VERSION 5.8 ;
BUSBITCHARS "[]" ;
DIVIDERCHAR "/" ;
UNITS
    DATABASE MICRONS 1000 ;
END UNITS

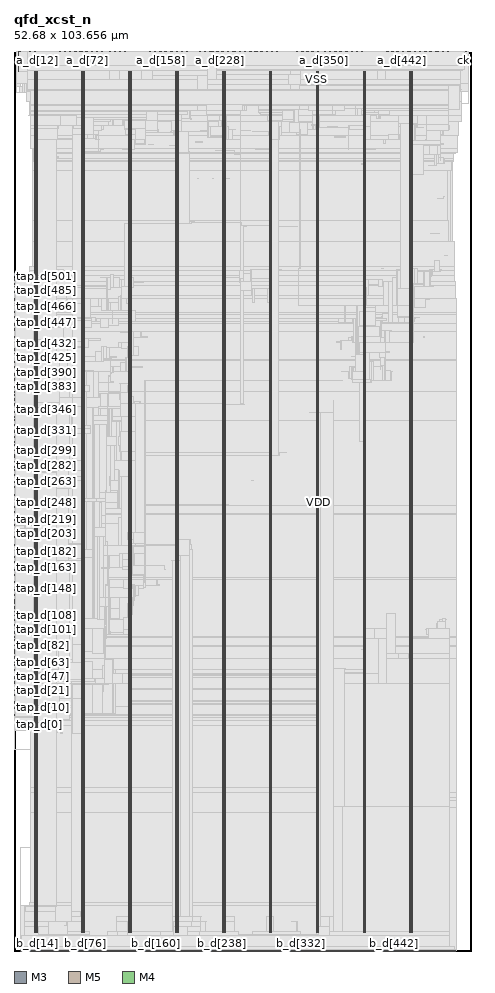
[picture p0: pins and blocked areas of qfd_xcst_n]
MACRO qfd_xcst_n
  FOREIGN qfd_xcst_n 0 0 ;
  CLASS BLOCK ;
  SIZE 52.68 BY 103.656 ;
  PIN a_d[0]
    DIRECTION OUTPUT ;
    USE SIGNAL ;
    PORT
      LAYER M3 ;
        RECT  1.44 103.618 1.458 103.656 ;
    END
  END a_d[0]
  PIN a_d[100]
    DIRECTION OUTPUT ;
    USE SIGNAL ;
    PORT
      LAYER M3 ;
        RECT  11.232 103.618 11.25 103.656 ;
    END
  END a_d[100]
  PIN a_d[101]
    DIRECTION OUTPUT ;
    USE SIGNAL ;
    PORT
      LAYER M5 ;
        RECT  11.328 103.572 11.352 103.656 ;
    END
  END a_d[101]
  PIN a_d[102]
    DIRECTION OUTPUT ;
    USE SIGNAL ;
    PORT
      LAYER M3 ;
        RECT  11.412 103.618 11.43 103.656 ;
    END
  END a_d[102]
  PIN a_d[103]
    DIRECTION OUTPUT ;
    USE SIGNAL ;
    PORT
      LAYER M5 ;
        RECT  11.52 103.572 11.544 103.656 ;
    END
  END a_d[103]
  PIN a_d[104]
    DIRECTION OUTPUT ;
    USE SIGNAL ;
    PORT
      LAYER M3 ;
        RECT  11.628 103.618 11.646 103.656 ;
    END
  END a_d[104]
  PIN a_d[105]
    DIRECTION OUTPUT ;
    USE SIGNAL ;
    PORT
      LAYER M5 ;
        RECT  11.712 103.572 11.736 103.656 ;
    END
  END a_d[105]
  PIN a_d[106]
    DIRECTION OUTPUT ;
    USE SIGNAL ;
    PORT
      LAYER M3 ;
        RECT  11.808 103.618 11.826 103.656 ;
    END
  END a_d[106]
  PIN a_d[107]
    DIRECTION OUTPUT ;
    USE SIGNAL ;
    PORT
      LAYER M5 ;
        RECT  11.904 103.572 11.928 103.656 ;
    END
  END a_d[107]
  PIN a_d[108]
    DIRECTION OUTPUT ;
    USE SIGNAL ;
    PORT
      LAYER M3 ;
        RECT  12.024 103.618 12.042 103.656 ;
    END
  END a_d[108]
  PIN a_d[109]
    DIRECTION OUTPUT ;
    USE SIGNAL ;
    PORT
      LAYER M5 ;
        RECT  12.096 103.572 12.12 103.656 ;
    END
  END a_d[109]
  PIN a_d[10]
    DIRECTION OUTPUT ;
    USE SIGNAL ;
    PORT
      LAYER M3 ;
        RECT  2.412 103.618 2.43 103.656 ;
    END
  END a_d[10]
  PIN a_d[110]
    DIRECTION OUTPUT ;
    USE SIGNAL ;
    PORT
      LAYER M3 ;
        RECT  12.204 103.618 12.222 103.656 ;
    END
  END a_d[110]
  PIN a_d[111]
    DIRECTION OUTPUT ;
    USE SIGNAL ;
    PORT
      LAYER M5 ;
        RECT  12.288 103.572 12.312 103.656 ;
    END
  END a_d[111]
  PIN a_d[112]
    DIRECTION OUTPUT ;
    USE SIGNAL ;
    PORT
      LAYER M3 ;
        RECT  12.42 103.618 12.438 103.656 ;
    END
  END a_d[112]
  PIN a_d[113]
    DIRECTION OUTPUT ;
    USE SIGNAL ;
    PORT
      LAYER M5 ;
        RECT  12.48 103.572 12.504 103.656 ;
    END
  END a_d[113]
  PIN a_d[114]
    DIRECTION OUTPUT ;
    USE SIGNAL ;
    PORT
      LAYER M3 ;
        RECT  12.6 103.618 12.618 103.656 ;
    END
  END a_d[114]
  PIN a_d[115]
    DIRECTION OUTPUT ;
    USE SIGNAL ;
    PORT
      LAYER M5 ;
        RECT  12.672 103.572 12.696 103.656 ;
    END
  END a_d[115]
  PIN a_d[116]
    DIRECTION OUTPUT ;
    USE SIGNAL ;
    PORT
      LAYER M3 ;
        RECT  12.78 103.618 12.798 103.656 ;
    END
  END a_d[116]
  PIN a_d[117]
    DIRECTION OUTPUT ;
    USE SIGNAL ;
    PORT
      LAYER M5 ;
        RECT  12.912 103.572 12.936 103.656 ;
    END
  END a_d[117]
  PIN a_d[118]
    DIRECTION OUTPUT ;
    USE SIGNAL ;
    PORT
      LAYER M3 ;
        RECT  12.996 103.618 13.014 103.656 ;
    END
  END a_d[118]
  PIN a_d[119]
    DIRECTION OUTPUT ;
    USE SIGNAL ;
    PORT
      LAYER M5 ;
        RECT  13.104 103.572 13.128 103.656 ;
    END
  END a_d[119]
  PIN a_d[11]
    DIRECTION OUTPUT ;
    USE SIGNAL ;
    PORT
      LAYER M5 ;
        RECT  2.496 103.572 2.52 103.656 ;
    END
  END a_d[11]
  PIN a_d[120]
    DIRECTION OUTPUT ;
    USE SIGNAL ;
    PORT
      LAYER M3 ;
        RECT  13.176 103.618 13.194 103.656 ;
    END
  END a_d[120]
  PIN a_d[121]
    DIRECTION OUTPUT ;
    USE SIGNAL ;
    PORT
      LAYER M5 ;
        RECT  13.296 103.572 13.32 103.656 ;
    END
  END a_d[121]
  PIN a_d[122]
    DIRECTION OUTPUT ;
    USE SIGNAL ;
    PORT
      LAYER M3 ;
        RECT  13.392 103.618 13.41 103.656 ;
    END
  END a_d[122]
  PIN a_d[123]
    DIRECTION OUTPUT ;
    USE SIGNAL ;
    PORT
      LAYER M5 ;
        RECT  13.488 103.572 13.512 103.656 ;
    END
  END a_d[123]
  PIN a_d[124]
    DIRECTION OUTPUT ;
    USE SIGNAL ;
    PORT
      LAYER M3 ;
        RECT  13.572 103.618 13.59 103.656 ;
    END
  END a_d[124]
  PIN a_d[125]
    DIRECTION OUTPUT ;
    USE SIGNAL ;
    PORT
      LAYER M5 ;
        RECT  13.68 103.572 13.704 103.656 ;
    END
  END a_d[125]
  PIN a_d[126]
    DIRECTION OUTPUT ;
    USE SIGNAL ;
    PORT
      LAYER M3 ;
        RECT  13.788 103.618 13.806 103.656 ;
    END
  END a_d[126]
  PIN a_d[127]
    DIRECTION OUTPUT ;
    USE SIGNAL ;
    PORT
      LAYER M5 ;
        RECT  13.872 103.572 13.896 103.656 ;
    END
  END a_d[127]
  PIN a_d[128]
    DIRECTION OUTPUT ;
    USE SIGNAL ;
    PORT
      LAYER M3 ;
        RECT  13.968 103.618 13.986 103.656 ;
    END
  END a_d[128]
  PIN a_d[129]
    DIRECTION OUTPUT ;
    USE SIGNAL ;
    PORT
      LAYER M5 ;
        RECT  14.064 103.572 14.088 103.656 ;
    END
  END a_d[129]
  PIN a_d[12]
    DIRECTION OUTPUT ;
    USE SIGNAL ;
    PORT
      LAYER M3 ;
        RECT  2.628 103.618 2.646 103.656 ;
    END
  END a_d[12]
  PIN a_d[130]
    DIRECTION OUTPUT ;
    USE SIGNAL ;
    PORT
      LAYER M3 ;
        RECT  14.184 103.618 14.202 103.656 ;
    END
  END a_d[130]
  PIN a_d[131]
    DIRECTION OUTPUT ;
    USE SIGNAL ;
    PORT
      LAYER M5 ;
        RECT  14.256 103.572 14.28 103.656 ;
    END
  END a_d[131]
  PIN a_d[132]
    DIRECTION OUTPUT ;
    USE SIGNAL ;
    PORT
      LAYER M3 ;
        RECT  14.364 103.618 14.382 103.656 ;
    END
  END a_d[132]
  PIN a_d[133]
    DIRECTION OUTPUT ;
    USE SIGNAL ;
    PORT
      LAYER M5 ;
        RECT  14.448 103.572 14.472 103.656 ;
    END
  END a_d[133]
  PIN a_d[134]
    DIRECTION OUTPUT ;
    USE SIGNAL ;
    PORT
      LAYER M3 ;
        RECT  14.544 103.618 14.562 103.656 ;
    END
  END a_d[134]
  PIN a_d[135]
    DIRECTION OUTPUT ;
    USE SIGNAL ;
    PORT
      LAYER M5 ;
        RECT  14.64 103.572 14.664 103.656 ;
    END
  END a_d[135]
  PIN a_d[136]
    DIRECTION OUTPUT ;
    USE SIGNAL ;
    PORT
      LAYER M3 ;
        RECT  14.76 103.618 14.778 103.656 ;
    END
  END a_d[136]
  PIN a_d[137]
    DIRECTION OUTPUT ;
    USE SIGNAL ;
    PORT
      LAYER M5 ;
        RECT  14.832 103.572 14.856 103.656 ;
    END
  END a_d[137]
  PIN a_d[138]
    DIRECTION OUTPUT ;
    USE SIGNAL ;
    PORT
      LAYER M3 ;
        RECT  14.94 103.618 14.958 103.656 ;
    END
  END a_d[138]
  PIN a_d[139]
    DIRECTION OUTPUT ;
    USE SIGNAL ;
    PORT
      LAYER M5 ;
        RECT  15.024 103.572 15.048 103.656 ;
    END
  END a_d[139]
  PIN a_d[13]
    DIRECTION OUTPUT ;
    USE SIGNAL ;
    PORT
      LAYER M5 ;
        RECT  2.736 103.572 2.76 103.656 ;
    END
  END a_d[13]
  PIN a_d[140]
    DIRECTION OUTPUT ;
    USE SIGNAL ;
    PORT
      LAYER M3 ;
        RECT  15.156 103.618 15.174 103.656 ;
    END
  END a_d[140]
  PIN a_d[141]
    DIRECTION OUTPUT ;
    USE SIGNAL ;
    PORT
      LAYER M5 ;
        RECT  15.216 103.572 15.24 103.656 ;
    END
  END a_d[141]
  PIN a_d[142]
    DIRECTION OUTPUT ;
    USE SIGNAL ;
    PORT
      LAYER M3 ;
        RECT  15.336 103.618 15.354 103.656 ;
    END
  END a_d[142]
  PIN a_d[143]
    DIRECTION OUTPUT ;
    USE SIGNAL ;
    PORT
      LAYER M5 ;
        RECT  15.456 103.572 15.48 103.656 ;
    END
  END a_d[143]
  PIN a_d[144]
    DIRECTION OUTPUT ;
    USE SIGNAL ;
    PORT
      LAYER M3 ;
        RECT  15.552 103.618 15.57 103.656 ;
    END
  END a_d[144]
  PIN a_d[145]
    DIRECTION OUTPUT ;
    USE SIGNAL ;
    PORT
      LAYER M5 ;
        RECT  15.648 103.572 15.672 103.656 ;
    END
  END a_d[145]
  PIN a_d[146]
    DIRECTION OUTPUT ;
    USE SIGNAL ;
    PORT
      LAYER M3 ;
        RECT  15.732 103.618 15.75 103.656 ;
    END
  END a_d[146]
  PIN a_d[147]
    DIRECTION OUTPUT ;
    USE SIGNAL ;
    PORT
      LAYER M5 ;
        RECT  15.84 103.572 15.864 103.656 ;
    END
  END a_d[147]
  PIN a_d[148]
    DIRECTION OUTPUT ;
    USE SIGNAL ;
    PORT
      LAYER M3 ;
        RECT  15.912 103.618 15.93 103.656 ;
    END
  END a_d[148]
  PIN a_d[149]
    DIRECTION OUTPUT ;
    USE SIGNAL ;
    PORT
      LAYER M5 ;
        RECT  16.032 103.572 16.056 103.656 ;
    END
  END a_d[149]
  PIN a_d[14]
    DIRECTION OUTPUT ;
    USE SIGNAL ;
    PORT
      LAYER M3 ;
        RECT  2.808 103.618 2.826 103.656 ;
    END
  END a_d[14]
  PIN a_d[150]
    DIRECTION OUTPUT ;
    USE SIGNAL ;
    PORT
      LAYER M3 ;
        RECT  16.128 103.618 16.146 103.656 ;
    END
  END a_d[150]
  PIN a_d[151]
    DIRECTION OUTPUT ;
    USE SIGNAL ;
    PORT
      LAYER M5 ;
        RECT  16.224 103.572 16.248 103.656 ;
    END
  END a_d[151]
  PIN a_d[152]
    DIRECTION OUTPUT ;
    USE SIGNAL ;
    PORT
      LAYER M3 ;
        RECT  16.308 103.618 16.326 103.656 ;
    END
  END a_d[152]
  PIN a_d[153]
    DIRECTION OUTPUT ;
    USE SIGNAL ;
    PORT
      LAYER M5 ;
        RECT  16.416 103.572 16.44 103.656 ;
    END
  END a_d[153]
  PIN a_d[154]
    DIRECTION OUTPUT ;
    USE SIGNAL ;
    PORT
      LAYER M3 ;
        RECT  16.524 103.618 16.542 103.656 ;
    END
  END a_d[154]
  PIN a_d[155]
    DIRECTION OUTPUT ;
    USE SIGNAL ;
    PORT
      LAYER M5 ;
        RECT  16.608 103.572 16.632 103.656 ;
    END
  END a_d[155]
  PIN a_d[156]
    DIRECTION OUTPUT ;
    USE SIGNAL ;
    PORT
      LAYER M3 ;
        RECT  16.704 103.618 16.722 103.656 ;
    END
  END a_d[156]
  PIN a_d[157]
    DIRECTION OUTPUT ;
    USE SIGNAL ;
    PORT
      LAYER M5 ;
        RECT  16.8 103.572 16.824 103.656 ;
    END
  END a_d[157]
  PIN a_d[158]
    DIRECTION OUTPUT ;
    USE SIGNAL ;
    PORT
      LAYER M3 ;
        RECT  16.92 103.618 16.938 103.656 ;
    END
  END a_d[158]
  PIN a_d[159]
    DIRECTION OUTPUT ;
    USE SIGNAL ;
    PORT
      LAYER M5 ;
        RECT  16.992 103.572 17.016 103.656 ;
    END
  END a_d[159]
  PIN a_d[15]
    DIRECTION OUTPUT ;
    USE SIGNAL ;
    PORT
      LAYER M5 ;
        RECT  2.928 103.572 2.952 103.656 ;
    END
  END a_d[15]
  PIN a_d[160]
    DIRECTION OUTPUT ;
    USE SIGNAL ;
    PORT
      LAYER M3 ;
        RECT  17.1 103.618 17.118 103.656 ;
    END
  END a_d[160]
  PIN a_d[161]
    DIRECTION OUTPUT ;
    USE SIGNAL ;
    PORT
      LAYER M5 ;
        RECT  17.184 103.572 17.208 103.656 ;
    END
  END a_d[161]
  PIN a_d[162]
    DIRECTION OUTPUT ;
    USE SIGNAL ;
    PORT
      LAYER M3 ;
        RECT  17.28 103.618 17.298 103.656 ;
    END
  END a_d[162]
  PIN a_d[163]
    DIRECTION OUTPUT ;
    USE SIGNAL ;
    PORT
      LAYER M5 ;
        RECT  17.376 103.572 17.4 103.656 ;
    END
  END a_d[163]
  PIN a_d[164]
    DIRECTION OUTPUT ;
    USE SIGNAL ;
    PORT
      LAYER M3 ;
        RECT  17.496 103.618 17.514 103.656 ;
    END
  END a_d[164]
  PIN a_d[165]
    DIRECTION OUTPUT ;
    USE SIGNAL ;
    PORT
      LAYER M5 ;
        RECT  17.568 103.572 17.592 103.656 ;
    END
  END a_d[165]
  PIN a_d[166]
    DIRECTION OUTPUT ;
    USE SIGNAL ;
    PORT
      LAYER M3 ;
        RECT  17.676 103.618 17.694 103.656 ;
    END
  END a_d[166]
  PIN a_d[167]
    DIRECTION OUTPUT ;
    USE SIGNAL ;
    PORT
      LAYER M5 ;
        RECT  17.808 103.572 17.832 103.656 ;
    END
  END a_d[167]
  PIN a_d[168]
    DIRECTION OUTPUT ;
    USE SIGNAL ;
    PORT
      LAYER M3 ;
        RECT  17.892 103.618 17.91 103.656 ;
    END
  END a_d[168]
  PIN a_d[169]
    DIRECTION OUTPUT ;
    USE SIGNAL ;
    PORT
      LAYER M5 ;
        RECT  18 103.572 18.024 103.656 ;
    END
  END a_d[169]
  PIN a_d[16]
    DIRECTION OUTPUT ;
    USE SIGNAL ;
    PORT
      LAYER M3 ;
        RECT  3.024 103.618 3.042 103.656 ;
    END
  END a_d[16]
  PIN a_d[170]
    DIRECTION OUTPUT ;
    USE SIGNAL ;
    PORT
      LAYER M3 ;
        RECT  18.072 103.618 18.09 103.656 ;
    END
  END a_d[170]
  PIN a_d[171]
    DIRECTION OUTPUT ;
    USE SIGNAL ;
    PORT
      LAYER M5 ;
        RECT  18.192 103.572 18.216 103.656 ;
    END
  END a_d[171]
  PIN a_d[172]
    DIRECTION OUTPUT ;
    USE SIGNAL ;
    PORT
      LAYER M3 ;
        RECT  18.288 103.618 18.306 103.656 ;
    END
  END a_d[172]
  PIN a_d[173]
    DIRECTION OUTPUT ;
    USE SIGNAL ;
    PORT
      LAYER M5 ;
        RECT  18.384 103.572 18.408 103.656 ;
    END
  END a_d[173]
  PIN a_d[174]
    DIRECTION OUTPUT ;
    USE SIGNAL ;
    PORT
      LAYER M3 ;
        RECT  18.468 103.618 18.486 103.656 ;
    END
  END a_d[174]
  PIN a_d[175]
    DIRECTION OUTPUT ;
    USE SIGNAL ;
    PORT
      LAYER M5 ;
        RECT  18.576 103.572 18.6 103.656 ;
    END
  END a_d[175]
  PIN a_d[176]
    DIRECTION OUTPUT ;
    USE SIGNAL ;
    PORT
      LAYER M3 ;
        RECT  18.684 103.618 18.702 103.656 ;
    END
  END a_d[176]
  PIN a_d[177]
    DIRECTION OUTPUT ;
    USE SIGNAL ;
    PORT
      LAYER M5 ;
        RECT  18.768 103.572 18.792 103.656 ;
    END
  END a_d[177]
  PIN a_d[178]
    DIRECTION OUTPUT ;
    USE SIGNAL ;
    PORT
      LAYER M3 ;
        RECT  18.864 103.618 18.882 103.656 ;
    END
  END a_d[178]
  PIN a_d[179]
    DIRECTION OUTPUT ;
    USE SIGNAL ;
    PORT
      LAYER M5 ;
        RECT  18.96 103.572 18.984 103.656 ;
    END
  END a_d[179]
  PIN a_d[17]
    DIRECTION OUTPUT ;
    USE SIGNAL ;
    PORT
      LAYER M5 ;
        RECT  3.12 103.572 3.144 103.656 ;
    END
  END a_d[17]
  PIN a_d[180]
    DIRECTION OUTPUT ;
    USE SIGNAL ;
    PORT
      LAYER M3 ;
        RECT  19.044 103.618 19.062 103.656 ;
    END
  END a_d[180]
  PIN a_d[181]
    DIRECTION OUTPUT ;
    USE SIGNAL ;
    PORT
      LAYER M5 ;
        RECT  19.152 103.572 19.176 103.656 ;
    END
  END a_d[181]
  PIN a_d[182]
    DIRECTION OUTPUT ;
    USE SIGNAL ;
    PORT
      LAYER M3 ;
        RECT  19.26 103.618 19.278 103.656 ;
    END
  END a_d[182]
  PIN a_d[183]
    DIRECTION OUTPUT ;
    USE SIGNAL ;
    PORT
      LAYER M5 ;
        RECT  19.344 103.572 19.368 103.656 ;
    END
  END a_d[183]
  PIN a_d[184]
    DIRECTION OUTPUT ;
    USE SIGNAL ;
    PORT
      LAYER M3 ;
        RECT  19.44 103.618 19.458 103.656 ;
    END
  END a_d[184]
  PIN a_d[185]
    DIRECTION OUTPUT ;
    USE SIGNAL ;
    PORT
      LAYER M5 ;
        RECT  19.536 103.572 19.56 103.656 ;
    END
  END a_d[185]
  PIN a_d[186]
    DIRECTION OUTPUT ;
    USE SIGNAL ;
    PORT
      LAYER M3 ;
        RECT  19.656 103.618 19.674 103.656 ;
    END
  END a_d[186]
  PIN a_d[187]
    DIRECTION OUTPUT ;
    USE SIGNAL ;
    PORT
      LAYER M5 ;
        RECT  19.728 103.572 19.752 103.656 ;
    END
  END a_d[187]
  PIN a_d[188]
    DIRECTION OUTPUT ;
    USE SIGNAL ;
    PORT
      LAYER M3 ;
        RECT  19.836 103.618 19.854 103.656 ;
    END
  END a_d[188]
  PIN a_d[189]
    DIRECTION OUTPUT ;
    USE SIGNAL ;
    PORT
      LAYER M5 ;
        RECT  19.92 103.572 19.944 103.656 ;
    END
  END a_d[189]
  PIN a_d[18]
    DIRECTION OUTPUT ;
    USE SIGNAL ;
    PORT
      LAYER M3 ;
        RECT  3.204 103.618 3.222 103.656 ;
    END
  END a_d[18]
  PIN a_d[190]
    DIRECTION OUTPUT ;
    USE SIGNAL ;
    PORT
      LAYER M3 ;
        RECT  20.052 103.618 20.07 103.656 ;
    END
  END a_d[190]
  PIN a_d[191]
    DIRECTION OUTPUT ;
    USE SIGNAL ;
    PORT
      LAYER M5 ;
        RECT  20.112 103.572 20.136 103.656 ;
    END
  END a_d[191]
  PIN a_d[192]
    DIRECTION OUTPUT ;
    USE SIGNAL ;
    PORT
      LAYER M3 ;
        RECT  20.232 103.618 20.25 103.656 ;
    END
  END a_d[192]
  PIN a_d[193]
    DIRECTION OUTPUT ;
    USE SIGNAL ;
    PORT
      LAYER M5 ;
        RECT  20.352 103.572 20.376 103.656 ;
    END
  END a_d[193]
  PIN a_d[194]
    DIRECTION OUTPUT ;
    USE SIGNAL ;
    PORT
      LAYER M3 ;
        RECT  20.412 103.618 20.43 103.656 ;
    END
  END a_d[194]
  PIN a_d[195]
    DIRECTION OUTPUT ;
    USE SIGNAL ;
    PORT
      LAYER M5 ;
        RECT  20.544 103.572 20.568 103.656 ;
    END
  END a_d[195]
  PIN a_d[196]
    DIRECTION OUTPUT ;
    USE SIGNAL ;
    PORT
      LAYER M3 ;
        RECT  20.628 103.618 20.646 103.656 ;
    END
  END a_d[196]
  PIN a_d[197]
    DIRECTION OUTPUT ;
    USE SIGNAL ;
    PORT
      LAYER M5 ;
        RECT  20.736 103.572 20.76 103.656 ;
    END
  END a_d[197]
  PIN a_d[198]
    DIRECTION OUTPUT ;
    USE SIGNAL ;
    PORT
      LAYER M3 ;
        RECT  20.808 103.618 20.826 103.656 ;
    END
  END a_d[198]
  PIN a_d[199]
    DIRECTION OUTPUT ;
    USE SIGNAL ;
    PORT
      LAYER M5 ;
        RECT  20.928 103.572 20.952 103.656 ;
    END
  END a_d[199]
  PIN a_d[19]
    DIRECTION OUTPUT ;
    USE SIGNAL ;
    PORT
      LAYER M5 ;
        RECT  3.312 103.572 3.336 103.656 ;
    END
  END a_d[19]
  PIN a_d[1]
    DIRECTION OUTPUT ;
    USE SIGNAL ;
    PORT
      LAYER M5 ;
        RECT  1.536 103.572 1.56 103.656 ;
    END
  END a_d[1]
  PIN a_d[200]
    DIRECTION OUTPUT ;
    USE SIGNAL ;
    PORT
      LAYER M3 ;
        RECT  21.024 103.618 21.042 103.656 ;
    END
  END a_d[200]
  PIN a_d[201]
    DIRECTION OUTPUT ;
    USE SIGNAL ;
    PORT
      LAYER M5 ;
        RECT  21.12 103.572 21.144 103.656 ;
    END
  END a_d[201]
  PIN a_d[202]
    DIRECTION OUTPUT ;
    USE SIGNAL ;
    PORT
      LAYER M3 ;
        RECT  21.204 103.618 21.222 103.656 ;
    END
  END a_d[202]
  PIN a_d[203]
    DIRECTION OUTPUT ;
    USE SIGNAL ;
    PORT
      LAYER M5 ;
        RECT  21.312 103.572 21.336 103.656 ;
    END
  END a_d[203]
  PIN a_d[204]
    DIRECTION OUTPUT ;
    USE SIGNAL ;
    PORT
      LAYER M3 ;
        RECT  21.42 103.618 21.438 103.656 ;
    END
  END a_d[204]
  PIN a_d[205]
    DIRECTION OUTPUT ;
    USE SIGNAL ;
    PORT
      LAYER M5 ;
        RECT  21.504 103.572 21.528 103.656 ;
    END
  END a_d[205]
  PIN a_d[206]
    DIRECTION OUTPUT ;
    USE SIGNAL ;
    PORT
      LAYER M3 ;
        RECT  21.6 103.618 21.618 103.656 ;
    END
  END a_d[206]
  PIN a_d[207]
    DIRECTION OUTPUT ;
    USE SIGNAL ;
    PORT
      LAYER M5 ;
        RECT  21.696 103.572 21.72 103.656 ;
    END
  END a_d[207]
  PIN a_d[208]
    DIRECTION OUTPUT ;
    USE SIGNAL ;
    PORT
      LAYER M3 ;
        RECT  21.816 103.618 21.834 103.656 ;
    END
  END a_d[208]
  PIN a_d[209]
    DIRECTION OUTPUT ;
    USE SIGNAL ;
    PORT
      LAYER M5 ;
        RECT  21.888 103.572 21.912 103.656 ;
    END
  END a_d[209]
  PIN a_d[20]
    DIRECTION OUTPUT ;
    USE SIGNAL ;
    PORT
      LAYER M3 ;
        RECT  3.384 103.618 3.402 103.656 ;
    END
  END a_d[20]
  PIN a_d[210]
    DIRECTION OUTPUT ;
    USE SIGNAL ;
    PORT
      LAYER M3 ;
        RECT  21.996 103.618 22.014 103.656 ;
    END
  END a_d[210]
  PIN a_d[211]
    DIRECTION OUTPUT ;
    USE SIGNAL ;
    PORT
      LAYER M5 ;
        RECT  22.08 103.572 22.104 103.656 ;
    END
  END a_d[211]
  PIN a_d[212]
    DIRECTION OUTPUT ;
    USE SIGNAL ;
    PORT
      LAYER M3 ;
        RECT  22.176 103.618 22.194 103.656 ;
    END
  END a_d[212]
  PIN a_d[213]
    DIRECTION OUTPUT ;
    USE SIGNAL ;
    PORT
      LAYER M5 ;
        RECT  22.272 103.572 22.296 103.656 ;
    END
  END a_d[213]
  PIN a_d[214]
    DIRECTION OUTPUT ;
    USE SIGNAL ;
    PORT
      LAYER M3 ;
        RECT  22.392 103.618 22.41 103.656 ;
    END
  END a_d[214]
  PIN a_d[215]
    DIRECTION OUTPUT ;
    USE SIGNAL ;
    PORT
      LAYER M5 ;
        RECT  22.464 103.572 22.488 103.656 ;
    END
  END a_d[215]
  PIN a_d[216]
    DIRECTION OUTPUT ;
    USE SIGNAL ;
    PORT
      LAYER M3 ;
        RECT  22.572 103.618 22.59 103.656 ;
    END
  END a_d[216]
  PIN a_d[217]
    DIRECTION OUTPUT ;
    USE SIGNAL ;
    PORT
      LAYER M5 ;
        RECT  22.656 103.572 22.68 103.656 ;
    END
  END a_d[217]
  PIN a_d[218]
    DIRECTION OUTPUT ;
    USE SIGNAL ;
    PORT
      LAYER M3 ;
        RECT  22.788 103.618 22.806 103.656 ;
    END
  END a_d[218]
  PIN a_d[219]
    DIRECTION OUTPUT ;
    USE SIGNAL ;
    PORT
      LAYER M5 ;
        RECT  22.896 103.572 22.92 103.656 ;
    END
  END a_d[219]
  PIN a_d[21]
    DIRECTION OUTPUT ;
    USE SIGNAL ;
    PORT
      LAYER M5 ;
        RECT  3.504 103.572 3.528 103.656 ;
    END
  END a_d[21]
  PIN a_d[220]
    DIRECTION OUTPUT ;
    USE SIGNAL ;
    PORT
      LAYER M3 ;
        RECT  22.968 103.618 22.986 103.656 ;
    END
  END a_d[220]
  PIN a_d[221]
    DIRECTION OUTPUT ;
    USE SIGNAL ;
    PORT
      LAYER M5 ;
        RECT  23.088 103.572 23.112 103.656 ;
    END
  END a_d[221]
  PIN a_d[222]
    DIRECTION OUTPUT ;
    USE SIGNAL ;
    PORT
      LAYER M3 ;
        RECT  23.184 103.618 23.202 103.656 ;
    END
  END a_d[222]
  PIN a_d[223]
    DIRECTION OUTPUT ;
    USE SIGNAL ;
    PORT
      LAYER M5 ;
        RECT  23.28 103.572 23.304 103.656 ;
    END
  END a_d[223]
  PIN a_d[224]
    DIRECTION OUTPUT ;
    USE SIGNAL ;
    PORT
      LAYER M3 ;
        RECT  23.364 103.618 23.382 103.656 ;
    END
  END a_d[224]
  PIN a_d[225]
    DIRECTION OUTPUT ;
    USE SIGNAL ;
    PORT
      LAYER M5 ;
        RECT  23.472 103.572 23.496 103.656 ;
    END
  END a_d[225]
  PIN a_d[226]
    DIRECTION OUTPUT ;
    USE SIGNAL ;
    PORT
      LAYER M3 ;
        RECT  23.544 103.618 23.562 103.656 ;
    END
  END a_d[226]
  PIN a_d[227]
    DIRECTION OUTPUT ;
    USE SIGNAL ;
    PORT
      LAYER M5 ;
        RECT  23.664 103.572 23.688 103.656 ;
    END
  END a_d[227]
  PIN a_d[228]
    DIRECTION OUTPUT ;
    USE SIGNAL ;
    PORT
      LAYER M3 ;
        RECT  23.76 103.618 23.778 103.656 ;
    END
  END a_d[228]
  PIN a_d[229]
    DIRECTION OUTPUT ;
    USE SIGNAL ;
    PORT
      LAYER M5 ;
        RECT  23.856 103.572 23.88 103.656 ;
    END
  END a_d[229]
  PIN a_d[22]
    DIRECTION OUTPUT ;
    USE SIGNAL ;
    PORT
      LAYER M3 ;
        RECT  3.6 103.618 3.618 103.656 ;
    END
  END a_d[22]
  PIN a_d[230]
    DIRECTION OUTPUT ;
    USE SIGNAL ;
    PORT
      LAYER M3 ;
        RECT  23.94 103.618 23.958 103.656 ;
    END
  END a_d[230]
  PIN a_d[231]
    DIRECTION OUTPUT ;
    USE SIGNAL ;
    PORT
      LAYER M5 ;
        RECT  24.048 103.572 24.072 103.656 ;
    END
  END a_d[231]
  PIN a_d[232]
    DIRECTION OUTPUT ;
    USE SIGNAL ;
    PORT
      LAYER M3 ;
        RECT  24.156 103.618 24.174 103.656 ;
    END
  END a_d[232]
  PIN a_d[233]
    DIRECTION OUTPUT ;
    USE SIGNAL ;
    PORT
      LAYER M5 ;
        RECT  24.24 103.572 24.264 103.656 ;
    END
  END a_d[233]
  PIN a_d[234]
    DIRECTION OUTPUT ;
    USE SIGNAL ;
    PORT
      LAYER M3 ;
        RECT  24.336 103.618 24.354 103.656 ;
    END
  END a_d[234]
  PIN a_d[235]
    DIRECTION OUTPUT ;
    USE SIGNAL ;
    PORT
      LAYER M5 ;
        RECT  24.432 103.572 24.456 103.656 ;
    END
  END a_d[235]
  PIN a_d[236]
    DIRECTION OUTPUT ;
    USE SIGNAL ;
    PORT
      LAYER M3 ;
        RECT  24.552 103.618 24.57 103.656 ;
    END
  END a_d[236]
  PIN a_d[237]
    DIRECTION OUTPUT ;
    USE SIGNAL ;
    PORT
      LAYER M5 ;
        RECT  24.624 103.572 24.648 103.656 ;
    END
  END a_d[237]
  PIN a_d[238]
    DIRECTION OUTPUT ;
    USE SIGNAL ;
    PORT
      LAYER M3 ;
        RECT  24.732 103.618 24.75 103.656 ;
    END
  END a_d[238]
  PIN a_d[239]
    DIRECTION OUTPUT ;
    USE SIGNAL ;
    PORT
      LAYER M5 ;
        RECT  24.816 103.572 24.84 103.656 ;
    END
  END a_d[239]
  PIN a_d[23]
    DIRECTION OUTPUT ;
    USE SIGNAL ;
    PORT
      LAYER M5 ;
        RECT  3.696 103.572 3.72 103.656 ;
    END
  END a_d[23]
  PIN a_d[240]
    DIRECTION OUTPUT ;
    USE SIGNAL ;
    PORT
      LAYER M3 ;
        RECT  24.948 103.618 24.966 103.656 ;
    END
  END a_d[240]
  PIN a_d[241]
    DIRECTION OUTPUT ;
    USE SIGNAL ;
    PORT
      LAYER M5 ;
        RECT  25.008 103.572 25.032 103.656 ;
    END
  END a_d[241]
  PIN a_d[242]
    DIRECTION OUTPUT ;
    USE SIGNAL ;
    PORT
      LAYER M3 ;
        RECT  25.128 103.618 25.146 103.656 ;
    END
  END a_d[242]
  PIN a_d[243]
    DIRECTION OUTPUT ;
    USE SIGNAL ;
    PORT
      LAYER M5 ;
        RECT  25.2 103.572 25.224 103.656 ;
    END
  END a_d[243]
  PIN a_d[244]
    DIRECTION OUTPUT ;
    USE SIGNAL ;
    PORT
      LAYER M3 ;
        RECT  25.308 103.618 25.326 103.656 ;
    END
  END a_d[244]
  PIN a_d[245]
    DIRECTION OUTPUT ;
    USE SIGNAL ;
    PORT
      LAYER M5 ;
        RECT  25.44 103.572 25.464 103.656 ;
    END
  END a_d[245]
  PIN a_d[246]
    DIRECTION OUTPUT ;
    USE SIGNAL ;
    PORT
      LAYER M3 ;
        RECT  25.524 103.618 25.542 103.656 ;
    END
  END a_d[246]
  PIN a_d[247]
    DIRECTION OUTPUT ;
    USE SIGNAL ;
    PORT
      LAYER M5 ;
        RECT  25.632 103.572 25.656 103.656 ;
    END
  END a_d[247]
  PIN a_d[248]
    DIRECTION OUTPUT ;
    USE SIGNAL ;
    PORT
      LAYER M3 ;
        RECT  25.704 103.618 25.722 103.656 ;
    END
  END a_d[248]
  PIN a_d[249]
    DIRECTION OUTPUT ;
    USE SIGNAL ;
    PORT
      LAYER M5 ;
        RECT  25.824 103.572 25.848 103.656 ;
    END
  END a_d[249]
  PIN a_d[24]
    DIRECTION OUTPUT ;
    USE SIGNAL ;
    PORT
      LAYER M3 ;
        RECT  3.78 103.618 3.798 103.656 ;
    END
  END a_d[24]
  PIN a_d[250]
    DIRECTION OUTPUT ;
    USE SIGNAL ;
    PORT
      LAYER M3 ;
        RECT  25.92 103.618 25.938 103.656 ;
    END
  END a_d[250]
  PIN a_d[251]
    DIRECTION OUTPUT ;
    USE SIGNAL ;
    PORT
      LAYER M5 ;
        RECT  26.016 103.572 26.04 103.656 ;
    END
  END a_d[251]
  PIN a_d[252]
    DIRECTION OUTPUT ;
    USE SIGNAL ;
    PORT
      LAYER M3 ;
        RECT  26.1 103.618 26.118 103.656 ;
    END
  END a_d[252]
  PIN a_d[253]
    DIRECTION OUTPUT ;
    USE SIGNAL ;
    PORT
      LAYER M5 ;
        RECT  26.208 103.572 26.232 103.656 ;
    END
  END a_d[253]
  PIN a_d[254]
    DIRECTION OUTPUT ;
    USE SIGNAL ;
    PORT
      LAYER M3 ;
        RECT  26.316 103.618 26.334 103.656 ;
    END
  END a_d[254]
  PIN a_d[255]
    DIRECTION OUTPUT ;
    USE SIGNAL ;
    PORT
      LAYER M5 ;
        RECT  26.4 103.572 26.424 103.656 ;
    END
  END a_d[255]
  PIN a_d[256]
    DIRECTION OUTPUT ;
    USE SIGNAL ;
    PORT
      LAYER M3 ;
        RECT  26.496 103.618 26.514 103.656 ;
    END
  END a_d[256]
  PIN a_d[257]
    DIRECTION OUTPUT ;
    USE SIGNAL ;
    PORT
      LAYER M5 ;
        RECT  26.592 103.572 26.616 103.656 ;
    END
  END a_d[257]
  PIN a_d[258]
    DIRECTION OUTPUT ;
    USE SIGNAL ;
    PORT
      LAYER M3 ;
        RECT  26.676 103.618 26.694 103.656 ;
    END
  END a_d[258]
  PIN a_d[259]
    DIRECTION OUTPUT ;
    USE SIGNAL ;
    PORT
      LAYER M5 ;
        RECT  26.784 103.572 26.808 103.656 ;
    END
  END a_d[259]
  PIN a_d[25]
    DIRECTION OUTPUT ;
    USE SIGNAL ;
    PORT
      LAYER M5 ;
        RECT  3.888 103.572 3.912 103.656 ;
    END
  END a_d[25]
  PIN a_d[260]
    DIRECTION OUTPUT ;
    USE SIGNAL ;
    PORT
      LAYER M3 ;
        RECT  26.892 103.618 26.91 103.656 ;
    END
  END a_d[260]
  PIN a_d[261]
    DIRECTION OUTPUT ;
    USE SIGNAL ;
    PORT
      LAYER M5 ;
        RECT  26.976 103.572 27 103.656 ;
    END
  END a_d[261]
  PIN a_d[262]
    DIRECTION OUTPUT ;
    USE SIGNAL ;
    PORT
      LAYER M3 ;
        RECT  27.072 103.618 27.09 103.656 ;
    END
  END a_d[262]
  PIN a_d[263]
    DIRECTION OUTPUT ;
    USE SIGNAL ;
    PORT
      LAYER M5 ;
        RECT  27.168 103.572 27.192 103.656 ;
    END
  END a_d[263]
  PIN a_d[264]
    DIRECTION OUTPUT ;
    USE SIGNAL ;
    PORT
      LAYER M3 ;
        RECT  27.288 103.618 27.306 103.656 ;
    END
  END a_d[264]
  PIN a_d[265]
    DIRECTION OUTPUT ;
    USE SIGNAL ;
    PORT
      LAYER M5 ;
        RECT  27.36 103.572 27.384 103.656 ;
    END
  END a_d[265]
  PIN a_d[266]
    DIRECTION OUTPUT ;
    USE SIGNAL ;
    PORT
      LAYER M3 ;
        RECT  27.468 103.618 27.486 103.656 ;
    END
  END a_d[266]
  PIN a_d[267]
    DIRECTION OUTPUT ;
    USE SIGNAL ;
    PORT
      LAYER M5 ;
        RECT  27.552 103.572 27.576 103.656 ;
    END
  END a_d[267]
  PIN a_d[268]
    DIRECTION OUTPUT ;
    USE SIGNAL ;
    PORT
      LAYER M3 ;
        RECT  27.684 103.618 27.702 103.656 ;
    END
  END a_d[268]
  PIN a_d[269]
    DIRECTION OUTPUT ;
    USE SIGNAL ;
    PORT
      LAYER M5 ;
        RECT  27.744 103.572 27.768 103.656 ;
    END
  END a_d[269]
  PIN a_d[26]
    DIRECTION OUTPUT ;
    USE SIGNAL ;
    PORT
      LAYER M3 ;
        RECT  3.996 103.618 4.014 103.656 ;
    END
  END a_d[26]
  PIN a_d[270]
    DIRECTION OUTPUT ;
    USE SIGNAL ;
    PORT
      LAYER M3 ;
        RECT  27.864 103.618 27.882 103.656 ;
    END
  END a_d[270]
  PIN a_d[271]
    DIRECTION OUTPUT ;
    USE SIGNAL ;
    PORT
      LAYER M5 ;
        RECT  27.984 103.572 28.008 103.656 ;
    END
  END a_d[271]
  PIN a_d[272]
    DIRECTION OUTPUT ;
    USE SIGNAL ;
    PORT
      LAYER M3 ;
        RECT  28.08 103.618 28.098 103.656 ;
    END
  END a_d[272]
  PIN a_d[273]
    DIRECTION OUTPUT ;
    USE SIGNAL ;
    PORT
      LAYER M5 ;
        RECT  28.176 103.572 28.2 103.656 ;
    END
  END a_d[273]
  PIN a_d[274]
    DIRECTION OUTPUT ;
    USE SIGNAL ;
    PORT
      LAYER M3 ;
        RECT  28.26 103.618 28.278 103.656 ;
    END
  END a_d[274]
  PIN a_d[275]
    DIRECTION OUTPUT ;
    USE SIGNAL ;
    PORT
      LAYER M5 ;
        RECT  28.368 103.572 28.392 103.656 ;
    END
  END a_d[275]
  PIN a_d[276]
    DIRECTION OUTPUT ;
    USE SIGNAL ;
    PORT
      LAYER M3 ;
        RECT  28.44 103.618 28.458 103.656 ;
    END
  END a_d[276]
  PIN a_d[277]
    DIRECTION OUTPUT ;
    USE SIGNAL ;
    PORT
      LAYER M5 ;
        RECT  28.56 103.572 28.584 103.656 ;
    END
  END a_d[277]
  PIN a_d[278]
    DIRECTION OUTPUT ;
    USE SIGNAL ;
    PORT
      LAYER M3 ;
        RECT  28.656 103.618 28.674 103.656 ;
    END
  END a_d[278]
  PIN a_d[279]
    DIRECTION OUTPUT ;
    USE SIGNAL ;
    PORT
      LAYER M5 ;
        RECT  28.752 103.572 28.776 103.656 ;
    END
  END a_d[279]
  PIN a_d[27]
    DIRECTION OUTPUT ;
    USE SIGNAL ;
    PORT
      LAYER M5 ;
        RECT  4.08 103.572 4.104 103.656 ;
    END
  END a_d[27]
  PIN a_d[280]
    DIRECTION OUTPUT ;
    USE SIGNAL ;
    PORT
      LAYER M3 ;
        RECT  28.836 103.618 28.854 103.656 ;
    END
  END a_d[280]
  PIN a_d[281]
    DIRECTION OUTPUT ;
    USE SIGNAL ;
    PORT
      LAYER M5 ;
        RECT  28.944 103.572 28.968 103.656 ;
    END
  END a_d[281]
  PIN a_d[282]
    DIRECTION OUTPUT ;
    USE SIGNAL ;
    PORT
      LAYER M3 ;
        RECT  29.052 103.618 29.07 103.656 ;
    END
  END a_d[282]
  PIN a_d[283]
    DIRECTION OUTPUT ;
    USE SIGNAL ;
    PORT
      LAYER M5 ;
        RECT  29.136 103.572 29.16 103.656 ;
    END
  END a_d[283]
  PIN a_d[284]
    DIRECTION OUTPUT ;
    USE SIGNAL ;
    PORT
      LAYER M3 ;
        RECT  29.232 103.618 29.25 103.656 ;
    END
  END a_d[284]
  PIN a_d[285]
    DIRECTION OUTPUT ;
    USE SIGNAL ;
    PORT
      LAYER M5 ;
        RECT  29.328 103.572 29.352 103.656 ;
    END
  END a_d[285]
  PIN a_d[286]
    DIRECTION OUTPUT ;
    USE SIGNAL ;
    PORT
      LAYER M3 ;
        RECT  29.448 103.618 29.466 103.656 ;
    END
  END a_d[286]
  PIN a_d[287]
    DIRECTION OUTPUT ;
    USE SIGNAL ;
    PORT
      LAYER M5 ;
        RECT  29.52 103.572 29.544 103.656 ;
    END
  END a_d[287]
  PIN a_d[288]
    DIRECTION OUTPUT ;
    USE SIGNAL ;
    PORT
      LAYER M3 ;
        RECT  29.628 103.618 29.646 103.656 ;
    END
  END a_d[288]
  PIN a_d[289]
    DIRECTION OUTPUT ;
    USE SIGNAL ;
    PORT
      LAYER M5 ;
        RECT  29.712 103.572 29.736 103.656 ;
    END
  END a_d[289]
  PIN a_d[28]
    DIRECTION OUTPUT ;
    USE SIGNAL ;
    PORT
      LAYER M3 ;
        RECT  4.176 103.618 4.194 103.656 ;
    END
  END a_d[28]
  PIN a_d[290]
    DIRECTION OUTPUT ;
    USE SIGNAL ;
    PORT
      LAYER M3 ;
        RECT  29.808 103.618 29.826 103.656 ;
    END
  END a_d[290]
  PIN a_d[291]
    DIRECTION OUTPUT ;
    USE SIGNAL ;
    PORT
      LAYER M5 ;
        RECT  29.904 103.572 29.928 103.656 ;
    END
  END a_d[291]
  PIN a_d[292]
    DIRECTION OUTPUT ;
    USE SIGNAL ;
    PORT
      LAYER M3 ;
        RECT  30.024 103.618 30.042 103.656 ;
    END
  END a_d[292]
  PIN a_d[293]
    DIRECTION OUTPUT ;
    USE SIGNAL ;
    PORT
      LAYER M5 ;
        RECT  30.096 103.572 30.12 103.656 ;
    END
  END a_d[293]
  PIN a_d[294]
    DIRECTION OUTPUT ;
    USE SIGNAL ;
    PORT
      LAYER M3 ;
        RECT  30.204 103.618 30.222 103.656 ;
    END
  END a_d[294]
  PIN a_d[295]
    DIRECTION OUTPUT ;
    USE SIGNAL ;
    PORT
      LAYER M5 ;
        RECT  30.288 103.572 30.312 103.656 ;
    END
  END a_d[295]
  PIN a_d[296]
    DIRECTION OUTPUT ;
    USE SIGNAL ;
    PORT
      LAYER M3 ;
        RECT  30.42 103.618 30.438 103.656 ;
    END
  END a_d[296]
  PIN a_d[297]
    DIRECTION OUTPUT ;
    USE SIGNAL ;
    PORT
      LAYER M5 ;
        RECT  30.528 103.572 30.552 103.656 ;
    END
  END a_d[297]
  PIN a_d[298]
    DIRECTION OUTPUT ;
    USE SIGNAL ;
    PORT
      LAYER M3 ;
        RECT  30.6 103.618 30.618 103.656 ;
    END
  END a_d[298]
  PIN a_d[299]
    DIRECTION OUTPUT ;
    USE SIGNAL ;
    PORT
      LAYER M5 ;
        RECT  30.72 103.572 30.744 103.656 ;
    END
  END a_d[299]
  PIN a_d[29]
    DIRECTION OUTPUT ;
    USE SIGNAL ;
    PORT
      LAYER M5 ;
        RECT  4.272 103.572 4.296 103.656 ;
    END
  END a_d[29]
  PIN a_d[2]
    DIRECTION OUTPUT ;
    USE SIGNAL ;
    PORT
      LAYER M3 ;
        RECT  1.656 103.618 1.674 103.656 ;
    END
  END a_d[2]
  PIN a_d[300]
    DIRECTION OUTPUT ;
    USE SIGNAL ;
    PORT
      LAYER M3 ;
        RECT  30.816 103.618 30.834 103.656 ;
    END
  END a_d[300]
  PIN a_d[301]
    DIRECTION OUTPUT ;
    USE SIGNAL ;
    PORT
      LAYER M5 ;
        RECT  30.912 103.572 30.936 103.656 ;
    END
  END a_d[301]
  PIN a_d[302]
    DIRECTION OUTPUT ;
    USE SIGNAL ;
    PORT
      LAYER M3 ;
        RECT  30.996 103.618 31.014 103.656 ;
    END
  END a_d[302]
  PIN a_d[303]
    DIRECTION OUTPUT ;
    USE SIGNAL ;
    PORT
      LAYER M5 ;
        RECT  31.104 103.572 31.128 103.656 ;
    END
  END a_d[303]
  PIN a_d[304]
    DIRECTION OUTPUT ;
    USE SIGNAL ;
    PORT
      LAYER M3 ;
        RECT  31.212 103.618 31.23 103.656 ;
    END
  END a_d[304]
  PIN a_d[305]
    DIRECTION OUTPUT ;
    USE SIGNAL ;
    PORT
      LAYER M5 ;
        RECT  31.296 103.572 31.32 103.656 ;
    END
  END a_d[305]
  PIN a_d[306]
    DIRECTION OUTPUT ;
    USE SIGNAL ;
    PORT
      LAYER M3 ;
        RECT  31.392 103.618 31.41 103.656 ;
    END
  END a_d[306]
  PIN a_d[307]
    DIRECTION OUTPUT ;
    USE SIGNAL ;
    PORT
      LAYER M5 ;
        RECT  31.488 103.572 31.512 103.656 ;
    END
  END a_d[307]
  PIN a_d[308]
    DIRECTION OUTPUT ;
    USE SIGNAL ;
    PORT
      LAYER M3 ;
        RECT  31.572 103.618 31.59 103.656 ;
    END
  END a_d[308]
  PIN a_d[309]
    DIRECTION OUTPUT ;
    USE SIGNAL ;
    PORT
      LAYER M5 ;
        RECT  31.68 103.572 31.704 103.656 ;
    END
  END a_d[309]
  PIN a_d[30]
    DIRECTION OUTPUT ;
    USE SIGNAL ;
    PORT
      LAYER M3 ;
        RECT  4.392 103.618 4.41 103.656 ;
    END
  END a_d[30]
  PIN a_d[310]
    DIRECTION OUTPUT ;
    USE SIGNAL ;
    PORT
      LAYER M3 ;
        RECT  31.788 103.618 31.806 103.656 ;
    END
  END a_d[310]
  PIN a_d[311]
    DIRECTION OUTPUT ;
    USE SIGNAL ;
    PORT
      LAYER M5 ;
        RECT  31.872 103.572 31.896 103.656 ;
    END
  END a_d[311]
  PIN a_d[312]
    DIRECTION OUTPUT ;
    USE SIGNAL ;
    PORT
      LAYER M3 ;
        RECT  31.968 103.618 31.986 103.656 ;
    END
  END a_d[312]
  PIN a_d[313]
    DIRECTION OUTPUT ;
    USE SIGNAL ;
    PORT
      LAYER M5 ;
        RECT  32.064 103.572 32.088 103.656 ;
    END
  END a_d[313]
  PIN a_d[314]
    DIRECTION OUTPUT ;
    USE SIGNAL ;
    PORT
      LAYER M3 ;
        RECT  32.184 103.618 32.202 103.656 ;
    END
  END a_d[314]
  PIN a_d[315]
    DIRECTION OUTPUT ;
    USE SIGNAL ;
    PORT
      LAYER M5 ;
        RECT  32.256 103.572 32.28 103.656 ;
    END
  END a_d[315]
  PIN a_d[316]
    DIRECTION OUTPUT ;
    USE SIGNAL ;
    PORT
      LAYER M3 ;
        RECT  32.364 103.618 32.382 103.656 ;
    END
  END a_d[316]
  PIN a_d[317]
    DIRECTION OUTPUT ;
    USE SIGNAL ;
    PORT
      LAYER M5 ;
        RECT  32.448 103.572 32.472 103.656 ;
    END
  END a_d[317]
  PIN a_d[318]
    DIRECTION OUTPUT ;
    USE SIGNAL ;
    PORT
      LAYER M3 ;
        RECT  32.58 103.618 32.598 103.656 ;
    END
  END a_d[318]
  PIN a_d[319]
    DIRECTION OUTPUT ;
    USE SIGNAL ;
    PORT
      LAYER M5 ;
        RECT  32.64 103.572 32.664 103.656 ;
    END
  END a_d[319]
  PIN a_d[31]
    DIRECTION OUTPUT ;
    USE SIGNAL ;
    PORT
      LAYER M5 ;
        RECT  4.464 103.572 4.488 103.656 ;
    END
  END a_d[31]
  PIN a_d[320]
    DIRECTION OUTPUT ;
    USE SIGNAL ;
    PORT
      LAYER M3 ;
        RECT  32.76 103.618 32.778 103.656 ;
    END
  END a_d[320]
  PIN a_d[321]
    DIRECTION OUTPUT ;
    USE SIGNAL ;
    PORT
      LAYER M5 ;
        RECT  32.832 103.572 32.856 103.656 ;
    END
  END a_d[321]
  PIN a_d[322]
    DIRECTION OUTPUT ;
    USE SIGNAL ;
    PORT
      LAYER M3 ;
        RECT  32.94 103.618 32.958 103.656 ;
    END
  END a_d[322]
  PIN a_d[323]
    DIRECTION OUTPUT ;
    USE SIGNAL ;
    PORT
      LAYER M5 ;
        RECT  33.072 103.572 33.096 103.656 ;
    END
  END a_d[323]
  PIN a_d[324]
    DIRECTION OUTPUT ;
    USE SIGNAL ;
    PORT
      LAYER M3 ;
        RECT  33.156 103.618 33.174 103.656 ;
    END
  END a_d[324]
  PIN a_d[325]
    DIRECTION OUTPUT ;
    USE SIGNAL ;
    PORT
      LAYER M5 ;
        RECT  33.264 103.572 33.288 103.656 ;
    END
  END a_d[325]
  PIN a_d[326]
    DIRECTION OUTPUT ;
    USE SIGNAL ;
    PORT
      LAYER M3 ;
        RECT  33.336 103.618 33.354 103.656 ;
    END
  END a_d[326]
  PIN a_d[327]
    DIRECTION OUTPUT ;
    USE SIGNAL ;
    PORT
      LAYER M5 ;
        RECT  33.456 103.572 33.48 103.656 ;
    END
  END a_d[327]
  PIN a_d[328]
    DIRECTION OUTPUT ;
    USE SIGNAL ;
    PORT
      LAYER M3 ;
        RECT  33.552 103.618 33.57 103.656 ;
    END
  END a_d[328]
  PIN a_d[329]
    DIRECTION OUTPUT ;
    USE SIGNAL ;
    PORT
      LAYER M5 ;
        RECT  33.648 103.572 33.672 103.656 ;
    END
  END a_d[329]
  PIN a_d[32]
    DIRECTION OUTPUT ;
    USE SIGNAL ;
    PORT
      LAYER M3 ;
        RECT  4.572 103.618 4.59 103.656 ;
    END
  END a_d[32]
  PIN a_d[330]
    DIRECTION OUTPUT ;
    USE SIGNAL ;
    PORT
      LAYER M3 ;
        RECT  33.732 103.618 33.75 103.656 ;
    END
  END a_d[330]
  PIN a_d[331]
    DIRECTION OUTPUT ;
    USE SIGNAL ;
    PORT
      LAYER M5 ;
        RECT  33.84 103.572 33.864 103.656 ;
    END
  END a_d[331]
  PIN a_d[332]
    DIRECTION OUTPUT ;
    USE SIGNAL ;
    PORT
      LAYER M3 ;
        RECT  33.948 103.618 33.966 103.656 ;
    END
  END a_d[332]
  PIN a_d[333]
    DIRECTION OUTPUT ;
    USE SIGNAL ;
    PORT
      LAYER M5 ;
        RECT  34.032 103.572 34.056 103.656 ;
    END
  END a_d[333]
  PIN a_d[334]
    DIRECTION OUTPUT ;
    USE SIGNAL ;
    PORT
      LAYER M3 ;
        RECT  34.128 103.618 34.146 103.656 ;
    END
  END a_d[334]
  PIN a_d[335]
    DIRECTION OUTPUT ;
    USE SIGNAL ;
    PORT
      LAYER M5 ;
        RECT  34.224 103.572 34.248 103.656 ;
    END
  END a_d[335]
  PIN a_d[336]
    DIRECTION OUTPUT ;
    USE SIGNAL ;
    PORT
      LAYER M3 ;
        RECT  34.308 103.618 34.326 103.656 ;
    END
  END a_d[336]
  PIN a_d[337]
    DIRECTION OUTPUT ;
    USE SIGNAL ;
    PORT
      LAYER M5 ;
        RECT  34.416 103.572 34.44 103.656 ;
    END
  END a_d[337]
  PIN a_d[338]
    DIRECTION OUTPUT ;
    USE SIGNAL ;
    PORT
      LAYER M3 ;
        RECT  34.524 103.618 34.542 103.656 ;
    END
  END a_d[338]
  PIN a_d[339]
    DIRECTION OUTPUT ;
    USE SIGNAL ;
    PORT
      LAYER M5 ;
        RECT  34.608 103.572 34.632 103.656 ;
    END
  END a_d[339]
  PIN a_d[33]
    DIRECTION OUTPUT ;
    USE SIGNAL ;
    PORT
      LAYER M5 ;
        RECT  4.656 103.572 4.68 103.656 ;
    END
  END a_d[33]
  PIN a_d[340]
    DIRECTION OUTPUT ;
    USE SIGNAL ;
    PORT
      LAYER M3 ;
        RECT  34.704 103.618 34.722 103.656 ;
    END
  END a_d[340]
  PIN a_d[341]
    DIRECTION OUTPUT ;
    USE SIGNAL ;
    PORT
      LAYER M5 ;
        RECT  34.8 103.572 34.824 103.656 ;
    END
  END a_d[341]
  PIN a_d[342]
    DIRECTION OUTPUT ;
    USE SIGNAL ;
    PORT
      LAYER M3 ;
        RECT  34.92 103.618 34.938 103.656 ;
    END
  END a_d[342]
  PIN a_d[343]
    DIRECTION OUTPUT ;
    USE SIGNAL ;
    PORT
      LAYER M5 ;
        RECT  34.992 103.572 35.016 103.656 ;
    END
  END a_d[343]
  PIN a_d[344]
    DIRECTION OUTPUT ;
    USE SIGNAL ;
    PORT
      LAYER M3 ;
        RECT  35.1 103.618 35.118 103.656 ;
    END
  END a_d[344]
  PIN a_d[345]
    DIRECTION OUTPUT ;
    USE SIGNAL ;
    PORT
      LAYER M5 ;
        RECT  35.184 103.572 35.208 103.656 ;
    END
  END a_d[345]
  PIN a_d[346]
    DIRECTION OUTPUT ;
    USE SIGNAL ;
    PORT
      LAYER M3 ;
        RECT  35.316 103.618 35.334 103.656 ;
    END
  END a_d[346]
  PIN a_d[347]
    DIRECTION OUTPUT ;
    USE SIGNAL ;
    PORT
      LAYER M5 ;
        RECT  35.376 103.572 35.4 103.656 ;
    END
  END a_d[347]
  PIN a_d[348]
    DIRECTION OUTPUT ;
    USE SIGNAL ;
    PORT
      LAYER M3 ;
        RECT  35.496 103.618 35.514 103.656 ;
    END
  END a_d[348]
  PIN a_d[349]
    DIRECTION OUTPUT ;
    USE SIGNAL ;
    PORT
      LAYER M5 ;
        RECT  35.616 103.572 35.64 103.656 ;
    END
  END a_d[349]
  PIN a_d[34]
    DIRECTION OUTPUT ;
    USE SIGNAL ;
    PORT
      LAYER M3 ;
        RECT  4.788 103.618 4.806 103.656 ;
    END
  END a_d[34]
  PIN a_d[350]
    DIRECTION OUTPUT ;
    USE SIGNAL ;
    PORT
      LAYER M3 ;
        RECT  35.712 103.618 35.73 103.656 ;
    END
  END a_d[350]
  PIN a_d[351]
    DIRECTION OUTPUT ;
    USE SIGNAL ;
    PORT
      LAYER M5 ;
        RECT  35.808 103.572 35.832 103.656 ;
    END
  END a_d[351]
  PIN a_d[352]
    DIRECTION OUTPUT ;
    USE SIGNAL ;
    PORT
      LAYER M3 ;
        RECT  35.892 103.618 35.91 103.656 ;
    END
  END a_d[352]
  PIN a_d[353]
    DIRECTION OUTPUT ;
    USE SIGNAL ;
    PORT
      LAYER M5 ;
        RECT  36 103.572 36.024 103.656 ;
    END
  END a_d[353]
  PIN a_d[354]
    DIRECTION OUTPUT ;
    USE SIGNAL ;
    PORT
      LAYER M3 ;
        RECT  36.072 103.618 36.09 103.656 ;
    END
  END a_d[354]
  PIN a_d[355]
    DIRECTION OUTPUT ;
    USE SIGNAL ;
    PORT
      LAYER M5 ;
        RECT  36.192 103.572 36.216 103.656 ;
    END
  END a_d[355]
  PIN a_d[356]
    DIRECTION OUTPUT ;
    USE SIGNAL ;
    PORT
      LAYER M3 ;
        RECT  36.288 103.618 36.306 103.656 ;
    END
  END a_d[356]
  PIN a_d[357]
    DIRECTION OUTPUT ;
    USE SIGNAL ;
    PORT
      LAYER M5 ;
        RECT  36.384 103.572 36.408 103.656 ;
    END
  END a_d[357]
  PIN a_d[358]
    DIRECTION OUTPUT ;
    USE SIGNAL ;
    PORT
      LAYER M3 ;
        RECT  36.468 103.618 36.486 103.656 ;
    END
  END a_d[358]
  PIN a_d[359]
    DIRECTION OUTPUT ;
    USE SIGNAL ;
    PORT
      LAYER M5 ;
        RECT  36.576 103.572 36.6 103.656 ;
    END
  END a_d[359]
  PIN a_d[35]
    DIRECTION OUTPUT ;
    USE SIGNAL ;
    PORT
      LAYER M5 ;
        RECT  4.848 103.572 4.872 103.656 ;
    END
  END a_d[35]
  PIN a_d[360]
    DIRECTION OUTPUT ;
    USE SIGNAL ;
    PORT
      LAYER M3 ;
        RECT  36.684 103.618 36.702 103.656 ;
    END
  END a_d[360]
  PIN a_d[361]
    DIRECTION OUTPUT ;
    USE SIGNAL ;
    PORT
      LAYER M5 ;
        RECT  36.768 103.572 36.792 103.656 ;
    END
  END a_d[361]
  PIN a_d[362]
    DIRECTION OUTPUT ;
    USE SIGNAL ;
    PORT
      LAYER M3 ;
        RECT  36.864 103.618 36.882 103.656 ;
    END
  END a_d[362]
  PIN a_d[363]
    DIRECTION OUTPUT ;
    USE SIGNAL ;
    PORT
      LAYER M5 ;
        RECT  36.96 103.572 36.984 103.656 ;
    END
  END a_d[363]
  PIN a_d[364]
    DIRECTION OUTPUT ;
    USE SIGNAL ;
    PORT
      LAYER M3 ;
        RECT  37.08 103.618 37.098 103.656 ;
    END
  END a_d[364]
  PIN a_d[365]
    DIRECTION OUTPUT ;
    USE SIGNAL ;
    PORT
      LAYER M5 ;
        RECT  37.152 103.572 37.176 103.656 ;
    END
  END a_d[365]
  PIN a_d[366]
    DIRECTION OUTPUT ;
    USE SIGNAL ;
    PORT
      LAYER M3 ;
        RECT  37.26 103.618 37.278 103.656 ;
    END
  END a_d[366]
  PIN a_d[367]
    DIRECTION OUTPUT ;
    USE SIGNAL ;
    PORT
      LAYER M5 ;
        RECT  37.344 103.572 37.368 103.656 ;
    END
  END a_d[367]
  PIN a_d[368]
    DIRECTION OUTPUT ;
    USE SIGNAL ;
    PORT
      LAYER M3 ;
        RECT  37.44 103.618 37.458 103.656 ;
    END
  END a_d[368]
  PIN a_d[369]
    DIRECTION OUTPUT ;
    USE SIGNAL ;
    PORT
      LAYER M5 ;
        RECT  37.536 103.572 37.56 103.656 ;
    END
  END a_d[369]
  PIN a_d[36]
    DIRECTION OUTPUT ;
    USE SIGNAL ;
    PORT
      LAYER M3 ;
        RECT  4.968 103.618 4.986 103.656 ;
    END
  END a_d[36]
  PIN a_d[370]
    DIRECTION OUTPUT ;
    USE SIGNAL ;
    PORT
      LAYER M3 ;
        RECT  37.656 103.618 37.674 103.656 ;
    END
  END a_d[370]
  PIN a_d[371]
    DIRECTION OUTPUT ;
    USE SIGNAL ;
    PORT
      LAYER M5 ;
        RECT  37.728 103.572 37.752 103.656 ;
    END
  END a_d[371]
  PIN a_d[372]
    DIRECTION OUTPUT ;
    USE SIGNAL ;
    PORT
      LAYER M3 ;
        RECT  37.836 103.618 37.854 103.656 ;
    END
  END a_d[372]
  PIN a_d[373]
    DIRECTION OUTPUT ;
    USE SIGNAL ;
    PORT
      LAYER M5 ;
        RECT  37.92 103.572 37.944 103.656 ;
    END
  END a_d[373]
  PIN a_d[374]
    DIRECTION OUTPUT ;
    USE SIGNAL ;
    PORT
      LAYER M3 ;
        RECT  38.052 103.618 38.07 103.656 ;
    END
  END a_d[374]
  PIN a_d[375]
    DIRECTION OUTPUT ;
    USE SIGNAL ;
    PORT
      LAYER M5 ;
        RECT  38.16 103.572 38.184 103.656 ;
    END
  END a_d[375]
  PIN a_d[376]
    DIRECTION OUTPUT ;
    USE SIGNAL ;
    PORT
      LAYER M3 ;
        RECT  38.232 103.618 38.25 103.656 ;
    END
  END a_d[376]
  PIN a_d[377]
    DIRECTION OUTPUT ;
    USE SIGNAL ;
    PORT
      LAYER M5 ;
        RECT  38.352 103.572 38.376 103.656 ;
    END
  END a_d[377]
  PIN a_d[378]
    DIRECTION OUTPUT ;
    USE SIGNAL ;
    PORT
      LAYER M3 ;
        RECT  38.448 103.618 38.466 103.656 ;
    END
  END a_d[378]
  PIN a_d[379]
    DIRECTION OUTPUT ;
    USE SIGNAL ;
    PORT
      LAYER M5 ;
        RECT  38.544 103.572 38.568 103.656 ;
    END
  END a_d[379]
  PIN a_d[37]
    DIRECTION OUTPUT ;
    USE SIGNAL ;
    PORT
      LAYER M5 ;
        RECT  5.04 103.572 5.064 103.656 ;
    END
  END a_d[37]
  PIN a_d[380]
    DIRECTION OUTPUT ;
    USE SIGNAL ;
    PORT
      LAYER M3 ;
        RECT  38.628 103.618 38.646 103.656 ;
    END
  END a_d[380]
  PIN a_d[381]
    DIRECTION OUTPUT ;
    USE SIGNAL ;
    PORT
      LAYER M5 ;
        RECT  38.736 103.572 38.76 103.656 ;
    END
  END a_d[381]
  PIN a_d[382]
    DIRECTION OUTPUT ;
    USE SIGNAL ;
    PORT
      LAYER M3 ;
        RECT  38.844 103.618 38.862 103.656 ;
    END
  END a_d[382]
  PIN a_d[383]
    DIRECTION OUTPUT ;
    USE SIGNAL ;
    PORT
      LAYER M5 ;
        RECT  38.928 103.572 38.952 103.656 ;
    END
  END a_d[383]
  PIN a_d[384]
    DIRECTION OUTPUT ;
    USE SIGNAL ;
    PORT
      LAYER M3 ;
        RECT  39.024 103.618 39.042 103.656 ;
    END
  END a_d[384]
  PIN a_d[385]
    DIRECTION OUTPUT ;
    USE SIGNAL ;
    PORT
      LAYER M5 ;
        RECT  39.12 103.572 39.144 103.656 ;
    END
  END a_d[385]
  PIN a_d[386]
    DIRECTION OUTPUT ;
    USE SIGNAL ;
    PORT
      LAYER M3 ;
        RECT  39.204 103.618 39.222 103.656 ;
    END
  END a_d[386]
  PIN a_d[387]
    DIRECTION OUTPUT ;
    USE SIGNAL ;
    PORT
      LAYER M5 ;
        RECT  39.312 103.572 39.336 103.656 ;
    END
  END a_d[387]
  PIN a_d[388]
    DIRECTION OUTPUT ;
    USE SIGNAL ;
    PORT
      LAYER M3 ;
        RECT  39.42 103.618 39.438 103.656 ;
    END
  END a_d[388]
  PIN a_d[389]
    DIRECTION OUTPUT ;
    USE SIGNAL ;
    PORT
      LAYER M5 ;
        RECT  39.504 103.572 39.528 103.656 ;
    END
  END a_d[389]
  PIN a_d[38]
    DIRECTION OUTPUT ;
    USE SIGNAL ;
    PORT
      LAYER M3 ;
        RECT  5.148 103.618 5.166 103.656 ;
    END
  END a_d[38]
  PIN a_d[390]
    DIRECTION OUTPUT ;
    USE SIGNAL ;
    PORT
      LAYER M3 ;
        RECT  39.6 103.618 39.618 103.656 ;
    END
  END a_d[390]
  PIN a_d[391]
    DIRECTION OUTPUT ;
    USE SIGNAL ;
    PORT
      LAYER M5 ;
        RECT  39.696 103.572 39.72 103.656 ;
    END
  END a_d[391]
  PIN a_d[392]
    DIRECTION OUTPUT ;
    USE SIGNAL ;
    PORT
      LAYER M3 ;
        RECT  39.816 103.618 39.834 103.656 ;
    END
  END a_d[392]
  PIN a_d[393]
    DIRECTION OUTPUT ;
    USE SIGNAL ;
    PORT
      LAYER M5 ;
        RECT  39.888 103.572 39.912 103.656 ;
    END
  END a_d[393]
  PIN a_d[394]
    DIRECTION OUTPUT ;
    USE SIGNAL ;
    PORT
      LAYER M3 ;
        RECT  39.996 103.618 40.014 103.656 ;
    END
  END a_d[394]
  PIN a_d[395]
    DIRECTION OUTPUT ;
    USE SIGNAL ;
    PORT
      LAYER M5 ;
        RECT  40.08 103.572 40.104 103.656 ;
    END
  END a_d[395]
  PIN a_d[396]
    DIRECTION OUTPUT ;
    USE SIGNAL ;
    PORT
      LAYER M3 ;
        RECT  40.212 103.618 40.23 103.656 ;
    END
  END a_d[396]
  PIN a_d[397]
    DIRECTION OUTPUT ;
    USE SIGNAL ;
    PORT
      LAYER M5 ;
        RECT  40.272 103.572 40.296 103.656 ;
    END
  END a_d[397]
  PIN a_d[398]
    DIRECTION OUTPUT ;
    USE SIGNAL ;
    PORT
      LAYER M3 ;
        RECT  40.392 103.618 40.41 103.656 ;
    END
  END a_d[398]
  PIN a_d[399]
    DIRECTION OUTPUT ;
    USE SIGNAL ;
    PORT
      LAYER M5 ;
        RECT  40.464 103.572 40.488 103.656 ;
    END
  END a_d[399]
  PIN a_d[39]
    DIRECTION OUTPUT ;
    USE SIGNAL ;
    PORT
      LAYER M5 ;
        RECT  5.28 103.572 5.304 103.656 ;
    END
  END a_d[39]
  PIN a_d[3]
    DIRECTION OUTPUT ;
    USE SIGNAL ;
    PORT
      LAYER M5 ;
        RECT  1.728 103.572 1.752 103.656 ;
    END
  END a_d[3]
  PIN a_d[400]
    DIRECTION OUTPUT ;
    USE SIGNAL ;
    PORT
      LAYER M3 ;
        RECT  40.572 103.618 40.59 103.656 ;
    END
  END a_d[400]
  PIN a_d[401]
    DIRECTION OUTPUT ;
    USE SIGNAL ;
    PORT
      LAYER M5 ;
        RECT  40.704 103.572 40.728 103.656 ;
    END
  END a_d[401]
  PIN a_d[402]
    DIRECTION OUTPUT ;
    USE SIGNAL ;
    PORT
      LAYER M3 ;
        RECT  40.788 103.618 40.806 103.656 ;
    END
  END a_d[402]
  PIN a_d[403]
    DIRECTION OUTPUT ;
    USE SIGNAL ;
    PORT
      LAYER M5 ;
        RECT  40.896 103.572 40.92 103.656 ;
    END
  END a_d[403]
  PIN a_d[404]
    DIRECTION OUTPUT ;
    USE SIGNAL ;
    PORT
      LAYER M3 ;
        RECT  40.968 103.618 40.986 103.656 ;
    END
  END a_d[404]
  PIN a_d[405]
    DIRECTION OUTPUT ;
    USE SIGNAL ;
    PORT
      LAYER M5 ;
        RECT  41.088 103.572 41.112 103.656 ;
    END
  END a_d[405]
  PIN a_d[406]
    DIRECTION OUTPUT ;
    USE SIGNAL ;
    PORT
      LAYER M3 ;
        RECT  41.184 103.618 41.202 103.656 ;
    END
  END a_d[406]
  PIN a_d[407]
    DIRECTION OUTPUT ;
    USE SIGNAL ;
    PORT
      LAYER M5 ;
        RECT  41.28 103.572 41.304 103.656 ;
    END
  END a_d[407]
  PIN a_d[408]
    DIRECTION OUTPUT ;
    USE SIGNAL ;
    PORT
      LAYER M3 ;
        RECT  41.364 103.618 41.382 103.656 ;
    END
  END a_d[408]
  PIN a_d[409]
    DIRECTION OUTPUT ;
    USE SIGNAL ;
    PORT
      LAYER M5 ;
        RECT  41.472 103.572 41.496 103.656 ;
    END
  END a_d[409]
  PIN a_d[40]
    DIRECTION OUTPUT ;
    USE SIGNAL ;
    PORT
      LAYER M3 ;
        RECT  5.364 103.618 5.382 103.656 ;
    END
  END a_d[40]
  PIN a_d[410]
    DIRECTION OUTPUT ;
    USE SIGNAL ;
    PORT
      LAYER M3 ;
        RECT  41.58 103.618 41.598 103.656 ;
    END
  END a_d[410]
  PIN a_d[411]
    DIRECTION OUTPUT ;
    USE SIGNAL ;
    PORT
      LAYER M5 ;
        RECT  41.664 103.572 41.688 103.656 ;
    END
  END a_d[411]
  PIN a_d[412]
    DIRECTION OUTPUT ;
    USE SIGNAL ;
    PORT
      LAYER M3 ;
        RECT  41.76 103.618 41.778 103.656 ;
    END
  END a_d[412]
  PIN a_d[413]
    DIRECTION OUTPUT ;
    USE SIGNAL ;
    PORT
      LAYER M5 ;
        RECT  41.856 103.572 41.88 103.656 ;
    END
  END a_d[413]
  PIN a_d[414]
    DIRECTION OUTPUT ;
    USE SIGNAL ;
    PORT
      LAYER M3 ;
        RECT  41.976 103.618 41.994 103.656 ;
    END
  END a_d[414]
  PIN a_d[415]
    DIRECTION OUTPUT ;
    USE SIGNAL ;
    PORT
      LAYER M5 ;
        RECT  42.048 103.572 42.072 103.656 ;
    END
  END a_d[415]
  PIN a_d[416]
    DIRECTION OUTPUT ;
    USE SIGNAL ;
    PORT
      LAYER M3 ;
        RECT  42.156 103.618 42.174 103.656 ;
    END
  END a_d[416]
  PIN a_d[417]
    DIRECTION OUTPUT ;
    USE SIGNAL ;
    PORT
      LAYER M5 ;
        RECT  42.24 103.572 42.264 103.656 ;
    END
  END a_d[417]
  PIN a_d[418]
    DIRECTION OUTPUT ;
    USE SIGNAL ;
    PORT
      LAYER M3 ;
        RECT  42.336 103.618 42.354 103.656 ;
    END
  END a_d[418]
  PIN a_d[419]
    DIRECTION OUTPUT ;
    USE SIGNAL ;
    PORT
      LAYER M5 ;
        RECT  42.432 103.572 42.456 103.656 ;
    END
  END a_d[419]
  PIN a_d[41]
    DIRECTION OUTPUT ;
    USE SIGNAL ;
    PORT
      LAYER M5 ;
        RECT  5.472 103.572 5.496 103.656 ;
    END
  END a_d[41]
  PIN a_d[420]
    DIRECTION OUTPUT ;
    USE SIGNAL ;
    PORT
      LAYER M3 ;
        RECT  42.552 103.618 42.57 103.656 ;
    END
  END a_d[420]
  PIN a_d[421]
    DIRECTION OUTPUT ;
    USE SIGNAL ;
    PORT
      LAYER M5 ;
        RECT  42.624 103.572 42.648 103.656 ;
    END
  END a_d[421]
  PIN a_d[422]
    DIRECTION OUTPUT ;
    USE SIGNAL ;
    PORT
      LAYER M3 ;
        RECT  42.732 103.618 42.75 103.656 ;
    END
  END a_d[422]
  PIN a_d[423]
    DIRECTION OUTPUT ;
    USE SIGNAL ;
    PORT
      LAYER M5 ;
        RECT  42.816 103.572 42.84 103.656 ;
    END
  END a_d[423]
  PIN a_d[424]
    DIRECTION OUTPUT ;
    USE SIGNAL ;
    PORT
      LAYER M3 ;
        RECT  42.948 103.618 42.966 103.656 ;
    END
  END a_d[424]
  PIN a_d[425]
    DIRECTION OUTPUT ;
    USE SIGNAL ;
    PORT
      LAYER M5 ;
        RECT  43.056 103.572 43.08 103.656 ;
    END
  END a_d[425]
  PIN a_d[426]
    DIRECTION OUTPUT ;
    USE SIGNAL ;
    PORT
      LAYER M3 ;
        RECT  43.128 103.618 43.146 103.656 ;
    END
  END a_d[426]
  PIN a_d[427]
    DIRECTION OUTPUT ;
    USE SIGNAL ;
    PORT
      LAYER M5 ;
        RECT  43.248 103.572 43.272 103.656 ;
    END
  END a_d[427]
  PIN a_d[428]
    DIRECTION OUTPUT ;
    USE SIGNAL ;
    PORT
      LAYER M3 ;
        RECT  43.344 103.618 43.362 103.656 ;
    END
  END a_d[428]
  PIN a_d[429]
    DIRECTION OUTPUT ;
    USE SIGNAL ;
    PORT
      LAYER M5 ;
        RECT  43.44 103.572 43.464 103.656 ;
    END
  END a_d[429]
  PIN a_d[42]
    DIRECTION OUTPUT ;
    USE SIGNAL ;
    PORT
      LAYER M3 ;
        RECT  5.544 103.618 5.562 103.656 ;
    END
  END a_d[42]
  PIN a_d[430]
    DIRECTION OUTPUT ;
    USE SIGNAL ;
    PORT
      LAYER M3 ;
        RECT  43.524 103.618 43.542 103.656 ;
    END
  END a_d[430]
  PIN a_d[431]
    DIRECTION OUTPUT ;
    USE SIGNAL ;
    PORT
      LAYER M5 ;
        RECT  43.632 103.572 43.656 103.656 ;
    END
  END a_d[431]
  PIN a_d[432]
    DIRECTION OUTPUT ;
    USE SIGNAL ;
    PORT
      LAYER M3 ;
        RECT  43.704 103.618 43.722 103.656 ;
    END
  END a_d[432]
  PIN a_d[433]
    DIRECTION OUTPUT ;
    USE SIGNAL ;
    PORT
      LAYER M5 ;
        RECT  43.824 103.572 43.848 103.656 ;
    END
  END a_d[433]
  PIN a_d[434]
    DIRECTION OUTPUT ;
    USE SIGNAL ;
    PORT
      LAYER M3 ;
        RECT  43.92 103.618 43.938 103.656 ;
    END
  END a_d[434]
  PIN a_d[435]
    DIRECTION OUTPUT ;
    USE SIGNAL ;
    PORT
      LAYER M5 ;
        RECT  44.016 103.572 44.04 103.656 ;
    END
  END a_d[435]
  PIN a_d[436]
    DIRECTION OUTPUT ;
    USE SIGNAL ;
    PORT
      LAYER M3 ;
        RECT  44.1 103.618 44.118 103.656 ;
    END
  END a_d[436]
  PIN a_d[437]
    DIRECTION OUTPUT ;
    USE SIGNAL ;
    PORT
      LAYER M5 ;
        RECT  44.208 103.572 44.232 103.656 ;
    END
  END a_d[437]
  PIN a_d[438]
    DIRECTION OUTPUT ;
    USE SIGNAL ;
    PORT
      LAYER M3 ;
        RECT  44.316 103.618 44.334 103.656 ;
    END
  END a_d[438]
  PIN a_d[439]
    DIRECTION OUTPUT ;
    USE SIGNAL ;
    PORT
      LAYER M5 ;
        RECT  44.4 103.572 44.424 103.656 ;
    END
  END a_d[439]
  PIN a_d[43]
    DIRECTION OUTPUT ;
    USE SIGNAL ;
    PORT
      LAYER M5 ;
        RECT  5.664 103.572 5.688 103.656 ;
    END
  END a_d[43]
  PIN a_d[440]
    DIRECTION OUTPUT ;
    USE SIGNAL ;
    PORT
      LAYER M3 ;
        RECT  44.496 103.618 44.514 103.656 ;
    END
  END a_d[440]
  PIN a_d[441]
    DIRECTION OUTPUT ;
    USE SIGNAL ;
    PORT
      LAYER M5 ;
        RECT  44.592 103.572 44.616 103.656 ;
    END
  END a_d[441]
  PIN a_d[442]
    DIRECTION OUTPUT ;
    USE SIGNAL ;
    PORT
      LAYER M3 ;
        RECT  44.712 103.618 44.73 103.656 ;
    END
  END a_d[442]
  PIN a_d[443]
    DIRECTION OUTPUT ;
    USE SIGNAL ;
    PORT
      LAYER M5 ;
        RECT  44.784 103.572 44.808 103.656 ;
    END
  END a_d[443]
  PIN a_d[444]
    DIRECTION OUTPUT ;
    USE SIGNAL ;
    PORT
      LAYER M3 ;
        RECT  44.892 103.618 44.91 103.656 ;
    END
  END a_d[444]
  PIN a_d[445]
    DIRECTION OUTPUT ;
    USE SIGNAL ;
    PORT
      LAYER M5 ;
        RECT  44.976 103.572 45 103.656 ;
    END
  END a_d[445]
  PIN a_d[446]
    DIRECTION OUTPUT ;
    USE SIGNAL ;
    PORT
      LAYER M3 ;
        RECT  45.108 103.618 45.126 103.656 ;
    END
  END a_d[446]
  PIN a_d[447]
    DIRECTION OUTPUT ;
    USE SIGNAL ;
    PORT
      LAYER M5 ;
        RECT  45.168 103.572 45.192 103.656 ;
    END
  END a_d[447]
  PIN a_d[448]
    DIRECTION OUTPUT ;
    USE SIGNAL ;
    PORT
      LAYER M3 ;
        RECT  45.288 103.618 45.306 103.656 ;
    END
  END a_d[448]
  PIN a_d[449]
    DIRECTION OUTPUT ;
    USE SIGNAL ;
    PORT
      LAYER M5 ;
        RECT  45.36 103.572 45.384 103.656 ;
    END
  END a_d[449]
  PIN a_d[44]
    DIRECTION OUTPUT ;
    USE SIGNAL ;
    PORT
      LAYER M3 ;
        RECT  5.76 103.618 5.778 103.656 ;
    END
  END a_d[44]
  PIN a_d[450]
    DIRECTION OUTPUT ;
    USE SIGNAL ;
    PORT
      LAYER M3 ;
        RECT  45.468 103.618 45.486 103.656 ;
    END
  END a_d[450]
  PIN a_d[451]
    DIRECTION OUTPUT ;
    USE SIGNAL ;
    PORT
      LAYER M5 ;
        RECT  45.6 103.572 45.624 103.656 ;
    END
  END a_d[451]
  PIN a_d[452]
    DIRECTION OUTPUT ;
    USE SIGNAL ;
    PORT
      LAYER M3 ;
        RECT  45.684 103.618 45.702 103.656 ;
    END
  END a_d[452]
  PIN a_d[453]
    DIRECTION OUTPUT ;
    USE SIGNAL ;
    PORT
      LAYER M5 ;
        RECT  45.792 103.572 45.816 103.656 ;
    END
  END a_d[453]
  PIN a_d[454]
    DIRECTION OUTPUT ;
    USE SIGNAL ;
    PORT
      LAYER M3 ;
        RECT  45.864 103.618 45.882 103.656 ;
    END
  END a_d[454]
  PIN a_d[455]
    DIRECTION OUTPUT ;
    USE SIGNAL ;
    PORT
      LAYER M5 ;
        RECT  45.984 103.572 46.008 103.656 ;
    END
  END a_d[455]
  PIN a_d[456]
    DIRECTION OUTPUT ;
    USE SIGNAL ;
    PORT
      LAYER M3 ;
        RECT  46.08 103.618 46.098 103.656 ;
    END
  END a_d[456]
  PIN a_d[457]
    DIRECTION OUTPUT ;
    USE SIGNAL ;
    PORT
      LAYER M5 ;
        RECT  46.176 103.572 46.2 103.656 ;
    END
  END a_d[457]
  PIN a_d[458]
    DIRECTION OUTPUT ;
    USE SIGNAL ;
    PORT
      LAYER M3 ;
        RECT  46.26 103.618 46.278 103.656 ;
    END
  END a_d[458]
  PIN a_d[459]
    DIRECTION OUTPUT ;
    USE SIGNAL ;
    PORT
      LAYER M5 ;
        RECT  46.368 103.572 46.392 103.656 ;
    END
  END a_d[459]
  PIN a_d[45]
    DIRECTION OUTPUT ;
    USE SIGNAL ;
    PORT
      LAYER M5 ;
        RECT  5.856 103.572 5.88 103.656 ;
    END
  END a_d[45]
  PIN a_d[460]
    DIRECTION OUTPUT ;
    USE SIGNAL ;
    PORT
      LAYER M3 ;
        RECT  46.476 103.618 46.494 103.656 ;
    END
  END a_d[460]
  PIN a_d[461]
    DIRECTION OUTPUT ;
    USE SIGNAL ;
    PORT
      LAYER M5 ;
        RECT  46.56 103.572 46.584 103.656 ;
    END
  END a_d[461]
  PIN a_d[462]
    DIRECTION OUTPUT ;
    USE SIGNAL ;
    PORT
      LAYER M3 ;
        RECT  46.656 103.618 46.674 103.656 ;
    END
  END a_d[462]
  PIN a_d[463]
    DIRECTION OUTPUT ;
    USE SIGNAL ;
    PORT
      LAYER M5 ;
        RECT  46.752 103.572 46.776 103.656 ;
    END
  END a_d[463]
  PIN a_d[464]
    DIRECTION OUTPUT ;
    USE SIGNAL ;
    PORT
      LAYER M3 ;
        RECT  46.836 103.618 46.854 103.656 ;
    END
  END a_d[464]
  PIN a_d[465]
    DIRECTION OUTPUT ;
    USE SIGNAL ;
    PORT
      LAYER M5 ;
        RECT  46.944 103.572 46.968 103.656 ;
    END
  END a_d[465]
  PIN a_d[466]
    DIRECTION OUTPUT ;
    USE SIGNAL ;
    PORT
      LAYER M3 ;
        RECT  47.052 103.618 47.07 103.656 ;
    END
  END a_d[466]
  PIN a_d[467]
    DIRECTION OUTPUT ;
    USE SIGNAL ;
    PORT
      LAYER M5 ;
        RECT  47.136 103.572 47.16 103.656 ;
    END
  END a_d[467]
  PIN a_d[468]
    DIRECTION OUTPUT ;
    USE SIGNAL ;
    PORT
      LAYER M3 ;
        RECT  47.232 103.618 47.25 103.656 ;
    END
  END a_d[468]
  PIN a_d[469]
    DIRECTION OUTPUT ;
    USE SIGNAL ;
    PORT
      LAYER M5 ;
        RECT  47.328 103.572 47.352 103.656 ;
    END
  END a_d[469]
  PIN a_d[46]
    DIRECTION OUTPUT ;
    USE SIGNAL ;
    PORT
      LAYER M3 ;
        RECT  5.94 103.618 5.958 103.656 ;
    END
  END a_d[46]
  PIN a_d[470]
    DIRECTION OUTPUT ;
    USE SIGNAL ;
    PORT
      LAYER M3 ;
        RECT  47.448 103.618 47.466 103.656 ;
    END
  END a_d[470]
  PIN a_d[471]
    DIRECTION OUTPUT ;
    USE SIGNAL ;
    PORT
      LAYER M5 ;
        RECT  47.52 103.572 47.544 103.656 ;
    END
  END a_d[471]
  PIN a_d[472]
    DIRECTION OUTPUT ;
    USE SIGNAL ;
    PORT
      LAYER M3 ;
        RECT  47.628 103.618 47.646 103.656 ;
    END
  END a_d[472]
  PIN a_d[473]
    DIRECTION OUTPUT ;
    USE SIGNAL ;
    PORT
      LAYER M5 ;
        RECT  47.712 103.572 47.736 103.656 ;
    END
  END a_d[473]
  PIN a_d[474]
    DIRECTION OUTPUT ;
    USE SIGNAL ;
    PORT
      LAYER M3 ;
        RECT  47.844 103.618 47.862 103.656 ;
    END
  END a_d[474]
  PIN a_d[475]
    DIRECTION OUTPUT ;
    USE SIGNAL ;
    PORT
      LAYER M5 ;
        RECT  47.904 103.572 47.928 103.656 ;
    END
  END a_d[475]
  PIN a_d[476]
    DIRECTION OUTPUT ;
    USE SIGNAL ;
    PORT
      LAYER M3 ;
        RECT  48.024 103.618 48.042 103.656 ;
    END
  END a_d[476]
  PIN a_d[477]
    DIRECTION OUTPUT ;
    USE SIGNAL ;
    PORT
      LAYER M5 ;
        RECT  48.144 103.572 48.168 103.656 ;
    END
  END a_d[477]
  PIN a_d[478]
    DIRECTION OUTPUT ;
    USE SIGNAL ;
    PORT
      LAYER M3 ;
        RECT  48.204 103.618 48.222 103.656 ;
    END
  END a_d[478]
  PIN a_d[479]
    DIRECTION OUTPUT ;
    USE SIGNAL ;
    PORT
      LAYER M5 ;
        RECT  48.336 103.572 48.36 103.656 ;
    END
  END a_d[479]
  PIN a_d[47]
    DIRECTION OUTPUT ;
    USE SIGNAL ;
    PORT
      LAYER M5 ;
        RECT  6.048 103.572 6.072 103.656 ;
    END
  END a_d[47]
  PIN a_d[480]
    DIRECTION OUTPUT ;
    USE SIGNAL ;
    PORT
      LAYER M3 ;
        RECT  48.42 103.618 48.438 103.656 ;
    END
  END a_d[480]
  PIN a_d[481]
    DIRECTION OUTPUT ;
    USE SIGNAL ;
    PORT
      LAYER M5 ;
        RECT  48.528 103.572 48.552 103.656 ;
    END
  END a_d[481]
  PIN a_d[482]
    DIRECTION OUTPUT ;
    USE SIGNAL ;
    PORT
      LAYER M3 ;
        RECT  48.6 103.618 48.618 103.656 ;
    END
  END a_d[482]
  PIN a_d[483]
    DIRECTION OUTPUT ;
    USE SIGNAL ;
    PORT
      LAYER M5 ;
        RECT  48.72 103.572 48.744 103.656 ;
    END
  END a_d[483]
  PIN a_d[484]
    DIRECTION OUTPUT ;
    USE SIGNAL ;
    PORT
      LAYER M3 ;
        RECT  48.816 103.618 48.834 103.656 ;
    END
  END a_d[484]
  PIN a_d[485]
    DIRECTION OUTPUT ;
    USE SIGNAL ;
    PORT
      LAYER M5 ;
        RECT  48.912 103.572 48.936 103.656 ;
    END
  END a_d[485]
  PIN a_d[486]
    DIRECTION OUTPUT ;
    USE SIGNAL ;
    PORT
      LAYER M3 ;
        RECT  48.996 103.618 49.014 103.656 ;
    END
  END a_d[486]
  PIN a_d[487]
    DIRECTION OUTPUT ;
    USE SIGNAL ;
    PORT
      LAYER M5 ;
        RECT  49.104 103.572 49.128 103.656 ;
    END
  END a_d[487]
  PIN a_d[488]
    DIRECTION OUTPUT ;
    USE SIGNAL ;
    PORT
      LAYER M3 ;
        RECT  49.212 103.618 49.23 103.656 ;
    END
  END a_d[488]
  PIN a_d[489]
    DIRECTION OUTPUT ;
    USE SIGNAL ;
    PORT
      LAYER M5 ;
        RECT  49.296 103.572 49.32 103.656 ;
    END
  END a_d[489]
  PIN a_d[48]
    DIRECTION OUTPUT ;
    USE SIGNAL ;
    PORT
      LAYER M3 ;
        RECT  6.156 103.618 6.174 103.656 ;
    END
  END a_d[48]
  PIN a_d[490]
    DIRECTION OUTPUT ;
    USE SIGNAL ;
    PORT
      LAYER M3 ;
        RECT  49.392 103.618 49.41 103.656 ;
    END
  END a_d[490]
  PIN a_d[491]
    DIRECTION OUTPUT ;
    USE SIGNAL ;
    PORT
      LAYER M5 ;
        RECT  49.488 103.572 49.512 103.656 ;
    END
  END a_d[491]
  PIN a_d[492]
    DIRECTION OUTPUT ;
    USE SIGNAL ;
    PORT
      LAYER M3 ;
        RECT  49.608 103.618 49.626 103.656 ;
    END
  END a_d[492]
  PIN a_d[493]
    DIRECTION OUTPUT ;
    USE SIGNAL ;
    PORT
      LAYER M5 ;
        RECT  49.68 103.572 49.704 103.656 ;
    END
  END a_d[493]
  PIN a_d[494]
    DIRECTION OUTPUT ;
    USE SIGNAL ;
    PORT
      LAYER M3 ;
        RECT  49.788 103.618 49.806 103.656 ;
    END
  END a_d[494]
  PIN a_d[495]
    DIRECTION OUTPUT ;
    USE SIGNAL ;
    PORT
      LAYER M5 ;
        RECT  49.872 103.572 49.896 103.656 ;
    END
  END a_d[495]
  PIN a_d[496]
    DIRECTION OUTPUT ;
    USE SIGNAL ;
    PORT
      LAYER M3 ;
        RECT  49.968 103.618 49.986 103.656 ;
    END
  END a_d[496]
  PIN a_d[497]
    DIRECTION OUTPUT ;
    USE SIGNAL ;
    PORT
      LAYER M5 ;
        RECT  50.064 103.572 50.088 103.656 ;
    END
  END a_d[497]
  PIN a_d[498]
    DIRECTION OUTPUT ;
    USE SIGNAL ;
    PORT
      LAYER M3 ;
        RECT  50.184 103.618 50.202 103.656 ;
    END
  END a_d[498]
  PIN a_d[499]
    DIRECTION OUTPUT ;
    USE SIGNAL ;
    PORT
      LAYER M5 ;
        RECT  50.256 103.572 50.28 103.656 ;
    END
  END a_d[499]
  PIN a_d[49]
    DIRECTION OUTPUT ;
    USE SIGNAL ;
    PORT
      LAYER M5 ;
        RECT  6.24 103.572 6.264 103.656 ;
    END
  END a_d[49]
  PIN a_d[4]
    DIRECTION OUTPUT ;
    USE SIGNAL ;
    PORT
      LAYER M3 ;
        RECT  1.836 103.618 1.854 103.656 ;
    END
  END a_d[4]
  PIN a_d[500]
    DIRECTION OUTPUT ;
    USE SIGNAL ;
    PORT
      LAYER M3 ;
        RECT  50.364 103.618 50.382 103.656 ;
    END
  END a_d[500]
  PIN a_d[501]
    DIRECTION OUTPUT ;
    USE SIGNAL ;
    PORT
      LAYER M5 ;
        RECT  50.448 103.572 50.472 103.656 ;
    END
  END a_d[501]
  PIN a_d[502]
    DIRECTION OUTPUT ;
    USE SIGNAL ;
    PORT
      LAYER M3 ;
        RECT  50.58 103.618 50.598 103.656 ;
    END
  END a_d[502]
  PIN a_d[503]
    DIRECTION OUTPUT ;
    USE SIGNAL ;
    PORT
      LAYER M5 ;
        RECT  50.688 103.572 50.712 103.656 ;
    END
  END a_d[503]
  PIN a_d[504]
    DIRECTION OUTPUT ;
    USE SIGNAL ;
    PORT
      LAYER M3 ;
        RECT  50.76 103.618 50.778 103.656 ;
    END
  END a_d[504]
  PIN a_d[505]
    DIRECTION OUTPUT ;
    USE SIGNAL ;
    PORT
      LAYER M5 ;
        RECT  50.88 103.572 50.904 103.656 ;
    END
  END a_d[505]
  PIN a_d[506]
    DIRECTION OUTPUT ;
    USE SIGNAL ;
    PORT
      LAYER M3 ;
        RECT  50.976 103.618 50.994 103.656 ;
    END
  END a_d[506]
  PIN a_d[507]
    DIRECTION OUTPUT ;
    USE SIGNAL ;
    PORT
      LAYER M5 ;
        RECT  51.072 103.572 51.096 103.656 ;
    END
  END a_d[507]
  PIN a_d[508]
    DIRECTION OUTPUT ;
    USE SIGNAL ;
    PORT
      LAYER M3 ;
        RECT  51.156 103.618 51.174 103.656 ;
    END
  END a_d[508]
  PIN a_d[509]
    DIRECTION OUTPUT ;
    USE SIGNAL ;
    PORT
      LAYER M5 ;
        RECT  51.264 103.572 51.288 103.656 ;
    END
  END a_d[509]
  PIN a_d[50]
    DIRECTION OUTPUT ;
    USE SIGNAL ;
    PORT
      LAYER M3 ;
        RECT  6.336 103.618 6.354 103.656 ;
    END
  END a_d[50]
  PIN a_d[510]
    DIRECTION OUTPUT ;
    USE SIGNAL ;
    PORT
      LAYER M3 ;
        RECT  51.336 103.618 51.354 103.656 ;
    END
  END a_d[510]
  PIN a_d[511]
    DIRECTION OUTPUT ;
    USE SIGNAL ;
    PORT
      LAYER M5 ;
        RECT  51.456 103.572 51.48 103.656 ;
    END
  END a_d[511]
  PIN a_d[512]
    DIRECTION OUTPUT ;
    USE SIGNAL ;
    PORT
      LAYER M3 ;
        RECT  51.552 103.618 51.57 103.656 ;
    END
  END a_d[512]
  PIN a_d[513]
    DIRECTION OUTPUT ;
    USE SIGNAL ;
    PORT
      LAYER M5 ;
        RECT  51.648 103.572 51.672 103.656 ;
    END
  END a_d[513]
  PIN a_d[514]
    DIRECTION OUTPUT ;
    USE SIGNAL ;
    PORT
      LAYER M3 ;
        RECT  51.732 103.618 51.75 103.656 ;
    END
  END a_d[514]
  PIN a_d[515]
    DIRECTION OUTPUT ;
    USE SIGNAL ;
    PORT
      LAYER M5 ;
        RECT  51.84 103.572 51.864 103.656 ;
    END
  END a_d[515]
  PIN a_d[51]
    DIRECTION OUTPUT ;
    USE SIGNAL ;
    PORT
      LAYER M5 ;
        RECT  6.432 103.572 6.456 103.656 ;
    END
  END a_d[51]
  PIN a_d[52]
    DIRECTION OUTPUT ;
    USE SIGNAL ;
    PORT
      LAYER M3 ;
        RECT  6.516 103.618 6.534 103.656 ;
    END
  END a_d[52]
  PIN a_d[53]
    DIRECTION OUTPUT ;
    USE SIGNAL ;
    PORT
      LAYER M5 ;
        RECT  6.624 103.572 6.648 103.656 ;
    END
  END a_d[53]
  PIN a_d[54]
    DIRECTION OUTPUT ;
    USE SIGNAL ;
    PORT
      LAYER M3 ;
        RECT  6.732 103.618 6.75 103.656 ;
    END
  END a_d[54]
  PIN a_d[55]
    DIRECTION OUTPUT ;
    USE SIGNAL ;
    PORT
      LAYER M5 ;
        RECT  6.816 103.572 6.84 103.656 ;
    END
  END a_d[55]
  PIN a_d[56]
    DIRECTION OUTPUT ;
    USE SIGNAL ;
    PORT
      LAYER M3 ;
        RECT  6.912 103.618 6.93 103.656 ;
    END
  END a_d[56]
  PIN a_d[57]
    DIRECTION OUTPUT ;
    USE SIGNAL ;
    PORT
      LAYER M5 ;
        RECT  7.008 103.572 7.032 103.656 ;
    END
  END a_d[57]
  PIN a_d[58]
    DIRECTION OUTPUT ;
    USE SIGNAL ;
    PORT
      LAYER M3 ;
        RECT  7.128 103.618 7.146 103.656 ;
    END
  END a_d[58]
  PIN a_d[59]
    DIRECTION OUTPUT ;
    USE SIGNAL ;
    PORT
      LAYER M5 ;
        RECT  7.2 103.572 7.224 103.656 ;
    END
  END a_d[59]
  PIN a_d[5]
    DIRECTION OUTPUT ;
    USE SIGNAL ;
    PORT
      LAYER M5 ;
        RECT  1.92 103.572 1.944 103.656 ;
    END
  END a_d[5]
  PIN a_d[60]
    DIRECTION OUTPUT ;
    USE SIGNAL ;
    PORT
      LAYER M3 ;
        RECT  7.308 103.618 7.326 103.656 ;
    END
  END a_d[60]
  PIN a_d[61]
    DIRECTION OUTPUT ;
    USE SIGNAL ;
    PORT
      LAYER M5 ;
        RECT  7.392 103.572 7.416 103.656 ;
    END
  END a_d[61]
  PIN a_d[62]
    DIRECTION OUTPUT ;
    USE SIGNAL ;
    PORT
      LAYER M3 ;
        RECT  7.524 103.618 7.542 103.656 ;
    END
  END a_d[62]
  PIN a_d[63]
    DIRECTION OUTPUT ;
    USE SIGNAL ;
    PORT
      LAYER M5 ;
        RECT  7.584 103.572 7.608 103.656 ;
    END
  END a_d[63]
  PIN a_d[64]
    DIRECTION OUTPUT ;
    USE SIGNAL ;
    PORT
      LAYER M3 ;
        RECT  7.704 103.618 7.722 103.656 ;
    END
  END a_d[64]
  PIN a_d[65]
    DIRECTION OUTPUT ;
    USE SIGNAL ;
    PORT
      LAYER M5 ;
        RECT  7.824 103.572 7.848 103.656 ;
    END
  END a_d[65]
  PIN a_d[66]
    DIRECTION OUTPUT ;
    USE SIGNAL ;
    PORT
      LAYER M3 ;
        RECT  7.92 103.618 7.938 103.656 ;
    END
  END a_d[66]
  PIN a_d[67]
    DIRECTION OUTPUT ;
    USE SIGNAL ;
    PORT
      LAYER M5 ;
        RECT  8.016 103.572 8.04 103.656 ;
    END
  END a_d[67]
  PIN a_d[68]
    DIRECTION OUTPUT ;
    USE SIGNAL ;
    PORT
      LAYER M3 ;
        RECT  8.1 103.618 8.118 103.656 ;
    END
  END a_d[68]
  PIN a_d[69]
    DIRECTION OUTPUT ;
    USE SIGNAL ;
    PORT
      LAYER M5 ;
        RECT  8.208 103.572 8.232 103.656 ;
    END
  END a_d[69]
  PIN a_d[6]
    DIRECTION OUTPUT ;
    USE SIGNAL ;
    PORT
      LAYER M3 ;
        RECT  2.016 103.618 2.034 103.656 ;
    END
  END a_d[6]
  PIN a_d[70]
    DIRECTION OUTPUT ;
    USE SIGNAL ;
    PORT
      LAYER M3 ;
        RECT  8.28 103.618 8.298 103.656 ;
    END
  END a_d[70]
  PIN a_d[71]
    DIRECTION OUTPUT ;
    USE SIGNAL ;
    PORT
      LAYER M5 ;
        RECT  8.4 103.572 8.424 103.656 ;
    END
  END a_d[71]
  PIN a_d[72]
    DIRECTION OUTPUT ;
    USE SIGNAL ;
    PORT
      LAYER M3 ;
        RECT  8.496 103.618 8.514 103.656 ;
    END
  END a_d[72]
  PIN a_d[73]
    DIRECTION OUTPUT ;
    USE SIGNAL ;
    PORT
      LAYER M5 ;
        RECT  8.592 103.572 8.616 103.656 ;
    END
  END a_d[73]
  PIN a_d[74]
    DIRECTION OUTPUT ;
    USE SIGNAL ;
    PORT
      LAYER M3 ;
        RECT  8.676 103.618 8.694 103.656 ;
    END
  END a_d[74]
  PIN a_d[75]
    DIRECTION OUTPUT ;
    USE SIGNAL ;
    PORT
      LAYER M5 ;
        RECT  8.784 103.572 8.808 103.656 ;
    END
  END a_d[75]
  PIN a_d[76]
    DIRECTION OUTPUT ;
    USE SIGNAL ;
    PORT
      LAYER M3 ;
        RECT  8.892 103.618 8.91 103.656 ;
    END
  END a_d[76]
  PIN a_d[77]
    DIRECTION OUTPUT ;
    USE SIGNAL ;
    PORT
      LAYER M5 ;
        RECT  8.976 103.572 9 103.656 ;
    END
  END a_d[77]
  PIN a_d[78]
    DIRECTION OUTPUT ;
    USE SIGNAL ;
    PORT
      LAYER M3 ;
        RECT  9.072 103.618 9.09 103.656 ;
    END
  END a_d[78]
  PIN a_d[79]
    DIRECTION OUTPUT ;
    USE SIGNAL ;
    PORT
      LAYER M5 ;
        RECT  9.168 103.572 9.192 103.656 ;
    END
  END a_d[79]
  PIN a_d[7]
    DIRECTION OUTPUT ;
    USE SIGNAL ;
    PORT
      LAYER M5 ;
        RECT  2.112 103.572 2.136 103.656 ;
    END
  END a_d[7]
  PIN a_d[80]
    DIRECTION OUTPUT ;
    USE SIGNAL ;
    PORT
      LAYER M3 ;
        RECT  9.288 103.618 9.306 103.656 ;
    END
  END a_d[80]
  PIN a_d[81]
    DIRECTION OUTPUT ;
    USE SIGNAL ;
    PORT
      LAYER M5 ;
        RECT  9.36 103.572 9.384 103.656 ;
    END
  END a_d[81]
  PIN a_d[82]
    DIRECTION OUTPUT ;
    USE SIGNAL ;
    PORT
      LAYER M3 ;
        RECT  9.468 103.618 9.486 103.656 ;
    END
  END a_d[82]
  PIN a_d[83]
    DIRECTION OUTPUT ;
    USE SIGNAL ;
    PORT
      LAYER M5 ;
        RECT  9.552 103.572 9.576 103.656 ;
    END
  END a_d[83]
  PIN a_d[84]
    DIRECTION OUTPUT ;
    USE SIGNAL ;
    PORT
      LAYER M3 ;
        RECT  9.648 103.618 9.666 103.656 ;
    END
  END a_d[84]
  PIN a_d[85]
    DIRECTION OUTPUT ;
    USE SIGNAL ;
    PORT
      LAYER M5 ;
        RECT  9.744 103.572 9.768 103.656 ;
    END
  END a_d[85]
  PIN a_d[86]
    DIRECTION OUTPUT ;
    USE SIGNAL ;
    PORT
      LAYER M3 ;
        RECT  9.864 103.618 9.882 103.656 ;
    END
  END a_d[86]
  PIN a_d[87]
    DIRECTION OUTPUT ;
    USE SIGNAL ;
    PORT
      LAYER M5 ;
        RECT  9.936 103.572 9.96 103.656 ;
    END
  END a_d[87]
  PIN a_d[88]
    DIRECTION OUTPUT ;
    USE SIGNAL ;
    PORT
      LAYER M3 ;
        RECT  10.044 103.618 10.062 103.656 ;
    END
  END a_d[88]
  PIN a_d[89]
    DIRECTION OUTPUT ;
    USE SIGNAL ;
    PORT
      LAYER M5 ;
        RECT  10.128 103.572 10.152 103.656 ;
    END
  END a_d[89]
  PIN a_d[8]
    DIRECTION OUTPUT ;
    USE SIGNAL ;
    PORT
      LAYER M3 ;
        RECT  2.232 103.618 2.25 103.656 ;
    END
  END a_d[8]
  PIN a_d[90]
    DIRECTION OUTPUT ;
    USE SIGNAL ;
    PORT
      LAYER M3 ;
        RECT  10.26 103.618 10.278 103.656 ;
    END
  END a_d[90]
  PIN a_d[91]
    DIRECTION OUTPUT ;
    USE SIGNAL ;
    PORT
      LAYER M5 ;
        RECT  10.368 103.572 10.392 103.656 ;
    END
  END a_d[91]
  PIN a_d[92]
    DIRECTION OUTPUT ;
    USE SIGNAL ;
    PORT
      LAYER M3 ;
        RECT  10.44 103.618 10.458 103.656 ;
    END
  END a_d[92]
  PIN a_d[93]
    DIRECTION OUTPUT ;
    USE SIGNAL ;
    PORT
      LAYER M5 ;
        RECT  10.56 103.572 10.584 103.656 ;
    END
  END a_d[93]
  PIN a_d[94]
    DIRECTION OUTPUT ;
    USE SIGNAL ;
    PORT
      LAYER M3 ;
        RECT  10.656 103.618 10.674 103.656 ;
    END
  END a_d[94]
  PIN a_d[95]
    DIRECTION OUTPUT ;
    USE SIGNAL ;
    PORT
      LAYER M5 ;
        RECT  10.752 103.572 10.776 103.656 ;
    END
  END a_d[95]
  PIN a_d[96]
    DIRECTION OUTPUT ;
    USE SIGNAL ;
    PORT
      LAYER M3 ;
        RECT  10.836 103.618 10.854 103.656 ;
    END
  END a_d[96]
  PIN a_d[97]
    DIRECTION OUTPUT ;
    USE SIGNAL ;
    PORT
      LAYER M5 ;
        RECT  10.944 103.572 10.968 103.656 ;
    END
  END a_d[97]
  PIN a_d[98]
    DIRECTION OUTPUT ;
    USE SIGNAL ;
    PORT
      LAYER M3 ;
        RECT  11.052 103.618 11.07 103.656 ;
    END
  END a_d[98]
  PIN a_d[99]
    DIRECTION OUTPUT ;
    USE SIGNAL ;
    PORT
      LAYER M5 ;
        RECT  11.136 103.572 11.16 103.656 ;
    END
  END a_d[99]
  PIN a_d[9]
    DIRECTION OUTPUT ;
    USE SIGNAL ;
    PORT
      LAYER M5 ;
        RECT  2.304 103.572 2.328 103.656 ;
    END
  END a_d[9]
  PIN b_d[0]
    DIRECTION INPUT ;
    USE SIGNAL ;
    PORT
      LAYER M3 ;
        RECT  0.756 0 0.774 0.038 ;
    END
  END b_d[0]
  PIN b_d[100]
    DIRECTION INPUT ;
    USE SIGNAL ;
    PORT
      LAYER M3 ;
        RECT  10.512 0 10.53 0.038 ;
    END
  END b_d[100]
  PIN b_d[101]
    DIRECTION INPUT ;
    USE SIGNAL ;
    PORT
      LAYER M5 ;
        RECT  10.608 0 10.632 0.084 ;
    END
  END b_d[101]
  PIN b_d[102]
    DIRECTION INPUT ;
    USE SIGNAL ;
    PORT
      LAYER M3 ;
        RECT  10.692 0 10.71 0.038 ;
    END
  END b_d[102]
  PIN b_d[103]
    DIRECTION INPUT ;
    USE SIGNAL ;
    PORT
      LAYER M5 ;
        RECT  10.8 0 10.824 0.084 ;
    END
  END b_d[103]
  PIN b_d[104]
    DIRECTION INPUT ;
    USE SIGNAL ;
    PORT
      LAYER M3 ;
        RECT  10.908 0 10.926 0.038 ;
    END
  END b_d[104]
  PIN b_d[105]
    DIRECTION INPUT ;
    USE SIGNAL ;
    PORT
      LAYER M5 ;
        RECT  10.992 0 11.016 0.084 ;
    END
  END b_d[105]
  PIN b_d[106]
    DIRECTION INPUT ;
    USE SIGNAL ;
    PORT
      LAYER M3 ;
        RECT  11.088 0 11.106 0.038 ;
    END
  END b_d[106]
  PIN b_d[107]
    DIRECTION INPUT ;
    USE SIGNAL ;
    PORT
      LAYER M5 ;
        RECT  11.184 0 11.208 0.084 ;
    END
  END b_d[107]
  PIN b_d[108]
    DIRECTION INPUT ;
    USE SIGNAL ;
    PORT
      LAYER M3 ;
        RECT  11.268 0 11.286 0.038 ;
    END
  END b_d[108]
  PIN b_d[109]
    DIRECTION INPUT ;
    USE SIGNAL ;
    PORT
      LAYER M5 ;
        RECT  11.376 0 11.4 0.084 ;
    END
  END b_d[109]
  PIN b_d[10]
    DIRECTION INPUT ;
    USE SIGNAL ;
    PORT
      LAYER M3 ;
        RECT  1.728 0 1.746 0.038 ;
    END
  END b_d[10]
  PIN b_d[110]
    DIRECTION INPUT ;
    USE SIGNAL ;
    PORT
      LAYER M3 ;
        RECT  11.484 0 11.502 0.038 ;
    END
  END b_d[110]
  PIN b_d[111]
    DIRECTION INPUT ;
    USE SIGNAL ;
    PORT
      LAYER M5 ;
        RECT  11.568 0 11.592 0.084 ;
    END
  END b_d[111]
  PIN b_d[112]
    DIRECTION INPUT ;
    USE SIGNAL ;
    PORT
      LAYER M3 ;
        RECT  11.664 0 11.682 0.038 ;
    END
  END b_d[112]
  PIN b_d[113]
    DIRECTION INPUT ;
    USE SIGNAL ;
    PORT
      LAYER M5 ;
        RECT  11.76 0 11.784 0.084 ;
    END
  END b_d[113]
  PIN b_d[114]
    DIRECTION INPUT ;
    USE SIGNAL ;
    PORT
      LAYER M3 ;
        RECT  11.88 0 11.898 0.038 ;
    END
  END b_d[114]
  PIN b_d[115]
    DIRECTION INPUT ;
    USE SIGNAL ;
    PORT
      LAYER M5 ;
        RECT  11.952 0 11.976 0.084 ;
    END
  END b_d[115]
  PIN b_d[116]
    DIRECTION INPUT ;
    USE SIGNAL ;
    PORT
      LAYER M3 ;
        RECT  12.06 0 12.078 0.038 ;
    END
  END b_d[116]
  PIN b_d[117]
    DIRECTION INPUT ;
    USE SIGNAL ;
    PORT
      LAYER M5 ;
        RECT  12.144 0 12.168 0.084 ;
    END
  END b_d[117]
  PIN b_d[118]
    DIRECTION INPUT ;
    USE SIGNAL ;
    PORT
      LAYER M3 ;
        RECT  12.24 0 12.258 0.038 ;
    END
  END b_d[118]
  PIN b_d[119]
    DIRECTION INPUT ;
    USE SIGNAL ;
    PORT
      LAYER M5 ;
        RECT  12.336 0 12.36 0.084 ;
    END
  END b_d[119]
  PIN b_d[11]
    DIRECTION INPUT ;
    USE SIGNAL ;
    PORT
      LAYER M5 ;
        RECT  1.824 0 1.848 0.084 ;
    END
  END b_d[11]
  PIN b_d[120]
    DIRECTION INPUT ;
    USE SIGNAL ;
    PORT
      LAYER M3 ;
        RECT  12.456 0 12.474 0.038 ;
    END
  END b_d[120]
  PIN b_d[121]
    DIRECTION INPUT ;
    USE SIGNAL ;
    PORT
      LAYER M5 ;
        RECT  12.528 0 12.552 0.084 ;
    END
  END b_d[121]
  PIN b_d[122]
    DIRECTION INPUT ;
    USE SIGNAL ;
    PORT
      LAYER M3 ;
        RECT  12.636 0 12.654 0.038 ;
    END
  END b_d[122]
  PIN b_d[123]
    DIRECTION INPUT ;
    USE SIGNAL ;
    PORT
      LAYER M5 ;
        RECT  12.72 0 12.744 0.084 ;
    END
  END b_d[123]
  PIN b_d[124]
    DIRECTION INPUT ;
    USE SIGNAL ;
    PORT
      LAYER M3 ;
        RECT  12.852 0 12.87 0.038 ;
    END
  END b_d[124]
  PIN b_d[125]
    DIRECTION INPUT ;
    USE SIGNAL ;
    PORT
      LAYER M5 ;
        RECT  12.912 0 12.936 0.084 ;
    END
  END b_d[125]
  PIN b_d[126]
    DIRECTION INPUT ;
    USE SIGNAL ;
    PORT
      LAYER M3 ;
        RECT  13.032 0 13.05 0.038 ;
    END
  END b_d[126]
  PIN b_d[127]
    DIRECTION INPUT ;
    USE SIGNAL ;
    PORT
      LAYER M5 ;
        RECT  13.104 0 13.128 0.084 ;
    END
  END b_d[127]
  PIN b_d[128]
    DIRECTION INPUT ;
    USE SIGNAL ;
    PORT
      LAYER M3 ;
        RECT  13.212 0 13.23 0.038 ;
    END
  END b_d[128]
  PIN b_d[129]
    DIRECTION INPUT ;
    USE SIGNAL ;
    PORT
      LAYER M5 ;
        RECT  13.344 0 13.368 0.084 ;
    END
  END b_d[129]
  PIN b_d[12]
    DIRECTION INPUT ;
    USE SIGNAL ;
    PORT
      LAYER M3 ;
        RECT  1.944 0 1.962 0.038 ;
    END
  END b_d[12]
  PIN b_d[130]
    DIRECTION INPUT ;
    USE SIGNAL ;
    PORT
      LAYER M3 ;
        RECT  13.428 0 13.446 0.038 ;
    END
  END b_d[130]
  PIN b_d[131]
    DIRECTION INPUT ;
    USE SIGNAL ;
    PORT
      LAYER M5 ;
        RECT  13.536 0 13.56 0.084 ;
    END
  END b_d[131]
  PIN b_d[132]
    DIRECTION INPUT ;
    USE SIGNAL ;
    PORT
      LAYER M3 ;
        RECT  13.608 0 13.626 0.038 ;
    END
  END b_d[132]
  PIN b_d[133]
    DIRECTION INPUT ;
    USE SIGNAL ;
    PORT
      LAYER M5 ;
        RECT  13.728 0 13.752 0.084 ;
    END
  END b_d[133]
  PIN b_d[134]
    DIRECTION INPUT ;
    USE SIGNAL ;
    PORT
      LAYER M3 ;
        RECT  13.824 0 13.842 0.038 ;
    END
  END b_d[134]
  PIN b_d[135]
    DIRECTION INPUT ;
    USE SIGNAL ;
    PORT
      LAYER M5 ;
        RECT  13.92 0 13.944 0.084 ;
    END
  END b_d[135]
  PIN b_d[136]
    DIRECTION INPUT ;
    USE SIGNAL ;
    PORT
      LAYER M3 ;
        RECT  14.004 0 14.022 0.038 ;
    END
  END b_d[136]
  PIN b_d[137]
    DIRECTION INPUT ;
    USE SIGNAL ;
    PORT
      LAYER M5 ;
        RECT  14.112 0 14.136 0.084 ;
    END
  END b_d[137]
  PIN b_d[138]
    DIRECTION INPUT ;
    USE SIGNAL ;
    PORT
      LAYER M3 ;
        RECT  14.184 0 14.202 0.038 ;
    END
  END b_d[138]
  PIN b_d[139]
    DIRECTION INPUT ;
    USE SIGNAL ;
    PORT
      LAYER M5 ;
        RECT  14.304 0 14.328 0.084 ;
    END
  END b_d[139]
  PIN b_d[13]
    DIRECTION INPUT ;
    USE SIGNAL ;
    PORT
      LAYER M5 ;
        RECT  2.016 0 2.04 0.084 ;
    END
  END b_d[13]
  PIN b_d[140]
    DIRECTION INPUT ;
    USE SIGNAL ;
    PORT
      LAYER M3 ;
        RECT  14.4 0 14.418 0.038 ;
    END
  END b_d[140]
  PIN b_d[141]
    DIRECTION INPUT ;
    USE SIGNAL ;
    PORT
      LAYER M5 ;
        RECT  14.496 0 14.52 0.084 ;
    END
  END b_d[141]
  PIN b_d[142]
    DIRECTION INPUT ;
    USE SIGNAL ;
    PORT
      LAYER M3 ;
        RECT  14.58 0 14.598 0.038 ;
    END
  END b_d[142]
  PIN b_d[143]
    DIRECTION INPUT ;
    USE SIGNAL ;
    PORT
      LAYER M5 ;
        RECT  14.688 0 14.712 0.084 ;
    END
  END b_d[143]
  PIN b_d[144]
    DIRECTION INPUT ;
    USE SIGNAL ;
    PORT
      LAYER M3 ;
        RECT  14.796 0 14.814 0.038 ;
    END
  END b_d[144]
  PIN b_d[145]
    DIRECTION INPUT ;
    USE SIGNAL ;
    PORT
      LAYER M5 ;
        RECT  14.88 0 14.904 0.084 ;
    END
  END b_d[145]
  PIN b_d[146]
    DIRECTION INPUT ;
    USE SIGNAL ;
    PORT
      LAYER M3 ;
        RECT  14.976 0 14.994 0.038 ;
    END
  END b_d[146]
  PIN b_d[147]
    DIRECTION INPUT ;
    USE SIGNAL ;
    PORT
      LAYER M5 ;
        RECT  15.072 0 15.096 0.084 ;
    END
  END b_d[147]
  PIN b_d[148]
    DIRECTION INPUT ;
    USE SIGNAL ;
    PORT
      LAYER M3 ;
        RECT  15.156 0 15.174 0.038 ;
    END
  END b_d[148]
  PIN b_d[149]
    DIRECTION INPUT ;
    USE SIGNAL ;
    PORT
      LAYER M5 ;
        RECT  15.264 0 15.288 0.084 ;
    END
  END b_d[149]
  PIN b_d[14]
    DIRECTION INPUT ;
    USE SIGNAL ;
    PORT
      LAYER M3 ;
        RECT  2.124 0 2.142 0.038 ;
    END
  END b_d[14]
  PIN b_d[150]
    DIRECTION INPUT ;
    USE SIGNAL ;
    PORT
      LAYER M3 ;
        RECT  15.372 0 15.39 0.038 ;
    END
  END b_d[150]
  PIN b_d[151]
    DIRECTION INPUT ;
    USE SIGNAL ;
    PORT
      LAYER M5 ;
        RECT  15.456 0 15.48 0.084 ;
    END
  END b_d[151]
  PIN b_d[152]
    DIRECTION INPUT ;
    USE SIGNAL ;
    PORT
      LAYER M3 ;
        RECT  15.552 0 15.57 0.038 ;
    END
  END b_d[152]
  PIN b_d[153]
    DIRECTION INPUT ;
    USE SIGNAL ;
    PORT
      LAYER M5 ;
        RECT  15.648 0 15.672 0.084 ;
    END
  END b_d[153]
  PIN b_d[154]
    DIRECTION INPUT ;
    USE SIGNAL ;
    PORT
      LAYER M3 ;
        RECT  15.768 0 15.786 0.038 ;
    END
  END b_d[154]
  PIN b_d[155]
    DIRECTION INPUT ;
    USE SIGNAL ;
    PORT
      LAYER M5 ;
        RECT  15.84 0 15.864 0.084 ;
    END
  END b_d[155]
  PIN b_d[156]
    DIRECTION INPUT ;
    USE SIGNAL ;
    PORT
      LAYER M3 ;
        RECT  15.948 0 15.966 0.038 ;
    END
  END b_d[156]
  PIN b_d[157]
    DIRECTION INPUT ;
    USE SIGNAL ;
    PORT
      LAYER M5 ;
        RECT  16.032 0 16.056 0.084 ;
    END
  END b_d[157]
  PIN b_d[158]
    DIRECTION INPUT ;
    USE SIGNAL ;
    PORT
      LAYER M3 ;
        RECT  16.128 0 16.146 0.038 ;
    END
  END b_d[158]
  PIN b_d[159]
    DIRECTION INPUT ;
    USE SIGNAL ;
    PORT
      LAYER M5 ;
        RECT  16.224 0 16.248 0.084 ;
    END
  END b_d[159]
  PIN b_d[15]
    DIRECTION INPUT ;
    USE SIGNAL ;
    PORT
      LAYER M5 ;
        RECT  2.208 0 2.232 0.084 ;
    END
  END b_d[15]
  PIN b_d[160]
    DIRECTION INPUT ;
    USE SIGNAL ;
    PORT
      LAYER M3 ;
        RECT  16.344 0 16.362 0.038 ;
    END
  END b_d[160]
  PIN b_d[161]
    DIRECTION INPUT ;
    USE SIGNAL ;
    PORT
      LAYER M5 ;
        RECT  16.416 0 16.44 0.084 ;
    END
  END b_d[161]
  PIN b_d[162]
    DIRECTION INPUT ;
    USE SIGNAL ;
    PORT
      LAYER M3 ;
        RECT  16.524 0 16.542 0.038 ;
    END
  END b_d[162]
  PIN b_d[163]
    DIRECTION INPUT ;
    USE SIGNAL ;
    PORT
      LAYER M5 ;
        RECT  16.608 0 16.632 0.084 ;
    END
  END b_d[163]
  PIN b_d[164]
    DIRECTION INPUT ;
    USE SIGNAL ;
    PORT
      LAYER M3 ;
        RECT  16.74 0 16.758 0.038 ;
    END
  END b_d[164]
  PIN b_d[165]
    DIRECTION INPUT ;
    USE SIGNAL ;
    PORT
      LAYER M5 ;
        RECT  16.848 0 16.872 0.084 ;
    END
  END b_d[165]
  PIN b_d[166]
    DIRECTION INPUT ;
    USE SIGNAL ;
    PORT
      LAYER M3 ;
        RECT  16.92 0 16.938 0.038 ;
    END
  END b_d[166]
  PIN b_d[167]
    DIRECTION INPUT ;
    USE SIGNAL ;
    PORT
      LAYER M5 ;
        RECT  17.04 0 17.064 0.084 ;
    END
  END b_d[167]
  PIN b_d[168]
    DIRECTION INPUT ;
    USE SIGNAL ;
    PORT
      LAYER M3 ;
        RECT  17.136 0 17.154 0.038 ;
    END
  END b_d[168]
  PIN b_d[169]
    DIRECTION INPUT ;
    USE SIGNAL ;
    PORT
      LAYER M5 ;
        RECT  17.232 0 17.256 0.084 ;
    END
  END b_d[169]
  PIN b_d[16]
    DIRECTION INPUT ;
    USE SIGNAL ;
    PORT
      LAYER M3 ;
        RECT  2.34 0 2.358 0.038 ;
    END
  END b_d[16]
  PIN b_d[170]
    DIRECTION INPUT ;
    USE SIGNAL ;
    PORT
      LAYER M3 ;
        RECT  17.316 0 17.334 0.038 ;
    END
  END b_d[170]
  PIN b_d[171]
    DIRECTION INPUT ;
    USE SIGNAL ;
    PORT
      LAYER M5 ;
        RECT  17.424 0 17.448 0.084 ;
    END
  END b_d[171]
  PIN b_d[172]
    DIRECTION INPUT ;
    USE SIGNAL ;
    PORT
      LAYER M3 ;
        RECT  17.496 0 17.514 0.038 ;
    END
  END b_d[172]
  PIN b_d[173]
    DIRECTION INPUT ;
    USE SIGNAL ;
    PORT
      LAYER M5 ;
        RECT  17.616 0 17.64 0.084 ;
    END
  END b_d[173]
  PIN b_d[174]
    DIRECTION INPUT ;
    USE SIGNAL ;
    PORT
      LAYER M3 ;
        RECT  17.712 0 17.73 0.038 ;
    END
  END b_d[174]
  PIN b_d[175]
    DIRECTION INPUT ;
    USE SIGNAL ;
    PORT
      LAYER M5 ;
        RECT  17.808 0 17.832 0.084 ;
    END
  END b_d[175]
  PIN b_d[176]
    DIRECTION INPUT ;
    USE SIGNAL ;
    PORT
      LAYER M3 ;
        RECT  17.892 0 17.91 0.038 ;
    END
  END b_d[176]
  PIN b_d[177]
    DIRECTION INPUT ;
    USE SIGNAL ;
    PORT
      LAYER M5 ;
        RECT  18 0 18.024 0.084 ;
    END
  END b_d[177]
  PIN b_d[178]
    DIRECTION INPUT ;
    USE SIGNAL ;
    PORT
      LAYER M3 ;
        RECT  18.108 0 18.126 0.038 ;
    END
  END b_d[178]
  PIN b_d[179]
    DIRECTION INPUT ;
    USE SIGNAL ;
    PORT
      LAYER M5 ;
        RECT  18.192 0 18.216 0.084 ;
    END
  END b_d[179]
  PIN b_d[17]
    DIRECTION INPUT ;
    USE SIGNAL ;
    PORT
      LAYER M5 ;
        RECT  2.4 0 2.424 0.084 ;
    END
  END b_d[17]
  PIN b_d[180]
    DIRECTION INPUT ;
    USE SIGNAL ;
    PORT
      LAYER M3 ;
        RECT  18.288 0 18.306 0.038 ;
    END
  END b_d[180]
  PIN b_d[181]
    DIRECTION INPUT ;
    USE SIGNAL ;
    PORT
      LAYER M5 ;
        RECT  18.384 0 18.408 0.084 ;
    END
  END b_d[181]
  PIN b_d[182]
    DIRECTION INPUT ;
    USE SIGNAL ;
    PORT
      LAYER M3 ;
        RECT  18.468 0 18.486 0.038 ;
    END
  END b_d[182]
  PIN b_d[183]
    DIRECTION INPUT ;
    USE SIGNAL ;
    PORT
      LAYER M5 ;
        RECT  18.576 0 18.6 0.084 ;
    END
  END b_d[183]
  PIN b_d[184]
    DIRECTION INPUT ;
    USE SIGNAL ;
    PORT
      LAYER M3 ;
        RECT  18.684 0 18.702 0.038 ;
    END
  END b_d[184]
  PIN b_d[185]
    DIRECTION INPUT ;
    USE SIGNAL ;
    PORT
      LAYER M5 ;
        RECT  18.768 0 18.792 0.084 ;
    END
  END b_d[185]
  PIN b_d[186]
    DIRECTION INPUT ;
    USE SIGNAL ;
    PORT
      LAYER M3 ;
        RECT  18.864 0 18.882 0.038 ;
    END
  END b_d[186]
  PIN b_d[187]
    DIRECTION INPUT ;
    USE SIGNAL ;
    PORT
      LAYER M5 ;
        RECT  18.96 0 18.984 0.084 ;
    END
  END b_d[187]
  PIN b_d[188]
    DIRECTION INPUT ;
    USE SIGNAL ;
    PORT
      LAYER M3 ;
        RECT  19.08 0 19.098 0.038 ;
    END
  END b_d[188]
  PIN b_d[189]
    DIRECTION INPUT ;
    USE SIGNAL ;
    PORT
      LAYER M5 ;
        RECT  19.152 0 19.176 0.084 ;
    END
  END b_d[189]
  PIN b_d[18]
    DIRECTION INPUT ;
    USE SIGNAL ;
    PORT
      LAYER M3 ;
        RECT  2.52 0 2.538 0.038 ;
    END
  END b_d[18]
  PIN b_d[190]
    DIRECTION INPUT ;
    USE SIGNAL ;
    PORT
      LAYER M3 ;
        RECT  19.26 0 19.278 0.038 ;
    END
  END b_d[190]
  PIN b_d[191]
    DIRECTION INPUT ;
    USE SIGNAL ;
    PORT
      LAYER M5 ;
        RECT  19.344 0 19.368 0.084 ;
    END
  END b_d[191]
  PIN b_d[192]
    DIRECTION INPUT ;
    USE SIGNAL ;
    PORT
      LAYER M3 ;
        RECT  19.44 0 19.458 0.038 ;
    END
  END b_d[192]
  PIN b_d[193]
    DIRECTION INPUT ;
    USE SIGNAL ;
    PORT
      LAYER M5 ;
        RECT  19.536 0 19.56 0.084 ;
    END
  END b_d[193]
  PIN b_d[194]
    DIRECTION INPUT ;
    USE SIGNAL ;
    PORT
      LAYER M3 ;
        RECT  19.656 0 19.674 0.038 ;
    END
  END b_d[194]
  PIN b_d[195]
    DIRECTION INPUT ;
    USE SIGNAL ;
    PORT
      LAYER M5 ;
        RECT  19.728 0 19.752 0.084 ;
    END
  END b_d[195]
  PIN b_d[196]
    DIRECTION INPUT ;
    USE SIGNAL ;
    PORT
      LAYER M3 ;
        RECT  19.836 0 19.854 0.038 ;
    END
  END b_d[196]
  PIN b_d[197]
    DIRECTION INPUT ;
    USE SIGNAL ;
    PORT
      LAYER M5 ;
        RECT  19.92 0 19.944 0.084 ;
    END
  END b_d[197]
  PIN b_d[198]
    DIRECTION INPUT ;
    USE SIGNAL ;
    PORT
      LAYER M3 ;
        RECT  20.052 0 20.07 0.038 ;
    END
  END b_d[198]
  PIN b_d[199]
    DIRECTION INPUT ;
    USE SIGNAL ;
    PORT
      LAYER M5 ;
        RECT  20.112 0 20.136 0.084 ;
    END
  END b_d[199]
  PIN b_d[19]
    DIRECTION INPUT ;
    USE SIGNAL ;
    PORT
      LAYER M5 ;
        RECT  2.64 0 2.664 0.084 ;
    END
  END b_d[19]
  PIN b_d[1]
    DIRECTION INPUT ;
    USE SIGNAL ;
    PORT
      LAYER M5 ;
        RECT  0.864 0 0.888 0.084 ;
    END
  END b_d[1]
  PIN b_d[200]
    DIRECTION INPUT ;
    USE SIGNAL ;
    PORT
      LAYER M3 ;
        RECT  20.232 0 20.25 0.038 ;
    END
  END b_d[200]
  PIN b_d[201]
    DIRECTION INPUT ;
    USE SIGNAL ;
    PORT
      LAYER M5 ;
        RECT  20.304 0 20.328 0.084 ;
    END
  END b_d[201]
  PIN b_d[202]
    DIRECTION INPUT ;
    USE SIGNAL ;
    PORT
      LAYER M3 ;
        RECT  20.412 0 20.43 0.038 ;
    END
  END b_d[202]
  PIN b_d[203]
    DIRECTION INPUT ;
    USE SIGNAL ;
    PORT
      LAYER M5 ;
        RECT  20.544 0 20.568 0.084 ;
    END
  END b_d[203]
  PIN b_d[204]
    DIRECTION INPUT ;
    USE SIGNAL ;
    PORT
      LAYER M3 ;
        RECT  20.628 0 20.646 0.038 ;
    END
  END b_d[204]
  PIN b_d[205]
    DIRECTION INPUT ;
    USE SIGNAL ;
    PORT
      LAYER M5 ;
        RECT  20.736 0 20.76 0.084 ;
    END
  END b_d[205]
  PIN b_d[206]
    DIRECTION INPUT ;
    USE SIGNAL ;
    PORT
      LAYER M3 ;
        RECT  20.808 0 20.826 0.038 ;
    END
  END b_d[206]
  PIN b_d[207]
    DIRECTION INPUT ;
    USE SIGNAL ;
    PORT
      LAYER M5 ;
        RECT  20.928 0 20.952 0.084 ;
    END
  END b_d[207]
  PIN b_d[208]
    DIRECTION INPUT ;
    USE SIGNAL ;
    PORT
      LAYER M3 ;
        RECT  21.024 0 21.042 0.038 ;
    END
  END b_d[208]
  PIN b_d[209]
    DIRECTION INPUT ;
    USE SIGNAL ;
    PORT
      LAYER M5 ;
        RECT  21.12 0 21.144 0.084 ;
    END
  END b_d[209]
  PIN b_d[20]
    DIRECTION INPUT ;
    USE SIGNAL ;
    PORT
      LAYER M3 ;
        RECT  2.736 0 2.754 0.038 ;
    END
  END b_d[20]
  PIN b_d[210]
    DIRECTION INPUT ;
    USE SIGNAL ;
    PORT
      LAYER M3 ;
        RECT  21.204 0 21.222 0.038 ;
    END
  END b_d[210]
  PIN b_d[211]
    DIRECTION INPUT ;
    USE SIGNAL ;
    PORT
      LAYER M5 ;
        RECT  21.312 0 21.336 0.084 ;
    END
  END b_d[211]
  PIN b_d[212]
    DIRECTION INPUT ;
    USE SIGNAL ;
    PORT
      LAYER M3 ;
        RECT  21.384 0 21.402 0.038 ;
    END
  END b_d[212]
  PIN b_d[213]
    DIRECTION INPUT ;
    USE SIGNAL ;
    PORT
      LAYER M5 ;
        RECT  21.504 0 21.528 0.084 ;
    END
  END b_d[213]
  PIN b_d[214]
    DIRECTION INPUT ;
    USE SIGNAL ;
    PORT
      LAYER M3 ;
        RECT  21.6 0 21.618 0.038 ;
    END
  END b_d[214]
  PIN b_d[215]
    DIRECTION INPUT ;
    USE SIGNAL ;
    PORT
      LAYER M5 ;
        RECT  21.696 0 21.72 0.084 ;
    END
  END b_d[215]
  PIN b_d[216]
    DIRECTION INPUT ;
    USE SIGNAL ;
    PORT
      LAYER M3 ;
        RECT  21.78 0 21.798 0.038 ;
    END
  END b_d[216]
  PIN b_d[217]
    DIRECTION INPUT ;
    USE SIGNAL ;
    PORT
      LAYER M5 ;
        RECT  21.888 0 21.912 0.084 ;
    END
  END b_d[217]
  PIN b_d[218]
    DIRECTION INPUT ;
    USE SIGNAL ;
    PORT
      LAYER M3 ;
        RECT  21.996 0 22.014 0.038 ;
    END
  END b_d[218]
  PIN b_d[219]
    DIRECTION INPUT ;
    USE SIGNAL ;
    PORT
      LAYER M5 ;
        RECT  22.08 0 22.104 0.084 ;
    END
  END b_d[219]
  PIN b_d[21]
    DIRECTION INPUT ;
    USE SIGNAL ;
    PORT
      LAYER M5 ;
        RECT  2.832 0 2.856 0.084 ;
    END
  END b_d[21]
  PIN b_d[220]
    DIRECTION INPUT ;
    USE SIGNAL ;
    PORT
      LAYER M3 ;
        RECT  22.176 0 22.194 0.038 ;
    END
  END b_d[220]
  PIN b_d[221]
    DIRECTION INPUT ;
    USE SIGNAL ;
    PORT
      LAYER M5 ;
        RECT  22.272 0 22.296 0.084 ;
    END
  END b_d[221]
  PIN b_d[222]
    DIRECTION INPUT ;
    USE SIGNAL ;
    PORT
      LAYER M3 ;
        RECT  22.356 0 22.374 0.038 ;
    END
  END b_d[222]
  PIN b_d[223]
    DIRECTION INPUT ;
    USE SIGNAL ;
    PORT
      LAYER M5 ;
        RECT  22.464 0 22.488 0.084 ;
    END
  END b_d[223]
  PIN b_d[224]
    DIRECTION INPUT ;
    USE SIGNAL ;
    PORT
      LAYER M3 ;
        RECT  22.572 0 22.59 0.038 ;
    END
  END b_d[224]
  PIN b_d[225]
    DIRECTION INPUT ;
    USE SIGNAL ;
    PORT
      LAYER M5 ;
        RECT  22.656 0 22.68 0.084 ;
    END
  END b_d[225]
  PIN b_d[226]
    DIRECTION INPUT ;
    USE SIGNAL ;
    PORT
      LAYER M3 ;
        RECT  22.752 0 22.77 0.038 ;
    END
  END b_d[226]
  PIN b_d[227]
    DIRECTION INPUT ;
    USE SIGNAL ;
    PORT
      LAYER M5 ;
        RECT  22.848 0 22.872 0.084 ;
    END
  END b_d[227]
  PIN b_d[228]
    DIRECTION INPUT ;
    USE SIGNAL ;
    PORT
      LAYER M3 ;
        RECT  22.968 0 22.986 0.038 ;
    END
  END b_d[228]
  PIN b_d[229]
    DIRECTION INPUT ;
    USE SIGNAL ;
    PORT
      LAYER M5 ;
        RECT  23.04 0 23.064 0.084 ;
    END
  END b_d[229]
  PIN b_d[22]
    DIRECTION INPUT ;
    USE SIGNAL ;
    PORT
      LAYER M3 ;
        RECT  2.916 0 2.934 0.038 ;
    END
  END b_d[22]
  PIN b_d[230]
    DIRECTION INPUT ;
    USE SIGNAL ;
    PORT
      LAYER M3 ;
        RECT  23.148 0 23.166 0.038 ;
    END
  END b_d[230]
  PIN b_d[231]
    DIRECTION INPUT ;
    USE SIGNAL ;
    PORT
      LAYER M5 ;
        RECT  23.232 0 23.256 0.084 ;
    END
  END b_d[231]
  PIN b_d[232]
    DIRECTION INPUT ;
    USE SIGNAL ;
    PORT
      LAYER M3 ;
        RECT  23.364 0 23.382 0.038 ;
    END
  END b_d[232]
  PIN b_d[233]
    DIRECTION INPUT ;
    USE SIGNAL ;
    PORT
      LAYER M5 ;
        RECT  23.424 0 23.448 0.084 ;
    END
  END b_d[233]
  PIN b_d[234]
    DIRECTION INPUT ;
    USE SIGNAL ;
    PORT
      LAYER M3 ;
        RECT  23.544 0 23.562 0.038 ;
    END
  END b_d[234]
  PIN b_d[235]
    DIRECTION INPUT ;
    USE SIGNAL ;
    PORT
      LAYER M5 ;
        RECT  23.616 0 23.64 0.084 ;
    END
  END b_d[235]
  PIN b_d[236]
    DIRECTION INPUT ;
    USE SIGNAL ;
    PORT
      LAYER M3 ;
        RECT  23.724 0 23.742 0.038 ;
    END
  END b_d[236]
  PIN b_d[237]
    DIRECTION INPUT ;
    USE SIGNAL ;
    PORT
      LAYER M5 ;
        RECT  23.808 0 23.832 0.084 ;
    END
  END b_d[237]
  PIN b_d[238]
    DIRECTION INPUT ;
    USE SIGNAL ;
    PORT
      LAYER M3 ;
        RECT  23.94 0 23.958 0.038 ;
    END
  END b_d[238]
  PIN b_d[239]
    DIRECTION INPUT ;
    USE SIGNAL ;
    PORT
      LAYER M5 ;
        RECT  24.048 0 24.072 0.084 ;
    END
  END b_d[239]
  PIN b_d[23]
    DIRECTION INPUT ;
    USE SIGNAL ;
    PORT
      LAYER M5 ;
        RECT  3.024 0 3.048 0.084 ;
    END
  END b_d[23]
  PIN b_d[240]
    DIRECTION INPUT ;
    USE SIGNAL ;
    PORT
      LAYER M3 ;
        RECT  24.12 0 24.138 0.038 ;
    END
  END b_d[240]
  PIN b_d[241]
    DIRECTION INPUT ;
    USE SIGNAL ;
    PORT
      LAYER M5 ;
        RECT  24.24 0 24.264 0.084 ;
    END
  END b_d[241]
  PIN b_d[242]
    DIRECTION INPUT ;
    USE SIGNAL ;
    PORT
      LAYER M3 ;
        RECT  24.336 0 24.354 0.038 ;
    END
  END b_d[242]
  PIN b_d[243]
    DIRECTION INPUT ;
    USE SIGNAL ;
    PORT
      LAYER M5 ;
        RECT  24.432 0 24.456 0.084 ;
    END
  END b_d[243]
  PIN b_d[244]
    DIRECTION INPUT ;
    USE SIGNAL ;
    PORT
      LAYER M3 ;
        RECT  24.516 0 24.534 0.038 ;
    END
  END b_d[244]
  PIN b_d[245]
    DIRECTION INPUT ;
    USE SIGNAL ;
    PORT
      LAYER M5 ;
        RECT  24.624 0 24.648 0.084 ;
    END
  END b_d[245]
  PIN b_d[246]
    DIRECTION INPUT ;
    USE SIGNAL ;
    PORT
      LAYER M3 ;
        RECT  24.696 0 24.714 0.038 ;
    END
  END b_d[246]
  PIN b_d[247]
    DIRECTION INPUT ;
    USE SIGNAL ;
    PORT
      LAYER M5 ;
        RECT  24.816 0 24.84 0.084 ;
    END
  END b_d[247]
  PIN b_d[248]
    DIRECTION INPUT ;
    USE SIGNAL ;
    PORT
      LAYER M3 ;
        RECT  24.912 0 24.93 0.038 ;
    END
  END b_d[248]
  PIN b_d[249]
    DIRECTION INPUT ;
    USE SIGNAL ;
    PORT
      LAYER M5 ;
        RECT  25.008 0 25.032 0.084 ;
    END
  END b_d[249]
  PIN b_d[24]
    DIRECTION INPUT ;
    USE SIGNAL ;
    PORT
      LAYER M3 ;
        RECT  3.096 0 3.114 0.038 ;
    END
  END b_d[24]
  PIN b_d[250]
    DIRECTION INPUT ;
    USE SIGNAL ;
    PORT
      LAYER M3 ;
        RECT  25.092 0 25.11 0.038 ;
    END
  END b_d[250]
  PIN b_d[251]
    DIRECTION INPUT ;
    USE SIGNAL ;
    PORT
      LAYER M5 ;
        RECT  25.2 0 25.224 0.084 ;
    END
  END b_d[251]
  PIN b_d[252]
    DIRECTION INPUT ;
    USE SIGNAL ;
    PORT
      LAYER M3 ;
        RECT  25.308 0 25.326 0.038 ;
    END
  END b_d[252]
  PIN b_d[253]
    DIRECTION INPUT ;
    USE SIGNAL ;
    PORT
      LAYER M5 ;
        RECT  25.392 0 25.416 0.084 ;
    END
  END b_d[253]
  PIN b_d[254]
    DIRECTION INPUT ;
    USE SIGNAL ;
    PORT
      LAYER M3 ;
        RECT  25.488 0 25.506 0.038 ;
    END
  END b_d[254]
  PIN b_d[255]
    DIRECTION INPUT ;
    USE SIGNAL ;
    PORT
      LAYER M5 ;
        RECT  25.584 0 25.608 0.084 ;
    END
  END b_d[255]
  PIN b_d[256]
    DIRECTION INPUT ;
    USE SIGNAL ;
    PORT
      LAYER M3 ;
        RECT  25.668 0 25.686 0.038 ;
    END
  END b_d[256]
  PIN b_d[257]
    DIRECTION INPUT ;
    USE SIGNAL ;
    PORT
      LAYER M5 ;
        RECT  25.776 0 25.8 0.084 ;
    END
  END b_d[257]
  PIN b_d[258]
    DIRECTION INPUT ;
    USE SIGNAL ;
    PORT
      LAYER M3 ;
        RECT  25.884 0 25.902 0.038 ;
    END
  END b_d[258]
  PIN b_d[259]
    DIRECTION INPUT ;
    USE SIGNAL ;
    PORT
      LAYER M5 ;
        RECT  25.968 0 25.992 0.084 ;
    END
  END b_d[259]
  PIN b_d[25]
    DIRECTION INPUT ;
    USE SIGNAL ;
    PORT
      LAYER M5 ;
        RECT  3.216 0 3.24 0.084 ;
    END
  END b_d[25]
  PIN b_d[260]
    DIRECTION INPUT ;
    USE SIGNAL ;
    PORT
      LAYER M3 ;
        RECT  26.064 0 26.082 0.038 ;
    END
  END b_d[260]
  PIN b_d[261]
    DIRECTION INPUT ;
    USE SIGNAL ;
    PORT
      LAYER M5 ;
        RECT  26.16 0 26.184 0.084 ;
    END
  END b_d[261]
  PIN b_d[262]
    DIRECTION INPUT ;
    USE SIGNAL ;
    PORT
      LAYER M3 ;
        RECT  26.28 0 26.298 0.038 ;
    END
  END b_d[262]
  PIN b_d[263]
    DIRECTION INPUT ;
    USE SIGNAL ;
    PORT
      LAYER M5 ;
        RECT  26.352 0 26.376 0.084 ;
    END
  END b_d[263]
  PIN b_d[264]
    DIRECTION INPUT ;
    USE SIGNAL ;
    PORT
      LAYER M3 ;
        RECT  26.46 0 26.478 0.038 ;
    END
  END b_d[264]
  PIN b_d[265]
    DIRECTION INPUT ;
    USE SIGNAL ;
    PORT
      LAYER M5 ;
        RECT  26.544 0 26.568 0.084 ;
    END
  END b_d[265]
  PIN b_d[266]
    DIRECTION INPUT ;
    USE SIGNAL ;
    PORT
      LAYER M3 ;
        RECT  26.64 0 26.658 0.038 ;
    END
  END b_d[266]
  PIN b_d[267]
    DIRECTION INPUT ;
    USE SIGNAL ;
    PORT
      LAYER M5 ;
        RECT  26.736 0 26.76 0.084 ;
    END
  END b_d[267]
  PIN b_d[268]
    DIRECTION INPUT ;
    USE SIGNAL ;
    PORT
      LAYER M3 ;
        RECT  26.856 0 26.874 0.038 ;
    END
  END b_d[268]
  PIN b_d[269]
    DIRECTION INPUT ;
    USE SIGNAL ;
    PORT
      LAYER M5 ;
        RECT  26.928 0 26.952 0.084 ;
    END
  END b_d[269]
  PIN b_d[26]
    DIRECTION INPUT ;
    USE SIGNAL ;
    PORT
      LAYER M3 ;
        RECT  3.312 0 3.33 0.038 ;
    END
  END b_d[26]
  PIN b_d[270]
    DIRECTION INPUT ;
    USE SIGNAL ;
    PORT
      LAYER M3 ;
        RECT  27.036 0 27.054 0.038 ;
    END
  END b_d[270]
  PIN b_d[271]
    DIRECTION INPUT ;
    USE SIGNAL ;
    PORT
      LAYER M5 ;
        RECT  27.12 0 27.144 0.084 ;
    END
  END b_d[271]
  PIN b_d[272]
    DIRECTION INPUT ;
    USE SIGNAL ;
    PORT
      LAYER M3 ;
        RECT  27.252 0 27.27 0.038 ;
    END
  END b_d[272]
  PIN b_d[273]
    DIRECTION INPUT ;
    USE SIGNAL ;
    PORT
      LAYER M5 ;
        RECT  27.312 0 27.336 0.084 ;
    END
  END b_d[273]
  PIN b_d[274]
    DIRECTION INPUT ;
    USE SIGNAL ;
    PORT
      LAYER M3 ;
        RECT  27.432 0 27.45 0.038 ;
    END
  END b_d[274]
  PIN b_d[275]
    DIRECTION INPUT ;
    USE SIGNAL ;
    PORT
      LAYER M5 ;
        RECT  27.504 0 27.528 0.084 ;
    END
  END b_d[275]
  PIN b_d[276]
    DIRECTION INPUT ;
    USE SIGNAL ;
    PORT
      LAYER M3 ;
        RECT  27.612 0 27.63 0.038 ;
    END
  END b_d[276]
  PIN b_d[277]
    DIRECTION INPUT ;
    USE SIGNAL ;
    PORT
      LAYER M5 ;
        RECT  27.744 0 27.768 0.084 ;
    END
  END b_d[277]
  PIN b_d[278]
    DIRECTION INPUT ;
    USE SIGNAL ;
    PORT
      LAYER M3 ;
        RECT  27.828 0 27.846 0.038 ;
    END
  END b_d[278]
  PIN b_d[279]
    DIRECTION INPUT ;
    USE SIGNAL ;
    PORT
      LAYER M5 ;
        RECT  27.936 0 27.96 0.084 ;
    END
  END b_d[279]
  PIN b_d[27]
    DIRECTION INPUT ;
    USE SIGNAL ;
    PORT
      LAYER M5 ;
        RECT  3.408 0 3.432 0.084 ;
    END
  END b_d[27]
  PIN b_d[280]
    DIRECTION INPUT ;
    USE SIGNAL ;
    PORT
      LAYER M3 ;
        RECT  28.008 0 28.026 0.038 ;
    END
  END b_d[280]
  PIN b_d[281]
    DIRECTION INPUT ;
    USE SIGNAL ;
    PORT
      LAYER M5 ;
        RECT  28.128 0 28.152 0.084 ;
    END
  END b_d[281]
  PIN b_d[282]
    DIRECTION INPUT ;
    USE SIGNAL ;
    PORT
      LAYER M3 ;
        RECT  28.224 0 28.242 0.038 ;
    END
  END b_d[282]
  PIN b_d[283]
    DIRECTION INPUT ;
    USE SIGNAL ;
    PORT
      LAYER M5 ;
        RECT  28.32 0 28.344 0.084 ;
    END
  END b_d[283]
  PIN b_d[284]
    DIRECTION INPUT ;
    USE SIGNAL ;
    PORT
      LAYER M3 ;
        RECT  28.404 0 28.422 0.038 ;
    END
  END b_d[284]
  PIN b_d[285]
    DIRECTION INPUT ;
    USE SIGNAL ;
    PORT
      LAYER M5 ;
        RECT  28.512 0 28.536 0.084 ;
    END
  END b_d[285]
  PIN b_d[286]
    DIRECTION INPUT ;
    USE SIGNAL ;
    PORT
      LAYER M3 ;
        RECT  28.584 0 28.602 0.038 ;
    END
  END b_d[286]
  PIN b_d[287]
    DIRECTION INPUT ;
    USE SIGNAL ;
    PORT
      LAYER M5 ;
        RECT  28.704 0 28.728 0.084 ;
    END
  END b_d[287]
  PIN b_d[288]
    DIRECTION INPUT ;
    USE SIGNAL ;
    PORT
      LAYER M3 ;
        RECT  28.8 0 28.818 0.038 ;
    END
  END b_d[288]
  PIN b_d[289]
    DIRECTION INPUT ;
    USE SIGNAL ;
    PORT
      LAYER M5 ;
        RECT  28.896 0 28.92 0.084 ;
    END
  END b_d[289]
  PIN b_d[28]
    DIRECTION INPUT ;
    USE SIGNAL ;
    PORT
      LAYER M3 ;
        RECT  3.492 0 3.51 0.038 ;
    END
  END b_d[28]
  PIN b_d[290]
    DIRECTION INPUT ;
    USE SIGNAL ;
    PORT
      LAYER M3 ;
        RECT  28.98 0 28.998 0.038 ;
    END
  END b_d[290]
  PIN b_d[291]
    DIRECTION INPUT ;
    USE SIGNAL ;
    PORT
      LAYER M5 ;
        RECT  29.088 0 29.112 0.084 ;
    END
  END b_d[291]
  PIN b_d[292]
    DIRECTION INPUT ;
    USE SIGNAL ;
    PORT
      LAYER M3 ;
        RECT  29.196 0 29.214 0.038 ;
    END
  END b_d[292]
  PIN b_d[293]
    DIRECTION INPUT ;
    USE SIGNAL ;
    PORT
      LAYER M5 ;
        RECT  29.28 0 29.304 0.084 ;
    END
  END b_d[293]
  PIN b_d[294]
    DIRECTION INPUT ;
    USE SIGNAL ;
    PORT
      LAYER M3 ;
        RECT  29.376 0 29.394 0.038 ;
    END
  END b_d[294]
  PIN b_d[295]
    DIRECTION INPUT ;
    USE SIGNAL ;
    PORT
      LAYER M5 ;
        RECT  29.472 0 29.496 0.084 ;
    END
  END b_d[295]
  PIN b_d[296]
    DIRECTION INPUT ;
    USE SIGNAL ;
    PORT
      LAYER M3 ;
        RECT  29.556 0 29.574 0.038 ;
    END
  END b_d[296]
  PIN b_d[297]
    DIRECTION INPUT ;
    USE SIGNAL ;
    PORT
      LAYER M5 ;
        RECT  29.664 0 29.688 0.084 ;
    END
  END b_d[297]
  PIN b_d[298]
    DIRECTION INPUT ;
    USE SIGNAL ;
    PORT
      LAYER M3 ;
        RECT  29.772 0 29.79 0.038 ;
    END
  END b_d[298]
  PIN b_d[299]
    DIRECTION INPUT ;
    USE SIGNAL ;
    PORT
      LAYER M5 ;
        RECT  29.856 0 29.88 0.084 ;
    END
  END b_d[299]
  PIN b_d[29]
    DIRECTION INPUT ;
    USE SIGNAL ;
    PORT
      LAYER M5 ;
        RECT  3.6 0 3.624 0.084 ;
    END
  END b_d[29]
  PIN b_d[2]
    DIRECTION INPUT ;
    USE SIGNAL ;
    PORT
      LAYER M3 ;
        RECT  0.972 0 0.99 0.038 ;
    END
  END b_d[2]
  PIN b_d[300]
    DIRECTION INPUT ;
    USE SIGNAL ;
    PORT
      LAYER M3 ;
        RECT  29.952 0 29.97 0.038 ;
    END
  END b_d[300]
  PIN b_d[301]
    DIRECTION INPUT ;
    USE SIGNAL ;
    PORT
      LAYER M5 ;
        RECT  30.048 0 30.072 0.084 ;
    END
  END b_d[301]
  PIN b_d[302]
    DIRECTION INPUT ;
    USE SIGNAL ;
    PORT
      LAYER M3 ;
        RECT  30.168 0 30.186 0.038 ;
    END
  END b_d[302]
  PIN b_d[303]
    DIRECTION INPUT ;
    USE SIGNAL ;
    PORT
      LAYER M5 ;
        RECT  30.24 0 30.264 0.084 ;
    END
  END b_d[303]
  PIN b_d[304]
    DIRECTION INPUT ;
    USE SIGNAL ;
    PORT
      LAYER M3 ;
        RECT  30.348 0 30.366 0.038 ;
    END
  END b_d[304]
  PIN b_d[305]
    DIRECTION INPUT ;
    USE SIGNAL ;
    PORT
      LAYER M5 ;
        RECT  30.432 0 30.456 0.084 ;
    END
  END b_d[305]
  PIN b_d[306]
    DIRECTION INPUT ;
    USE SIGNAL ;
    PORT
      LAYER M3 ;
        RECT  30.564 0 30.582 0.038 ;
    END
  END b_d[306]
  PIN b_d[307]
    DIRECTION INPUT ;
    USE SIGNAL ;
    PORT
      LAYER M5 ;
        RECT  30.624 0 30.648 0.084 ;
    END
  END b_d[307]
  PIN b_d[308]
    DIRECTION INPUT ;
    USE SIGNAL ;
    PORT
      LAYER M3 ;
        RECT  30.744 0 30.762 0.038 ;
    END
  END b_d[308]
  PIN b_d[309]
    DIRECTION INPUT ;
    USE SIGNAL ;
    PORT
      LAYER M5 ;
        RECT  30.816 0 30.84 0.084 ;
    END
  END b_d[309]
  PIN b_d[30]
    DIRECTION INPUT ;
    USE SIGNAL ;
    PORT
      LAYER M3 ;
        RECT  3.708 0 3.726 0.038 ;
    END
  END b_d[30]
  PIN b_d[310]
    DIRECTION INPUT ;
    USE SIGNAL ;
    PORT
      LAYER M3 ;
        RECT  30.924 0 30.942 0.038 ;
    END
  END b_d[310]
  PIN b_d[311]
    DIRECTION INPUT ;
    USE SIGNAL ;
    PORT
      LAYER M5 ;
        RECT  31.008 0 31.032 0.084 ;
    END
  END b_d[311]
  PIN b_d[312]
    DIRECTION INPUT ;
    USE SIGNAL ;
    PORT
      LAYER M3 ;
        RECT  31.14 0 31.158 0.038 ;
    END
  END b_d[312]
  PIN b_d[313]
    DIRECTION INPUT ;
    USE SIGNAL ;
    PORT
      LAYER M5 ;
        RECT  31.248 0 31.272 0.084 ;
    END
  END b_d[313]
  PIN b_d[314]
    DIRECTION INPUT ;
    USE SIGNAL ;
    PORT
      LAYER M3 ;
        RECT  31.32 0 31.338 0.038 ;
    END
  END b_d[314]
  PIN b_d[315]
    DIRECTION INPUT ;
    USE SIGNAL ;
    PORT
      LAYER M5 ;
        RECT  31.44 0 31.464 0.084 ;
    END
  END b_d[315]
  PIN b_d[316]
    DIRECTION INPUT ;
    USE SIGNAL ;
    PORT
      LAYER M3 ;
        RECT  31.536 0 31.554 0.038 ;
    END
  END b_d[316]
  PIN b_d[317]
    DIRECTION INPUT ;
    USE SIGNAL ;
    PORT
      LAYER M5 ;
        RECT  31.632 0 31.656 0.084 ;
    END
  END b_d[317]
  PIN b_d[318]
    DIRECTION INPUT ;
    USE SIGNAL ;
    PORT
      LAYER M3 ;
        RECT  31.716 0 31.734 0.038 ;
    END
  END b_d[318]
  PIN b_d[319]
    DIRECTION INPUT ;
    USE SIGNAL ;
    PORT
      LAYER M5 ;
        RECT  31.824 0 31.848 0.084 ;
    END
  END b_d[319]
  PIN b_d[31]
    DIRECTION INPUT ;
    USE SIGNAL ;
    PORT
      LAYER M5 ;
        RECT  3.792 0 3.816 0.084 ;
    END
  END b_d[31]
  PIN b_d[320]
    DIRECTION INPUT ;
    USE SIGNAL ;
    PORT
      LAYER M3 ;
        RECT  31.896 0 31.914 0.038 ;
    END
  END b_d[320]
  PIN b_d[321]
    DIRECTION INPUT ;
    USE SIGNAL ;
    PORT
      LAYER M5 ;
        RECT  32.016 0 32.04 0.084 ;
    END
  END b_d[321]
  PIN b_d[322]
    DIRECTION INPUT ;
    USE SIGNAL ;
    PORT
      LAYER M3 ;
        RECT  32.112 0 32.13 0.038 ;
    END
  END b_d[322]
  PIN b_d[323]
    DIRECTION INPUT ;
    USE SIGNAL ;
    PORT
      LAYER M5 ;
        RECT  32.208 0 32.232 0.084 ;
    END
  END b_d[323]
  PIN b_d[324]
    DIRECTION INPUT ;
    USE SIGNAL ;
    PORT
      LAYER M3 ;
        RECT  32.292 0 32.31 0.038 ;
    END
  END b_d[324]
  PIN b_d[325]
    DIRECTION INPUT ;
    USE SIGNAL ;
    PORT
      LAYER M5 ;
        RECT  32.4 0 32.424 0.084 ;
    END
  END b_d[325]
  PIN b_d[326]
    DIRECTION INPUT ;
    USE SIGNAL ;
    PORT
      LAYER M3 ;
        RECT  32.508 0 32.526 0.038 ;
    END
  END b_d[326]
  PIN b_d[327]
    DIRECTION INPUT ;
    USE SIGNAL ;
    PORT
      LAYER M5 ;
        RECT  32.592 0 32.616 0.084 ;
    END
  END b_d[327]
  PIN b_d[328]
    DIRECTION INPUT ;
    USE SIGNAL ;
    PORT
      LAYER M3 ;
        RECT  32.688 0 32.706 0.038 ;
    END
  END b_d[328]
  PIN b_d[329]
    DIRECTION INPUT ;
    USE SIGNAL ;
    PORT
      LAYER M5 ;
        RECT  32.784 0 32.808 0.084 ;
    END
  END b_d[329]
  PIN b_d[32]
    DIRECTION INPUT ;
    USE SIGNAL ;
    PORT
      LAYER M3 ;
        RECT  3.888 0 3.906 0.038 ;
    END
  END b_d[32]
  PIN b_d[330]
    DIRECTION INPUT ;
    USE SIGNAL ;
    PORT
      LAYER M3 ;
        RECT  32.868 0 32.886 0.038 ;
    END
  END b_d[330]
  PIN b_d[331]
    DIRECTION INPUT ;
    USE SIGNAL ;
    PORT
      LAYER M5 ;
        RECT  32.976 0 33 0.084 ;
    END
  END b_d[331]
  PIN b_d[332]
    DIRECTION INPUT ;
    USE SIGNAL ;
    PORT
      LAYER M3 ;
        RECT  33.084 0 33.102 0.038 ;
    END
  END b_d[332]
  PIN b_d[333]
    DIRECTION INPUT ;
    USE SIGNAL ;
    PORT
      LAYER M5 ;
        RECT  33.168 0 33.192 0.084 ;
    END
  END b_d[333]
  PIN b_d[334]
    DIRECTION INPUT ;
    USE SIGNAL ;
    PORT
      LAYER M3 ;
        RECT  33.264 0 33.282 0.038 ;
    END
  END b_d[334]
  PIN b_d[335]
    DIRECTION INPUT ;
    USE SIGNAL ;
    PORT
      LAYER M5 ;
        RECT  33.36 0 33.384 0.084 ;
    END
  END b_d[335]
  PIN b_d[336]
    DIRECTION INPUT ;
    USE SIGNAL ;
    PORT
      LAYER M3 ;
        RECT  33.48 0 33.498 0.038 ;
    END
  END b_d[336]
  PIN b_d[337]
    DIRECTION INPUT ;
    USE SIGNAL ;
    PORT
      LAYER M5 ;
        RECT  33.552 0 33.576 0.084 ;
    END
  END b_d[337]
  PIN b_d[338]
    DIRECTION INPUT ;
    USE SIGNAL ;
    PORT
      LAYER M3 ;
        RECT  33.66 0 33.678 0.038 ;
    END
  END b_d[338]
  PIN b_d[339]
    DIRECTION INPUT ;
    USE SIGNAL ;
    PORT
      LAYER M5 ;
        RECT  33.744 0 33.768 0.084 ;
    END
  END b_d[339]
  PIN b_d[33]
    DIRECTION INPUT ;
    USE SIGNAL ;
    PORT
      LAYER M5 ;
        RECT  3.984 0 4.008 0.084 ;
    END
  END b_d[33]
  PIN b_d[340]
    DIRECTION INPUT ;
    USE SIGNAL ;
    PORT
      LAYER M3 ;
        RECT  33.84 0 33.858 0.038 ;
    END
  END b_d[340]
  PIN b_d[341]
    DIRECTION INPUT ;
    USE SIGNAL ;
    PORT
      LAYER M5 ;
        RECT  33.936 0 33.96 0.084 ;
    END
  END b_d[341]
  PIN b_d[342]
    DIRECTION INPUT ;
    USE SIGNAL ;
    PORT
      LAYER M3 ;
        RECT  34.056 0 34.074 0.038 ;
    END
  END b_d[342]
  PIN b_d[343]
    DIRECTION INPUT ;
    USE SIGNAL ;
    PORT
      LAYER M5 ;
        RECT  34.128 0 34.152 0.084 ;
    END
  END b_d[343]
  PIN b_d[344]
    DIRECTION INPUT ;
    USE SIGNAL ;
    PORT
      LAYER M3 ;
        RECT  34.236 0 34.254 0.038 ;
    END
  END b_d[344]
  PIN b_d[345]
    DIRECTION INPUT ;
    USE SIGNAL ;
    PORT
      LAYER M5 ;
        RECT  34.32 0 34.344 0.084 ;
    END
  END b_d[345]
  PIN b_d[346]
    DIRECTION INPUT ;
    USE SIGNAL ;
    PORT
      LAYER M3 ;
        RECT  34.452 0 34.47 0.038 ;
    END
  END b_d[346]
  PIN b_d[347]
    DIRECTION INPUT ;
    USE SIGNAL ;
    PORT
      LAYER M5 ;
        RECT  34.512 0 34.536 0.084 ;
    END
  END b_d[347]
  PIN b_d[348]
    DIRECTION INPUT ;
    USE SIGNAL ;
    PORT
      LAYER M3 ;
        RECT  34.632 0 34.65 0.038 ;
    END
  END b_d[348]
  PIN b_d[349]
    DIRECTION INPUT ;
    USE SIGNAL ;
    PORT
      LAYER M5 ;
        RECT  34.704 0 34.728 0.084 ;
    END
  END b_d[349]
  PIN b_d[34]
    DIRECTION INPUT ;
    USE SIGNAL ;
    PORT
      LAYER M3 ;
        RECT  4.068 0 4.086 0.038 ;
    END
  END b_d[34]
  PIN b_d[350]
    DIRECTION INPUT ;
    USE SIGNAL ;
    PORT
      LAYER M3 ;
        RECT  34.812 0 34.83 0.038 ;
    END
  END b_d[350]
  PIN b_d[351]
    DIRECTION INPUT ;
    USE SIGNAL ;
    PORT
      LAYER M5 ;
        RECT  34.944 0 34.968 0.084 ;
    END
  END b_d[351]
  PIN b_d[352]
    DIRECTION INPUT ;
    USE SIGNAL ;
    PORT
      LAYER M3 ;
        RECT  35.028 0 35.046 0.038 ;
    END
  END b_d[352]
  PIN b_d[353]
    DIRECTION INPUT ;
    USE SIGNAL ;
    PORT
      LAYER M5 ;
        RECT  35.136 0 35.16 0.084 ;
    END
  END b_d[353]
  PIN b_d[354]
    DIRECTION INPUT ;
    USE SIGNAL ;
    PORT
      LAYER M3 ;
        RECT  35.208 0 35.226 0.038 ;
    END
  END b_d[354]
  PIN b_d[355]
    DIRECTION INPUT ;
    USE SIGNAL ;
    PORT
      LAYER M5 ;
        RECT  35.328 0 35.352 0.084 ;
    END
  END b_d[355]
  PIN b_d[356]
    DIRECTION INPUT ;
    USE SIGNAL ;
    PORT
      LAYER M3 ;
        RECT  35.424 0 35.442 0.038 ;
    END
  END b_d[356]
  PIN b_d[357]
    DIRECTION INPUT ;
    USE SIGNAL ;
    PORT
      LAYER M5 ;
        RECT  35.52 0 35.544 0.084 ;
    END
  END b_d[357]
  PIN b_d[358]
    DIRECTION INPUT ;
    USE SIGNAL ;
    PORT
      LAYER M3 ;
        RECT  35.604 0 35.622 0.038 ;
    END
  END b_d[358]
  PIN b_d[359]
    DIRECTION INPUT ;
    USE SIGNAL ;
    PORT
      LAYER M5 ;
        RECT  35.712 0 35.736 0.084 ;
    END
  END b_d[359]
  PIN b_d[35]
    DIRECTION INPUT ;
    USE SIGNAL ;
    PORT
      LAYER M5 ;
        RECT  4.176 0 4.2 0.084 ;
    END
  END b_d[35]
  PIN b_d[360]
    DIRECTION INPUT ;
    USE SIGNAL ;
    PORT
      LAYER M3 ;
        RECT  35.784 0 35.802 0.038 ;
    END
  END b_d[360]
  PIN b_d[361]
    DIRECTION INPUT ;
    USE SIGNAL ;
    PORT
      LAYER M5 ;
        RECT  35.904 0 35.928 0.084 ;
    END
  END b_d[361]
  PIN b_d[362]
    DIRECTION INPUT ;
    USE SIGNAL ;
    PORT
      LAYER M3 ;
        RECT  36 0 36.018 0.038 ;
    END
  END b_d[362]
  PIN b_d[363]
    DIRECTION INPUT ;
    USE SIGNAL ;
    PORT
      LAYER M5 ;
        RECT  36.096 0 36.12 0.084 ;
    END
  END b_d[363]
  PIN b_d[364]
    DIRECTION INPUT ;
    USE SIGNAL ;
    PORT
      LAYER M3 ;
        RECT  36.18 0 36.198 0.038 ;
    END
  END b_d[364]
  PIN b_d[365]
    DIRECTION INPUT ;
    USE SIGNAL ;
    PORT
      LAYER M5 ;
        RECT  36.288 0 36.312 0.084 ;
    END
  END b_d[365]
  PIN b_d[366]
    DIRECTION INPUT ;
    USE SIGNAL ;
    PORT
      LAYER M3 ;
        RECT  36.396 0 36.414 0.038 ;
    END
  END b_d[366]
  PIN b_d[367]
    DIRECTION INPUT ;
    USE SIGNAL ;
    PORT
      LAYER M5 ;
        RECT  36.48 0 36.504 0.084 ;
    END
  END b_d[367]
  PIN b_d[368]
    DIRECTION INPUT ;
    USE SIGNAL ;
    PORT
      LAYER M3 ;
        RECT  36.576 0 36.594 0.038 ;
    END
  END b_d[368]
  PIN b_d[369]
    DIRECTION INPUT ;
    USE SIGNAL ;
    PORT
      LAYER M5 ;
        RECT  36.672 0 36.696 0.084 ;
    END
  END b_d[369]
  PIN b_d[36]
    DIRECTION INPUT ;
    USE SIGNAL ;
    PORT
      LAYER M3 ;
        RECT  4.284 0 4.302 0.038 ;
    END
  END b_d[36]
  PIN b_d[370]
    DIRECTION INPUT ;
    USE SIGNAL ;
    PORT
      LAYER M3 ;
        RECT  36.792 0 36.81 0.038 ;
    END
  END b_d[370]
  PIN b_d[371]
    DIRECTION INPUT ;
    USE SIGNAL ;
    PORT
      LAYER M5 ;
        RECT  36.864 0 36.888 0.084 ;
    END
  END b_d[371]
  PIN b_d[372]
    DIRECTION INPUT ;
    USE SIGNAL ;
    PORT
      LAYER M3 ;
        RECT  36.972 0 36.99 0.038 ;
    END
  END b_d[372]
  PIN b_d[373]
    DIRECTION INPUT ;
    USE SIGNAL ;
    PORT
      LAYER M5 ;
        RECT  37.056 0 37.08 0.084 ;
    END
  END b_d[373]
  PIN b_d[374]
    DIRECTION INPUT ;
    USE SIGNAL ;
    PORT
      LAYER M3 ;
        RECT  37.152 0 37.17 0.038 ;
    END
  END b_d[374]
  PIN b_d[375]
    DIRECTION INPUT ;
    USE SIGNAL ;
    PORT
      LAYER M5 ;
        RECT  37.248 0 37.272 0.084 ;
    END
  END b_d[375]
  PIN b_d[376]
    DIRECTION INPUT ;
    USE SIGNAL ;
    PORT
      LAYER M3 ;
        RECT  37.368 0 37.386 0.038 ;
    END
  END b_d[376]
  PIN b_d[377]
    DIRECTION INPUT ;
    USE SIGNAL ;
    PORT
      LAYER M5 ;
        RECT  37.44 0 37.464 0.084 ;
    END
  END b_d[377]
  PIN b_d[378]
    DIRECTION INPUT ;
    USE SIGNAL ;
    PORT
      LAYER M3 ;
        RECT  37.548 0 37.566 0.038 ;
    END
  END b_d[378]
  PIN b_d[379]
    DIRECTION INPUT ;
    USE SIGNAL ;
    PORT
      LAYER M5 ;
        RECT  37.632 0 37.656 0.084 ;
    END
  END b_d[379]
  PIN b_d[37]
    DIRECTION INPUT ;
    USE SIGNAL ;
    PORT
      LAYER M5 ;
        RECT  4.368 0 4.392 0.084 ;
    END
  END b_d[37]
  PIN b_d[380]
    DIRECTION INPUT ;
    USE SIGNAL ;
    PORT
      LAYER M3 ;
        RECT  37.764 0 37.782 0.038 ;
    END
  END b_d[380]
  PIN b_d[381]
    DIRECTION INPUT ;
    USE SIGNAL ;
    PORT
      LAYER M5 ;
        RECT  37.824 0 37.848 0.084 ;
    END
  END b_d[381]
  PIN b_d[382]
    DIRECTION INPUT ;
    USE SIGNAL ;
    PORT
      LAYER M3 ;
        RECT  37.944 0 37.962 0.038 ;
    END
  END b_d[382]
  PIN b_d[383]
    DIRECTION INPUT ;
    USE SIGNAL ;
    PORT
      LAYER M5 ;
        RECT  38.016 0 38.04 0.084 ;
    END
  END b_d[383]
  PIN b_d[384]
    DIRECTION INPUT ;
    USE SIGNAL ;
    PORT
      LAYER M3 ;
        RECT  38.124 0 38.142 0.038 ;
    END
  END b_d[384]
  PIN b_d[385]
    DIRECTION INPUT ;
    USE SIGNAL ;
    PORT
      LAYER M5 ;
        RECT  38.208 0 38.232 0.084 ;
    END
  END b_d[385]
  PIN b_d[386]
    DIRECTION INPUT ;
    USE SIGNAL ;
    PORT
      LAYER M3 ;
        RECT  38.34 0 38.358 0.038 ;
    END
  END b_d[386]
  PIN b_d[387]
    DIRECTION INPUT ;
    USE SIGNAL ;
    PORT
      LAYER M5 ;
        RECT  38.448 0 38.472 0.084 ;
    END
  END b_d[387]
  PIN b_d[388]
    DIRECTION INPUT ;
    USE SIGNAL ;
    PORT
      LAYER M3 ;
        RECT  38.52 0 38.538 0.038 ;
    END
  END b_d[388]
  PIN b_d[389]
    DIRECTION INPUT ;
    USE SIGNAL ;
    PORT
      LAYER M5 ;
        RECT  38.64 0 38.664 0.084 ;
    END
  END b_d[389]
  PIN b_d[38]
    DIRECTION INPUT ;
    USE SIGNAL ;
    PORT
      LAYER M3 ;
        RECT  4.464 0 4.482 0.038 ;
    END
  END b_d[38]
  PIN b_d[390]
    DIRECTION INPUT ;
    USE SIGNAL ;
    PORT
      LAYER M3 ;
        RECT  38.736 0 38.754 0.038 ;
    END
  END b_d[390]
  PIN b_d[391]
    DIRECTION INPUT ;
    USE SIGNAL ;
    PORT
      LAYER M5 ;
        RECT  38.832 0 38.856 0.084 ;
    END
  END b_d[391]
  PIN b_d[392]
    DIRECTION INPUT ;
    USE SIGNAL ;
    PORT
      LAYER M3 ;
        RECT  38.916 0 38.934 0.038 ;
    END
  END b_d[392]
  PIN b_d[393]
    DIRECTION INPUT ;
    USE SIGNAL ;
    PORT
      LAYER M5 ;
        RECT  39.024 0 39.048 0.084 ;
    END
  END b_d[393]
  PIN b_d[394]
    DIRECTION INPUT ;
    USE SIGNAL ;
    PORT
      LAYER M3 ;
        RECT  39.096 0 39.114 0.038 ;
    END
  END b_d[394]
  PIN b_d[395]
    DIRECTION INPUT ;
    USE SIGNAL ;
    PORT
      LAYER M5 ;
        RECT  39.216 0 39.24 0.084 ;
    END
  END b_d[395]
  PIN b_d[396]
    DIRECTION INPUT ;
    USE SIGNAL ;
    PORT
      LAYER M3 ;
        RECT  39.312 0 39.33 0.038 ;
    END
  END b_d[396]
  PIN b_d[397]
    DIRECTION INPUT ;
    USE SIGNAL ;
    PORT
      LAYER M5 ;
        RECT  39.408 0 39.432 0.084 ;
    END
  END b_d[397]
  PIN b_d[398]
    DIRECTION INPUT ;
    USE SIGNAL ;
    PORT
      LAYER M3 ;
        RECT  39.492 0 39.51 0.038 ;
    END
  END b_d[398]
  PIN b_d[399]
    DIRECTION INPUT ;
    USE SIGNAL ;
    PORT
      LAYER M5 ;
        RECT  39.6 0 39.624 0.084 ;
    END
  END b_d[399]
  PIN b_d[39]
    DIRECTION INPUT ;
    USE SIGNAL ;
    PORT
      LAYER M5 ;
        RECT  4.56 0 4.584 0.084 ;
    END
  END b_d[39]
  PIN b_d[3]
    DIRECTION INPUT ;
    USE SIGNAL ;
    PORT
      LAYER M5 ;
        RECT  1.056 0 1.08 0.084 ;
    END
  END b_d[3]
  PIN b_d[400]
    DIRECTION INPUT ;
    USE SIGNAL ;
    PORT
      LAYER M3 ;
        RECT  39.708 0 39.726 0.038 ;
    END
  END b_d[400]
  PIN b_d[401]
    DIRECTION INPUT ;
    USE SIGNAL ;
    PORT
      LAYER M5 ;
        RECT  39.792 0 39.816 0.084 ;
    END
  END b_d[401]
  PIN b_d[402]
    DIRECTION INPUT ;
    USE SIGNAL ;
    PORT
      LAYER M3 ;
        RECT  39.888 0 39.906 0.038 ;
    END
  END b_d[402]
  PIN b_d[403]
    DIRECTION INPUT ;
    USE SIGNAL ;
    PORT
      LAYER M5 ;
        RECT  39.984 0 40.008 0.084 ;
    END
  END b_d[403]
  PIN b_d[404]
    DIRECTION INPUT ;
    USE SIGNAL ;
    PORT
      LAYER M3 ;
        RECT  40.068 0 40.086 0.038 ;
    END
  END b_d[404]
  PIN b_d[405]
    DIRECTION INPUT ;
    USE SIGNAL ;
    PORT
      LAYER M5 ;
        RECT  40.176 0 40.2 0.084 ;
    END
  END b_d[405]
  PIN b_d[406]
    DIRECTION INPUT ;
    USE SIGNAL ;
    PORT
      LAYER M3 ;
        RECT  40.284 0 40.302 0.038 ;
    END
  END b_d[406]
  PIN b_d[407]
    DIRECTION INPUT ;
    USE SIGNAL ;
    PORT
      LAYER M5 ;
        RECT  40.368 0 40.392 0.084 ;
    END
  END b_d[407]
  PIN b_d[408]
    DIRECTION INPUT ;
    USE SIGNAL ;
    PORT
      LAYER M3 ;
        RECT  40.464 0 40.482 0.038 ;
    END
  END b_d[408]
  PIN b_d[409]
    DIRECTION INPUT ;
    USE SIGNAL ;
    PORT
      LAYER M5 ;
        RECT  40.56 0 40.584 0.084 ;
    END
  END b_d[409]
  PIN b_d[40]
    DIRECTION INPUT ;
    USE SIGNAL ;
    PORT
      LAYER M3 ;
        RECT  4.68 0 4.698 0.038 ;
    END
  END b_d[40]
  PIN b_d[410]
    DIRECTION INPUT ;
    USE SIGNAL ;
    PORT
      LAYER M3 ;
        RECT  40.68 0 40.698 0.038 ;
    END
  END b_d[410]
  PIN b_d[411]
    DIRECTION INPUT ;
    USE SIGNAL ;
    PORT
      LAYER M5 ;
        RECT  40.752 0 40.776 0.084 ;
    END
  END b_d[411]
  PIN b_d[412]
    DIRECTION INPUT ;
    USE SIGNAL ;
    PORT
      LAYER M3 ;
        RECT  40.86 0 40.878 0.038 ;
    END
  END b_d[412]
  PIN b_d[413]
    DIRECTION INPUT ;
    USE SIGNAL ;
    PORT
      LAYER M5 ;
        RECT  40.944 0 40.968 0.084 ;
    END
  END b_d[413]
  PIN b_d[414]
    DIRECTION INPUT ;
    USE SIGNAL ;
    PORT
      LAYER M3 ;
        RECT  41.04 0 41.058 0.038 ;
    END
  END b_d[414]
  PIN b_d[415]
    DIRECTION INPUT ;
    USE SIGNAL ;
    PORT
      LAYER M5 ;
        RECT  41.136 0 41.16 0.084 ;
    END
  END b_d[415]
  PIN b_d[416]
    DIRECTION INPUT ;
    USE SIGNAL ;
    PORT
      LAYER M3 ;
        RECT  41.256 0 41.274 0.038 ;
    END
  END b_d[416]
  PIN b_d[417]
    DIRECTION INPUT ;
    USE SIGNAL ;
    PORT
      LAYER M5 ;
        RECT  41.328 0 41.352 0.084 ;
    END
  END b_d[417]
  PIN b_d[418]
    DIRECTION INPUT ;
    USE SIGNAL ;
    PORT
      LAYER M3 ;
        RECT  41.436 0 41.454 0.038 ;
    END
  END b_d[418]
  PIN b_d[419]
    DIRECTION INPUT ;
    USE SIGNAL ;
    PORT
      LAYER M5 ;
        RECT  41.52 0 41.544 0.084 ;
    END
  END b_d[419]
  PIN b_d[41]
    DIRECTION INPUT ;
    USE SIGNAL ;
    PORT
      LAYER M5 ;
        RECT  4.752 0 4.776 0.084 ;
    END
  END b_d[41]
  PIN b_d[420]
    DIRECTION INPUT ;
    USE SIGNAL ;
    PORT
      LAYER M3 ;
        RECT  41.652 0 41.67 0.038 ;
    END
  END b_d[420]
  PIN b_d[421]
    DIRECTION INPUT ;
    USE SIGNAL ;
    PORT
      LAYER M5 ;
        RECT  41.712 0 41.736 0.084 ;
    END
  END b_d[421]
  PIN b_d[422]
    DIRECTION INPUT ;
    USE SIGNAL ;
    PORT
      LAYER M3 ;
        RECT  41.832 0 41.85 0.038 ;
    END
  END b_d[422]
  PIN b_d[423]
    DIRECTION INPUT ;
    USE SIGNAL ;
    PORT
      LAYER M5 ;
        RECT  41.952 0 41.976 0.084 ;
    END
  END b_d[423]
  PIN b_d[424]
    DIRECTION INPUT ;
    USE SIGNAL ;
    PORT
      LAYER M3 ;
        RECT  42.012 0 42.03 0.038 ;
    END
  END b_d[424]
  PIN b_d[425]
    DIRECTION INPUT ;
    USE SIGNAL ;
    PORT
      LAYER M5 ;
        RECT  42.144 0 42.168 0.084 ;
    END
  END b_d[425]
  PIN b_d[426]
    DIRECTION INPUT ;
    USE SIGNAL ;
    PORT
      LAYER M3 ;
        RECT  42.228 0 42.246 0.038 ;
    END
  END b_d[426]
  PIN b_d[427]
    DIRECTION INPUT ;
    USE SIGNAL ;
    PORT
      LAYER M5 ;
        RECT  42.336 0 42.36 0.084 ;
    END
  END b_d[427]
  PIN b_d[428]
    DIRECTION INPUT ;
    USE SIGNAL ;
    PORT
      LAYER M3 ;
        RECT  42.408 0 42.426 0.038 ;
    END
  END b_d[428]
  PIN b_d[429]
    DIRECTION INPUT ;
    USE SIGNAL ;
    PORT
      LAYER M5 ;
        RECT  42.528 0 42.552 0.084 ;
    END
  END b_d[429]
  PIN b_d[42]
    DIRECTION INPUT ;
    USE SIGNAL ;
    PORT
      LAYER M3 ;
        RECT  4.86 0 4.878 0.038 ;
    END
  END b_d[42]
  PIN b_d[430]
    DIRECTION INPUT ;
    USE SIGNAL ;
    PORT
      LAYER M3 ;
        RECT  42.624 0 42.642 0.038 ;
    END
  END b_d[430]
  PIN b_d[431]
    DIRECTION INPUT ;
    USE SIGNAL ;
    PORT
      LAYER M5 ;
        RECT  42.72 0 42.744 0.084 ;
    END
  END b_d[431]
  PIN b_d[432]
    DIRECTION INPUT ;
    USE SIGNAL ;
    PORT
      LAYER M3 ;
        RECT  42.804 0 42.822 0.038 ;
    END
  END b_d[432]
  PIN b_d[433]
    DIRECTION INPUT ;
    USE SIGNAL ;
    PORT
      LAYER M5 ;
        RECT  42.912 0 42.936 0.084 ;
    END
  END b_d[433]
  PIN b_d[434]
    DIRECTION INPUT ;
    USE SIGNAL ;
    PORT
      LAYER M3 ;
        RECT  42.984 0 43.002 0.038 ;
    END
  END b_d[434]
  PIN b_d[435]
    DIRECTION INPUT ;
    USE SIGNAL ;
    PORT
      LAYER M5 ;
        RECT  43.104 0 43.128 0.084 ;
    END
  END b_d[435]
  PIN b_d[436]
    DIRECTION INPUT ;
    USE SIGNAL ;
    PORT
      LAYER M3 ;
        RECT  43.2 0 43.218 0.038 ;
    END
  END b_d[436]
  PIN b_d[437]
    DIRECTION INPUT ;
    USE SIGNAL ;
    PORT
      LAYER M5 ;
        RECT  43.296 0 43.32 0.084 ;
    END
  END b_d[437]
  PIN b_d[438]
    DIRECTION INPUT ;
    USE SIGNAL ;
    PORT
      LAYER M3 ;
        RECT  43.38 0 43.398 0.038 ;
    END
  END b_d[438]
  PIN b_d[439]
    DIRECTION INPUT ;
    USE SIGNAL ;
    PORT
      LAYER M5 ;
        RECT  43.488 0 43.512 0.084 ;
    END
  END b_d[439]
  PIN b_d[43]
    DIRECTION INPUT ;
    USE SIGNAL ;
    PORT
      LAYER M5 ;
        RECT  4.944 0 4.968 0.084 ;
    END
  END b_d[43]
  PIN b_d[440]
    DIRECTION INPUT ;
    USE SIGNAL ;
    PORT
      LAYER M3 ;
        RECT  43.596 0 43.614 0.038 ;
    END
  END b_d[440]
  PIN b_d[441]
    DIRECTION INPUT ;
    USE SIGNAL ;
    PORT
      LAYER M5 ;
        RECT  43.68 0 43.704 0.084 ;
    END
  END b_d[441]
  PIN b_d[442]
    DIRECTION INPUT ;
    USE SIGNAL ;
    PORT
      LAYER M3 ;
        RECT  43.776 0 43.794 0.038 ;
    END
  END b_d[442]
  PIN b_d[443]
    DIRECTION INPUT ;
    USE SIGNAL ;
    PORT
      LAYER M5 ;
        RECT  43.872 0 43.896 0.084 ;
    END
  END b_d[443]
  PIN b_d[444]
    DIRECTION INPUT ;
    USE SIGNAL ;
    PORT
      LAYER M3 ;
        RECT  43.992 0 44.01 0.038 ;
    END
  END b_d[444]
  PIN b_d[445]
    DIRECTION INPUT ;
    USE SIGNAL ;
    PORT
      LAYER M5 ;
        RECT  44.064 0 44.088 0.084 ;
    END
  END b_d[445]
  PIN b_d[446]
    DIRECTION INPUT ;
    USE SIGNAL ;
    PORT
      LAYER M3 ;
        RECT  44.172 0 44.19 0.038 ;
    END
  END b_d[446]
  PIN b_d[447]
    DIRECTION INPUT ;
    USE SIGNAL ;
    PORT
      LAYER M5 ;
        RECT  44.256 0 44.28 0.084 ;
    END
  END b_d[447]
  PIN b_d[448]
    DIRECTION INPUT ;
    USE SIGNAL ;
    PORT
      LAYER M3 ;
        RECT  44.352 0 44.37 0.038 ;
    END
  END b_d[448]
  PIN b_d[449]
    DIRECTION INPUT ;
    USE SIGNAL ;
    PORT
      LAYER M5 ;
        RECT  44.448 0 44.472 0.084 ;
    END
  END b_d[449]
  PIN b_d[44]
    DIRECTION INPUT ;
    USE SIGNAL ;
    PORT
      LAYER M3 ;
        RECT  5.04 0 5.058 0.038 ;
    END
  END b_d[44]
  PIN b_d[450]
    DIRECTION INPUT ;
    USE SIGNAL ;
    PORT
      LAYER M3 ;
        RECT  44.568 0 44.586 0.038 ;
    END
  END b_d[450]
  PIN b_d[451]
    DIRECTION INPUT ;
    USE SIGNAL ;
    PORT
      LAYER M5 ;
        RECT  44.64 0 44.664 0.084 ;
    END
  END b_d[451]
  PIN b_d[452]
    DIRECTION INPUT ;
    USE SIGNAL ;
    PORT
      LAYER M3 ;
        RECT  44.748 0 44.766 0.038 ;
    END
  END b_d[452]
  PIN b_d[453]
    DIRECTION INPUT ;
    USE SIGNAL ;
    PORT
      LAYER M5 ;
        RECT  44.832 0 44.856 0.084 ;
    END
  END b_d[453]
  PIN b_d[454]
    DIRECTION INPUT ;
    USE SIGNAL ;
    PORT
      LAYER M3 ;
        RECT  44.964 0 44.982 0.038 ;
    END
  END b_d[454]
  PIN b_d[455]
    DIRECTION INPUT ;
    USE SIGNAL ;
    PORT
      LAYER M5 ;
        RECT  45.024 0 45.048 0.084 ;
    END
  END b_d[455]
  PIN b_d[456]
    DIRECTION INPUT ;
    USE SIGNAL ;
    PORT
      LAYER M3 ;
        RECT  45.144 0 45.162 0.038 ;
    END
  END b_d[456]
  PIN b_d[457]
    DIRECTION INPUT ;
    USE SIGNAL ;
    PORT
      LAYER M5 ;
        RECT  45.216 0 45.24 0.084 ;
    END
  END b_d[457]
  PIN b_d[458]
    DIRECTION INPUT ;
    USE SIGNAL ;
    PORT
      LAYER M3 ;
        RECT  45.324 0 45.342 0.038 ;
    END
  END b_d[458]
  PIN b_d[459]
    DIRECTION INPUT ;
    USE SIGNAL ;
    PORT
      LAYER M5 ;
        RECT  45.408 0 45.432 0.084 ;
    END
  END b_d[459]
  PIN b_d[45]
    DIRECTION INPUT ;
    USE SIGNAL ;
    PORT
      LAYER M5 ;
        RECT  5.136 0 5.16 0.084 ;
    END
  END b_d[45]
  PIN b_d[460]
    DIRECTION INPUT ;
    USE SIGNAL ;
    PORT
      LAYER M3 ;
        RECT  45.54 0 45.558 0.038 ;
    END
  END b_d[460]
  PIN b_d[461]
    DIRECTION INPUT ;
    USE SIGNAL ;
    PORT
      LAYER M5 ;
        RECT  45.648 0 45.672 0.084 ;
    END
  END b_d[461]
  PIN b_d[462]
    DIRECTION INPUT ;
    USE SIGNAL ;
    PORT
      LAYER M3 ;
        RECT  45.72 0 45.738 0.038 ;
    END
  END b_d[462]
  PIN b_d[463]
    DIRECTION INPUT ;
    USE SIGNAL ;
    PORT
      LAYER M5 ;
        RECT  45.84 0 45.864 0.084 ;
    END
  END b_d[463]
  PIN b_d[464]
    DIRECTION INPUT ;
    USE SIGNAL ;
    PORT
      LAYER M3 ;
        RECT  45.936 0 45.954 0.038 ;
    END
  END b_d[464]
  PIN b_d[465]
    DIRECTION INPUT ;
    USE SIGNAL ;
    PORT
      LAYER M5 ;
        RECT  46.032 0 46.056 0.084 ;
    END
  END b_d[465]
  PIN b_d[466]
    DIRECTION INPUT ;
    USE SIGNAL ;
    PORT
      LAYER M3 ;
        RECT  46.116 0 46.134 0.038 ;
    END
  END b_d[466]
  PIN b_d[467]
    DIRECTION INPUT ;
    USE SIGNAL ;
    PORT
      LAYER M5 ;
        RECT  46.224 0 46.248 0.084 ;
    END
  END b_d[467]
  PIN b_d[468]
    DIRECTION INPUT ;
    USE SIGNAL ;
    PORT
      LAYER M3 ;
        RECT  46.296 0 46.314 0.038 ;
    END
  END b_d[468]
  PIN b_d[469]
    DIRECTION INPUT ;
    USE SIGNAL ;
    PORT
      LAYER M5 ;
        RECT  46.416 0 46.44 0.084 ;
    END
  END b_d[469]
  PIN b_d[46]
    DIRECTION INPUT ;
    USE SIGNAL ;
    PORT
      LAYER M3 ;
        RECT  5.256 0 5.274 0.038 ;
    END
  END b_d[46]
  PIN b_d[470]
    DIRECTION INPUT ;
    USE SIGNAL ;
    PORT
      LAYER M3 ;
        RECT  46.512 0 46.53 0.038 ;
    END
  END b_d[470]
  PIN b_d[471]
    DIRECTION INPUT ;
    USE SIGNAL ;
    PORT
      LAYER M5 ;
        RECT  46.608 0 46.632 0.084 ;
    END
  END b_d[471]
  PIN b_d[472]
    DIRECTION INPUT ;
    USE SIGNAL ;
    PORT
      LAYER M3 ;
        RECT  46.692 0 46.71 0.038 ;
    END
  END b_d[472]
  PIN b_d[473]
    DIRECTION INPUT ;
    USE SIGNAL ;
    PORT
      LAYER M5 ;
        RECT  46.8 0 46.824 0.084 ;
    END
  END b_d[473]
  PIN b_d[474]
    DIRECTION INPUT ;
    USE SIGNAL ;
    PORT
      LAYER M3 ;
        RECT  46.908 0 46.926 0.038 ;
    END
  END b_d[474]
  PIN b_d[475]
    DIRECTION INPUT ;
    USE SIGNAL ;
    PORT
      LAYER M5 ;
        RECT  46.992 0 47.016 0.084 ;
    END
  END b_d[475]
  PIN b_d[476]
    DIRECTION INPUT ;
    USE SIGNAL ;
    PORT
      LAYER M3 ;
        RECT  47.088 0 47.106 0.038 ;
    END
  END b_d[476]
  PIN b_d[477]
    DIRECTION INPUT ;
    USE SIGNAL ;
    PORT
      LAYER M5 ;
        RECT  47.184 0 47.208 0.084 ;
    END
  END b_d[477]
  PIN b_d[478]
    DIRECTION INPUT ;
    USE SIGNAL ;
    PORT
      LAYER M3 ;
        RECT  47.268 0 47.286 0.038 ;
    END
  END b_d[478]
  PIN b_d[479]
    DIRECTION INPUT ;
    USE SIGNAL ;
    PORT
      LAYER M5 ;
        RECT  47.376 0 47.4 0.084 ;
    END
  END b_d[479]
  PIN b_d[47]
    DIRECTION INPUT ;
    USE SIGNAL ;
    PORT
      LAYER M5 ;
        RECT  5.328 0 5.352 0.084 ;
    END
  END b_d[47]
  PIN b_d[480]
    DIRECTION INPUT ;
    USE SIGNAL ;
    PORT
      LAYER M3 ;
        RECT  47.484 0 47.502 0.038 ;
    END
  END b_d[480]
  PIN b_d[481]
    DIRECTION INPUT ;
    USE SIGNAL ;
    PORT
      LAYER M5 ;
        RECT  47.568 0 47.592 0.084 ;
    END
  END b_d[481]
  PIN b_d[482]
    DIRECTION INPUT ;
    USE SIGNAL ;
    PORT
      LAYER M3 ;
        RECT  47.664 0 47.682 0.038 ;
    END
  END b_d[482]
  PIN b_d[483]
    DIRECTION INPUT ;
    USE SIGNAL ;
    PORT
      LAYER M5 ;
        RECT  47.76 0 47.784 0.084 ;
    END
  END b_d[483]
  PIN b_d[484]
    DIRECTION INPUT ;
    USE SIGNAL ;
    PORT
      LAYER M3 ;
        RECT  47.88 0 47.898 0.038 ;
    END
  END b_d[484]
  PIN b_d[485]
    DIRECTION INPUT ;
    USE SIGNAL ;
    PORT
      LAYER M5 ;
        RECT  47.952 0 47.976 0.084 ;
    END
  END b_d[485]
  PIN b_d[486]
    DIRECTION INPUT ;
    USE SIGNAL ;
    PORT
      LAYER M3 ;
        RECT  48.06 0 48.078 0.038 ;
    END
  END b_d[486]
  PIN b_d[487]
    DIRECTION INPUT ;
    USE SIGNAL ;
    PORT
      LAYER M5 ;
        RECT  48.144 0 48.168 0.084 ;
    END
  END b_d[487]
  PIN b_d[488]
    DIRECTION INPUT ;
    USE SIGNAL ;
    PORT
      LAYER M3 ;
        RECT  48.24 0 48.258 0.038 ;
    END
  END b_d[488]
  PIN b_d[489]
    DIRECTION INPUT ;
    USE SIGNAL ;
    PORT
      LAYER M5 ;
        RECT  48.336 0 48.36 0.084 ;
    END
  END b_d[489]
  PIN b_d[48]
    DIRECTION INPUT ;
    USE SIGNAL ;
    PORT
      LAYER M3 ;
        RECT  5.436 0 5.454 0.038 ;
    END
  END b_d[48]
  PIN b_d[490]
    DIRECTION INPUT ;
    USE SIGNAL ;
    PORT
      LAYER M3 ;
        RECT  48.456 0 48.474 0.038 ;
    END
  END b_d[490]
  PIN b_d[491]
    DIRECTION INPUT ;
    USE SIGNAL ;
    PORT
      LAYER M5 ;
        RECT  48.528 0 48.552 0.084 ;
    END
  END b_d[491]
  PIN b_d[492]
    DIRECTION INPUT ;
    USE SIGNAL ;
    PORT
      LAYER M3 ;
        RECT  48.636 0 48.654 0.038 ;
    END
  END b_d[492]
  PIN b_d[493]
    DIRECTION INPUT ;
    USE SIGNAL ;
    PORT
      LAYER M5 ;
        RECT  48.72 0 48.744 0.084 ;
    END
  END b_d[493]
  PIN b_d[494]
    DIRECTION INPUT ;
    USE SIGNAL ;
    PORT
      LAYER M3 ;
        RECT  48.852 0 48.87 0.038 ;
    END
  END b_d[494]
  PIN b_d[495]
    DIRECTION INPUT ;
    USE SIGNAL ;
    PORT
      LAYER M5 ;
        RECT  48.912 0 48.936 0.084 ;
    END
  END b_d[495]
  PIN b_d[496]
    DIRECTION INPUT ;
    USE SIGNAL ;
    PORT
      LAYER M3 ;
        RECT  49.032 0 49.05 0.038 ;
    END
  END b_d[496]
  PIN b_d[497]
    DIRECTION INPUT ;
    USE SIGNAL ;
    PORT
      LAYER M5 ;
        RECT  49.152 0 49.176 0.084 ;
    END
  END b_d[497]
  PIN b_d[498]
    DIRECTION INPUT ;
    USE SIGNAL ;
    PORT
      LAYER M3 ;
        RECT  49.212 0 49.23 0.038 ;
    END
  END b_d[498]
  PIN b_d[499]
    DIRECTION INPUT ;
    USE SIGNAL ;
    PORT
      LAYER M5 ;
        RECT  49.344 0 49.368 0.084 ;
    END
  END b_d[499]
  PIN b_d[49]
    DIRECTION INPUT ;
    USE SIGNAL ;
    PORT
      LAYER M5 ;
        RECT  5.52 0 5.544 0.084 ;
    END
  END b_d[49]
  PIN b_d[4]
    DIRECTION INPUT ;
    USE SIGNAL ;
    PORT
      LAYER M3 ;
        RECT  1.152 0 1.17 0.038 ;
    END
  END b_d[4]
  PIN b_d[500]
    DIRECTION INPUT ;
    USE SIGNAL ;
    PORT
      LAYER M3 ;
        RECT  49.428 0 49.446 0.038 ;
    END
  END b_d[500]
  PIN b_d[501]
    DIRECTION INPUT ;
    USE SIGNAL ;
    PORT
      LAYER M5 ;
        RECT  49.536 0 49.56 0.084 ;
    END
  END b_d[501]
  PIN b_d[502]
    DIRECTION INPUT ;
    USE SIGNAL ;
    PORT
      LAYER M3 ;
        RECT  49.608 0 49.626 0.038 ;
    END
  END b_d[502]
  PIN b_d[503]
    DIRECTION INPUT ;
    USE SIGNAL ;
    PORT
      LAYER M5 ;
        RECT  49.728 0 49.752 0.084 ;
    END
  END b_d[503]
  PIN b_d[504]
    DIRECTION INPUT ;
    USE SIGNAL ;
    PORT
      LAYER M3 ;
        RECT  49.824 0 49.842 0.038 ;
    END
  END b_d[504]
  PIN b_d[505]
    DIRECTION INPUT ;
    USE SIGNAL ;
    PORT
      LAYER M5 ;
        RECT  49.92 0 49.944 0.084 ;
    END
  END b_d[505]
  PIN b_d[506]
    DIRECTION INPUT ;
    USE SIGNAL ;
    PORT
      LAYER M3 ;
        RECT  50.004 0 50.022 0.038 ;
    END
  END b_d[506]
  PIN b_d[507]
    DIRECTION INPUT ;
    USE SIGNAL ;
    PORT
      LAYER M5 ;
        RECT  50.112 0 50.136 0.084 ;
    END
  END b_d[507]
  PIN b_d[508]
    DIRECTION INPUT ;
    USE SIGNAL ;
    PORT
      LAYER M3 ;
        RECT  50.184 0 50.202 0.038 ;
    END
  END b_d[508]
  PIN b_d[509]
    DIRECTION INPUT ;
    USE SIGNAL ;
    PORT
      LAYER M5 ;
        RECT  50.304 0 50.328 0.084 ;
    END
  END b_d[509]
  PIN b_d[50]
    DIRECTION INPUT ;
    USE SIGNAL ;
    PORT
      LAYER M3 ;
        RECT  5.652 0 5.67 0.038 ;
    END
  END b_d[50]
  PIN b_d[510]
    DIRECTION INPUT ;
    USE SIGNAL ;
    PORT
      LAYER M3 ;
        RECT  50.4 0 50.418 0.038 ;
    END
  END b_d[510]
  PIN b_d[511]
    DIRECTION INPUT ;
    USE SIGNAL ;
    PORT
      LAYER M5 ;
        RECT  50.496 0 50.52 0.084 ;
    END
  END b_d[511]
  PIN b_d[512]
    DIRECTION INPUT ;
    USE SIGNAL ;
    PORT
      LAYER M3 ;
        RECT  50.58 0 50.598 0.038 ;
    END
  END b_d[512]
  PIN b_d[513]
    DIRECTION INPUT ;
    USE SIGNAL ;
    PORT
      LAYER M5 ;
        RECT  50.688 0 50.712 0.084 ;
    END
  END b_d[513]
  PIN b_d[514]
    DIRECTION INPUT ;
    USE SIGNAL ;
    PORT
      LAYER M3 ;
        RECT  50.796 0 50.814 0.038 ;
    END
  END b_d[514]
  PIN b_d[515]
    DIRECTION INPUT ;
    USE SIGNAL ;
    PORT
      LAYER M5 ;
        RECT  50.88 0 50.904 0.084 ;
    END
  END b_d[515]
  PIN b_d[51]
    DIRECTION INPUT ;
    USE SIGNAL ;
    PORT
      LAYER M5 ;
        RECT  5.712 0 5.736 0.084 ;
    END
  END b_d[51]
  PIN b_d[52]
    DIRECTION INPUT ;
    USE SIGNAL ;
    PORT
      LAYER M3 ;
        RECT  5.832 0 5.85 0.038 ;
    END
  END b_d[52]
  PIN b_d[53]
    DIRECTION INPUT ;
    USE SIGNAL ;
    PORT
      LAYER M5 ;
        RECT  5.904 0 5.928 0.084 ;
    END
  END b_d[53]
  PIN b_d[54]
    DIRECTION INPUT ;
    USE SIGNAL ;
    PORT
      LAYER M3 ;
        RECT  6.012 0 6.03 0.038 ;
    END
  END b_d[54]
  PIN b_d[55]
    DIRECTION INPUT ;
    USE SIGNAL ;
    PORT
      LAYER M5 ;
        RECT  6.144 0 6.168 0.084 ;
    END
  END b_d[55]
  PIN b_d[56]
    DIRECTION INPUT ;
    USE SIGNAL ;
    PORT
      LAYER M3 ;
        RECT  6.228 0 6.246 0.038 ;
    END
  END b_d[56]
  PIN b_d[57]
    DIRECTION INPUT ;
    USE SIGNAL ;
    PORT
      LAYER M5 ;
        RECT  6.336 0 6.36 0.084 ;
    END
  END b_d[57]
  PIN b_d[58]
    DIRECTION INPUT ;
    USE SIGNAL ;
    PORT
      LAYER M3 ;
        RECT  6.408 0 6.426 0.038 ;
    END
  END b_d[58]
  PIN b_d[59]
    DIRECTION INPUT ;
    USE SIGNAL ;
    PORT
      LAYER M5 ;
        RECT  6.528 0 6.552 0.084 ;
    END
  END b_d[59]
  PIN b_d[5]
    DIRECTION INPUT ;
    USE SIGNAL ;
    PORT
      LAYER M5 ;
        RECT  1.248 0 1.272 0.084 ;
    END
  END b_d[5]
  PIN b_d[60]
    DIRECTION INPUT ;
    USE SIGNAL ;
    PORT
      LAYER M3 ;
        RECT  6.624 0 6.642 0.038 ;
    END
  END b_d[60]
  PIN b_d[61]
    DIRECTION INPUT ;
    USE SIGNAL ;
    PORT
      LAYER M5 ;
        RECT  6.72 0 6.744 0.084 ;
    END
  END b_d[61]
  PIN b_d[62]
    DIRECTION INPUT ;
    USE SIGNAL ;
    PORT
      LAYER M3 ;
        RECT  6.804 0 6.822 0.038 ;
    END
  END b_d[62]
  PIN b_d[63]
    DIRECTION INPUT ;
    USE SIGNAL ;
    PORT
      LAYER M5 ;
        RECT  6.912 0 6.936 0.084 ;
    END
  END b_d[63]
  PIN b_d[64]
    DIRECTION INPUT ;
    USE SIGNAL ;
    PORT
      LAYER M3 ;
        RECT  6.984 0 7.002 0.038 ;
    END
  END b_d[64]
  PIN b_d[65]
    DIRECTION INPUT ;
    USE SIGNAL ;
    PORT
      LAYER M5 ;
        RECT  7.104 0 7.128 0.084 ;
    END
  END b_d[65]
  PIN b_d[66]
    DIRECTION INPUT ;
    USE SIGNAL ;
    PORT
      LAYER M3 ;
        RECT  7.2 0 7.218 0.038 ;
    END
  END b_d[66]
  PIN b_d[67]
    DIRECTION INPUT ;
    USE SIGNAL ;
    PORT
      LAYER M5 ;
        RECT  7.296 0 7.32 0.084 ;
    END
  END b_d[67]
  PIN b_d[68]
    DIRECTION INPUT ;
    USE SIGNAL ;
    PORT
      LAYER M3 ;
        RECT  7.38 0 7.398 0.038 ;
    END
  END b_d[68]
  PIN b_d[69]
    DIRECTION INPUT ;
    USE SIGNAL ;
    PORT
      LAYER M5 ;
        RECT  7.488 0 7.512 0.084 ;
    END
  END b_d[69]
  PIN b_d[6]
    DIRECTION INPUT ;
    USE SIGNAL ;
    PORT
      LAYER M3 ;
        RECT  1.368 0 1.386 0.038 ;
    END
  END b_d[6]
  PIN b_d[70]
    DIRECTION INPUT ;
    USE SIGNAL ;
    PORT
      LAYER M3 ;
        RECT  7.596 0 7.614 0.038 ;
    END
  END b_d[70]
  PIN b_d[71]
    DIRECTION INPUT ;
    USE SIGNAL ;
    PORT
      LAYER M5 ;
        RECT  7.68 0 7.704 0.084 ;
    END
  END b_d[71]
  PIN b_d[72]
    DIRECTION INPUT ;
    USE SIGNAL ;
    PORT
      LAYER M3 ;
        RECT  7.776 0 7.794 0.038 ;
    END
  END b_d[72]
  PIN b_d[73]
    DIRECTION INPUT ;
    USE SIGNAL ;
    PORT
      LAYER M5 ;
        RECT  7.872 0 7.896 0.084 ;
    END
  END b_d[73]
  PIN b_d[74]
    DIRECTION INPUT ;
    USE SIGNAL ;
    PORT
      LAYER M3 ;
        RECT  7.956 0 7.974 0.038 ;
    END
  END b_d[74]
  PIN b_d[75]
    DIRECTION INPUT ;
    USE SIGNAL ;
    PORT
      LAYER M5 ;
        RECT  8.064 0 8.088 0.084 ;
    END
  END b_d[75]
  PIN b_d[76]
    DIRECTION INPUT ;
    USE SIGNAL ;
    PORT
      LAYER M3 ;
        RECT  8.172 0 8.19 0.038 ;
    END
  END b_d[76]
  PIN b_d[77]
    DIRECTION INPUT ;
    USE SIGNAL ;
    PORT
      LAYER M5 ;
        RECT  8.256 0 8.28 0.084 ;
    END
  END b_d[77]
  PIN b_d[78]
    DIRECTION INPUT ;
    USE SIGNAL ;
    PORT
      LAYER M3 ;
        RECT  8.352 0 8.37 0.038 ;
    END
  END b_d[78]
  PIN b_d[79]
    DIRECTION INPUT ;
    USE SIGNAL ;
    PORT
      LAYER M5 ;
        RECT  8.448 0 8.472 0.084 ;
    END
  END b_d[79]
  PIN b_d[7]
    DIRECTION INPUT ;
    USE SIGNAL ;
    PORT
      LAYER M5 ;
        RECT  1.44 0 1.464 0.084 ;
    END
  END b_d[7]
  PIN b_d[80]
    DIRECTION INPUT ;
    USE SIGNAL ;
    PORT
      LAYER M3 ;
        RECT  8.568 0 8.586 0.038 ;
    END
  END b_d[80]
  PIN b_d[81]
    DIRECTION INPUT ;
    USE SIGNAL ;
    PORT
      LAYER M5 ;
        RECT  8.64 0 8.664 0.084 ;
    END
  END b_d[81]
  PIN b_d[82]
    DIRECTION INPUT ;
    USE SIGNAL ;
    PORT
      LAYER M3 ;
        RECT  8.748 0 8.766 0.038 ;
    END
  END b_d[82]
  PIN b_d[83]
    DIRECTION INPUT ;
    USE SIGNAL ;
    PORT
      LAYER M5 ;
        RECT  8.832 0 8.856 0.084 ;
    END
  END b_d[83]
  PIN b_d[84]
    DIRECTION INPUT ;
    USE SIGNAL ;
    PORT
      LAYER M3 ;
        RECT  8.928 0 8.946 0.038 ;
    END
  END b_d[84]
  PIN b_d[85]
    DIRECTION INPUT ;
    USE SIGNAL ;
    PORT
      LAYER M5 ;
        RECT  9.024 0 9.048 0.084 ;
    END
  END b_d[85]
  PIN b_d[86]
    DIRECTION INPUT ;
    USE SIGNAL ;
    PORT
      LAYER M3 ;
        RECT  9.144 0 9.162 0.038 ;
    END
  END b_d[86]
  PIN b_d[87]
    DIRECTION INPUT ;
    USE SIGNAL ;
    PORT
      LAYER M5 ;
        RECT  9.216 0 9.24 0.084 ;
    END
  END b_d[87]
  PIN b_d[88]
    DIRECTION INPUT ;
    USE SIGNAL ;
    PORT
      LAYER M3 ;
        RECT  9.324 0 9.342 0.038 ;
    END
  END b_d[88]
  PIN b_d[89]
    DIRECTION INPUT ;
    USE SIGNAL ;
    PORT
      LAYER M5 ;
        RECT  9.408 0 9.432 0.084 ;
    END
  END b_d[89]
  PIN b_d[8]
    DIRECTION INPUT ;
    USE SIGNAL ;
    PORT
      LAYER M3 ;
        RECT  1.548 0 1.566 0.038 ;
    END
  END b_d[8]
  PIN b_d[90]
    DIRECTION INPUT ;
    USE SIGNAL ;
    PORT
      LAYER M3 ;
        RECT  9.54 0 9.558 0.038 ;
    END
  END b_d[90]
  PIN b_d[91]
    DIRECTION INPUT ;
    USE SIGNAL ;
    PORT
      LAYER M5 ;
        RECT  9.6 0 9.624 0.084 ;
    END
  END b_d[91]
  PIN b_d[92]
    DIRECTION INPUT ;
    USE SIGNAL ;
    PORT
      LAYER M3 ;
        RECT  9.72 0 9.738 0.038 ;
    END
  END b_d[92]
  PIN b_d[93]
    DIRECTION INPUT ;
    USE SIGNAL ;
    PORT
      LAYER M5 ;
        RECT  9.84 0 9.864 0.084 ;
    END
  END b_d[93]
  PIN b_d[94]
    DIRECTION INPUT ;
    USE SIGNAL ;
    PORT
      LAYER M3 ;
        RECT  9.936 0 9.954 0.038 ;
    END
  END b_d[94]
  PIN b_d[95]
    DIRECTION INPUT ;
    USE SIGNAL ;
    PORT
      LAYER M5 ;
        RECT  10.032 0 10.056 0.084 ;
    END
  END b_d[95]
  PIN b_d[96]
    DIRECTION INPUT ;
    USE SIGNAL ;
    PORT
      LAYER M3 ;
        RECT  10.116 0 10.134 0.038 ;
    END
  END b_d[96]
  PIN b_d[97]
    DIRECTION INPUT ;
    USE SIGNAL ;
    PORT
      LAYER M5 ;
        RECT  10.224 0 10.248 0.084 ;
    END
  END b_d[97]
  PIN b_d[98]
    DIRECTION INPUT ;
    USE SIGNAL ;
    PORT
      LAYER M3 ;
        RECT  10.296 0 10.314 0.038 ;
    END
  END b_d[98]
  PIN b_d[99]
    DIRECTION INPUT ;
    USE SIGNAL ;
    PORT
      LAYER M5 ;
        RECT  10.416 0 10.44 0.084 ;
    END
  END b_d[99]
  PIN b_d[9]
    DIRECTION INPUT ;
    USE SIGNAL ;
    PORT
      LAYER M5 ;
        RECT  1.632 0 1.656 0.084 ;
    END
  END b_d[9]
  PIN ck
    DIRECTION INPUT ;
    USE SIGNAL ;
    PORT
      LAYER M3 ;
        RECT  52.056 103.618 52.074 103.656 ;
    END
  END ck
  PIN rst_n
    DIRECTION INPUT ;
    USE SIGNAL ;
    PORT
      LAYER M3 ;
        RECT  52.344 103.618 52.362 103.656 ;
    END
  END rst_n
  PIN sidx[0]
    DIRECTION INPUT ;
    USE SIGNAL ;
    PORT
      LAYER M3 ;
        RECT  0.288 103.618 0.306 103.656 ;
    END
  END sidx[0]
  PIN sidx[1]
    DIRECTION INPUT ;
    USE SIGNAL ;
    PORT
      LAYER M5 ;
        RECT  0.48 103.572 0.504 103.656 ;
    END
    PORT
      LAYER M5 ;
        RECT  0.48 101.317 0.504 103.632 ;
    END
  END sidx[1]
  PIN sidx[2]
    DIRECTION INPUT ;
    USE SIGNAL ;
    PORT
      LAYER M3 ;
        RECT  0.684 103.618 0.702 103.656 ;
    END
  END sidx[2]
  PIN tap_d[0]
    DIRECTION OUTPUT ;
    USE SIGNAL ;
    PORT
      LAYER M4 ;
        RECT  0 26.976 0.084 27 ;
    END
  END tap_d[0]
  PIN tap_d[100]
    DIRECTION OUTPUT ;
    USE SIGNAL ;
    PORT
      LAYER M4 ;
        RECT  0 36.912 0.084 36.936 ;
    END
  END tap_d[100]
  PIN tap_d[101]
    DIRECTION OUTPUT ;
    USE SIGNAL ;
    PORT
      LAYER M4 ;
        RECT  0 37.008 0.084 37.032 ;
    END
  END tap_d[101]
  PIN tap_d[102]
    DIRECTION OUTPUT ;
    USE SIGNAL ;
    PORT
      LAYER M4 ;
        RECT  0 37.104 0.084 37.128 ;
    END
  END tap_d[102]
  PIN tap_d[103]
    DIRECTION OUTPUT ;
    USE SIGNAL ;
    PORT
      LAYER M4 ;
        RECT  0 37.2 0.084 37.224 ;
    END
  END tap_d[103]
  PIN tap_d[104]
    DIRECTION OUTPUT ;
    USE SIGNAL ;
    PORT
      LAYER M4 ;
        RECT  0 37.296 0.084 37.32 ;
    END
  END tap_d[104]
  PIN tap_d[105]
    DIRECTION OUTPUT ;
    USE SIGNAL ;
    PORT
      LAYER M4 ;
        RECT  0 37.392 0.084 37.416 ;
    END
  END tap_d[105]
  PIN tap_d[106]
    DIRECTION OUTPUT ;
    USE SIGNAL ;
    PORT
      LAYER M4 ;
        RECT  0 37.536 0.084 37.56 ;
    END
  END tap_d[106]
  PIN tap_d[107]
    DIRECTION OUTPUT ;
    USE SIGNAL ;
    PORT
      LAYER M4 ;
        RECT  0 37.632 0.084 37.656 ;
    END
  END tap_d[107]
  PIN tap_d[108]
    DIRECTION OUTPUT ;
    USE SIGNAL ;
    PORT
      LAYER M4 ;
        RECT  0 37.728 0.084 37.752 ;
    END
  END tap_d[108]
  PIN tap_d[109]
    DIRECTION OUTPUT ;
    USE SIGNAL ;
    PORT
      LAYER M4 ;
        RECT  0 37.824 0.084 37.848 ;
    END
  END tap_d[109]
  PIN tap_d[10]
    DIRECTION OUTPUT ;
    USE SIGNAL ;
    PORT
      LAYER M4 ;
        RECT  0 27.984 0.084 28.008 ;
    END
  END tap_d[10]
  PIN tap_d[110]
    DIRECTION OUTPUT ;
    USE SIGNAL ;
    PORT
      LAYER M4 ;
        RECT  0 37.92 0.084 37.944 ;
    END
  END tap_d[110]
  PIN tap_d[111]
    DIRECTION OUTPUT ;
    USE SIGNAL ;
    PORT
      LAYER M4 ;
        RECT  0 38.016 0.084 38.04 ;
    END
  END tap_d[111]
  PIN tap_d[112]
    DIRECTION OUTPUT ;
    USE SIGNAL ;
    PORT
      LAYER M4 ;
        RECT  0 38.112 0.084 38.136 ;
    END
  END tap_d[112]
  PIN tap_d[113]
    DIRECTION OUTPUT ;
    USE SIGNAL ;
    PORT
      LAYER M4 ;
        RECT  0 38.208 0.084 38.232 ;
    END
  END tap_d[113]
  PIN tap_d[114]
    DIRECTION OUTPUT ;
    USE SIGNAL ;
    PORT
      LAYER M4 ;
        RECT  0 38.304 0.084 38.328 ;
    END
  END tap_d[114]
  PIN tap_d[115]
    DIRECTION OUTPUT ;
    USE SIGNAL ;
    PORT
      LAYER M4 ;
        RECT  0 38.4 0.084 38.424 ;
    END
  END tap_d[115]
  PIN tap_d[116]
    DIRECTION OUTPUT ;
    USE SIGNAL ;
    PORT
      LAYER M4 ;
        RECT  0 38.496 0.084 38.52 ;
    END
  END tap_d[116]
  PIN tap_d[117]
    DIRECTION OUTPUT ;
    USE SIGNAL ;
    PORT
      LAYER M4 ;
        RECT  0 38.592 0.084 38.616 ;
    END
  END tap_d[117]
  PIN tap_d[118]
    DIRECTION OUTPUT ;
    USE SIGNAL ;
    PORT
      LAYER M4 ;
        RECT  0 38.688 0.084 38.712 ;
    END
  END tap_d[118]
  PIN tap_d[119]
    DIRECTION OUTPUT ;
    USE SIGNAL ;
    PORT
      LAYER M4 ;
        RECT  0 38.784 0.084 38.808 ;
    END
  END tap_d[119]
  PIN tap_d[11]
    DIRECTION OUTPUT ;
    USE SIGNAL ;
    PORT
      LAYER M4 ;
        RECT  0 28.08 0.084 28.104 ;
    END
  END tap_d[11]
  PIN tap_d[120]
    DIRECTION OUTPUT ;
    USE SIGNAL ;
    PORT
      LAYER M4 ;
        RECT  0 38.928 0.084 38.952 ;
    END
  END tap_d[120]
  PIN tap_d[121]
    DIRECTION OUTPUT ;
    USE SIGNAL ;
    PORT
      LAYER M4 ;
        RECT  0 39.024 0.084 39.048 ;
    END
  END tap_d[121]
  PIN tap_d[122]
    DIRECTION OUTPUT ;
    USE SIGNAL ;
    PORT
      LAYER M4 ;
        RECT  0 39.12 0.084 39.144 ;
    END
  END tap_d[122]
  PIN tap_d[123]
    DIRECTION OUTPUT ;
    USE SIGNAL ;
    PORT
      LAYER M4 ;
        RECT  0 39.216 0.084 39.24 ;
    END
  END tap_d[123]
  PIN tap_d[124]
    DIRECTION OUTPUT ;
    USE SIGNAL ;
    PORT
      LAYER M4 ;
        RECT  0 39.312 0.084 39.336 ;
    END
  END tap_d[124]
  PIN tap_d[125]
    DIRECTION OUTPUT ;
    USE SIGNAL ;
    PORT
      LAYER M4 ;
        RECT  0 39.408 0.084 39.432 ;
    END
  END tap_d[125]
  PIN tap_d[126]
    DIRECTION OUTPUT ;
    USE SIGNAL ;
    PORT
      LAYER M4 ;
        RECT  0 39.504 0.084 39.528 ;
    END
  END tap_d[126]
  PIN tap_d[127]
    DIRECTION OUTPUT ;
    USE SIGNAL ;
    PORT
      LAYER M4 ;
        RECT  0 39.6 0.084 39.624 ;
    END
  END tap_d[127]
  PIN tap_d[128]
    DIRECTION OUTPUT ;
    USE SIGNAL ;
    PORT
      LAYER M4 ;
        RECT  0 39.696 0.084 39.72 ;
    END
  END tap_d[128]
  PIN tap_d[129]
    DIRECTION OUTPUT ;
    USE SIGNAL ;
    PORT
      LAYER M4 ;
        RECT  0 39.792 0.084 39.816 ;
    END
  END tap_d[129]
  PIN tap_d[12]
    DIRECTION OUTPUT ;
    USE SIGNAL ;
    PORT
      LAYER M4 ;
        RECT  0 28.176 0.084 28.2 ;
    END
  END tap_d[12]
  PIN tap_d[130]
    DIRECTION OUTPUT ;
    USE SIGNAL ;
    PORT
      LAYER M4 ;
        RECT  0 39.888 0.084 39.912 ;
    END
  END tap_d[130]
  PIN tap_d[131]
    DIRECTION OUTPUT ;
    USE SIGNAL ;
    PORT
      LAYER M4 ;
        RECT  0 39.984 0.084 40.008 ;
    END
  END tap_d[131]
  PIN tap_d[132]
    DIRECTION OUTPUT ;
    USE SIGNAL ;
    PORT
      LAYER M4 ;
        RECT  0 40.08 0.084 40.104 ;
    END
  END tap_d[132]
  PIN tap_d[133]
    DIRECTION OUTPUT ;
    USE SIGNAL ;
    PORT
      LAYER M4 ;
        RECT  0 40.176 0.084 40.2 ;
    END
  END tap_d[133]
  PIN tap_d[134]
    DIRECTION OUTPUT ;
    USE SIGNAL ;
    PORT
      LAYER M4 ;
        RECT  0 40.32 0.084 40.344 ;
    END
  END tap_d[134]
  PIN tap_d[135]
    DIRECTION OUTPUT ;
    USE SIGNAL ;
    PORT
      LAYER M4 ;
        RECT  0 40.416 0.084 40.44 ;
    END
  END tap_d[135]
  PIN tap_d[136]
    DIRECTION OUTPUT ;
    USE SIGNAL ;
    PORT
      LAYER M4 ;
        RECT  0 40.512 0.084 40.536 ;
    END
  END tap_d[136]
  PIN tap_d[137]
    DIRECTION OUTPUT ;
    USE SIGNAL ;
    PORT
      LAYER M4 ;
        RECT  0 40.608 0.084 40.632 ;
    END
  END tap_d[137]
  PIN tap_d[138]
    DIRECTION OUTPUT ;
    USE SIGNAL ;
    PORT
      LAYER M4 ;
        RECT  0 40.704 0.084 40.728 ;
    END
  END tap_d[138]
  PIN tap_d[139]
    DIRECTION OUTPUT ;
    USE SIGNAL ;
    PORT
      LAYER M4 ;
        RECT  0 40.8 0.084 40.824 ;
    END
  END tap_d[139]
  PIN tap_d[13]
    DIRECTION OUTPUT ;
    USE SIGNAL ;
    PORT
      LAYER M4 ;
        RECT  0 28.272 0.084 28.296 ;
    END
  END tap_d[13]
  PIN tap_d[140]
    DIRECTION OUTPUT ;
    USE SIGNAL ;
    PORT
      LAYER M4 ;
        RECT  0 40.896 0.084 40.92 ;
    END
  END tap_d[140]
  PIN tap_d[141]
    DIRECTION OUTPUT ;
    USE SIGNAL ;
    PORT
      LAYER M4 ;
        RECT  0 40.992 0.084 41.016 ;
    END
  END tap_d[141]
  PIN tap_d[142]
    DIRECTION OUTPUT ;
    USE SIGNAL ;
    PORT
      LAYER M4 ;
        RECT  0 41.088 0.084 41.112 ;
    END
  END tap_d[142]
  PIN tap_d[143]
    DIRECTION OUTPUT ;
    USE SIGNAL ;
    PORT
      LAYER M4 ;
        RECT  0 41.184 0.084 41.208 ;
    END
  END tap_d[143]
  PIN tap_d[144]
    DIRECTION OUTPUT ;
    USE SIGNAL ;
    PORT
      LAYER M4 ;
        RECT  0 41.28 0.084 41.304 ;
    END
  END tap_d[144]
  PIN tap_d[145]
    DIRECTION OUTPUT ;
    USE SIGNAL ;
    PORT
      LAYER M4 ;
        RECT  0 41.376 0.084 41.4 ;
    END
  END tap_d[145]
  PIN tap_d[146]
    DIRECTION OUTPUT ;
    USE SIGNAL ;
    PORT
      LAYER M4 ;
        RECT  0 41.472 0.084 41.496 ;
    END
  END tap_d[146]
  PIN tap_d[147]
    DIRECTION OUTPUT ;
    USE SIGNAL ;
    PORT
      LAYER M4 ;
        RECT  0 41.568 0.084 41.592 ;
    END
  END tap_d[147]
  PIN tap_d[148]
    DIRECTION OUTPUT ;
    USE SIGNAL ;
    PORT
      LAYER M4 ;
        RECT  0 41.712 0.084 41.736 ;
    END
  END tap_d[148]
  PIN tap_d[149]
    DIRECTION OUTPUT ;
    USE SIGNAL ;
    PORT
      LAYER M4 ;
        RECT  0 41.808 0.084 41.832 ;
    END
  END tap_d[149]
  PIN tap_d[14]
    DIRECTION OUTPUT ;
    USE SIGNAL ;
    PORT
      LAYER M4 ;
        RECT  0 28.368 0.084 28.392 ;
    END
  END tap_d[14]
  PIN tap_d[150]
    DIRECTION OUTPUT ;
    USE SIGNAL ;
    PORT
      LAYER M4 ;
        RECT  0 41.904 0.084 41.928 ;
    END
  END tap_d[150]
  PIN tap_d[151]
    DIRECTION OUTPUT ;
    USE SIGNAL ;
    PORT
      LAYER M4 ;
        RECT  0 42 0.084 42.024 ;
    END
  END tap_d[151]
  PIN tap_d[152]
    DIRECTION OUTPUT ;
    USE SIGNAL ;
    PORT
      LAYER M4 ;
        RECT  0 42.096 0.084 42.12 ;
    END
  END tap_d[152]
  PIN tap_d[153]
    DIRECTION OUTPUT ;
    USE SIGNAL ;
    PORT
      LAYER M4 ;
        RECT  0 42.192 0.084 42.216 ;
    END
  END tap_d[153]
  PIN tap_d[154]
    DIRECTION OUTPUT ;
    USE SIGNAL ;
    PORT
      LAYER M4 ;
        RECT  0 42.288 0.084 42.312 ;
    END
  END tap_d[154]
  PIN tap_d[155]
    DIRECTION OUTPUT ;
    USE SIGNAL ;
    PORT
      LAYER M4 ;
        RECT  0 42.384 0.084 42.408 ;
    END
  END tap_d[155]
  PIN tap_d[156]
    DIRECTION OUTPUT ;
    USE SIGNAL ;
    PORT
      LAYER M4 ;
        RECT  0 42.48 0.084 42.504 ;
    END
  END tap_d[156]
  PIN tap_d[157]
    DIRECTION OUTPUT ;
    USE SIGNAL ;
    PORT
      LAYER M4 ;
        RECT  0 42.576 0.084 42.6 ;
    END
  END tap_d[157]
  PIN tap_d[158]
    DIRECTION OUTPUT ;
    USE SIGNAL ;
    PORT
      LAYER M4 ;
        RECT  0 42.672 0.084 42.696 ;
    END
  END tap_d[158]
  PIN tap_d[159]
    DIRECTION OUTPUT ;
    USE SIGNAL ;
    PORT
      LAYER M4 ;
        RECT  0 42.768 0.084 42.792 ;
    END
  END tap_d[159]
  PIN tap_d[15]
    DIRECTION OUTPUT ;
    USE SIGNAL ;
    PORT
      LAYER M4 ;
        RECT  0 28.464 0.084 28.488 ;
    END
  END tap_d[15]
  PIN tap_d[160]
    DIRECTION OUTPUT ;
    USE SIGNAL ;
    PORT
      LAYER M4 ;
        RECT  0 42.864 0.084 42.888 ;
    END
  END tap_d[160]
  PIN tap_d[161]
    DIRECTION OUTPUT ;
    USE SIGNAL ;
    PORT
      LAYER M4 ;
        RECT  0 42.96 0.084 42.984 ;
    END
  END tap_d[161]
  PIN tap_d[162]
    DIRECTION OUTPUT ;
    USE SIGNAL ;
    PORT
      LAYER M4 ;
        RECT  0 43.104 0.084 43.128 ;
    END
  END tap_d[162]
  PIN tap_d[163]
    DIRECTION OUTPUT ;
    USE SIGNAL ;
    PORT
      LAYER M4 ;
        RECT  0 43.2 0.084 43.224 ;
    END
  END tap_d[163]
  PIN tap_d[164]
    DIRECTION OUTPUT ;
    USE SIGNAL ;
    PORT
      LAYER M4 ;
        RECT  0 43.296 0.084 43.32 ;
    END
  END tap_d[164]
  PIN tap_d[165]
    DIRECTION OUTPUT ;
    USE SIGNAL ;
    PORT
      LAYER M4 ;
        RECT  0 43.392 0.084 43.416 ;
    END
  END tap_d[165]
  PIN tap_d[166]
    DIRECTION OUTPUT ;
    USE SIGNAL ;
    PORT
      LAYER M4 ;
        RECT  0 43.488 0.084 43.512 ;
    END
  END tap_d[166]
  PIN tap_d[167]
    DIRECTION OUTPUT ;
    USE SIGNAL ;
    PORT
      LAYER M4 ;
        RECT  0 43.584 0.084 43.608 ;
    END
  END tap_d[167]
  PIN tap_d[168]
    DIRECTION OUTPUT ;
    USE SIGNAL ;
    PORT
      LAYER M4 ;
        RECT  0 43.68 0.084 43.704 ;
    END
  END tap_d[168]
  PIN tap_d[169]
    DIRECTION OUTPUT ;
    USE SIGNAL ;
    PORT
      LAYER M4 ;
        RECT  0 43.776 0.084 43.8 ;
    END
  END tap_d[169]
  PIN tap_d[16]
    DIRECTION OUTPUT ;
    USE SIGNAL ;
    PORT
      LAYER M4 ;
        RECT  0 28.56 0.084 28.584 ;
    END
  END tap_d[16]
  PIN tap_d[170]
    DIRECTION OUTPUT ;
    USE SIGNAL ;
    PORT
      LAYER M4 ;
        RECT  0 43.872 0.084 43.896 ;
    END
  END tap_d[170]
  PIN tap_d[171]
    DIRECTION OUTPUT ;
    USE SIGNAL ;
    PORT
      LAYER M4 ;
        RECT  0 43.968 0.084 43.992 ;
    END
  END tap_d[171]
  PIN tap_d[172]
    DIRECTION OUTPUT ;
    USE SIGNAL ;
    PORT
      LAYER M4 ;
        RECT  0 44.064 0.084 44.088 ;
    END
  END tap_d[172]
  PIN tap_d[173]
    DIRECTION OUTPUT ;
    USE SIGNAL ;
    PORT
      LAYER M4 ;
        RECT  0 44.16 0.084 44.184 ;
    END
  END tap_d[173]
  PIN tap_d[174]
    DIRECTION OUTPUT ;
    USE SIGNAL ;
    PORT
      LAYER M4 ;
        RECT  0 44.256 0.084 44.28 ;
    END
  END tap_d[174]
  PIN tap_d[175]
    DIRECTION OUTPUT ;
    USE SIGNAL ;
    PORT
      LAYER M4 ;
        RECT  0 44.352 0.084 44.376 ;
    END
  END tap_d[175]
  PIN tap_d[176]
    DIRECTION OUTPUT ;
    USE SIGNAL ;
    PORT
      LAYER M4 ;
        RECT  0 44.496 0.084 44.52 ;
    END
  END tap_d[176]
  PIN tap_d[177]
    DIRECTION OUTPUT ;
    USE SIGNAL ;
    PORT
      LAYER M4 ;
        RECT  0 44.592 0.084 44.616 ;
    END
  END tap_d[177]
  PIN tap_d[178]
    DIRECTION OUTPUT ;
    USE SIGNAL ;
    PORT
      LAYER M4 ;
        RECT  0 44.688 0.084 44.712 ;
    END
  END tap_d[178]
  PIN tap_d[179]
    DIRECTION OUTPUT ;
    USE SIGNAL ;
    PORT
      LAYER M4 ;
        RECT  0 44.784 0.084 44.808 ;
    END
  END tap_d[179]
  PIN tap_d[17]
    DIRECTION OUTPUT ;
    USE SIGNAL ;
    PORT
      LAYER M4 ;
        RECT  0 28.656 0.084 28.68 ;
    END
  END tap_d[17]
  PIN tap_d[180]
    DIRECTION OUTPUT ;
    USE SIGNAL ;
    PORT
      LAYER M4 ;
        RECT  0 44.88 0.084 44.904 ;
    END
  END tap_d[180]
  PIN tap_d[181]
    DIRECTION OUTPUT ;
    USE SIGNAL ;
    PORT
      LAYER M4 ;
        RECT  0 44.976 0.084 45 ;
    END
  END tap_d[181]
  PIN tap_d[182]
    DIRECTION OUTPUT ;
    USE SIGNAL ;
    PORT
      LAYER M4 ;
        RECT  0 45.072 0.084 45.096 ;
    END
  END tap_d[182]
  PIN tap_d[183]
    DIRECTION OUTPUT ;
    USE SIGNAL ;
    PORT
      LAYER M4 ;
        RECT  0 45.168 0.084 45.192 ;
    END
  END tap_d[183]
  PIN tap_d[184]
    DIRECTION OUTPUT ;
    USE SIGNAL ;
    PORT
      LAYER M4 ;
        RECT  0 45.264 0.084 45.288 ;
    END
  END tap_d[184]
  PIN tap_d[185]
    DIRECTION OUTPUT ;
    USE SIGNAL ;
    PORT
      LAYER M4 ;
        RECT  0 45.36 0.084 45.384 ;
    END
  END tap_d[185]
  PIN tap_d[186]
    DIRECTION OUTPUT ;
    USE SIGNAL ;
    PORT
      LAYER M4 ;
        RECT  0 45.456 0.084 45.48 ;
    END
  END tap_d[186]
  PIN tap_d[187]
    DIRECTION OUTPUT ;
    USE SIGNAL ;
    PORT
      LAYER M4 ;
        RECT  0 45.552 0.084 45.576 ;
    END
  END tap_d[187]
  PIN tap_d[188]
    DIRECTION OUTPUT ;
    USE SIGNAL ;
    PORT
      LAYER M4 ;
        RECT  0 45.648 0.084 45.672 ;
    END
  END tap_d[188]
  PIN tap_d[189]
    DIRECTION OUTPUT ;
    USE SIGNAL ;
    PORT
      LAYER M4 ;
        RECT  0 45.744 0.084 45.768 ;
    END
  END tap_d[189]
  PIN tap_d[18]
    DIRECTION OUTPUT ;
    USE SIGNAL ;
    PORT
      LAYER M4 ;
        RECT  0 28.752 0.084 28.776 ;
    END
  END tap_d[18]
  PIN tap_d[190]
    DIRECTION OUTPUT ;
    USE SIGNAL ;
    PORT
      LAYER M4 ;
        RECT  0 45.888 0.084 45.912 ;
    END
  END tap_d[190]
  PIN tap_d[191]
    DIRECTION OUTPUT ;
    USE SIGNAL ;
    PORT
      LAYER M4 ;
        RECT  0 45.984 0.084 46.008 ;
    END
  END tap_d[191]
  PIN tap_d[192]
    DIRECTION OUTPUT ;
    USE SIGNAL ;
    PORT
      LAYER M4 ;
        RECT  0 46.08 0.084 46.104 ;
    END
  END tap_d[192]
  PIN tap_d[193]
    DIRECTION OUTPUT ;
    USE SIGNAL ;
    PORT
      LAYER M4 ;
        RECT  0 46.176 0.084 46.2 ;
    END
  END tap_d[193]
  PIN tap_d[194]
    DIRECTION OUTPUT ;
    USE SIGNAL ;
    PORT
      LAYER M4 ;
        RECT  0 46.272 0.084 46.296 ;
    END
  END tap_d[194]
  PIN tap_d[195]
    DIRECTION OUTPUT ;
    USE SIGNAL ;
    PORT
      LAYER M4 ;
        RECT  0 46.368 0.084 46.392 ;
    END
  END tap_d[195]
  PIN tap_d[196]
    DIRECTION OUTPUT ;
    USE SIGNAL ;
    PORT
      LAYER M4 ;
        RECT  0 46.464 0.084 46.488 ;
    END
  END tap_d[196]
  PIN tap_d[197]
    DIRECTION OUTPUT ;
    USE SIGNAL ;
    PORT
      LAYER M4 ;
        RECT  0 46.56 0.084 46.584 ;
    END
  END tap_d[197]
  PIN tap_d[198]
    DIRECTION OUTPUT ;
    USE SIGNAL ;
    PORT
      LAYER M4 ;
        RECT  0 46.656 0.084 46.68 ;
    END
  END tap_d[198]
  PIN tap_d[199]
    DIRECTION OUTPUT ;
    USE SIGNAL ;
    PORT
      LAYER M4 ;
        RECT  0 46.752 0.084 46.776 ;
    END
  END tap_d[199]
  PIN tap_d[19]
    DIRECTION OUTPUT ;
    USE SIGNAL ;
    PORT
      LAYER M4 ;
        RECT  0 28.848 0.084 28.872 ;
    END
  END tap_d[19]
  PIN tap_d[1]
    DIRECTION OUTPUT ;
    USE SIGNAL ;
    PORT
      LAYER M4 ;
        RECT  0 27.072 0.084 27.096 ;
    END
  END tap_d[1]
  PIN tap_d[200]
    DIRECTION OUTPUT ;
    USE SIGNAL ;
    PORT
      LAYER M4 ;
        RECT  0 46.848 0.084 46.872 ;
    END
  END tap_d[200]
  PIN tap_d[201]
    DIRECTION OUTPUT ;
    USE SIGNAL ;
    PORT
      LAYER M4 ;
        RECT  0 46.944 0.084 46.968 ;
    END
  END tap_d[201]
  PIN tap_d[202]
    DIRECTION OUTPUT ;
    USE SIGNAL ;
    PORT
      LAYER M4 ;
        RECT  0 47.04 0.084 47.064 ;
    END
  END tap_d[202]
  PIN tap_d[203]
    DIRECTION OUTPUT ;
    USE SIGNAL ;
    PORT
      LAYER M4 ;
        RECT  0 47.136 0.084 47.16 ;
    END
  END tap_d[203]
  PIN tap_d[204]
    DIRECTION OUTPUT ;
    USE SIGNAL ;
    PORT
      LAYER M4 ;
        RECT  0 47.28 0.084 47.304 ;
    END
  END tap_d[204]
  PIN tap_d[205]
    DIRECTION OUTPUT ;
    USE SIGNAL ;
    PORT
      LAYER M4 ;
        RECT  0 47.376 0.084 47.4 ;
    END
  END tap_d[205]
  PIN tap_d[206]
    DIRECTION OUTPUT ;
    USE SIGNAL ;
    PORT
      LAYER M4 ;
        RECT  0 47.472 0.084 47.496 ;
    END
  END tap_d[206]
  PIN tap_d[207]
    DIRECTION OUTPUT ;
    USE SIGNAL ;
    PORT
      LAYER M4 ;
        RECT  0 47.568 0.084 47.592 ;
    END
  END tap_d[207]
  PIN tap_d[208]
    DIRECTION OUTPUT ;
    USE SIGNAL ;
    PORT
      LAYER M4 ;
        RECT  0 47.664 0.084 47.688 ;
    END
  END tap_d[208]
  PIN tap_d[209]
    DIRECTION OUTPUT ;
    USE SIGNAL ;
    PORT
      LAYER M4 ;
        RECT  0 47.76 0.084 47.784 ;
    END
  END tap_d[209]
  PIN tap_d[20]
    DIRECTION OUTPUT ;
    USE SIGNAL ;
    PORT
      LAYER M4 ;
        RECT  0 28.944 0.084 28.968 ;
    END
  END tap_d[20]
  PIN tap_d[210]
    DIRECTION OUTPUT ;
    USE SIGNAL ;
    PORT
      LAYER M4 ;
        RECT  0 47.856 0.084 47.88 ;
    END
  END tap_d[210]
  PIN tap_d[211]
    DIRECTION OUTPUT ;
    USE SIGNAL ;
    PORT
      LAYER M4 ;
        RECT  0 47.952 0.084 47.976 ;
    END
  END tap_d[211]
  PIN tap_d[212]
    DIRECTION OUTPUT ;
    USE SIGNAL ;
    PORT
      LAYER M4 ;
        RECT  0 48.048 0.084 48.072 ;
    END
  END tap_d[212]
  PIN tap_d[213]
    DIRECTION OUTPUT ;
    USE SIGNAL ;
    PORT
      LAYER M4 ;
        RECT  0 48.144 0.084 48.168 ;
    END
  END tap_d[213]
  PIN tap_d[214]
    DIRECTION OUTPUT ;
    USE SIGNAL ;
    PORT
      LAYER M4 ;
        RECT  0 48.24 0.084 48.264 ;
    END
  END tap_d[214]
  PIN tap_d[215]
    DIRECTION OUTPUT ;
    USE SIGNAL ;
    PORT
      LAYER M4 ;
        RECT  0 48.336 0.084 48.36 ;
    END
  END tap_d[215]
  PIN tap_d[216]
    DIRECTION OUTPUT ;
    USE SIGNAL ;
    PORT
      LAYER M4 ;
        RECT  0 48.432 0.084 48.456 ;
    END
  END tap_d[216]
  PIN tap_d[217]
    DIRECTION OUTPUT ;
    USE SIGNAL ;
    PORT
      LAYER M4 ;
        RECT  0 48.528 0.084 48.552 ;
    END
  END tap_d[217]
  PIN tap_d[218]
    DIRECTION OUTPUT ;
    USE SIGNAL ;
    PORT
      LAYER M4 ;
        RECT  0 48.624 0.084 48.648 ;
    END
  END tap_d[218]
  PIN tap_d[219]
    DIRECTION OUTPUT ;
    USE SIGNAL ;
    PORT
      LAYER M4 ;
        RECT  0 48.768 0.084 48.792 ;
    END
  END tap_d[219]
  PIN tap_d[21]
    DIRECTION OUTPUT ;
    USE SIGNAL ;
    PORT
      LAYER M4 ;
        RECT  0 29.088 0.084 29.112 ;
    END
  END tap_d[21]
  PIN tap_d[220]
    DIRECTION OUTPUT ;
    USE SIGNAL ;
    PORT
      LAYER M4 ;
        RECT  0 48.864 0.084 48.888 ;
    END
  END tap_d[220]
  PIN tap_d[221]
    DIRECTION OUTPUT ;
    USE SIGNAL ;
    PORT
      LAYER M4 ;
        RECT  0 48.96 0.084 48.984 ;
    END
  END tap_d[221]
  PIN tap_d[222]
    DIRECTION OUTPUT ;
    USE SIGNAL ;
    PORT
      LAYER M4 ;
        RECT  0 49.056 0.084 49.08 ;
    END
  END tap_d[222]
  PIN tap_d[223]
    DIRECTION OUTPUT ;
    USE SIGNAL ;
    PORT
      LAYER M4 ;
        RECT  0 49.152 0.084 49.176 ;
    END
  END tap_d[223]
  PIN tap_d[224]
    DIRECTION OUTPUT ;
    USE SIGNAL ;
    PORT
      LAYER M4 ;
        RECT  0 49.248 0.084 49.272 ;
    END
  END tap_d[224]
  PIN tap_d[225]
    DIRECTION OUTPUT ;
    USE SIGNAL ;
    PORT
      LAYER M4 ;
        RECT  0 49.344 0.084 49.368 ;
    END
  END tap_d[225]
  PIN tap_d[226]
    DIRECTION OUTPUT ;
    USE SIGNAL ;
    PORT
      LAYER M4 ;
        RECT  0 49.44 0.084 49.464 ;
    END
  END tap_d[226]
  PIN tap_d[227]
    DIRECTION OUTPUT ;
    USE SIGNAL ;
    PORT
      LAYER M4 ;
        RECT  0 49.536 0.084 49.56 ;
    END
  END tap_d[227]
  PIN tap_d[228]
    DIRECTION OUTPUT ;
    USE SIGNAL ;
    PORT
      LAYER M4 ;
        RECT  0 49.632 0.084 49.656 ;
    END
  END tap_d[228]
  PIN tap_d[229]
    DIRECTION OUTPUT ;
    USE SIGNAL ;
    PORT
      LAYER M4 ;
        RECT  0 49.728 0.084 49.752 ;
    END
  END tap_d[229]
  PIN tap_d[22]
    DIRECTION OUTPUT ;
    USE SIGNAL ;
    PORT
      LAYER M4 ;
        RECT  0 29.184 0.084 29.208 ;
    END
  END tap_d[22]
  PIN tap_d[230]
    DIRECTION OUTPUT ;
    USE SIGNAL ;
    PORT
      LAYER M4 ;
        RECT  0 49.824 0.084 49.848 ;
    END
  END tap_d[230]
  PIN tap_d[231]
    DIRECTION OUTPUT ;
    USE SIGNAL ;
    PORT
      LAYER M4 ;
        RECT  0 49.92 0.084 49.944 ;
    END
  END tap_d[231]
  PIN tap_d[232]
    DIRECTION OUTPUT ;
    USE SIGNAL ;
    PORT
      LAYER M4 ;
        RECT  0 50.016 0.084 50.04 ;
    END
  END tap_d[232]
  PIN tap_d[233]
    DIRECTION OUTPUT ;
    USE SIGNAL ;
    PORT
      LAYER M4 ;
        RECT  0 50.16 0.084 50.184 ;
    END
  END tap_d[233]
  PIN tap_d[234]
    DIRECTION OUTPUT ;
    USE SIGNAL ;
    PORT
      LAYER M4 ;
        RECT  0 50.256 0.084 50.28 ;
    END
  END tap_d[234]
  PIN tap_d[235]
    DIRECTION OUTPUT ;
    USE SIGNAL ;
    PORT
      LAYER M4 ;
        RECT  0 50.352 0.084 50.376 ;
    END
  END tap_d[235]
  PIN tap_d[236]
    DIRECTION OUTPUT ;
    USE SIGNAL ;
    PORT
      LAYER M4 ;
        RECT  0 50.448 0.084 50.472 ;
    END
  END tap_d[236]
  PIN tap_d[237]
    DIRECTION OUTPUT ;
    USE SIGNAL ;
    PORT
      LAYER M4 ;
        RECT  0 50.544 0.084 50.568 ;
    END
  END tap_d[237]
  PIN tap_d[238]
    DIRECTION OUTPUT ;
    USE SIGNAL ;
    PORT
      LAYER M4 ;
        RECT  0 50.64 0.084 50.664 ;
    END
  END tap_d[238]
  PIN tap_d[239]
    DIRECTION OUTPUT ;
    USE SIGNAL ;
    PORT
      LAYER M4 ;
        RECT  0 50.736 0.084 50.76 ;
    END
  END tap_d[239]
  PIN tap_d[23]
    DIRECTION OUTPUT ;
    USE SIGNAL ;
    PORT
      LAYER M4 ;
        RECT  0 29.28 0.084 29.304 ;
    END
  END tap_d[23]
  PIN tap_d[240]
    DIRECTION OUTPUT ;
    USE SIGNAL ;
    PORT
      LAYER M4 ;
        RECT  0 50.832 0.084 50.856 ;
    END
  END tap_d[240]
  PIN tap_d[241]
    DIRECTION OUTPUT ;
    USE SIGNAL ;
    PORT
      LAYER M4 ;
        RECT  0 50.928 0.084 50.952 ;
    END
  END tap_d[241]
  PIN tap_d[242]
    DIRECTION OUTPUT ;
    USE SIGNAL ;
    PORT
      LAYER M4 ;
        RECT  0 51.024 0.084 51.048 ;
    END
  END tap_d[242]
  PIN tap_d[243]
    DIRECTION OUTPUT ;
    USE SIGNAL ;
    PORT
      LAYER M4 ;
        RECT  0 51.12 0.084 51.144 ;
    END
  END tap_d[243]
  PIN tap_d[244]
    DIRECTION OUTPUT ;
    USE SIGNAL ;
    PORT
      LAYER M4 ;
        RECT  0 51.216 0.084 51.24 ;
    END
  END tap_d[244]
  PIN tap_d[245]
    DIRECTION OUTPUT ;
    USE SIGNAL ;
    PORT
      LAYER M4 ;
        RECT  0 51.312 0.084 51.336 ;
    END
  END tap_d[245]
  PIN tap_d[246]
    DIRECTION OUTPUT ;
    USE SIGNAL ;
    PORT
      LAYER M4 ;
        RECT  0 51.408 0.084 51.432 ;
    END
  END tap_d[246]
  PIN tap_d[247]
    DIRECTION OUTPUT ;
    USE SIGNAL ;
    PORT
      LAYER M4 ;
        RECT  0 51.552 0.084 51.576 ;
    END
  END tap_d[247]
  PIN tap_d[248]
    DIRECTION OUTPUT ;
    USE SIGNAL ;
    PORT
      LAYER M4 ;
        RECT  0 51.648 0.084 51.672 ;
    END
  END tap_d[248]
  PIN tap_d[249]
    DIRECTION OUTPUT ;
    USE SIGNAL ;
    PORT
      LAYER M4 ;
        RECT  0 51.744 0.084 51.768 ;
    END
  END tap_d[249]
  PIN tap_d[24]
    DIRECTION OUTPUT ;
    USE SIGNAL ;
    PORT
      LAYER M4 ;
        RECT  0 29.376 0.084 29.4 ;
    END
  END tap_d[24]
  PIN tap_d[250]
    DIRECTION OUTPUT ;
    USE SIGNAL ;
    PORT
      LAYER M4 ;
        RECT  0 51.84 0.084 51.864 ;
    END
  END tap_d[250]
  PIN tap_d[251]
    DIRECTION OUTPUT ;
    USE SIGNAL ;
    PORT
      LAYER M4 ;
        RECT  0 51.936 0.084 51.96 ;
    END
  END tap_d[251]
  PIN tap_d[252]
    DIRECTION OUTPUT ;
    USE SIGNAL ;
    PORT
      LAYER M4 ;
        RECT  0 52.032 0.084 52.056 ;
    END
  END tap_d[252]
  PIN tap_d[253]
    DIRECTION OUTPUT ;
    USE SIGNAL ;
    PORT
      LAYER M4 ;
        RECT  0 52.128 0.084 52.152 ;
    END
  END tap_d[253]
  PIN tap_d[254]
    DIRECTION OUTPUT ;
    USE SIGNAL ;
    PORT
      LAYER M4 ;
        RECT  0 52.224 0.084 52.248 ;
    END
  END tap_d[254]
  PIN tap_d[255]
    DIRECTION OUTPUT ;
    USE SIGNAL ;
    PORT
      LAYER M4 ;
        RECT  0 52.32 0.084 52.344 ;
    END
  END tap_d[255]
  PIN tap_d[256]
    DIRECTION OUTPUT ;
    USE SIGNAL ;
    PORT
      LAYER M4 ;
        RECT  0 52.416 0.084 52.44 ;
    END
  END tap_d[256]
  PIN tap_d[257]
    DIRECTION OUTPUT ;
    USE SIGNAL ;
    PORT
      LAYER M4 ;
        RECT  0 52.512 0.084 52.536 ;
    END
  END tap_d[257]
  PIN tap_d[258]
    DIRECTION OUTPUT ;
    USE SIGNAL ;
    PORT
      LAYER M4 ;
        RECT  0 52.608 0.084 52.632 ;
    END
  END tap_d[258]
  PIN tap_d[259]
    DIRECTION OUTPUT ;
    USE SIGNAL ;
    PORT
      LAYER M4 ;
        RECT  0 52.704 0.084 52.728 ;
    END
  END tap_d[259]
  PIN tap_d[25]
    DIRECTION OUTPUT ;
    USE SIGNAL ;
    PORT
      LAYER M4 ;
        RECT  0 29.472 0.084 29.496 ;
    END
  END tap_d[25]
  PIN tap_d[260]
    DIRECTION OUTPUT ;
    USE SIGNAL ;
    PORT
      LAYER M4 ;
        RECT  0 52.8 0.084 52.824 ;
    END
  END tap_d[260]
  PIN tap_d[261]
    DIRECTION OUTPUT ;
    USE SIGNAL ;
    PORT
      LAYER M4 ;
        RECT  0 52.944 0.084 52.968 ;
    END
  END tap_d[261]
  PIN tap_d[262]
    DIRECTION OUTPUT ;
    USE SIGNAL ;
    PORT
      LAYER M4 ;
        RECT  0 53.04 0.084 53.064 ;
    END
  END tap_d[262]
  PIN tap_d[263]
    DIRECTION OUTPUT ;
    USE SIGNAL ;
    PORT
      LAYER M4 ;
        RECT  0 53.136 0.084 53.16 ;
    END
  END tap_d[263]
  PIN tap_d[264]
    DIRECTION OUTPUT ;
    USE SIGNAL ;
    PORT
      LAYER M4 ;
        RECT  0 53.232 0.084 53.256 ;
    END
  END tap_d[264]
  PIN tap_d[265]
    DIRECTION OUTPUT ;
    USE SIGNAL ;
    PORT
      LAYER M4 ;
        RECT  0 53.328 0.084 53.352 ;
    END
  END tap_d[265]
  PIN tap_d[266]
    DIRECTION OUTPUT ;
    USE SIGNAL ;
    PORT
      LAYER M4 ;
        RECT  0 53.424 0.084 53.448 ;
    END
  END tap_d[266]
  PIN tap_d[267]
    DIRECTION OUTPUT ;
    USE SIGNAL ;
    PORT
      LAYER M4 ;
        RECT  0 53.52 0.084 53.544 ;
    END
  END tap_d[267]
  PIN tap_d[268]
    DIRECTION OUTPUT ;
    USE SIGNAL ;
    PORT
      LAYER M4 ;
        RECT  0 53.616 0.084 53.64 ;
    END
  END tap_d[268]
  PIN tap_d[269]
    DIRECTION OUTPUT ;
    USE SIGNAL ;
    PORT
      LAYER M4 ;
        RECT  0 53.712 0.084 53.736 ;
    END
  END tap_d[269]
  PIN tap_d[26]
    DIRECTION OUTPUT ;
    USE SIGNAL ;
    PORT
      LAYER M4 ;
        RECT  0 29.568 0.084 29.592 ;
    END
  END tap_d[26]
  PIN tap_d[270]
    DIRECTION OUTPUT ;
    USE SIGNAL ;
    PORT
      LAYER M4 ;
        RECT  0 53.808 0.084 53.832 ;
    END
  END tap_d[270]
  PIN tap_d[271]
    DIRECTION OUTPUT ;
    USE SIGNAL ;
    PORT
      LAYER M4 ;
        RECT  0 53.904 0.084 53.928 ;
    END
  END tap_d[271]
  PIN tap_d[272]
    DIRECTION OUTPUT ;
    USE SIGNAL ;
    PORT
      LAYER M4 ;
        RECT  0 54 0.084 54.024 ;
    END
  END tap_d[272]
  PIN tap_d[273]
    DIRECTION OUTPUT ;
    USE SIGNAL ;
    PORT
      LAYER M4 ;
        RECT  0 54.096 0.084 54.12 ;
    END
  END tap_d[273]
  PIN tap_d[274]
    DIRECTION OUTPUT ;
    USE SIGNAL ;
    PORT
      LAYER M4 ;
        RECT  0 54.192 0.084 54.216 ;
    END
  END tap_d[274]
  PIN tap_d[275]
    DIRECTION OUTPUT ;
    USE SIGNAL ;
    PORT
      LAYER M4 ;
        RECT  0 54.336 0.084 54.36 ;
    END
  END tap_d[275]
  PIN tap_d[276]
    DIRECTION OUTPUT ;
    USE SIGNAL ;
    PORT
      LAYER M4 ;
        RECT  0 54.432 0.084 54.456 ;
    END
  END tap_d[276]
  PIN tap_d[277]
    DIRECTION OUTPUT ;
    USE SIGNAL ;
    PORT
      LAYER M4 ;
        RECT  0 54.528 0.084 54.552 ;
    END
  END tap_d[277]
  PIN tap_d[278]
    DIRECTION OUTPUT ;
    USE SIGNAL ;
    PORT
      LAYER M4 ;
        RECT  0 54.624 0.084 54.648 ;
    END
  END tap_d[278]
  PIN tap_d[279]
    DIRECTION OUTPUT ;
    USE SIGNAL ;
    PORT
      LAYER M4 ;
        RECT  0 54.72 0.084 54.744 ;
    END
  END tap_d[279]
  PIN tap_d[27]
    DIRECTION OUTPUT ;
    USE SIGNAL ;
    PORT
      LAYER M4 ;
        RECT  0 29.664 0.084 29.688 ;
    END
  END tap_d[27]
  PIN tap_d[280]
    DIRECTION OUTPUT ;
    USE SIGNAL ;
    PORT
      LAYER M4 ;
        RECT  0 54.816 0.084 54.84 ;
    END
  END tap_d[280]
  PIN tap_d[281]
    DIRECTION OUTPUT ;
    USE SIGNAL ;
    PORT
      LAYER M4 ;
        RECT  0 54.912 0.084 54.936 ;
    END
  END tap_d[281]
  PIN tap_d[282]
    DIRECTION OUTPUT ;
    USE SIGNAL ;
    PORT
      LAYER M4 ;
        RECT  0 55.008 0.084 55.032 ;
    END
  END tap_d[282]
  PIN tap_d[283]
    DIRECTION OUTPUT ;
    USE SIGNAL ;
    PORT
      LAYER M4 ;
        RECT  0 55.104 0.084 55.128 ;
    END
  END tap_d[283]
  PIN tap_d[284]
    DIRECTION OUTPUT ;
    USE SIGNAL ;
    PORT
      LAYER M4 ;
        RECT  0 55.2 0.084 55.224 ;
    END
  END tap_d[284]
  PIN tap_d[285]
    DIRECTION OUTPUT ;
    USE SIGNAL ;
    PORT
      LAYER M4 ;
        RECT  0 55.296 0.084 55.32 ;
    END
  END tap_d[285]
  PIN tap_d[286]
    DIRECTION OUTPUT ;
    USE SIGNAL ;
    PORT
      LAYER M4 ;
        RECT  0 55.392 0.084 55.416 ;
    END
  END tap_d[286]
  PIN tap_d[287]
    DIRECTION OUTPUT ;
    USE SIGNAL ;
    PORT
      LAYER M4 ;
        RECT  0 55.488 0.084 55.512 ;
    END
  END tap_d[287]
  PIN tap_d[288]
    DIRECTION OUTPUT ;
    USE SIGNAL ;
    PORT
      LAYER M4 ;
        RECT  0 55.584 0.084 55.608 ;
    END
  END tap_d[288]
  PIN tap_d[289]
    DIRECTION OUTPUT ;
    USE SIGNAL ;
    PORT
      LAYER M4 ;
        RECT  0 55.728 0.084 55.752 ;
    END
  END tap_d[289]
  PIN tap_d[28]
    DIRECTION OUTPUT ;
    USE SIGNAL ;
    PORT
      LAYER M4 ;
        RECT  0 29.76 0.084 29.784 ;
    END
  END tap_d[28]
  PIN tap_d[290]
    DIRECTION OUTPUT ;
    USE SIGNAL ;
    PORT
      LAYER M4 ;
        RECT  0 55.824 0.084 55.848 ;
    END
  END tap_d[290]
  PIN tap_d[291]
    DIRECTION OUTPUT ;
    USE SIGNAL ;
    PORT
      LAYER M4 ;
        RECT  0 55.92 0.084 55.944 ;
    END
  END tap_d[291]
  PIN tap_d[292]
    DIRECTION OUTPUT ;
    USE SIGNAL ;
    PORT
      LAYER M4 ;
        RECT  0 56.016 0.084 56.04 ;
    END
  END tap_d[292]
  PIN tap_d[293]
    DIRECTION OUTPUT ;
    USE SIGNAL ;
    PORT
      LAYER M4 ;
        RECT  0 56.112 0.084 56.136 ;
    END
  END tap_d[293]
  PIN tap_d[294]
    DIRECTION OUTPUT ;
    USE SIGNAL ;
    PORT
      LAYER M4 ;
        RECT  0 56.208 0.084 56.232 ;
    END
  END tap_d[294]
  PIN tap_d[295]
    DIRECTION OUTPUT ;
    USE SIGNAL ;
    PORT
      LAYER M4 ;
        RECT  0 56.304 0.084 56.328 ;
    END
  END tap_d[295]
  PIN tap_d[296]
    DIRECTION OUTPUT ;
    USE SIGNAL ;
    PORT
      LAYER M4 ;
        RECT  0 56.4 0.084 56.424 ;
    END
  END tap_d[296]
  PIN tap_d[297]
    DIRECTION OUTPUT ;
    USE SIGNAL ;
    PORT
      LAYER M4 ;
        RECT  0 56.496 0.084 56.52 ;
    END
  END tap_d[297]
  PIN tap_d[298]
    DIRECTION OUTPUT ;
    USE SIGNAL ;
    PORT
      LAYER M4 ;
        RECT  0 56.592 0.084 56.616 ;
    END
  END tap_d[298]
  PIN tap_d[299]
    DIRECTION OUTPUT ;
    USE SIGNAL ;
    PORT
      LAYER M4 ;
        RECT  0 56.688 0.084 56.712 ;
    END
  END tap_d[299]
  PIN tap_d[29]
    DIRECTION OUTPUT ;
    USE SIGNAL ;
    PORT
      LAYER M4 ;
        RECT  0 29.856 0.084 29.88 ;
    END
  END tap_d[29]
  PIN tap_d[2]
    DIRECTION OUTPUT ;
    USE SIGNAL ;
    PORT
      LAYER M4 ;
        RECT  0 27.168 0.084 27.192 ;
    END
  END tap_d[2]
  PIN tap_d[300]
    DIRECTION OUTPUT ;
    USE SIGNAL ;
    PORT
      LAYER M4 ;
        RECT  0 56.784 0.084 56.808 ;
    END
  END tap_d[300]
  PIN tap_d[301]
    DIRECTION OUTPUT ;
    USE SIGNAL ;
    PORT
      LAYER M4 ;
        RECT  0 56.88 0.084 56.904 ;
    END
  END tap_d[301]
  PIN tap_d[302]
    DIRECTION OUTPUT ;
    USE SIGNAL ;
    PORT
      LAYER M4 ;
        RECT  0 56.976 0.084 57 ;
    END
  END tap_d[302]
  PIN tap_d[303]
    DIRECTION OUTPUT ;
    USE SIGNAL ;
    PORT
      LAYER M4 ;
        RECT  0 57.12 0.084 57.144 ;
    END
  END tap_d[303]
  PIN tap_d[304]
    DIRECTION OUTPUT ;
    USE SIGNAL ;
    PORT
      LAYER M4 ;
        RECT  0 57.216 0.084 57.24 ;
    END
  END tap_d[304]
  PIN tap_d[305]
    DIRECTION OUTPUT ;
    USE SIGNAL ;
    PORT
      LAYER M4 ;
        RECT  0 57.312 0.084 57.336 ;
    END
  END tap_d[305]
  PIN tap_d[306]
    DIRECTION OUTPUT ;
    USE SIGNAL ;
    PORT
      LAYER M4 ;
        RECT  0 57.408 0.084 57.432 ;
    END
  END tap_d[306]
  PIN tap_d[307]
    DIRECTION OUTPUT ;
    USE SIGNAL ;
    PORT
      LAYER M4 ;
        RECT  0 57.504 0.084 57.528 ;
    END
  END tap_d[307]
  PIN tap_d[308]
    DIRECTION OUTPUT ;
    USE SIGNAL ;
    PORT
      LAYER M4 ;
        RECT  0 57.6 0.084 57.624 ;
    END
  END tap_d[308]
  PIN tap_d[309]
    DIRECTION OUTPUT ;
    USE SIGNAL ;
    PORT
      LAYER M4 ;
        RECT  0 57.696 0.084 57.72 ;
    END
  END tap_d[309]
  PIN tap_d[30]
    DIRECTION OUTPUT ;
    USE SIGNAL ;
    PORT
      LAYER M4 ;
        RECT  0 29.952 0.084 29.976 ;
    END
  END tap_d[30]
  PIN tap_d[310]
    DIRECTION OUTPUT ;
    USE SIGNAL ;
    PORT
      LAYER M4 ;
        RECT  0 57.792 0.084 57.816 ;
    END
  END tap_d[310]
  PIN tap_d[311]
    DIRECTION OUTPUT ;
    USE SIGNAL ;
    PORT
      LAYER M4 ;
        RECT  0 57.888 0.084 57.912 ;
    END
  END tap_d[311]
  PIN tap_d[312]
    DIRECTION OUTPUT ;
    USE SIGNAL ;
    PORT
      LAYER M4 ;
        RECT  0 57.984 0.084 58.008 ;
    END
  END tap_d[312]
  PIN tap_d[313]
    DIRECTION OUTPUT ;
    USE SIGNAL ;
    PORT
      LAYER M4 ;
        RECT  0 58.08 0.084 58.104 ;
    END
  END tap_d[313]
  PIN tap_d[314]
    DIRECTION OUTPUT ;
    USE SIGNAL ;
    PORT
      LAYER M4 ;
        RECT  0 58.176 0.084 58.2 ;
    END
  END tap_d[314]
  PIN tap_d[315]
    DIRECTION OUTPUT ;
    USE SIGNAL ;
    PORT
      LAYER M4 ;
        RECT  0 58.272 0.084 58.296 ;
    END
  END tap_d[315]
  PIN tap_d[316]
    DIRECTION OUTPUT ;
    USE SIGNAL ;
    PORT
      LAYER M4 ;
        RECT  0 58.368 0.084 58.392 ;
    END
  END tap_d[316]
  PIN tap_d[317]
    DIRECTION OUTPUT ;
    USE SIGNAL ;
    PORT
      LAYER M4 ;
        RECT  0 58.512 0.084 58.536 ;
    END
  END tap_d[317]
  PIN tap_d[318]
    DIRECTION OUTPUT ;
    USE SIGNAL ;
    PORT
      LAYER M4 ;
        RECT  0 58.608 0.084 58.632 ;
    END
  END tap_d[318]
  PIN tap_d[319]
    DIRECTION OUTPUT ;
    USE SIGNAL ;
    PORT
      LAYER M4 ;
        RECT  0 58.704 0.084 58.728 ;
    END
  END tap_d[319]
  PIN tap_d[31]
    DIRECTION OUTPUT ;
    USE SIGNAL ;
    PORT
      LAYER M4 ;
        RECT  0 30.048 0.084 30.072 ;
    END
  END tap_d[31]
  PIN tap_d[320]
    DIRECTION OUTPUT ;
    USE SIGNAL ;
    PORT
      LAYER M4 ;
        RECT  0 58.8 0.084 58.824 ;
    END
  END tap_d[320]
  PIN tap_d[321]
    DIRECTION OUTPUT ;
    USE SIGNAL ;
    PORT
      LAYER M4 ;
        RECT  0 58.896 0.084 58.92 ;
    END
  END tap_d[321]
  PIN tap_d[322]
    DIRECTION OUTPUT ;
    USE SIGNAL ;
    PORT
      LAYER M4 ;
        RECT  0 58.992 0.084 59.016 ;
    END
  END tap_d[322]
  PIN tap_d[323]
    DIRECTION OUTPUT ;
    USE SIGNAL ;
    PORT
      LAYER M4 ;
        RECT  0 59.088 0.084 59.112 ;
    END
  END tap_d[323]
  PIN tap_d[324]
    DIRECTION OUTPUT ;
    USE SIGNAL ;
    PORT
      LAYER M4 ;
        RECT  0 59.184 0.084 59.208 ;
    END
  END tap_d[324]
  PIN tap_d[325]
    DIRECTION OUTPUT ;
    USE SIGNAL ;
    PORT
      LAYER M4 ;
        RECT  0 59.28 0.084 59.304 ;
    END
  END tap_d[325]
  PIN tap_d[326]
    DIRECTION OUTPUT ;
    USE SIGNAL ;
    PORT
      LAYER M4 ;
        RECT  0 59.376 0.084 59.4 ;
    END
  END tap_d[326]
  PIN tap_d[327]
    DIRECTION OUTPUT ;
    USE SIGNAL ;
    PORT
      LAYER M4 ;
        RECT  0 59.472 0.084 59.496 ;
    END
  END tap_d[327]
  PIN tap_d[328]
    DIRECTION OUTPUT ;
    USE SIGNAL ;
    PORT
      LAYER M4 ;
        RECT  0 59.568 0.084 59.592 ;
    END
  END tap_d[328]
  PIN tap_d[329]
    DIRECTION OUTPUT ;
    USE SIGNAL ;
    PORT
      LAYER M4 ;
        RECT  0 59.664 0.084 59.688 ;
    END
  END tap_d[329]
  PIN tap_d[32]
    DIRECTION OUTPUT ;
    USE SIGNAL ;
    PORT
      LAYER M4 ;
        RECT  0 30.144 0.084 30.168 ;
    END
  END tap_d[32]
  PIN tap_d[330]
    DIRECTION OUTPUT ;
    USE SIGNAL ;
    PORT
      LAYER M4 ;
        RECT  0 59.76 0.084 59.784 ;
    END
  END tap_d[330]
  PIN tap_d[331]
    DIRECTION OUTPUT ;
    USE SIGNAL ;
    PORT
      LAYER M4 ;
        RECT  0 59.904 0.084 59.928 ;
    END
  END tap_d[331]
  PIN tap_d[332]
    DIRECTION OUTPUT ;
    USE SIGNAL ;
    PORT
      LAYER M4 ;
        RECT  0 60 0.084 60.024 ;
    END
  END tap_d[332]
  PIN tap_d[333]
    DIRECTION OUTPUT ;
    USE SIGNAL ;
    PORT
      LAYER M4 ;
        RECT  0 60.096 0.084 60.12 ;
    END
  END tap_d[333]
  PIN tap_d[334]
    DIRECTION OUTPUT ;
    USE SIGNAL ;
    PORT
      LAYER M4 ;
        RECT  0 60.192 0.084 60.216 ;
    END
  END tap_d[334]
  PIN tap_d[335]
    DIRECTION OUTPUT ;
    USE SIGNAL ;
    PORT
      LAYER M4 ;
        RECT  0 60.288 0.084 60.312 ;
    END
  END tap_d[335]
  PIN tap_d[336]
    DIRECTION OUTPUT ;
    USE SIGNAL ;
    PORT
      LAYER M4 ;
        RECT  0 60.384 0.084 60.408 ;
    END
  END tap_d[336]
  PIN tap_d[337]
    DIRECTION OUTPUT ;
    USE SIGNAL ;
    PORT
      LAYER M4 ;
        RECT  0 60.48 0.084 60.504 ;
    END
  END tap_d[337]
  PIN tap_d[338]
    DIRECTION OUTPUT ;
    USE SIGNAL ;
    PORT
      LAYER M4 ;
        RECT  0 60.576 0.084 60.6 ;
    END
  END tap_d[338]
  PIN tap_d[339]
    DIRECTION OUTPUT ;
    USE SIGNAL ;
    PORT
      LAYER M4 ;
        RECT  0 60.672 0.084 60.696 ;
    END
  END tap_d[339]
  PIN tap_d[33]
    DIRECTION OUTPUT ;
    USE SIGNAL ;
    PORT
      LAYER M4 ;
        RECT  0 30.24 0.084 30.264 ;
    END
  END tap_d[33]
  PIN tap_d[340]
    DIRECTION OUTPUT ;
    USE SIGNAL ;
    PORT
      LAYER M4 ;
        RECT  0 60.768 0.084 60.792 ;
    END
  END tap_d[340]
  PIN tap_d[341]
    DIRECTION OUTPUT ;
    USE SIGNAL ;
    PORT
      LAYER M4 ;
        RECT  0 60.864 0.084 60.888 ;
    END
  END tap_d[341]
  PIN tap_d[342]
    DIRECTION OUTPUT ;
    USE SIGNAL ;
    PORT
      LAYER M4 ;
        RECT  0 60.96 0.084 60.984 ;
    END
  END tap_d[342]
  PIN tap_d[343]
    DIRECTION OUTPUT ;
    USE SIGNAL ;
    PORT
      LAYER M4 ;
        RECT  0 61.056 0.084 61.08 ;
    END
  END tap_d[343]
  PIN tap_d[344]
    DIRECTION OUTPUT ;
    USE SIGNAL ;
    PORT
      LAYER M4 ;
        RECT  0 61.152 0.084 61.176 ;
    END
  END tap_d[344]
  PIN tap_d[345]
    DIRECTION OUTPUT ;
    USE SIGNAL ;
    PORT
      LAYER M4 ;
        RECT  0 61.248 0.084 61.272 ;
    END
  END tap_d[345]
  PIN tap_d[346]
    DIRECTION OUTPUT ;
    USE SIGNAL ;
    PORT
      LAYER M4 ;
        RECT  0 61.392 0.084 61.416 ;
    END
  END tap_d[346]
  PIN tap_d[347]
    DIRECTION OUTPUT ;
    USE SIGNAL ;
    PORT
      LAYER M4 ;
        RECT  0 61.488 0.084 61.512 ;
    END
  END tap_d[347]
  PIN tap_d[348]
    DIRECTION OUTPUT ;
    USE SIGNAL ;
    PORT
      LAYER M4 ;
        RECT  0 61.584 0.084 61.608 ;
    END
  END tap_d[348]
  PIN tap_d[349]
    DIRECTION OUTPUT ;
    USE SIGNAL ;
    PORT
      LAYER M4 ;
        RECT  0 61.68 0.084 61.704 ;
    END
  END tap_d[349]
  PIN tap_d[34]
    DIRECTION OUTPUT ;
    USE SIGNAL ;
    PORT
      LAYER M4 ;
        RECT  0 30.336 0.084 30.36 ;
    END
  END tap_d[34]
  PIN tap_d[350]
    DIRECTION OUTPUT ;
    USE SIGNAL ;
    PORT
      LAYER M4 ;
        RECT  0 61.776 0.084 61.8 ;
    END
  END tap_d[350]
  PIN tap_d[351]
    DIRECTION OUTPUT ;
    USE SIGNAL ;
    PORT
      LAYER M4 ;
        RECT  0 61.872 0.084 61.896 ;
    END
  END tap_d[351]
  PIN tap_d[352]
    DIRECTION OUTPUT ;
    USE SIGNAL ;
    PORT
      LAYER M4 ;
        RECT  0 61.968 0.084 61.992 ;
    END
  END tap_d[352]
  PIN tap_d[353]
    DIRECTION OUTPUT ;
    USE SIGNAL ;
    PORT
      LAYER M4 ;
        RECT  0 62.064 0.084 62.088 ;
    END
  END tap_d[353]
  PIN tap_d[354]
    DIRECTION OUTPUT ;
    USE SIGNAL ;
    PORT
      LAYER M4 ;
        RECT  0 62.16 0.084 62.184 ;
    END
  END tap_d[354]
  PIN tap_d[355]
    DIRECTION OUTPUT ;
    USE SIGNAL ;
    PORT
      LAYER M4 ;
        RECT  0 62.256 0.084 62.28 ;
    END
  END tap_d[355]
  PIN tap_d[356]
    DIRECTION OUTPUT ;
    USE SIGNAL ;
    PORT
      LAYER M4 ;
        RECT  0 62.352 0.084 62.376 ;
    END
  END tap_d[356]
  PIN tap_d[357]
    DIRECTION OUTPUT ;
    USE SIGNAL ;
    PORT
      LAYER M4 ;
        RECT  0 62.448 0.084 62.472 ;
    END
  END tap_d[357]
  PIN tap_d[358]
    DIRECTION OUTPUT ;
    USE SIGNAL ;
    PORT
      LAYER M4 ;
        RECT  0 62.544 0.084 62.568 ;
    END
  END tap_d[358]
  PIN tap_d[359]
    DIRECTION OUTPUT ;
    USE SIGNAL ;
    PORT
      LAYER M4 ;
        RECT  0 62.64 0.084 62.664 ;
    END
  END tap_d[359]
  PIN tap_d[35]
    DIRECTION OUTPUT ;
    USE SIGNAL ;
    PORT
      LAYER M4 ;
        RECT  0 30.48 0.084 30.504 ;
    END
  END tap_d[35]
  PIN tap_d[360]
    DIRECTION OUTPUT ;
    USE SIGNAL ;
    PORT
      LAYER M4 ;
        RECT  0 62.784 0.084 62.808 ;
    END
  END tap_d[360]
  PIN tap_d[361]
    DIRECTION OUTPUT ;
    USE SIGNAL ;
    PORT
      LAYER M4 ;
        RECT  0 62.88 0.084 62.904 ;
    END
  END tap_d[361]
  PIN tap_d[362]
    DIRECTION OUTPUT ;
    USE SIGNAL ;
    PORT
      LAYER M4 ;
        RECT  0 62.976 0.084 63 ;
    END
  END tap_d[362]
  PIN tap_d[363]
    DIRECTION OUTPUT ;
    USE SIGNAL ;
    PORT
      LAYER M4 ;
        RECT  0 63.072 0.084 63.096 ;
    END
  END tap_d[363]
  PIN tap_d[364]
    DIRECTION OUTPUT ;
    USE SIGNAL ;
    PORT
      LAYER M4 ;
        RECT  0 63.168 0.084 63.192 ;
    END
  END tap_d[364]
  PIN tap_d[365]
    DIRECTION OUTPUT ;
    USE SIGNAL ;
    PORT
      LAYER M4 ;
        RECT  0 63.264 0.084 63.288 ;
    END
  END tap_d[365]
  PIN tap_d[366]
    DIRECTION OUTPUT ;
    USE SIGNAL ;
    PORT
      LAYER M4 ;
        RECT  0 63.36 0.084 63.384 ;
    END
  END tap_d[366]
  PIN tap_d[367]
    DIRECTION OUTPUT ;
    USE SIGNAL ;
    PORT
      LAYER M4 ;
        RECT  0 63.456 0.084 63.48 ;
    END
  END tap_d[367]
  PIN tap_d[368]
    DIRECTION OUTPUT ;
    USE SIGNAL ;
    PORT
      LAYER M4 ;
        RECT  0 63.552 0.084 63.576 ;
    END
  END tap_d[368]
  PIN tap_d[369]
    DIRECTION OUTPUT ;
    USE SIGNAL ;
    PORT
      LAYER M4 ;
        RECT  0 63.648 0.084 63.672 ;
    END
  END tap_d[369]
  PIN tap_d[36]
    DIRECTION OUTPUT ;
    USE SIGNAL ;
    PORT
      LAYER M4 ;
        RECT  0 30.576 0.084 30.6 ;
    END
  END tap_d[36]
  PIN tap_d[370]
    DIRECTION OUTPUT ;
    USE SIGNAL ;
    PORT
      LAYER M4 ;
        RECT  0 63.744 0.084 63.768 ;
    END
  END tap_d[370]
  PIN tap_d[371]
    DIRECTION OUTPUT ;
    USE SIGNAL ;
    PORT
      LAYER M4 ;
        RECT  0 63.84 0.084 63.864 ;
    END
  END tap_d[371]
  PIN tap_d[372]
    DIRECTION OUTPUT ;
    USE SIGNAL ;
    PORT
      LAYER M4 ;
        RECT  0 63.936 0.084 63.96 ;
    END
  END tap_d[372]
  PIN tap_d[373]
    DIRECTION OUTPUT ;
    USE SIGNAL ;
    PORT
      LAYER M4 ;
        RECT  0 64.032 0.084 64.056 ;
    END
  END tap_d[373]
  PIN tap_d[374]
    DIRECTION OUTPUT ;
    USE SIGNAL ;
    PORT
      LAYER M4 ;
        RECT  0 64.176 0.084 64.2 ;
    END
  END tap_d[374]
  PIN tap_d[375]
    DIRECTION OUTPUT ;
    USE SIGNAL ;
    PORT
      LAYER M4 ;
        RECT  0 64.272 0.084 64.296 ;
    END
  END tap_d[375]
  PIN tap_d[376]
    DIRECTION OUTPUT ;
    USE SIGNAL ;
    PORT
      LAYER M4 ;
        RECT  0 64.368 0.084 64.392 ;
    END
  END tap_d[376]
  PIN tap_d[377]
    DIRECTION OUTPUT ;
    USE SIGNAL ;
    PORT
      LAYER M4 ;
        RECT  0 64.464 0.084 64.488 ;
    END
  END tap_d[377]
  PIN tap_d[378]
    DIRECTION OUTPUT ;
    USE SIGNAL ;
    PORT
      LAYER M4 ;
        RECT  0 64.56 0.084 64.584 ;
    END
  END tap_d[378]
  PIN tap_d[379]
    DIRECTION OUTPUT ;
    USE SIGNAL ;
    PORT
      LAYER M4 ;
        RECT  0 64.656 0.084 64.68 ;
    END
  END tap_d[379]
  PIN tap_d[37]
    DIRECTION OUTPUT ;
    USE SIGNAL ;
    PORT
      LAYER M4 ;
        RECT  0 30.672 0.084 30.696 ;
    END
  END tap_d[37]
  PIN tap_d[380]
    DIRECTION OUTPUT ;
    USE SIGNAL ;
    PORT
      LAYER M4 ;
        RECT  0 64.752 0.084 64.776 ;
    END
  END tap_d[380]
  PIN tap_d[381]
    DIRECTION OUTPUT ;
    USE SIGNAL ;
    PORT
      LAYER M4 ;
        RECT  0 64.848 0.084 64.872 ;
    END
  END tap_d[381]
  PIN tap_d[382]
    DIRECTION OUTPUT ;
    USE SIGNAL ;
    PORT
      LAYER M4 ;
        RECT  0 64.944 0.084 64.968 ;
    END
  END tap_d[382]
  PIN tap_d[383]
    DIRECTION OUTPUT ;
    USE SIGNAL ;
    PORT
      LAYER M4 ;
        RECT  0 65.04 0.084 65.064 ;
    END
  END tap_d[383]
  PIN tap_d[384]
    DIRECTION OUTPUT ;
    USE SIGNAL ;
    PORT
      LAYER M4 ;
        RECT  0 65.136 0.084 65.16 ;
    END
  END tap_d[384]
  PIN tap_d[385]
    DIRECTION OUTPUT ;
    USE SIGNAL ;
    PORT
      LAYER M4 ;
        RECT  0 65.232 0.084 65.256 ;
    END
  END tap_d[385]
  PIN tap_d[386]
    DIRECTION OUTPUT ;
    USE SIGNAL ;
    PORT
      LAYER M4 ;
        RECT  0 65.328 0.084 65.352 ;
    END
  END tap_d[386]
  PIN tap_d[387]
    DIRECTION OUTPUT ;
    USE SIGNAL ;
    PORT
      LAYER M4 ;
        RECT  0 65.424 0.084 65.448 ;
    END
  END tap_d[387]
  PIN tap_d[388]
    DIRECTION OUTPUT ;
    USE SIGNAL ;
    PORT
      LAYER M4 ;
        RECT  0 65.568 0.084 65.592 ;
    END
  END tap_d[388]
  PIN tap_d[389]
    DIRECTION OUTPUT ;
    USE SIGNAL ;
    PORT
      LAYER M4 ;
        RECT  0 65.664 0.084 65.688 ;
    END
  END tap_d[389]
  PIN tap_d[38]
    DIRECTION OUTPUT ;
    USE SIGNAL ;
    PORT
      LAYER M4 ;
        RECT  0 30.768 0.084 30.792 ;
    END
  END tap_d[38]
  PIN tap_d[390]
    DIRECTION OUTPUT ;
    USE SIGNAL ;
    PORT
      LAYER M4 ;
        RECT  0 65.76 0.084 65.784 ;
    END
  END tap_d[390]
  PIN tap_d[391]
    DIRECTION OUTPUT ;
    USE SIGNAL ;
    PORT
      LAYER M4 ;
        RECT  0 65.856 0.084 65.88 ;
    END
  END tap_d[391]
  PIN tap_d[392]
    DIRECTION OUTPUT ;
    USE SIGNAL ;
    PORT
      LAYER M4 ;
        RECT  0 65.952 0.084 65.976 ;
    END
  END tap_d[392]
  PIN tap_d[393]
    DIRECTION OUTPUT ;
    USE SIGNAL ;
    PORT
      LAYER M4 ;
        RECT  0 66.048 0.084 66.072 ;
    END
  END tap_d[393]
  PIN tap_d[394]
    DIRECTION OUTPUT ;
    USE SIGNAL ;
    PORT
      LAYER M4 ;
        RECT  0 66.144 0.084 66.168 ;
    END
  END tap_d[394]
  PIN tap_d[395]
    DIRECTION OUTPUT ;
    USE SIGNAL ;
    PORT
      LAYER M4 ;
        RECT  0 66.24 0.084 66.264 ;
    END
  END tap_d[395]
  PIN tap_d[396]
    DIRECTION OUTPUT ;
    USE SIGNAL ;
    PORT
      LAYER M4 ;
        RECT  0 66.336 0.084 66.36 ;
    END
  END tap_d[396]
  PIN tap_d[397]
    DIRECTION OUTPUT ;
    USE SIGNAL ;
    PORT
      LAYER M4 ;
        RECT  0 66.432 0.084 66.456 ;
    END
  END tap_d[397]
  PIN tap_d[398]
    DIRECTION OUTPUT ;
    USE SIGNAL ;
    PORT
      LAYER M4 ;
        RECT  0 66.528 0.084 66.552 ;
    END
  END tap_d[398]
  PIN tap_d[399]
    DIRECTION OUTPUT ;
    USE SIGNAL ;
    PORT
      LAYER M4 ;
        RECT  0 66.624 0.084 66.648 ;
    END
  END tap_d[399]
  PIN tap_d[39]
    DIRECTION OUTPUT ;
    USE SIGNAL ;
    PORT
      LAYER M4 ;
        RECT  0 30.864 0.084 30.888 ;
    END
  END tap_d[39]
  PIN tap_d[3]
    DIRECTION OUTPUT ;
    USE SIGNAL ;
    PORT
      LAYER M4 ;
        RECT  0 27.264 0.084 27.288 ;
    END
  END tap_d[3]
  PIN tap_d[400]
    DIRECTION OUTPUT ;
    USE SIGNAL ;
    PORT
      LAYER M4 ;
        RECT  0 66.72 0.084 66.744 ;
    END
  END tap_d[400]
  PIN tap_d[401]
    DIRECTION OUTPUT ;
    USE SIGNAL ;
    PORT
      LAYER M4 ;
        RECT  0 66.816 0.084 66.84 ;
    END
  END tap_d[401]
  PIN tap_d[402]
    DIRECTION OUTPUT ;
    USE SIGNAL ;
    PORT
      LAYER M4 ;
        RECT  0 66.96 0.084 66.984 ;
    END
  END tap_d[402]
  PIN tap_d[403]
    DIRECTION OUTPUT ;
    USE SIGNAL ;
    PORT
      LAYER M4 ;
        RECT  0 67.056 0.084 67.08 ;
    END
  END tap_d[403]
  PIN tap_d[404]
    DIRECTION OUTPUT ;
    USE SIGNAL ;
    PORT
      LAYER M4 ;
        RECT  0 67.152 0.084 67.176 ;
    END
  END tap_d[404]
  PIN tap_d[405]
    DIRECTION OUTPUT ;
    USE SIGNAL ;
    PORT
      LAYER M4 ;
        RECT  0 67.248 0.084 67.272 ;
    END
  END tap_d[405]
  PIN tap_d[406]
    DIRECTION OUTPUT ;
    USE SIGNAL ;
    PORT
      LAYER M4 ;
        RECT  0 67.344 0.084 67.368 ;
    END
  END tap_d[406]
  PIN tap_d[407]
    DIRECTION OUTPUT ;
    USE SIGNAL ;
    PORT
      LAYER M4 ;
        RECT  0 67.44 0.084 67.464 ;
    END
  END tap_d[407]
  PIN tap_d[408]
    DIRECTION OUTPUT ;
    USE SIGNAL ;
    PORT
      LAYER M4 ;
        RECT  0 67.536 0.084 67.56 ;
    END
  END tap_d[408]
  PIN tap_d[409]
    DIRECTION OUTPUT ;
    USE SIGNAL ;
    PORT
      LAYER M4 ;
        RECT  0 67.632 0.084 67.656 ;
    END
  END tap_d[409]
  PIN tap_d[40]
    DIRECTION OUTPUT ;
    USE SIGNAL ;
    PORT
      LAYER M4 ;
        RECT  0 30.96 0.084 30.984 ;
    END
  END tap_d[40]
  PIN tap_d[410]
    DIRECTION OUTPUT ;
    USE SIGNAL ;
    PORT
      LAYER M4 ;
        RECT  0 67.728 0.084 67.752 ;
    END
  END tap_d[410]
  PIN tap_d[411]
    DIRECTION OUTPUT ;
    USE SIGNAL ;
    PORT
      LAYER M4 ;
        RECT  0 67.824 0.084 67.848 ;
    END
  END tap_d[411]
  PIN tap_d[412]
    DIRECTION OUTPUT ;
    USE SIGNAL ;
    PORT
      LAYER M4 ;
        RECT  0 67.92 0.084 67.944 ;
    END
  END tap_d[412]
  PIN tap_d[413]
    DIRECTION OUTPUT ;
    USE SIGNAL ;
    PORT
      LAYER M4 ;
        RECT  0 68.016 0.084 68.04 ;
    END
  END tap_d[413]
  PIN tap_d[414]
    DIRECTION OUTPUT ;
    USE SIGNAL ;
    PORT
      LAYER M4 ;
        RECT  0 68.112 0.084 68.136 ;
    END
  END tap_d[414]
  PIN tap_d[415]
    DIRECTION OUTPUT ;
    USE SIGNAL ;
    PORT
      LAYER M4 ;
        RECT  0 68.208 0.084 68.232 ;
    END
  END tap_d[415]
  PIN tap_d[416]
    DIRECTION OUTPUT ;
    USE SIGNAL ;
    PORT
      LAYER M4 ;
        RECT  0 68.352 0.084 68.376 ;
    END
  END tap_d[416]
  PIN tap_d[417]
    DIRECTION OUTPUT ;
    USE SIGNAL ;
    PORT
      LAYER M4 ;
        RECT  0 68.448 0.084 68.472 ;
    END
  END tap_d[417]
  PIN tap_d[418]
    DIRECTION OUTPUT ;
    USE SIGNAL ;
    PORT
      LAYER M4 ;
        RECT  0 68.544 0.084 68.568 ;
    END
  END tap_d[418]
  PIN tap_d[419]
    DIRECTION OUTPUT ;
    USE SIGNAL ;
    PORT
      LAYER M4 ;
        RECT  0 68.64 0.084 68.664 ;
    END
  END tap_d[419]
  PIN tap_d[41]
    DIRECTION OUTPUT ;
    USE SIGNAL ;
    PORT
      LAYER M4 ;
        RECT  0 31.056 0.084 31.08 ;
    END
  END tap_d[41]
  PIN tap_d[420]
    DIRECTION OUTPUT ;
    USE SIGNAL ;
    PORT
      LAYER M4 ;
        RECT  0 68.736 0.084 68.76 ;
    END
  END tap_d[420]
  PIN tap_d[421]
    DIRECTION OUTPUT ;
    USE SIGNAL ;
    PORT
      LAYER M4 ;
        RECT  0 68.832 0.084 68.856 ;
    END
  END tap_d[421]
  PIN tap_d[422]
    DIRECTION OUTPUT ;
    USE SIGNAL ;
    PORT
      LAYER M4 ;
        RECT  0 68.928 0.084 68.952 ;
    END
  END tap_d[422]
  PIN tap_d[423]
    DIRECTION OUTPUT ;
    USE SIGNAL ;
    PORT
      LAYER M4 ;
        RECT  0 69.024 0.084 69.048 ;
    END
  END tap_d[423]
  PIN tap_d[424]
    DIRECTION OUTPUT ;
    USE SIGNAL ;
    PORT
      LAYER M4 ;
        RECT  0 69.12 0.084 69.144 ;
    END
  END tap_d[424]
  PIN tap_d[425]
    DIRECTION OUTPUT ;
    USE SIGNAL ;
    PORT
      LAYER M4 ;
        RECT  0 69.216 0.084 69.24 ;
    END
  END tap_d[425]
  PIN tap_d[426]
    DIRECTION OUTPUT ;
    USE SIGNAL ;
    PORT
      LAYER M4 ;
        RECT  0 69.312 0.084 69.336 ;
    END
  END tap_d[426]
  PIN tap_d[427]
    DIRECTION OUTPUT ;
    USE SIGNAL ;
    PORT
      LAYER M4 ;
        RECT  0 69.408 0.084 69.432 ;
    END
  END tap_d[427]
  PIN tap_d[428]
    DIRECTION OUTPUT ;
    USE SIGNAL ;
    PORT
      LAYER M4 ;
        RECT  0 69.504 0.084 69.528 ;
    END
  END tap_d[428]
  PIN tap_d[429]
    DIRECTION OUTPUT ;
    USE SIGNAL ;
    PORT
      LAYER M4 ;
        RECT  0 69.6 0.084 69.624 ;
    END
  END tap_d[429]
  PIN tap_d[42]
    DIRECTION OUTPUT ;
    USE SIGNAL ;
    PORT
      LAYER M4 ;
        RECT  0 31.152 0.084 31.176 ;
    END
  END tap_d[42]
  PIN tap_d[430]
    DIRECTION OUTPUT ;
    USE SIGNAL ;
    PORT
      LAYER M4 ;
        RECT  0 69.744 0.084 69.768 ;
    END
  END tap_d[430]
  PIN tap_d[431]
    DIRECTION OUTPUT ;
    USE SIGNAL ;
    PORT
      LAYER M4 ;
        RECT  0 69.84 0.084 69.864 ;
    END
  END tap_d[431]
  PIN tap_d[432]
    DIRECTION OUTPUT ;
    USE SIGNAL ;
    PORT
      LAYER M4 ;
        RECT  0 69.936 0.084 69.96 ;
    END
  END tap_d[432]
  PIN tap_d[433]
    DIRECTION OUTPUT ;
    USE SIGNAL ;
    PORT
      LAYER M4 ;
        RECT  0 70.032 0.084 70.056 ;
    END
  END tap_d[433]
  PIN tap_d[434]
    DIRECTION OUTPUT ;
    USE SIGNAL ;
    PORT
      LAYER M4 ;
        RECT  0 70.128 0.084 70.152 ;
    END
  END tap_d[434]
  PIN tap_d[435]
    DIRECTION OUTPUT ;
    USE SIGNAL ;
    PORT
      LAYER M4 ;
        RECT  0 70.224 0.084 70.248 ;
    END
  END tap_d[435]
  PIN tap_d[436]
    DIRECTION OUTPUT ;
    USE SIGNAL ;
    PORT
      LAYER M4 ;
        RECT  0 70.32 0.084 70.344 ;
    END
  END tap_d[436]
  PIN tap_d[437]
    DIRECTION OUTPUT ;
    USE SIGNAL ;
    PORT
      LAYER M4 ;
        RECT  0 70.416 0.084 70.44 ;
    END
  END tap_d[437]
  PIN tap_d[438]
    DIRECTION OUTPUT ;
    USE SIGNAL ;
    PORT
      LAYER M4 ;
        RECT  0 70.512 0.084 70.536 ;
    END
  END tap_d[438]
  PIN tap_d[439]
    DIRECTION OUTPUT ;
    USE SIGNAL ;
    PORT
      LAYER M4 ;
        RECT  0 70.608 0.084 70.632 ;
    END
  END tap_d[439]
  PIN tap_d[43]
    DIRECTION OUTPUT ;
    USE SIGNAL ;
    PORT
      LAYER M4 ;
        RECT  0 31.248 0.084 31.272 ;
    END
  END tap_d[43]
  PIN tap_d[440]
    DIRECTION OUTPUT ;
    USE SIGNAL ;
    PORT
      LAYER M4 ;
        RECT  0 70.704 0.084 70.728 ;
    END
  END tap_d[440]
  PIN tap_d[441]
    DIRECTION OUTPUT ;
    USE SIGNAL ;
    PORT
      LAYER M4 ;
        RECT  0 70.8 0.084 70.824 ;
    END
  END tap_d[441]
  PIN tap_d[442]
    DIRECTION OUTPUT ;
    USE SIGNAL ;
    PORT
      LAYER M4 ;
        RECT  0 70.896 0.084 70.92 ;
    END
  END tap_d[442]
  PIN tap_d[443]
    DIRECTION OUTPUT ;
    USE SIGNAL ;
    PORT
      LAYER M4 ;
        RECT  0 70.992 0.084 71.016 ;
    END
  END tap_d[443]
  PIN tap_d[444]
    DIRECTION OUTPUT ;
    USE SIGNAL ;
    PORT
      LAYER M4 ;
        RECT  0 71.136 0.084 71.16 ;
    END
  END tap_d[444]
  PIN tap_d[445]
    DIRECTION OUTPUT ;
    USE SIGNAL ;
    PORT
      LAYER M4 ;
        RECT  0 71.232 0.084 71.256 ;
    END
  END tap_d[445]
  PIN tap_d[446]
    DIRECTION OUTPUT ;
    USE SIGNAL ;
    PORT
      LAYER M4 ;
        RECT  0 71.328 0.084 71.352 ;
    END
  END tap_d[446]
  PIN tap_d[447]
    DIRECTION OUTPUT ;
    USE SIGNAL ;
    PORT
      LAYER M4 ;
        RECT  0 71.424 0.084 71.448 ;
    END
  END tap_d[447]
  PIN tap_d[448]
    DIRECTION OUTPUT ;
    USE SIGNAL ;
    PORT
      LAYER M4 ;
        RECT  0 71.52 0.084 71.544 ;
    END
  END tap_d[448]
  PIN tap_d[449]
    DIRECTION OUTPUT ;
    USE SIGNAL ;
    PORT
      LAYER M4 ;
        RECT  0 71.616 0.084 71.64 ;
    END
  END tap_d[449]
  PIN tap_d[44]
    DIRECTION OUTPUT ;
    USE SIGNAL ;
    PORT
      LAYER M4 ;
        RECT  0 31.344 0.084 31.368 ;
    END
  END tap_d[44]
  PIN tap_d[450]
    DIRECTION OUTPUT ;
    USE SIGNAL ;
    PORT
      LAYER M4 ;
        RECT  0 71.712 0.084 71.736 ;
    END
  END tap_d[450]
  PIN tap_d[451]
    DIRECTION OUTPUT ;
    USE SIGNAL ;
    PORT
      LAYER M4 ;
        RECT  0 71.808 0.084 71.832 ;
    END
  END tap_d[451]
  PIN tap_d[452]
    DIRECTION OUTPUT ;
    USE SIGNAL ;
    PORT
      LAYER M4 ;
        RECT  0 71.904 0.084 71.928 ;
    END
  END tap_d[452]
  PIN tap_d[453]
    DIRECTION OUTPUT ;
    USE SIGNAL ;
    PORT
      LAYER M4 ;
        RECT  0 72 0.084 72.024 ;
    END
  END tap_d[453]
  PIN tap_d[454]
    DIRECTION OUTPUT ;
    USE SIGNAL ;
    PORT
      LAYER M4 ;
        RECT  0 72.096 0.084 72.12 ;
    END
  END tap_d[454]
  PIN tap_d[455]
    DIRECTION OUTPUT ;
    USE SIGNAL ;
    PORT
      LAYER M4 ;
        RECT  0 72.192 0.084 72.216 ;
    END
  END tap_d[455]
  PIN tap_d[456]
    DIRECTION OUTPUT ;
    USE SIGNAL ;
    PORT
      LAYER M4 ;
        RECT  0 72.288 0.084 72.312 ;
    END
  END tap_d[456]
  PIN tap_d[457]
    DIRECTION OUTPUT ;
    USE SIGNAL ;
    PORT
      LAYER M4 ;
        RECT  0 72.384 0.084 72.408 ;
    END
  END tap_d[457]
  PIN tap_d[458]
    DIRECTION OUTPUT ;
    USE SIGNAL ;
    PORT
      LAYER M4 ;
        RECT  0 72.528 0.084 72.552 ;
    END
  END tap_d[458]
  PIN tap_d[459]
    DIRECTION OUTPUT ;
    USE SIGNAL ;
    PORT
      LAYER M4 ;
        RECT  0 72.624 0.084 72.648 ;
    END
  END tap_d[459]
  PIN tap_d[45]
    DIRECTION OUTPUT ;
    USE SIGNAL ;
    PORT
      LAYER M4 ;
        RECT  0 31.44 0.084 31.464 ;
    END
  END tap_d[45]
  PIN tap_d[460]
    DIRECTION OUTPUT ;
    USE SIGNAL ;
    PORT
      LAYER M4 ;
        RECT  0 72.72 0.084 72.744 ;
    END
  END tap_d[460]
  PIN tap_d[461]
    DIRECTION OUTPUT ;
    USE SIGNAL ;
    PORT
      LAYER M4 ;
        RECT  0 72.816 0.084 72.84 ;
    END
  END tap_d[461]
  PIN tap_d[462]
    DIRECTION OUTPUT ;
    USE SIGNAL ;
    PORT
      LAYER M4 ;
        RECT  0 72.912 0.084 72.936 ;
    END
  END tap_d[462]
  PIN tap_d[463]
    DIRECTION OUTPUT ;
    USE SIGNAL ;
    PORT
      LAYER M4 ;
        RECT  0 73.008 0.084 73.032 ;
    END
  END tap_d[463]
  PIN tap_d[464]
    DIRECTION OUTPUT ;
    USE SIGNAL ;
    PORT
      LAYER M4 ;
        RECT  0 73.104 0.084 73.128 ;
    END
  END tap_d[464]
  PIN tap_d[465]
    DIRECTION OUTPUT ;
    USE SIGNAL ;
    PORT
      LAYER M4 ;
        RECT  0 73.2 0.084 73.224 ;
    END
  END tap_d[465]
  PIN tap_d[466]
    DIRECTION OUTPUT ;
    USE SIGNAL ;
    PORT
      LAYER M4 ;
        RECT  0 73.296 0.084 73.32 ;
    END
  END tap_d[466]
  PIN tap_d[467]
    DIRECTION OUTPUT ;
    USE SIGNAL ;
    PORT
      LAYER M4 ;
        RECT  0 73.392 0.084 73.416 ;
    END
  END tap_d[467]
  PIN tap_d[468]
    DIRECTION OUTPUT ;
    USE SIGNAL ;
    PORT
      LAYER M4 ;
        RECT  0 73.488 0.084 73.512 ;
    END
  END tap_d[468]
  PIN tap_d[469]
    DIRECTION OUTPUT ;
    USE SIGNAL ;
    PORT
      LAYER M4 ;
        RECT  0 73.584 0.084 73.608 ;
    END
  END tap_d[469]
  PIN tap_d[46]
    DIRECTION OUTPUT ;
    USE SIGNAL ;
    PORT
      LAYER M4 ;
        RECT  0 31.536 0.084 31.56 ;
    END
  END tap_d[46]
  PIN tap_d[470]
    DIRECTION OUTPUT ;
    USE SIGNAL ;
    PORT
      LAYER M4 ;
        RECT  0 73.68 0.084 73.704 ;
    END
  END tap_d[470]
  PIN tap_d[471]
    DIRECTION OUTPUT ;
    USE SIGNAL ;
    PORT
      LAYER M4 ;
        RECT  0 73.776 0.084 73.8 ;
    END
  END tap_d[471]
  PIN tap_d[472]
    DIRECTION OUTPUT ;
    USE SIGNAL ;
    PORT
      LAYER M4 ;
        RECT  0 73.872 0.084 73.896 ;
    END
  END tap_d[472]
  PIN tap_d[473]
    DIRECTION OUTPUT ;
    USE SIGNAL ;
    PORT
      LAYER M4 ;
        RECT  0 74.016 0.084 74.04 ;
    END
  END tap_d[473]
  PIN tap_d[474]
    DIRECTION OUTPUT ;
    USE SIGNAL ;
    PORT
      LAYER M4 ;
        RECT  0 74.112 0.084 74.136 ;
    END
  END tap_d[474]
  PIN tap_d[475]
    DIRECTION OUTPUT ;
    USE SIGNAL ;
    PORT
      LAYER M4 ;
        RECT  0 74.208 0.084 74.232 ;
    END
  END tap_d[475]
  PIN tap_d[476]
    DIRECTION OUTPUT ;
    USE SIGNAL ;
    PORT
      LAYER M4 ;
        RECT  0 74.304 0.084 74.328 ;
    END
  END tap_d[476]
  PIN tap_d[477]
    DIRECTION OUTPUT ;
    USE SIGNAL ;
    PORT
      LAYER M4 ;
        RECT  0 74.4 0.084 74.424 ;
    END
  END tap_d[477]
  PIN tap_d[478]
    DIRECTION OUTPUT ;
    USE SIGNAL ;
    PORT
      LAYER M4 ;
        RECT  0 74.496 0.084 74.52 ;
    END
  END tap_d[478]
  PIN tap_d[479]
    DIRECTION OUTPUT ;
    USE SIGNAL ;
    PORT
      LAYER M4 ;
        RECT  0 74.592 0.084 74.616 ;
    END
  END tap_d[479]
  PIN tap_d[47]
    DIRECTION OUTPUT ;
    USE SIGNAL ;
    PORT
      LAYER M4 ;
        RECT  0 31.632 0.084 31.656 ;
    END
  END tap_d[47]
  PIN tap_d[480]
    DIRECTION OUTPUT ;
    USE SIGNAL ;
    PORT
      LAYER M4 ;
        RECT  0 74.688 0.084 74.712 ;
    END
  END tap_d[480]
  PIN tap_d[481]
    DIRECTION OUTPUT ;
    USE SIGNAL ;
    PORT
      LAYER M4 ;
        RECT  0 74.784 0.084 74.808 ;
    END
  END tap_d[481]
  PIN tap_d[482]
    DIRECTION OUTPUT ;
    USE SIGNAL ;
    PORT
      LAYER M4 ;
        RECT  0 74.88 0.084 74.904 ;
    END
  END tap_d[482]
  PIN tap_d[483]
    DIRECTION OUTPUT ;
    USE SIGNAL ;
    PORT
      LAYER M4 ;
        RECT  0 74.976 0.084 75 ;
    END
  END tap_d[483]
  PIN tap_d[484]
    DIRECTION OUTPUT ;
    USE SIGNAL ;
    PORT
      LAYER M4 ;
        RECT  0 75.072 0.084 75.096 ;
    END
  END tap_d[484]
  PIN tap_d[485]
    DIRECTION OUTPUT ;
    USE SIGNAL ;
    PORT
      LAYER M4 ;
        RECT  0 75.168 0.084 75.192 ;
    END
  END tap_d[485]
  PIN tap_d[486]
    DIRECTION OUTPUT ;
    USE SIGNAL ;
    PORT
      LAYER M4 ;
        RECT  0 75.264 0.084 75.288 ;
    END
  END tap_d[486]
  PIN tap_d[487]
    DIRECTION OUTPUT ;
    USE SIGNAL ;
    PORT
      LAYER M4 ;
        RECT  0 75.408 0.084 75.432 ;
    END
  END tap_d[487]
  PIN tap_d[488]
    DIRECTION OUTPUT ;
    USE SIGNAL ;
    PORT
      LAYER M4 ;
        RECT  0 75.504 0.084 75.528 ;
    END
  END tap_d[488]
  PIN tap_d[489]
    DIRECTION OUTPUT ;
    USE SIGNAL ;
    PORT
      LAYER M4 ;
        RECT  0 75.6 0.084 75.624 ;
    END
  END tap_d[489]
  PIN tap_d[48]
    DIRECTION OUTPUT ;
    USE SIGNAL ;
    PORT
      LAYER M4 ;
        RECT  0 31.728 0.084 31.752 ;
    END
  END tap_d[48]
  PIN tap_d[490]
    DIRECTION OUTPUT ;
    USE SIGNAL ;
    PORT
      LAYER M4 ;
        RECT  0 75.696 0.084 75.72 ;
    END
  END tap_d[490]
  PIN tap_d[491]
    DIRECTION OUTPUT ;
    USE SIGNAL ;
    PORT
      LAYER M4 ;
        RECT  0 75.792 0.084 75.816 ;
    END
  END tap_d[491]
  PIN tap_d[492]
    DIRECTION OUTPUT ;
    USE SIGNAL ;
    PORT
      LAYER M4 ;
        RECT  0 75.888 0.084 75.912 ;
    END
  END tap_d[492]
  PIN tap_d[493]
    DIRECTION OUTPUT ;
    USE SIGNAL ;
    PORT
      LAYER M4 ;
        RECT  0 75.984 0.084 76.008 ;
    END
  END tap_d[493]
  PIN tap_d[494]
    DIRECTION OUTPUT ;
    USE SIGNAL ;
    PORT
      LAYER M4 ;
        RECT  0 76.08 0.084 76.104 ;
    END
  END tap_d[494]
  PIN tap_d[495]
    DIRECTION OUTPUT ;
    USE SIGNAL ;
    PORT
      LAYER M4 ;
        RECT  0 76.176 0.084 76.2 ;
    END
  END tap_d[495]
  PIN tap_d[496]
    DIRECTION OUTPUT ;
    USE SIGNAL ;
    PORT
      LAYER M4 ;
        RECT  0 76.272 0.084 76.296 ;
    END
  END tap_d[496]
  PIN tap_d[497]
    DIRECTION OUTPUT ;
    USE SIGNAL ;
    PORT
      LAYER M4 ;
        RECT  0 76.368 0.084 76.392 ;
    END
  END tap_d[497]
  PIN tap_d[498]
    DIRECTION OUTPUT ;
    USE SIGNAL ;
    PORT
      LAYER M4 ;
        RECT  0 76.464 0.084 76.488 ;
    END
  END tap_d[498]
  PIN tap_d[499]
    DIRECTION OUTPUT ;
    USE SIGNAL ;
    PORT
      LAYER M4 ;
        RECT  0 76.56 0.084 76.584 ;
    END
  END tap_d[499]
  PIN tap_d[49]
    DIRECTION OUTPUT ;
    USE SIGNAL ;
    PORT
      LAYER M4 ;
        RECT  0 31.872 0.084 31.896 ;
    END
  END tap_d[49]
  PIN tap_d[4]
    DIRECTION OUTPUT ;
    USE SIGNAL ;
    PORT
      LAYER M4 ;
        RECT  0 27.36 0.084 27.384 ;
    END
  END tap_d[4]
  PIN tap_d[500]
    DIRECTION OUTPUT ;
    USE SIGNAL ;
    PORT
      LAYER M4 ;
        RECT  0 76.656 0.084 76.68 ;
    END
  END tap_d[500]
  PIN tap_d[501]
    DIRECTION OUTPUT ;
    USE SIGNAL ;
    PORT
      LAYER M4 ;
        RECT  0 76.8 0.084 76.824 ;
    END
  END tap_d[501]
  PIN tap_d[502]
    DIRECTION OUTPUT ;
    USE SIGNAL ;
    PORT
      LAYER M4 ;
        RECT  0 76.896 0.084 76.92 ;
    END
  END tap_d[502]
  PIN tap_d[503]
    DIRECTION OUTPUT ;
    USE SIGNAL ;
    PORT
      LAYER M4 ;
        RECT  0 76.992 0.084 77.016 ;
    END
  END tap_d[503]
  PIN tap_d[504]
    DIRECTION OUTPUT ;
    USE SIGNAL ;
    PORT
      LAYER M4 ;
        RECT  0 77.088 0.084 77.112 ;
    END
  END tap_d[504]
  PIN tap_d[505]
    DIRECTION OUTPUT ;
    USE SIGNAL ;
    PORT
      LAYER M4 ;
        RECT  0 77.184 0.084 77.208 ;
    END
  END tap_d[505]
  PIN tap_d[506]
    DIRECTION OUTPUT ;
    USE SIGNAL ;
    PORT
      LAYER M4 ;
        RECT  0 77.28 0.084 77.304 ;
    END
  END tap_d[506]
  PIN tap_d[507]
    DIRECTION OUTPUT ;
    USE SIGNAL ;
    PORT
      LAYER M4 ;
        RECT  0 77.376 0.084 77.4 ;
    END
  END tap_d[507]
  PIN tap_d[50]
    DIRECTION OUTPUT ;
    USE SIGNAL ;
    PORT
      LAYER M4 ;
        RECT  0 31.968 0.084 31.992 ;
    END
  END tap_d[50]
  PIN tap_d[51]
    DIRECTION OUTPUT ;
    USE SIGNAL ;
    PORT
      LAYER M4 ;
        RECT  0 32.064 0.084 32.088 ;
    END
  END tap_d[51]
  PIN tap_d[52]
    DIRECTION OUTPUT ;
    USE SIGNAL ;
    PORT
      LAYER M4 ;
        RECT  0 32.16 0.084 32.184 ;
    END
  END tap_d[52]
  PIN tap_d[53]
    DIRECTION OUTPUT ;
    USE SIGNAL ;
    PORT
      LAYER M4 ;
        RECT  0 32.256 0.084 32.28 ;
    END
  END tap_d[53]
  PIN tap_d[54]
    DIRECTION OUTPUT ;
    USE SIGNAL ;
    PORT
      LAYER M4 ;
        RECT  0 32.352 0.084 32.376 ;
    END
  END tap_d[54]
  PIN tap_d[55]
    DIRECTION OUTPUT ;
    USE SIGNAL ;
    PORT
      LAYER M4 ;
        RECT  0 32.448 0.084 32.472 ;
    END
  END tap_d[55]
  PIN tap_d[56]
    DIRECTION OUTPUT ;
    USE SIGNAL ;
    PORT
      LAYER M4 ;
        RECT  0 32.544 0.084 32.568 ;
    END
  END tap_d[56]
  PIN tap_d[57]
    DIRECTION OUTPUT ;
    USE SIGNAL ;
    PORT
      LAYER M4 ;
        RECT  0 32.64 0.084 32.664 ;
    END
  END tap_d[57]
  PIN tap_d[58]
    DIRECTION OUTPUT ;
    USE SIGNAL ;
    PORT
      LAYER M4 ;
        RECT  0 32.736 0.084 32.76 ;
    END
  END tap_d[58]
  PIN tap_d[59]
    DIRECTION OUTPUT ;
    USE SIGNAL ;
    PORT
      LAYER M4 ;
        RECT  0 32.832 0.084 32.856 ;
    END
  END tap_d[59]
  PIN tap_d[5]
    DIRECTION OUTPUT ;
    USE SIGNAL ;
    PORT
      LAYER M4 ;
        RECT  0 27.456 0.084 27.48 ;
    END
  END tap_d[5]
  PIN tap_d[60]
    DIRECTION OUTPUT ;
    USE SIGNAL ;
    PORT
      LAYER M4 ;
        RECT  0 32.928 0.084 32.952 ;
    END
  END tap_d[60]
  PIN tap_d[61]
    DIRECTION OUTPUT ;
    USE SIGNAL ;
    PORT
      LAYER M4 ;
        RECT  0 33.024 0.084 33.048 ;
    END
  END tap_d[61]
  PIN tap_d[62]
    DIRECTION OUTPUT ;
    USE SIGNAL ;
    PORT
      LAYER M4 ;
        RECT  0 33.12 0.084 33.144 ;
    END
  END tap_d[62]
  PIN tap_d[63]
    DIRECTION OUTPUT ;
    USE SIGNAL ;
    PORT
      LAYER M4 ;
        RECT  0 33.264 0.084 33.288 ;
    END
  END tap_d[63]
  PIN tap_d[64]
    DIRECTION OUTPUT ;
    USE SIGNAL ;
    PORT
      LAYER M4 ;
        RECT  0 33.36 0.084 33.384 ;
    END
  END tap_d[64]
  PIN tap_d[65]
    DIRECTION OUTPUT ;
    USE SIGNAL ;
    PORT
      LAYER M4 ;
        RECT  0 33.456 0.084 33.48 ;
    END
  END tap_d[65]
  PIN tap_d[66]
    DIRECTION OUTPUT ;
    USE SIGNAL ;
    PORT
      LAYER M4 ;
        RECT  0 33.552 0.084 33.576 ;
    END
  END tap_d[66]
  PIN tap_d[67]
    DIRECTION OUTPUT ;
    USE SIGNAL ;
    PORT
      LAYER M4 ;
        RECT  0 33.648 0.084 33.672 ;
    END
  END tap_d[67]
  PIN tap_d[68]
    DIRECTION OUTPUT ;
    USE SIGNAL ;
    PORT
      LAYER M4 ;
        RECT  0 33.744 0.084 33.768 ;
    END
  END tap_d[68]
  PIN tap_d[69]
    DIRECTION OUTPUT ;
    USE SIGNAL ;
    PORT
      LAYER M4 ;
        RECT  0 33.84 0.084 33.864 ;
    END
  END tap_d[69]
  PIN tap_d[6]
    DIRECTION OUTPUT ;
    USE SIGNAL ;
    PORT
      LAYER M4 ;
        RECT  0 27.552 0.084 27.576 ;
    END
  END tap_d[6]
  PIN tap_d[70]
    DIRECTION OUTPUT ;
    USE SIGNAL ;
    PORT
      LAYER M4 ;
        RECT  0 33.936 0.084 33.96 ;
    END
  END tap_d[70]
  PIN tap_d[71]
    DIRECTION OUTPUT ;
    USE SIGNAL ;
    PORT
      LAYER M4 ;
        RECT  0 34.032 0.084 34.056 ;
    END
  END tap_d[71]
  PIN tap_d[72]
    DIRECTION OUTPUT ;
    USE SIGNAL ;
    PORT
      LAYER M4 ;
        RECT  0 34.128 0.084 34.152 ;
    END
  END tap_d[72]
  PIN tap_d[73]
    DIRECTION OUTPUT ;
    USE SIGNAL ;
    PORT
      LAYER M4 ;
        RECT  0 34.224 0.084 34.248 ;
    END
  END tap_d[73]
  PIN tap_d[74]
    DIRECTION OUTPUT ;
    USE SIGNAL ;
    PORT
      LAYER M4 ;
        RECT  0 34.32 0.084 34.344 ;
    END
  END tap_d[74]
  PIN tap_d[75]
    DIRECTION OUTPUT ;
    USE SIGNAL ;
    PORT
      LAYER M4 ;
        RECT  0 34.416 0.084 34.44 ;
    END
  END tap_d[75]
  PIN tap_d[76]
    DIRECTION OUTPUT ;
    USE SIGNAL ;
    PORT
      LAYER M4 ;
        RECT  0 34.512 0.084 34.536 ;
    END
  END tap_d[76]
  PIN tap_d[77]
    DIRECTION OUTPUT ;
    USE SIGNAL ;
    PORT
      LAYER M4 ;
        RECT  0 34.656 0.084 34.68 ;
    END
  END tap_d[77]
  PIN tap_d[78]
    DIRECTION OUTPUT ;
    USE SIGNAL ;
    PORT
      LAYER M4 ;
        RECT  0 34.752 0.084 34.776 ;
    END
  END tap_d[78]
  PIN tap_d[79]
    DIRECTION OUTPUT ;
    USE SIGNAL ;
    PORT
      LAYER M4 ;
        RECT  0 34.848 0.084 34.872 ;
    END
  END tap_d[79]
  PIN tap_d[7]
    DIRECTION OUTPUT ;
    USE SIGNAL ;
    PORT
      LAYER M4 ;
        RECT  0 27.696 0.084 27.72 ;
    END
  END tap_d[7]
  PIN tap_d[80]
    DIRECTION OUTPUT ;
    USE SIGNAL ;
    PORT
      LAYER M4 ;
        RECT  0 34.944 0.084 34.968 ;
    END
  END tap_d[80]
  PIN tap_d[81]
    DIRECTION OUTPUT ;
    USE SIGNAL ;
    PORT
      LAYER M4 ;
        RECT  0 35.04 0.084 35.064 ;
    END
  END tap_d[81]
  PIN tap_d[82]
    DIRECTION OUTPUT ;
    USE SIGNAL ;
    PORT
      LAYER M4 ;
        RECT  0 35.136 0.084 35.16 ;
    END
  END tap_d[82]
  PIN tap_d[83]
    DIRECTION OUTPUT ;
    USE SIGNAL ;
    PORT
      LAYER M4 ;
        RECT  0 35.232 0.084 35.256 ;
    END
  END tap_d[83]
  PIN tap_d[84]
    DIRECTION OUTPUT ;
    USE SIGNAL ;
    PORT
      LAYER M4 ;
        RECT  0 35.328 0.084 35.352 ;
    END
  END tap_d[84]
  PIN tap_d[85]
    DIRECTION OUTPUT ;
    USE SIGNAL ;
    PORT
      LAYER M4 ;
        RECT  0 35.424 0.084 35.448 ;
    END
  END tap_d[85]
  PIN tap_d[86]
    DIRECTION OUTPUT ;
    USE SIGNAL ;
    PORT
      LAYER M4 ;
        RECT  0 35.52 0.084 35.544 ;
    END
  END tap_d[86]
  PIN tap_d[87]
    DIRECTION OUTPUT ;
    USE SIGNAL ;
    PORT
      LAYER M4 ;
        RECT  0 35.616 0.084 35.64 ;
    END
  END tap_d[87]
  PIN tap_d[88]
    DIRECTION OUTPUT ;
    USE SIGNAL ;
    PORT
      LAYER M4 ;
        RECT  0 35.712 0.084 35.736 ;
    END
  END tap_d[88]
  PIN tap_d[89]
    DIRECTION OUTPUT ;
    USE SIGNAL ;
    PORT
      LAYER M4 ;
        RECT  0 35.808 0.084 35.832 ;
    END
  END tap_d[89]
  PIN tap_d[8]
    DIRECTION OUTPUT ;
    USE SIGNAL ;
    PORT
      LAYER M4 ;
        RECT  0 27.792 0.084 27.816 ;
    END
  END tap_d[8]
  PIN tap_d[90]
    DIRECTION OUTPUT ;
    USE SIGNAL ;
    PORT
      LAYER M4 ;
        RECT  0 35.904 0.084 35.928 ;
    END
  END tap_d[90]
  PIN tap_d[91]
    DIRECTION OUTPUT ;
    USE SIGNAL ;
    PORT
      LAYER M4 ;
        RECT  0 36 0.084 36.024 ;
    END
  END tap_d[91]
  PIN tap_d[92]
    DIRECTION OUTPUT ;
    USE SIGNAL ;
    PORT
      LAYER M4 ;
        RECT  0 36.144 0.084 36.168 ;
    END
  END tap_d[92]
  PIN tap_d[93]
    DIRECTION OUTPUT ;
    USE SIGNAL ;
    PORT
      LAYER M4 ;
        RECT  0 36.24 0.084 36.264 ;
    END
  END tap_d[93]
  PIN tap_d[94]
    DIRECTION OUTPUT ;
    USE SIGNAL ;
    PORT
      LAYER M4 ;
        RECT  0 36.336 0.084 36.36 ;
    END
  END tap_d[94]
  PIN tap_d[95]
    DIRECTION OUTPUT ;
    USE SIGNAL ;
    PORT
      LAYER M4 ;
        RECT  0 36.432 0.084 36.456 ;
    END
  END tap_d[95]
  PIN tap_d[96]
    DIRECTION OUTPUT ;
    USE SIGNAL ;
    PORT
      LAYER M4 ;
        RECT  0 36.528 0.084 36.552 ;
    END
  END tap_d[96]
  PIN tap_d[97]
    DIRECTION OUTPUT ;
    USE SIGNAL ;
    PORT
      LAYER M4 ;
        RECT  0 36.624 0.084 36.648 ;
    END
  END tap_d[97]
  PIN tap_d[98]
    DIRECTION OUTPUT ;
    USE SIGNAL ;
    PORT
      LAYER M4 ;
        RECT  0 36.72 0.084 36.744 ;
    END
  END tap_d[98]
  PIN tap_d[99]
    DIRECTION OUTPUT ;
    USE SIGNAL ;
    PORT
      LAYER M4 ;
        RECT  0 36.816 0.084 36.84 ;
    END
  END tap_d[99]
  PIN tap_d[9]
    DIRECTION OUTPUT ;
    USE SIGNAL ;
    PORT
      LAYER M4 ;
        RECT  0 27.888 0.084 27.912 ;
    END
  END tap_d[9]
  PIN tie_hi
    DIRECTION OUTPUT ;
    USE SIGNAL ;
    PORT
      LAYER M3 ;
        RECT  0.936 103.618 0.954 103.656 ;
    END
  END tie_hi
  PIN tie_lo
    DIRECTION OUTPUT ;
    USE SIGNAL ;
    PORT
      LAYER M3 ;
        RECT  1.188 103.618 1.206 103.656 ;
    END
  END tie_lo
  PIN VDD
    DIRECTION INOUT ;
    USE POWER ;
    PORT
      LAYER M5 ;
        RECT  45.792 2.151 45.912 101.273 ;
        RECT  40.392 2.151 40.512 101.273 ;
        RECT  34.992 2.151 35.112 101.273 ;
        RECT  29.592 2.151 29.712 101.273 ;
        RECT  24.192 2.151 24.312 101.273 ;
        RECT  18.792 2.151 18.912 101.273 ;
        RECT  13.392 2.151 13.512 101.273 ;
        RECT  7.992 2.151 8.112 101.273 ;
        RECT  2.592 2.151 2.712 101.273 ;
    END
  END VDD
  PIN VSS
    DIRECTION INOUT ;
    USE GROUND ;
    PORT
      LAYER M5 ;
        RECT  45.6 2.137 45.72 101.259 ;
        RECT  40.2 2.137 40.32 101.259 ;
        RECT  34.8 2.137 34.92 101.259 ;
        RECT  29.4 2.137 29.52 101.259 ;
        RECT  24 2.137 24.12 101.259 ;
        RECT  18.6 2.137 18.72 101.259 ;
        RECT  13.2 2.137 13.32 101.259 ;
        RECT  7.8 2.137 7.92 101.259 ;
        RECT  2.4 2.137 2.52 101.259 ;
    END
  END VSS
  # OT_OBS_CLOSED layer=M5 d_um=1.536 added=152
  OBS
    LAYER RVTN ;
     RECT  2.16 2.16 50.49 2.295 ;
     RECT  2.16 2.565 50.49 2.835 ;
     RECT  2.16 3.105 50.49 3.375 ;
     RECT  2.16 3.645 50.49 3.915 ;
     RECT  2.16 4.185 50.49 4.455 ;
     RECT  2.16 4.725 50.49 4.995 ;
     RECT  2.16 5.265 50.49 5.535 ;
     RECT  2.16 5.805 50.49 6.075 ;
     RECT  2.16 6.345 50.49 6.615 ;
     RECT  2.16 6.885 50.49 7.155 ;
     RECT  2.16 7.425 50.49 7.695 ;
     RECT  2.16 7.965 50.49 8.235 ;
     RECT  2.16 8.505 50.49 8.775 ;
     RECT  2.16 9.045 50.49 9.315 ;
     RECT  2.16 9.585 50.49 9.855 ;
     RECT  2.16 10.125 50.49 10.395 ;
     RECT  2.16 10.665 50.49 10.935 ;
     RECT  2.16 11.205 50.49 11.475 ;
     RECT  2.16 11.745 50.49 12.015 ;
     RECT  2.16 12.285 50.49 12.555 ;
     RECT  2.16 12.825 50.49 13.095 ;
     RECT  2.16 13.365 50.49 13.635 ;
     RECT  2.16 13.905 50.49 14.175 ;
     RECT  2.16 14.445 50.49 14.715 ;
     RECT  2.16 14.985 50.49 15.255 ;
     RECT  2.16 15.525 50.49 15.795 ;
     RECT  2.16 16.065 50.49 16.335 ;
     RECT  2.16 16.605 50.49 16.875 ;
     RECT  2.16 17.145 50.49 17.415 ;
     RECT  2.16 17.685 50.49 17.955 ;
     RECT  2.16 18.225 50.49 18.495 ;
     RECT  2.16 18.765 50.49 19.035 ;
     RECT  2.16 19.305 50.49 19.575 ;
     RECT  2.16 19.845 50.49 20.115 ;
     RECT  2.16 20.385 50.49 20.655 ;
     RECT  2.16 20.925 50.49 21.195 ;
     RECT  2.16 21.465 50.49 21.735 ;
     RECT  2.16 22.005 50.49 22.275 ;
     RECT  2.16 22.545 50.49 22.815 ;
     RECT  2.16 23.085 50.49 23.355 ;
     RECT  2.16 23.625 50.49 23.895 ;
     RECT  2.16 24.165 50.49 24.435 ;
     RECT  2.16 24.705 50.49 24.975 ;
     RECT  2.16 25.245 50.49 25.515 ;
     RECT  2.16 25.785 50.49 26.055 ;
     RECT  2.16 26.325 50.49 26.595 ;
     RECT  2.16 26.865 50.49 27.135 ;
     RECT  2.16 27.405 50.49 27.675 ;
     RECT  2.16 27.945 50.49 28.215 ;
     RECT  2.16 28.485 50.49 28.755 ;
     RECT  2.16 29.025 50.49 29.295 ;
     RECT  2.16 29.565 50.49 29.835 ;
     RECT  2.16 30.105 50.49 30.375 ;
     RECT  2.16 30.645 50.49 30.915 ;
     RECT  2.16 31.185 50.49 31.455 ;
     RECT  2.16 31.725 50.49 31.995 ;
     RECT  2.16 32.265 50.49 32.535 ;
     RECT  2.16 32.805 50.49 33.075 ;
     RECT  2.16 33.345 50.49 33.615 ;
     RECT  2.16 33.885 50.49 34.155 ;
     RECT  2.16 34.425 50.49 34.695 ;
     RECT  2.16 34.965 50.49 35.235 ;
     RECT  2.16 35.505 50.49 35.775 ;
     RECT  2.16 36.045 50.49 36.315 ;
     RECT  2.16 36.585 50.49 36.855 ;
     RECT  2.16 37.125 50.49 37.395 ;
     RECT  2.16 37.665 50.49 37.935 ;
     RECT  2.16 38.205 50.49 38.475 ;
     RECT  2.16 38.745 50.49 39.015 ;
     RECT  2.16 39.285 50.49 39.555 ;
     RECT  2.16 39.825 50.49 40.095 ;
     RECT  2.16 40.365 50.49 40.635 ;
     RECT  2.16 40.905 50.49 41.175 ;
     RECT  2.16 41.445 50.49 41.715 ;
     RECT  2.16 41.985 50.49 42.255 ;
     RECT  2.16 42.525 50.49 42.795 ;
     RECT  2.16 43.065 50.49 43.335 ;
     RECT  2.16 43.605 50.49 43.875 ;
     RECT  2.16 44.145 50.49 44.415 ;
     RECT  2.16 44.685 50.49 44.955 ;
     RECT  2.16 45.225 50.49 45.495 ;
     RECT  2.16 45.765 50.49 46.035 ;
     RECT  2.16 46.305 50.49 46.575 ;
     RECT  2.16 46.845 50.49 47.115 ;
     RECT  2.16 47.385 50.49 47.655 ;
     RECT  2.16 47.925 50.49 48.195 ;
     RECT  2.16 48.465 50.49 48.735 ;
     RECT  2.16 49.005 50.49 49.275 ;
     RECT  2.16 49.545 50.49 49.815 ;
     RECT  2.16 50.085 50.49 50.355 ;
     RECT  2.16 50.625 50.49 50.895 ;
     RECT  2.16 51.165 50.49 51.435 ;
     RECT  2.16 51.705 50.49 51.975 ;
     RECT  2.16 52.245 50.49 52.515 ;
     RECT  2.16 52.785 50.49 53.055 ;
     RECT  2.16 53.325 50.49 53.595 ;
     RECT  2.16 53.865 50.49 54.135 ;
     RECT  2.16 54.405 50.49 54.675 ;
     RECT  2.16 54.945 50.49 55.215 ;
     RECT  2.16 55.485 50.49 55.755 ;
     RECT  2.16 56.025 50.49 56.295 ;
     RECT  2.16 56.565 50.49 56.835 ;
     RECT  2.16 57.105 50.49 57.375 ;
     RECT  2.16 57.645 50.49 57.915 ;
     RECT  2.16 58.185 50.49 58.455 ;
     RECT  2.16 58.725 50.49 58.995 ;
     RECT  2.16 59.265 50.49 59.535 ;
     RECT  2.16 59.805 50.49 60.075 ;
     RECT  2.16 60.345 50.49 60.615 ;
     RECT  2.16 60.885 50.49 61.155 ;
     RECT  2.16 61.425 50.49 61.695 ;
     RECT  2.16 61.965 50.49 62.235 ;
     RECT  2.16 62.505 50.49 62.775 ;
     RECT  2.16 63.045 50.49 63.315 ;
     RECT  2.16 63.585 50.49 63.855 ;
     RECT  2.16 64.125 50.49 64.395 ;
     RECT  2.16 64.665 50.49 64.935 ;
     RECT  2.16 65.205 50.49 65.475 ;
     RECT  2.16 65.745 50.49 66.015 ;
     RECT  2.16 66.285 50.49 66.555 ;
     RECT  2.16 66.825 50.49 67.095 ;
     RECT  2.16 67.365 50.49 67.635 ;
     RECT  2.16 67.905 50.49 68.175 ;
     RECT  2.16 68.445 50.49 68.715 ;
     RECT  2.16 68.985 50.49 69.255 ;
     RECT  2.16 69.525 50.49 69.795 ;
     RECT  2.16 70.065 50.49 70.335 ;
     RECT  2.16 70.605 50.49 70.875 ;
     RECT  2.16 71.145 50.49 71.415 ;
     RECT  2.16 71.685 50.49 71.955 ;
     RECT  2.16 72.225 50.49 72.495 ;
     RECT  2.16 72.765 50.49 73.035 ;
     RECT  2.16 73.305 50.49 73.575 ;
     RECT  2.16 73.845 50.49 74.115 ;
     RECT  2.16 74.385 50.49 74.655 ;
     RECT  2.16 74.925 50.49 75.195 ;
     RECT  2.16 75.465 50.49 75.735 ;
     RECT  2.16 76.005 50.49 76.275 ;
     RECT  2.16 76.545 50.49 76.815 ;
     RECT  2.16 77.085 50.49 77.355 ;
     RECT  2.16 77.625 50.49 77.895 ;
     RECT  2.16 78.165 50.49 78.435 ;
     RECT  2.16 78.705 50.49 78.975 ;
     RECT  2.16 79.245 50.49 79.515 ;
     RECT  2.16 79.785 50.49 80.055 ;
     RECT  2.16 80.325 50.49 80.595 ;
     RECT  2.16 80.865 50.49 81.135 ;
     RECT  2.16 81.405 50.49 81.675 ;
     RECT  2.16 81.945 50.49 82.215 ;
     RECT  2.16 82.485 50.49 82.755 ;
     RECT  2.16 83.025 50.49 83.295 ;
     RECT  2.16 83.565 50.49 83.835 ;
     RECT  2.16 84.105 50.49 84.375 ;
     RECT  2.16 84.645 50.49 84.915 ;
     RECT  2.16 85.185 50.49 85.455 ;
     RECT  2.16 85.725 50.49 85.995 ;
     RECT  2.16 86.265 50.49 86.535 ;
     RECT  2.16 86.805 50.49 87.075 ;
     RECT  2.16 87.345 50.49 87.615 ;
     RECT  2.16 87.885 50.49 88.155 ;
     RECT  2.16 88.425 50.49 88.695 ;
     RECT  2.16 88.965 50.49 89.235 ;
     RECT  2.16 89.505 50.49 89.775 ;
     RECT  2.16 90.045 50.49 90.315 ;
     RECT  2.16 90.585 50.49 90.855 ;
     RECT  2.16 91.125 50.49 91.395 ;
     RECT  2.16 91.665 50.49 91.935 ;
     RECT  2.16 92.205 50.49 92.475 ;
     RECT  2.16 92.745 50.49 93.015 ;
     RECT  2.16 93.285 50.49 93.555 ;
     RECT  2.16 93.825 50.49 94.095 ;
     RECT  2.16 94.365 50.49 94.635 ;
     RECT  2.16 94.905 50.49 95.175 ;
     RECT  2.16 95.445 50.49 95.715 ;
     RECT  2.16 95.985 50.49 96.255 ;
     RECT  2.16 96.525 50.49 96.795 ;
     RECT  2.16 97.065 50.49 97.335 ;
     RECT  2.16 97.605 50.49 97.875 ;
     RECT  2.16 98.145 50.49 98.415 ;
     RECT  2.16 98.685 50.49 98.955 ;
     RECT  2.16 99.225 50.49 99.495 ;
     RECT  2.16 99.765 50.49 100.035 ;
     RECT  2.16 100.305 50.49 100.575 ;
     RECT  2.16 100.845 50.49 101.115 ;
    LAYER RVTP ;
     RECT  2.16 2.295 50.49 2.565 ;
     RECT  2.16 2.835 50.49 3.105 ;
     RECT  2.16 3.375 50.49 3.645 ;
     RECT  2.16 3.915 50.49 4.185 ;
     RECT  2.16 4.455 50.49 4.725 ;
     RECT  2.16 4.995 50.49 5.265 ;
     RECT  2.16 5.535 50.49 5.805 ;
     RECT  2.16 6.075 50.49 6.345 ;
     RECT  2.16 6.615 50.49 6.885 ;
     RECT  2.16 7.155 50.49 7.425 ;
     RECT  2.16 7.695 50.49 7.965 ;
     RECT  2.16 8.235 50.49 8.505 ;
     RECT  2.16 8.775 50.49 9.045 ;
     RECT  2.16 9.315 50.49 9.585 ;
     RECT  2.16 9.855 50.49 10.125 ;
     RECT  2.16 10.395 50.49 10.665 ;
     RECT  2.16 10.935 50.49 11.205 ;
     RECT  2.16 11.475 50.49 11.745 ;
     RECT  2.16 12.015 50.49 12.285 ;
     RECT  2.16 12.555 50.49 12.825 ;
     RECT  2.16 13.095 50.49 13.365 ;
     RECT  2.16 13.635 50.49 13.905 ;
     RECT  2.16 14.175 50.49 14.445 ;
     RECT  2.16 14.715 50.49 14.985 ;
     RECT  2.16 15.255 50.49 15.525 ;
     RECT  2.16 15.795 50.49 16.065 ;
     RECT  2.16 16.335 50.49 16.605 ;
     RECT  2.16 16.875 50.49 17.145 ;
     RECT  2.16 17.415 50.49 17.685 ;
     RECT  2.16 17.955 50.49 18.225 ;
     RECT  2.16 18.495 50.49 18.765 ;
     RECT  2.16 19.035 50.49 19.305 ;
     RECT  2.16 19.575 50.49 19.845 ;
     RECT  2.16 20.115 50.49 20.385 ;
     RECT  2.16 20.655 50.49 20.925 ;
     RECT  2.16 21.195 50.49 21.465 ;
     RECT  2.16 21.735 50.49 22.005 ;
     RECT  2.16 22.275 50.49 22.545 ;
     RECT  2.16 22.815 50.49 23.085 ;
     RECT  2.16 23.355 50.49 23.625 ;
     RECT  2.16 23.895 50.49 24.165 ;
     RECT  2.16 24.435 50.49 24.705 ;
     RECT  2.16 24.975 50.49 25.245 ;
     RECT  2.16 25.515 50.49 25.785 ;
     RECT  2.16 26.055 50.49 26.325 ;
     RECT  2.16 26.595 50.49 26.865 ;
     RECT  2.16 27.135 50.49 27.405 ;
     RECT  2.16 27.675 50.49 27.945 ;
     RECT  2.16 28.215 50.49 28.485 ;
     RECT  2.16 28.755 50.49 29.025 ;
     RECT  2.16 29.295 50.49 29.565 ;
     RECT  2.16 29.835 50.49 30.105 ;
     RECT  2.16 30.375 50.49 30.645 ;
     RECT  2.16 30.915 50.49 31.185 ;
     RECT  2.16 31.455 50.49 31.725 ;
     RECT  2.16 31.995 50.49 32.265 ;
     RECT  2.16 32.535 50.49 32.805 ;
     RECT  2.16 33.075 50.49 33.345 ;
     RECT  2.16 33.615 50.49 33.885 ;
     RECT  2.16 34.155 50.49 34.425 ;
     RECT  2.16 34.695 50.49 34.965 ;
     RECT  2.16 35.235 50.49 35.505 ;
     RECT  2.16 35.775 50.49 36.045 ;
     RECT  2.16 36.315 50.49 36.585 ;
     RECT  2.16 36.855 50.49 37.125 ;
     RECT  2.16 37.395 50.49 37.665 ;
     RECT  2.16 37.935 50.49 38.205 ;
     RECT  2.16 38.475 50.49 38.745 ;
     RECT  2.16 39.015 50.49 39.285 ;
     RECT  2.16 39.555 50.49 39.825 ;
     RECT  2.16 40.095 50.49 40.365 ;
     RECT  2.16 40.635 50.49 40.905 ;
     RECT  2.16 41.175 50.49 41.445 ;
     RECT  2.16 41.715 50.49 41.985 ;
     RECT  2.16 42.255 50.49 42.525 ;
     RECT  2.16 42.795 50.49 43.065 ;
     RECT  2.16 43.335 50.49 43.605 ;
     RECT  2.16 43.875 50.49 44.145 ;
     RECT  2.16 44.415 50.49 44.685 ;
     RECT  2.16 44.955 50.49 45.225 ;
     RECT  2.16 45.495 50.49 45.765 ;
     RECT  2.16 46.035 50.49 46.305 ;
     RECT  2.16 46.575 50.49 46.845 ;
     RECT  2.16 47.115 50.49 47.385 ;
     RECT  2.16 47.655 50.49 47.925 ;
     RECT  2.16 48.195 50.49 48.465 ;
     RECT  2.16 48.735 50.49 49.005 ;
     RECT  2.16 49.275 50.49 49.545 ;
     RECT  2.16 49.815 50.49 50.085 ;
     RECT  2.16 50.355 50.49 50.625 ;
     RECT  2.16 50.895 50.49 51.165 ;
     RECT  2.16 51.435 50.49 51.705 ;
     RECT  2.16 51.975 50.49 52.245 ;
     RECT  2.16 52.515 50.49 52.785 ;
     RECT  2.16 53.055 50.49 53.325 ;
     RECT  2.16 53.595 50.49 53.865 ;
     RECT  2.16 54.135 50.49 54.405 ;
     RECT  2.16 54.675 50.49 54.945 ;
     RECT  2.16 55.215 50.49 55.485 ;
     RECT  2.16 55.755 50.49 56.025 ;
     RECT  2.16 56.295 50.49 56.565 ;
     RECT  2.16 56.835 50.49 57.105 ;
     RECT  2.16 57.375 50.49 57.645 ;
     RECT  2.16 57.915 50.49 58.185 ;
     RECT  2.16 58.455 50.49 58.725 ;
     RECT  2.16 58.995 50.49 59.265 ;
     RECT  2.16 59.535 50.49 59.805 ;
     RECT  2.16 60.075 50.49 60.345 ;
     RECT  2.16 60.615 50.49 60.885 ;
     RECT  2.16 61.155 50.49 61.425 ;
     RECT  2.16 61.695 50.49 61.965 ;
     RECT  2.16 62.235 50.49 62.505 ;
     RECT  2.16 62.775 50.49 63.045 ;
     RECT  2.16 63.315 50.49 63.585 ;
     RECT  2.16 63.855 50.49 64.125 ;
     RECT  2.16 64.395 50.49 64.665 ;
     RECT  2.16 64.935 50.49 65.205 ;
     RECT  2.16 65.475 50.49 65.745 ;
     RECT  2.16 66.015 50.49 66.285 ;
     RECT  2.16 66.555 50.49 66.825 ;
     RECT  2.16 67.095 50.49 67.365 ;
     RECT  2.16 67.635 50.49 67.905 ;
     RECT  2.16 68.175 50.49 68.445 ;
     RECT  2.16 68.715 50.49 68.985 ;
     RECT  2.16 69.255 50.49 69.525 ;
     RECT  2.16 69.795 50.49 70.065 ;
     RECT  2.16 70.335 50.49 70.605 ;
     RECT  2.16 70.875 50.49 71.145 ;
     RECT  2.16 71.415 50.49 71.685 ;
     RECT  2.16 71.955 50.49 72.225 ;
     RECT  2.16 72.495 50.49 72.765 ;
     RECT  2.16 73.035 50.49 73.305 ;
     RECT  2.16 73.575 50.49 73.845 ;
     RECT  2.16 74.115 50.49 74.385 ;
     RECT  2.16 74.655 50.49 74.925 ;
     RECT  2.16 75.195 50.49 75.465 ;
     RECT  2.16 75.735 50.49 76.005 ;
     RECT  2.16 76.275 50.49 76.545 ;
     RECT  2.16 76.815 50.49 77.085 ;
     RECT  2.16 77.355 50.49 77.625 ;
     RECT  2.16 77.895 50.49 78.165 ;
     RECT  2.16 78.435 50.49 78.705 ;
     RECT  2.16 78.975 50.49 79.245 ;
     RECT  2.16 79.515 50.49 79.785 ;
     RECT  2.16 80.055 50.49 80.325 ;
     RECT  2.16 80.595 50.49 80.865 ;
     RECT  2.16 81.135 50.49 81.405 ;
     RECT  2.16 81.675 50.49 81.945 ;
     RECT  2.16 82.215 50.49 82.485 ;
     RECT  2.16 82.755 50.49 83.025 ;
     RECT  2.16 83.295 50.49 83.565 ;
     RECT  2.16 83.835 50.49 84.105 ;
     RECT  2.16 84.375 50.49 84.645 ;
     RECT  2.16 84.915 50.49 85.185 ;
     RECT  2.16 85.455 50.49 85.725 ;
     RECT  2.16 85.995 50.49 86.265 ;
     RECT  2.16 86.535 50.49 86.805 ;
     RECT  2.16 87.075 50.49 87.345 ;
     RECT  2.16 87.615 50.49 87.885 ;
     RECT  2.16 88.155 50.49 88.425 ;
     RECT  2.16 88.695 50.49 88.965 ;
     RECT  2.16 89.235 50.49 89.505 ;
     RECT  2.16 89.775 50.49 90.045 ;
     RECT  2.16 90.315 50.49 90.585 ;
     RECT  2.16 90.855 50.49 91.125 ;
     RECT  2.16 91.395 50.49 91.665 ;
     RECT  2.16 91.935 50.49 92.205 ;
     RECT  2.16 92.475 50.49 92.745 ;
     RECT  2.16 93.015 50.49 93.285 ;
     RECT  2.16 93.555 50.49 93.825 ;
     RECT  2.16 94.095 50.49 94.365 ;
     RECT  2.16 94.635 50.49 94.905 ;
     RECT  2.16 95.175 50.49 95.445 ;
     RECT  2.16 95.715 50.49 95.985 ;
     RECT  2.16 96.255 50.49 96.525 ;
     RECT  2.16 96.795 50.49 97.065 ;
     RECT  2.16 97.335 50.49 97.605 ;
     RECT  2.16 97.875 50.49 98.145 ;
     RECT  2.16 98.415 50.49 98.685 ;
     RECT  2.16 98.955 50.49 99.225 ;
     RECT  2.16 99.495 50.49 99.765 ;
     RECT  2.16 100.035 50.49 100.305 ;
     RECT  2.16 100.575 50.49 100.845 ;
     RECT  2.16 101.115 50.49 101.25 ;
    LAYER M1 ;
     RECT  2.16 2.151 50.49 101.259 ;
    LAYER M2 ;
     RECT  0.103 44.541 0.139 44.559 ;
     RECT  0.103 76.446 0.139 76.464 ;
     RECT  0.139 26.136 0.175 26.154 ;
     RECT  0.103 35.856 0.175 36.504 ;
     RECT  0.103 66.636 0.175 66.654 ;
     RECT  0.103 29.736 0.203 29.754 ;
     RECT  0.103 34.74 0.203 34.758 ;
     RECT  0.175 35.856 0.203 36.648 ;
     RECT  0.103 37.44 0.203 37.89 ;
     RECT  0.103 39.06 0.203 40.86 ;
     RECT  0.103 41.922 0.203 41.94 ;
     RECT  0.139 43.956 0.203 44.559 ;
     RECT  0.103 47.511 0.203 47.529 ;
     RECT  0.103 50.832 0.203 50.85 ;
     RECT  0.103 52.992 0.203 53.55 ;
     RECT  0.103 55.881 0.203 55.899 ;
     RECT  0.103 57.888 0.203 58.374 ;
     RECT  0.103 61.398 0.203 61.416 ;
     RECT  0.175 25.416 0.211 26.154 ;
     RECT  0.175 27.18 0.211 27.198 ;
     RECT  0.103 28.386 0.211 28.404 ;
     RECT  0.203 43.956 0.239 43.974 ;
     RECT  0.103 48.78 0.239 49.77 ;
     RECT  0.211 28.386 0.247 28.44 ;
     RECT  0.239 48.78 0.347 49.734 ;
     RECT  0.103 62.514 0.347 62.694 ;
     RECT  0.203 36.63 0.383 36.648 ;
     RECT  0.139 75.708 0.383 76.5 ;
     RECT  0.203 39.096 0.419 39.744 ;
     RECT  0.103 72.936 0.463 72.954 ;
     RECT  0.203 53.064 0.499 53.55 ;
     RECT  0.463 72.936 0.499 73.134 ;
     RECT  0.211 25.416 0.535 27.198 ;
     RECT  0.499 30.546 0.535 30.564 ;
     RECT  0.499 31.464 0.535 31.482 ;
     RECT  0.499 32.616 0.535 32.634 ;
     RECT  0.203 40.806 0.535 40.86 ;
     RECT  0.103 46.656 0.535 46.674 ;
     RECT  0.103 59.436 0.535 59.454 ;
     RECT  0.103 67.806 0.535 68.94 ;
     RECT  0.103 69.876 0.535 69.894 ;
     RECT  0.139 71.766 0.535 71.784 ;
     RECT  0.499 72.666 0.535 73.134 ;
     RECT  0.535 31.464 0.599 33.102 ;
     RECT  0.283 98.892 0.679 98.91 ;
     RECT  0.679 98.892 0.931 99.558 ;
     RECT  0.247 28.386 1.147 28.476 ;
     RECT  0.535 67.806 1.147 69.894 ;
     RECT  0.931 98.892 1.183 99.99 ;
     RECT  0.599 31.464 1.211 32.292 ;
     RECT  1.147 5.202 1.255 5.22 ;
     RECT  0.535 25.416 1.255 27.504 ;
     RECT  1.147 28.386 1.255 28.818 ;
     RECT  0.967 4.392 1.363 4.41 ;
     RECT  1.075 2.232 1.543 2.25 ;
     RECT  1.543 2.232 1.651 2.664 ;
     RECT  1.435 97.884 1.651 97.902 ;
     RECT  1.183 98.892 1.651 100.638 ;
     RECT  1.363 4.122 1.723 4.41 ;
     RECT  1.651 97.884 1.723 100.638 ;
     RECT  1.723 77.796 1.795 77.814 ;
     RECT  1.255 5.202 1.831 5.292 ;
     RECT  1.795 77.796 1.831 78.426 ;
     RECT  1.255 25.416 1.867 28.818 ;
     RECT  1.651 2.232 1.903 3.06 ;
     RECT  1.723 3.852 1.903 4.41 ;
     RECT  1.723 97.884 1.903 100.872 ;
     RECT  1.723 96.228 1.939 96.246 ;
     RECT  1.903 97.074 1.939 97.092 ;
     RECT  1.903 97.884 1.939 100.944 ;
     RECT  0.031 23.166 1.975 23.184 ;
     RECT  1.867 25.416 2.011 28.944 ;
     RECT  1.975 22.716 2.083 23.184 ;
     RECT  2.011 25.101 2.083 28.944 ;
     RECT  0.535 71.766 2.083 73.134 ;
     RECT  1.903 2.232 2.119 4.41 ;
     RECT  1.831 5.202 2.119 5.598 ;
     RECT  1.939 6.426 2.119 6.444 ;
     RECT  1.211 31.734 2.119 32.184 ;
     RECT  0.203 35.856 2.119 35.874 ;
     RECT  0.347 49.446 2.119 49.734 ;
     RECT  0.535 50.94 2.119 50.958 ;
     RECT  0.347 62.676 2.119 62.694 ;
     RECT  0.103 63.756 2.119 63.774 ;
     RECT  0.139 64.836 2.119 64.854 ;
     RECT  2.083 71.766 2.119 73.26 ;
     RECT  0.103 74.556 2.119 74.952 ;
     RECT  0.383 75.708 2.119 76.464 ;
     RECT  1.939 96.228 2.155 97.092 ;
     RECT  1.939 97.884 2.155 101.142 ;
     RECT  2.119 2.232 2.16 6.444 ;
     RECT  0.751 11.952 2.16 11.97 ;
     RECT  2.083 22.716 2.16 23.346 ;
     RECT  2.083 25.101 2.16 29.214 ;
     RECT  0.535 30.078 2.16 30.564 ;
     RECT  2.119 31.356 2.16 32.184 ;
     RECT  0.599 33.084 2.16 33.102 ;
     RECT  2.119 35.136 2.16 36.234 ;
     RECT  0.419 39.726 2.16 39.744 ;
     RECT  0.535 40.806 2.16 41.094 ;
     RECT  0.535 42.696 2.16 42.714 ;
     RECT  0.535 43.776 2.16 43.794 ;
     RECT  0.535 46.656 2.16 47.412 ;
     RECT  2.119 49.446 2.16 51.354 ;
     RECT  0.499 53.064 2.16 53.622 ;
     RECT  0.535 54.684 2.16 54.702 ;
     RECT  0.535 55.656 2.16 55.674 ;
     RECT  0.203 58.086 2.16 58.374 ;
     RECT  0.535 59.436 2.16 59.832 ;
     RECT  2.119 61.326 2.16 61.344 ;
     RECT  2.119 62.676 2.16 64.854 ;
     RECT  0.175 65.916 2.16 66.654 ;
     RECT  1.147 67.806 2.16 70.56 ;
     RECT  2.119 71.46 2.16 73.26 ;
     RECT  2.119 74.556 2.16 76.464 ;
     RECT  1.831 77.796 2.16 78.804 ;
     RECT  2.155 91.026 2.16 91.044 ;
     RECT  1.867 92.376 2.16 92.394 ;
     RECT  2.155 96.228 2.16 101.142 ;
     RECT  2.515 0.036 2.615 0.054 ;
     RECT  2.16 2.151 2.803 101.259 ;
     RECT  2.803 2.151 2.975 101.448 ;
     RECT  3.199 103.59 3.271 103.608 ;
     RECT  3.271 103.518 4.415 103.608 ;
     RECT  4.415 103.59 5.395 103.608 ;
     RECT  5.395 103.518 5.567 103.608 ;
     RECT  5.567 103.59 6.035 103.608 ;
     RECT  2.975 2.151 6.223 101.259 ;
     RECT  6.223 1.728 6.683 101.259 ;
     RECT  6.907 103.59 7.015 103.608 ;
     RECT  6.619 0.036 7.079 0.054 ;
     RECT  7.015 103.554 7.151 103.608 ;
     RECT  6.683 2.106 7.303 101.259 ;
     RECT  7.303 2.106 7.403 101.529 ;
     RECT  7.403 2.106 7.619 101.259 ;
     RECT  7.151 103.59 8.195 103.608 ;
     RECT  8.311 0.036 8.375 0.054 ;
     RECT  7.915 102.051 8.635 102.069 ;
     RECT  8.635 102.051 8.663 102.15 ;
     RECT  8.663 102.132 8.735 102.15 ;
     RECT  9.859 103.59 10.039 103.608 ;
     RECT  10.039 0.036 10.139 0.054 ;
     RECT  10.039 103.554 10.139 103.608 ;
     RECT  10.139 103.59 10.175 103.608 ;
     RECT  7.619 2.151 10.435 101.259 ;
     RECT  10.435 2.151 10.931 101.448 ;
     RECT  11.047 103.59 11.291 103.608 ;
     RECT  10.931 2.151 12.235 101.259 ;
     RECT  11.659 0.036 12.335 0.054 ;
     RECT  12.019 103.59 12.335 103.608 ;
     RECT  12.235 2.106 12.451 101.259 ;
     RECT  12.451 1.728 13.235 101.259 ;
     RECT  13.423 0.036 13.559 0.054 ;
     RECT  13.171 103.59 13.631 103.608 ;
     RECT  13.235 2.151 14.179 101.259 ;
     RECT  14.179 2.151 14.423 101.448 ;
     RECT  14.539 103.59 15.151 103.608 ;
     RECT  15.151 103.518 15.251 103.608 ;
     RECT  15.251 103.518 15.323 103.536 ;
     RECT  15.547 0.036 15.755 0.054 ;
     RECT  16.015 103.59 16.699 103.608 ;
     RECT  17.095 0.036 17.159 0.054 ;
     RECT  16.699 103.518 17.267 103.608 ;
     RECT  17.267 103.518 17.591 103.536 ;
     RECT  18.283 103.59 18.499 103.608 ;
     RECT  14.423 2.151 18.571 101.259 ;
     RECT  18.571 1.728 18.707 101.259 ;
     RECT  18.499 103.518 18.859 103.608 ;
     RECT  18.859 103.446 19.283 103.608 ;
     RECT  18.463 0.036 19.571 0.054 ;
     RECT  19.283 103.59 19.607 103.608 ;
     RECT  18.707 2.151 21.091 101.259 ;
     RECT  21.091 1.728 21.227 101.259 ;
     RECT  21.199 103.446 21.299 103.608 ;
     RECT  21.299 103.446 21.623 103.464 ;
     RECT  23.359 0.036 23.495 0.054 ;
     RECT  24.115 0.108 24.259 0.126 ;
     RECT  24.259 0.036 24.359 0.126 ;
     RECT  21.227 2.151 24.943 101.259 ;
     RECT  24.943 2.106 25.115 101.259 ;
     RECT  22.567 103.59 25.259 103.608 ;
     RECT  26.311 103.401 26.419 103.419 ;
     RECT  26.419 103.401 26.519 103.608 ;
     RECT  26.519 103.482 26.555 103.5 ;
     RECT  25.115 2.151 26.671 101.259 ;
     RECT  26.671 2.151 26.807 101.448 ;
     RECT  26.023 0.036 27.275 0.054 ;
     RECT  26.807 2.151 27.859 101.259 ;
     RECT  27.859 2.151 28.031 101.448 ;
     RECT  28.687 103.59 29.083 103.608 ;
     RECT  28.031 2.151 29.119 101.259 ;
     RECT  29.083 103.518 29.255 103.608 ;
     RECT  29.227 0.036 29.371 0.054 ;
     RECT  29.371 0.036 29.399 0.198 ;
     RECT  29.399 0.18 29.579 0.198 ;
     RECT  29.119 2.151 30.263 101.304 ;
     RECT  29.255 103.59 30.415 103.608 ;
     RECT  30.415 103.518 30.595 103.608 ;
     RECT  30.595 103.446 30.731 103.608 ;
     RECT  31.531 0.036 31.811 0.054 ;
     RECT  30.263 2.151 32.071 101.259 ;
     RECT  32.071 1.692 32.207 101.259 ;
     RECT  32.503 102.546 32.603 102.564 ;
     RECT  33.259 0.036 33.467 0.054 ;
     RECT  30.731 103.59 33.575 103.608 ;
     RECT  32.207 2.151 33.907 101.259 ;
     RECT  33.907 2.106 34.051 101.259 ;
     RECT  34.051 1.728 34.123 101.259 ;
     RECT  34.123 1.728 34.187 101.448 ;
     RECT  34.187 2.07 34.367 101.448 ;
     RECT  34.367 2.07 34.835 101.259 ;
     RECT  34.951 0.036 35.051 0.054 ;
     RECT  35.095 103.59 35.627 103.608 ;
     RECT  35.923 0.036 36.023 0.054 ;
     RECT  36.031 0.108 36.203 0.126 ;
     RECT  37.435 102.132 37.535 102.15 ;
     RECT  34.835 2.151 37.723 101.259 ;
     RECT  37.723 1.764 37.859 101.259 ;
     RECT  36.391 103.59 38.147 103.608 ;
     RECT  37.939 0.036 38.399 0.054 ;
     RECT  39.019 103.59 39.415 103.608 ;
     RECT  39.415 103.401 39.623 103.608 ;
     RECT  39.623 103.482 39.839 103.608 ;
     RECT  39.839 103.518 40.415 103.608 ;
     RECT  39.775 0.036 40.559 0.054 ;
     RECT  40.415 103.59 41.971 103.608 ;
     RECT  41.359 0.036 42.431 0.054 ;
     RECT  41.971 103.401 42.871 103.608 ;
     RECT  42.871 103.284 42.943 103.608 ;
     RECT  42.943 103.212 43.079 103.608 ;
     RECT  43.375 0.036 43.511 0.054 ;
     RECT  43.079 103.59 44.123 103.608 ;
     RECT  45.283 103.446 45.463 103.464 ;
     RECT  45.463 103.446 45.491 103.608 ;
     RECT  44.707 0.036 45.563 0.054 ;
     RECT  37.859 2.151 45.751 101.259 ;
     RECT  45.751 2.151 45.931 101.484 ;
     RECT  45.931 2.151 46.031 101.574 ;
     RECT  45.491 103.59 46.643 103.608 ;
     RECT  47.119 102.096 47.255 102.114 ;
     RECT  47.443 103.59 47.867 103.608 ;
     RECT  48.451 103.518 48.811 103.536 ;
     RECT  47.731 0.036 48.911 0.054 ;
     RECT  48.811 103.518 48.983 103.608 ;
     RECT  48.983 103.518 49.019 103.536 ;
     RECT  46.031 2.151 49.963 101.259 ;
     RECT  49.963 2.151 50.243 101.448 ;
     RECT  50.243 2.151 50.49 101.259 ;
     RECT  50.49 76.788 50.531 77.076 ;
     RECT  50.49 90.936 50.531 91.044 ;
     RECT  50.49 91.836 50.531 101.106 ;
     RECT  50.531 97.416 50.567 101.106 ;
     RECT  50.49 79.056 50.603 79.074 ;
     RECT  50.531 90.936 50.639 90.954 ;
     RECT  50.531 91.836 50.675 96.318 ;
     RECT  50.179 103.59 50.675 103.608 ;
     RECT  50.49 81.648 50.711 81.666 ;
     RECT  50.675 91.836 50.783 95.976 ;
     RECT  50.567 97.416 50.783 99.054 ;
     RECT  50.531 77.058 50.819 77.076 ;
     RECT  50.783 95.148 50.819 95.976 ;
     RECT  50.567 99.936 50.819 101.106 ;
     RECT  50.819 95.148 50.855 95.634 ;
     RECT  50.783 91.836 50.891 93.924 ;
     RECT  50.783 97.416 50.891 98.244 ;
     RECT  50.49 75.168 50.927 75.186 ;
     RECT  50.891 91.944 50.927 93.924 ;
     RECT  50.927 91.944 50.963 93.006 ;
     RECT  50.819 101.088 50.963 101.106 ;
     RECT  50.927 93.834 50.999 93.924 ;
     RECT  50.855 95.526 51.035 95.634 ;
     RECT  50.963 92.988 51.071 93.006 ;
     RECT  50.819 99.936 51.071 100.134 ;
     RECT  50.963 91.944 51.107 91.962 ;
     RECT  51.071 99.936 51.107 99.954 ;
     RECT  50.999 93.906 51.179 93.924 ;
     RECT  50.891 97.416 51.323 97.704 ;
     RECT  51.323 97.416 51.359 97.632 ;
     RECT  51.035 95.526 51.575 95.544 ;
     RECT  50.783 99.036 51.755 99.054 ;
     RECT  51.359 97.614 52.367 97.632 ;
    LAYER M3 ;
     RECT  0.756 0.012 50.814 0.077 ;
     RECT  46.908 0.077 50.814 0.091 ;
     RECT  46.908 0.091 50.922 0.173 ;
     RECT  0.756 0.077 46.134 0.557 ;
     RECT  45.468 0.557 46.134 2.839 ;
     RECT  0.756 0.557 43.506 5.297 ;
     RECT  1.836 5.297 43.506 5.603 ;
     RECT  0.756 5.297 0.774 11.975 ;
     RECT  1.908 5.603 43.506 15.965 ;
     RECT  41.364 15.965 43.506 15.979 ;
     RECT  44.352 0.557 44.73 15.979 ;
     RECT  45.468 2.839 46.17 15.979 ;
     RECT  41.364 15.979 46.17 16.555 ;
     RECT  47.088 0.173 50.922 16.555 ;
     RECT  41.364 16.555 50.922 17.375 ;
     RECT  44.244 17.375 50.922 17.645 ;
     RECT  45.468 17.645 50.922 18.221 ;
     RECT  1.908 15.965 40.59 18.235 ;
     RECT  41.364 17.375 43.506 18.235 ;
     RECT  1.908 18.235 43.506 18.803 ;
     RECT  41.364 18.803 43.506 19.387 ;
     RECT  44.352 17.645 44.73 19.387 ;
     RECT  41.364 19.387 44.73 19.955 ;
     RECT  45.468 18.221 46.17 22.811 ;
     RECT  0.036 23.161 0.054 25.411 ;
     RECT  0.036 25.411 0.198 25.753 ;
     RECT  1.152 25.681 1.17 25.951 ;
     RECT  1.908 18.803 40.59 25.951 ;
     RECT  0.036 25.753 0.27 25.987 ;
     RECT  0.036 25.987 0.342 26.221 ;
     RECT  0.036 26.221 0.414 26.491 ;
     RECT  1.152 25.951 40.59 26.491 ;
     RECT  0.036 26.491 40.59 26.909 ;
     RECT  0.108 26.909 40.59 27.101 ;
     RECT  0.144 27.101 40.59 27.197 ;
     RECT  0.18 27.197 40.59 28.381 ;
     RECT  0.108 28.381 40.59 28.507 ;
     RECT  41.364 19.955 43.506 28.507 ;
     RECT  0.108 28.507 43.506 28.685 ;
     RECT  0.144 28.685 43.506 28.877 ;
     RECT  0.144 28.877 0.27 29.659 ;
     RECT  0.144 29.659 0.342 29.731 ;
     RECT  0.108 29.731 0.342 30.073 ;
     RECT  1.152 28.877 43.506 30.073 ;
     RECT  0.108 30.073 43.506 30.077 ;
     RECT  0.144 30.077 43.506 30.269 ;
     RECT  0.144 30.269 0.558 30.701 ;
     RECT  45.468 22.811 46.134 30.811 ;
     RECT  0.144 30.701 0.522 30.941 ;
     RECT  0.324 30.941 0.522 31.459 ;
     RECT  1.548 30.269 43.506 31.459 ;
     RECT  0.324 31.459 43.506 31.757 ;
     RECT  0.324 31.757 1.206 31.771 ;
     RECT  2.16 31.757 43.506 31.801 ;
     RECT  0.144 31.771 1.206 31.901 ;
     RECT  2.16 31.801 43.578 31.915 ;
     RECT  44.352 19.955 44.73 31.915 ;
     RECT  0.504 31.901 1.206 32.297 ;
     RECT  2.16 31.915 44.73 32.431 ;
     RECT  45.468 30.811 46.17 32.431 ;
     RECT  0.504 32.297 1.17 32.477 ;
     RECT  0.504 32.477 0.666 32.669 ;
     RECT  0.54 32.669 0.666 32.957 ;
     RECT  0.54 32.957 0.558 33.451 ;
     RECT  0.144 33.451 0.558 33.629 ;
     RECT  2.16 32.431 46.17 33.643 ;
     RECT  47.088 18.221 50.922 33.643 ;
     RECT  0.324 33.629 0.558 33.677 ;
     RECT  0.324 33.677 0.342 34.735 ;
     RECT  0.108 34.735 0.342 34.877 ;
     RECT  2.16 33.643 50.922 35.035 ;
     RECT  2.124 35.035 50.922 35.159 ;
     RECT  0.144 34.877 0.342 35.261 ;
     RECT  0.144 35.261 0.162 35.645 ;
     RECT  2.16 35.159 50.922 36.139 ;
     RECT  2.124 36.139 50.922 36.239 ;
     RECT  0.108 35.851 0.126 36.379 ;
     RECT  0.108 36.379 0.198 36.523 ;
     RECT  0.108 36.523 0.342 36.524 ;
     RECT  0.18 36.524 0.342 36.625 ;
     RECT  0.18 36.625 0.378 36.653 ;
     RECT  0.216 36.653 0.378 36.845 ;
     RECT  0.216 36.845 0.342 37.42 ;
     RECT  0.108 37.42 0.342 37.421 ;
     RECT  0.108 37.421 0.198 38.045 ;
     RECT  0.144 38.045 0.198 38.299 ;
     RECT  0.144 38.299 0.342 39.052 ;
     RECT  0.108 39.052 0.342 39.067 ;
     RECT  0.108 39.067 0.414 39.119 ;
     RECT  0.108 39.119 0.342 39.149 ;
     RECT  0.108 39.149 0.198 39.293 ;
     RECT  0.108 39.293 0.126 40.171 ;
     RECT  0.108 40.171 0.162 40.396 ;
     RECT  0.108 40.396 0.198 40.801 ;
     RECT  0.108 40.801 0.27 41.021 ;
     RECT  0.216 41.021 0.27 41.071 ;
     RECT  0.216 41.071 0.558 41.755 ;
     RECT  0.18 41.755 0.558 41.803 ;
     RECT  0.108 41.803 0.558 41.948 ;
     RECT  0.144 41.948 0.558 42.557 ;
     RECT  2.16 36.239 50.922 42.811 ;
     RECT  0.54 42.557 0.558 42.859 ;
     RECT  2.124 42.811 50.922 42.989 ;
     RECT  0.54 42.859 1.278 43.037 ;
     RECT  0.54 43.037 1.17 43.771 ;
     RECT  0.324 43.771 1.17 43.915 ;
     RECT  0.216 43.915 1.17 43.951 ;
     RECT  0.144 43.951 1.17 44.189 ;
     RECT  1.152 44.189 1.17 44.285 ;
     RECT  0.144 44.189 0.198 44.524 ;
     RECT  0.108 44.524 0.198 44.765 ;
     RECT  0.108 44.765 0.162 44.813 ;
     RECT  0.144 44.813 0.162 45.883 ;
     RECT  0.144 45.883 0.342 46.013 ;
     RECT  1.152 46.219 1.17 46.363 ;
     RECT  1.152 46.363 1.278 46.589 ;
     RECT  0.144 46.013 0.162 46.636 ;
     RECT  0.108 46.636 0.162 46.939 ;
     RECT  0.108 46.939 0.234 47.389 ;
     RECT  0.108 47.389 0.558 47.534 ;
     RECT  0.144 47.534 0.558 48.139 ;
     RECT  0.144 48.139 1.278 48.269 ;
     RECT  0.144 48.269 1.17 48.365 ;
     RECT  1.152 48.365 1.17 48.749 ;
     RECT  0.144 48.365 0.342 48.763 ;
     RECT  0.108 48.763 0.342 48.989 ;
     RECT  0.108 48.989 0.27 49.037 ;
     RECT  0.108 49.037 0.234 49.775 ;
     RECT  0.144 49.775 0.234 50.093 ;
     RECT  2.16 42.989 50.922 50.251 ;
     RECT  2.124 50.251 50.922 50.351 ;
     RECT  0.18 50.093 0.234 50.443 ;
     RECT  0.18 50.443 0.342 50.827 ;
     RECT  0.108 50.827 0.342 50.864 ;
     RECT  0.18 50.864 0.342 50.935 ;
     RECT  2.16 50.351 50.922 51.307 ;
     RECT  2.124 51.307 50.922 51.359 ;
     RECT  0.18 50.935 0.558 51.869 ;
     RECT  0.324 51.869 0.558 52.061 ;
     RECT  0.324 52.061 0.342 52.253 ;
     RECT  0.144 52.747 0.198 52.972 ;
     RECT  0.108 52.972 0.198 53.059 ;
     RECT  0.108 53.059 0.558 53.564 ;
     RECT  0.144 53.564 0.558 54.029 ;
     RECT  0.504 54.029 0.558 54.749 ;
     RECT  0.54 54.749 0.558 55.531 ;
     RECT  0.18 55.531 0.558 55.579 ;
     RECT  0.108 55.579 0.558 55.916 ;
     RECT  0.144 55.916 0.558 56.333 ;
     RECT  0.144 56.333 0.162 57.005 ;
     RECT  0.324 57.211 0.342 57.341 ;
     RECT  0.108 57.787 0.198 57.911 ;
     RECT  0.108 57.911 0.162 58.891 ;
     RECT  0.108 58.891 0.342 59.809 ;
     RECT  0.108 59.809 0.558 59.933 ;
     RECT  0.144 59.933 0.558 60.029 ;
     RECT  0.144 60.029 0.342 60.365 ;
     RECT  0.18 60.365 0.342 60.605 ;
     RECT  2.16 51.359 50.922 61.051 ;
     RECT  0.18 60.605 0.198 61.243 ;
     RECT  0.144 61.243 0.198 61.393 ;
     RECT  0.108 61.393 0.198 61.613 ;
     RECT  0.144 61.613 0.198 61.723 ;
     RECT  0.144 61.723 0.234 62.347 ;
     RECT  0.144 62.347 0.342 62.443 ;
     RECT  0.108 62.443 0.342 62.573 ;
     RECT  0.108 62.573 0.126 62.909 ;
     RECT  0.144 63.499 0.162 63.595 ;
     RECT  0.144 63.595 0.234 63.751 ;
     RECT  0.108 63.751 0.234 63.931 ;
     RECT  0.108 63.931 0.342 64.205 ;
     RECT  2.124 61.051 50.922 64.391 ;
     RECT  0.108 64.205 0.162 64.877 ;
     RECT  0.144 64.877 0.162 65.165 ;
     RECT  0.324 65.323 0.342 65.911 ;
     RECT  0.18 65.911 0.342 66.631 ;
     RECT  0.108 66.631 0.342 66.749 ;
     RECT  0.144 66.749 0.342 67.085 ;
     RECT  0.144 67.085 0.234 67.757 ;
     RECT  2.16 64.391 50.922 68.011 ;
     RECT  2.124 68.011 50.922 68.099 ;
     RECT  0.108 67.801 0.126 68.683 ;
     RECT  0.108 68.683 0.162 69.053 ;
     RECT  1.152 68.347 1.17 69.223 ;
     RECT  0.54 69.223 1.17 69.773 ;
     RECT  0.108 69.871 0.342 70.157 ;
     RECT  1.152 69.773 1.17 70.565 ;
     RECT  0.144 70.157 0.342 70.589 ;
     RECT  0.324 70.589 0.342 70.829 ;
     RECT  2.16 68.099 50.922 71.323 ;
     RECT  0.144 71.761 0.162 71.803 ;
     RECT  0.144 71.803 0.342 72.265 ;
     RECT  2.124 71.323 50.922 72.283 ;
     RECT  0.144 72.265 0.558 72.931 ;
     RECT  0.108 72.931 0.558 73.037 ;
     RECT  0.468 73.037 0.558 73.133 ;
     RECT  0.468 73.133 0.522 73.229 ;
     RECT  2.088 72.283 50.922 73.265 ;
     RECT  2.124 73.265 50.922 73.517 ;
     RECT  0.468 73.229 0.486 73.613 ;
     RECT  0.144 73.819 0.162 74.491 ;
     RECT  0.144 74.491 0.342 74.551 ;
     RECT  0.108 74.551 0.342 74.621 ;
     RECT  2.16 73.517 50.922 75.163 ;
     RECT  2.124 75.163 50.922 75.191 ;
     RECT  0.108 74.621 0.126 75.703 ;
     RECT  0.108 75.703 0.162 76.363 ;
     RECT  0.108 76.363 0.342 76.477 ;
     RECT  0.108 76.477 0.378 76.589 ;
     RECT  2.124 75.191 50.814 76.651 ;
     RECT  0.108 76.589 0.198 76.733 ;
     RECT  1.728 76.651 50.814 77.081 ;
     RECT  0.108 76.733 0.126 77.213 ;
     RECT  1.728 77.081 50.706 77.819 ;
     RECT  1.8 77.819 50.706 78.431 ;
     RECT  1.836 78.431 50.706 78.809 ;
     RECT  2.16 78.809 50.706 81.671 ;
     RECT  2.16 81.671 50.094 84.173 ;
     RECT  2.16 84.173 49.95 89.941 ;
     RECT  2.16 89.941 50.418 90.931 ;
     RECT  2.16 90.931 50.634 91.049 ;
     RECT  2.196 91.049 50.634 91.319 ;
     RECT  2.232 91.319 50.634 91.831 ;
     RECT  2.232 91.831 50.886 91.939 ;
     RECT  2.232 91.939 51.102 92.371 ;
     RECT  1.872 92.371 51.102 93.901 ;
     RECT  1.872 93.901 51.174 95.521 ;
     RECT  1.872 95.521 51.57 96.223 ;
     RECT  1.728 96.223 51.57 97.879 ;
     RECT  1.44 97.879 51.57 99.031 ;
     RECT  52.344 97.609 52.362 99.031 ;
     RECT  0.288 98.887 0.306 99.535 ;
     RECT  0.288 99.535 0.702 99.967 ;
     RECT  1.44 99.031 52.362 99.967 ;
     RECT  0.288 99.967 52.362 103.644 ;
    LAYER M4 ;
     RECT  0.025 26.88 0.06 26.904 ;
     RECT  0.06 26.88 0.137 77.4 ;
     RECT  0.853 1.776 1.025 1.8 ;
     RECT  1.205 5.136 1.289 5.16 ;
     RECT  1.525 99.12 1.717 99.144 ;
     RECT  1.429 4.56 1.781 4.584 ;
     RECT  1.717 99.12 2.101 99.192 ;
     RECT  1.753 103.536 2.185 103.56 ;
     RECT  0.137 26.976 2.221 77.4 ;
     RECT  2.221 26.832 2.252 77.4 ;
     RECT  2.101 99.072 2.285 99.192 ;
     RECT  1.781 3.984 2.293 4.584 ;
     RECT  1.909 94.752 2.293 94.776 ;
     RECT  2.285 99.072 2.293 100.008 ;
     RECT  2.185 103.536 2.293 103.608 ;
     RECT  1.025 1.728 2.408 1.8 ;
     RECT  1.601 2.88 2.408 2.904 ;
     RECT  2.293 3.984 2.408 5.208 ;
     RECT  2.252 26.304 2.408 77.4 ;
     RECT  2.293 94.752 2.408 95.4 ;
     RECT  2.285 97.584 2.408 97.608 ;
     RECT  2.293 98.88 2.408 100.008 ;
     RECT  0.469 101.328 2.408 101.352 ;
     RECT  2.293 0.096 2.435 0.12 ;
     RECT  2.293 102.576 2.441 103.608 ;
     RECT  2.408 1.728 2.704 101.352 ;
     RECT  2.704 100.848 2.725 101.352 ;
     RECT  2.704 26.256 2.729 74.376 ;
     RECT  2.704 75.696 2.765 76.824 ;
     RECT  2.729 26.256 2.801 74.136 ;
     RECT  2.629 0.144 2.819 0.168 ;
     RECT  2.704 1.728 2.819 6.264 ;
     RECT  2.704 92.352 2.819 96.408 ;
     RECT  2.819 1.728 2.867 3.432 ;
     RECT  2.819 4.416 2.867 6.264 ;
     RECT  2.801 26.256 2.873 71.64 ;
     RECT  2.765 75.696 2.873 76.584 ;
     RECT  2.801 72.816 2.945 74.136 ;
     RECT  2.945 72.816 2.981 73.32 ;
     RECT  2.873 76.464 2.981 76.584 ;
     RECT  2.873 26.256 3.089 67.656 ;
     RECT  2.873 68.784 3.125 71.64 ;
     RECT  3.125 68.784 3.197 70.824 ;
     RECT  2.867 4.512 3.205 6.264 ;
     RECT  2.819 92.352 3.251 93 ;
     RECT  2.819 94.08 3.299 96.408 ;
     RECT  2.704 25.056 3.305 25.224 ;
     RECT  3.089 26.256 3.305 67.416 ;
     RECT  3.305 66.192 3.341 67.416 ;
     RECT  2.981 76.56 3.449 76.584 ;
     RECT  3.341 66.192 3.485 67.368 ;
     RECT  3.251 92.352 3.697 92.952 ;
     RECT  3.205 5.088 3.731 6.264 ;
     RECT  2.704 77.856 3.731 78.648 ;
     RECT  3.731 77.856 3.737 78.6 ;
     RECT  3.299 95.088 3.74 96.408 ;
     RECT  2.704 97.872 3.74 99.864 ;
     RECT  3.731 5.088 3.779 5.688 ;
     RECT  3.299 94.08 3.827 94.104 ;
     RECT  2.441 102.576 3.845 103.56 ;
     RECT  3.845 102.576 3.875 103.512 ;
     RECT  3.485 66.192 3.917 66.936 ;
     RECT  3.875 102.576 3.923 102.648 ;
     RECT  3.697 91.728 3.949 92.952 ;
     RECT  2.867 2.832 4.019 3.432 ;
     RECT  3.197 68.784 4.061 70.584 ;
     RECT  2.725 100.848 4.069 101.448 ;
     RECT  3.923 102.576 4.069 102.6 ;
     RECT  4.061 69.312 4.097 70.584 ;
     RECT  3.305 25.104 4.115 25.224 ;
     RECT  3.74 95.088 4.193 99.864 ;
     RECT  4.069 100.848 4.193 102.6 ;
     RECT  3.779 5.136 4.259 5.688 ;
     RECT  3.737 78.096 4.277 78.6 ;
     RECT  4.193 95.088 4.277 102.6 ;
     RECT  4.097 70.56 4.313 70.584 ;
     RECT  4.277 100.32 4.393 102.6 ;
     RECT  4.393 100.896 4.457 102.6 ;
     RECT  4.457 100.896 4.499 101.496 ;
     RECT  4.019 3.408 4.525 3.432 ;
     RECT  4.277 95.088 4.525 99.288 ;
     RECT  3.305 26.256 4.529 64.968 ;
     RECT  4.525 94.704 4.588 99.288 ;
     RECT  4.525 3.408 4.609 3.672 ;
     RECT  4.588 96.288 4.637 99.288 ;
     RECT  3.949 91.44 4.673 92.952 ;
     RECT  4.673 91.44 4.681 92.376 ;
     RECT  4.529 26.256 4.781 64.92 ;
     RECT  4.785 93.504 4.813 93.576 ;
     RECT  4.609 3.408 4.835 3.432 ;
     RECT  4.681 91.44 4.835 92.328 ;
     RECT  4.259 5.136 4.883 5.16 ;
     RECT  4.813 93.504 4.897 93.672 ;
     RECT  4.115 25.2 4.961 25.224 ;
     RECT  2.981 72.816 4.993 72.84 ;
     RECT  4.097 69.312 5.101 69.336 ;
     RECT  3.917 66.864 5.132 66.936 ;
     RECT  2.867 1.728 5.137 1.752 ;
     RECT  4.588 94.704 5.141 95.16 ;
     RECT  4.993 70.8 5.171 70.824 ;
     RECT  4.993 71.808 5.177 72.84 ;
     RECT  4.835 91.44 5.177 91.464 ;
     RECT  5.137 1.728 5.363 1.848 ;
     RECT  4.637 96.336 5.393 99.288 ;
     RECT  5.132 66.528 5.461 66.936 ;
     RECT  4.489 76.848 5.461 76.872 ;
     RECT  4.277 78.096 5.461 78.504 ;
     RECT  5.173 68.064 5.501 68.088 ;
     RECT  5.389 25.104 5.573 25.128 ;
     RECT  4.499 100.896 5.633 101.016 ;
     RECT  5.141 95.04 5.641 95.16 ;
     RECT  5.393 96.336 5.641 96.936 ;
     RECT  5.393 98.256 5.641 99.288 ;
     RECT  5.633 100.896 5.641 101.448 ;
     RECT  4.457 102.576 5.681 102.6 ;
     RECT  5.101 69.312 5.701 69.48 ;
     RECT  5.641 98.256 5.717 101.448 ;
     RECT  5.461 76.848 5.753 78.504 ;
     RECT  5.701 69.312 5.788 70.44 ;
     RECT  4.897 93.504 5.789 93.576 ;
     RECT  5.713 74.592 6.044 74.616 ;
     RECT  5.753 76.848 6.085 78.12 ;
     RECT  5.821 2.88 6.101 2.904 ;
     RECT  6.044 74.592 6.131 75.192 ;
     RECT  6.101 2.88 6.185 3.432 ;
     RECT  6.037 103.536 6.221 103.56 ;
     RECT  5.788 69.312 6.289 70.008 ;
     RECT  6.289 69.216 6.325 70.008 ;
     RECT  5.177 71.808 6.433 72.744 ;
     RECT  4.781 26.64 6.437 64.92 ;
     RECT  6.085 76.368 6.437 78.12 ;
     RECT  5.717 98.256 6.517 101.16 ;
     RECT  6.325 68.256 6.541 70.008 ;
     RECT  6.476 103.584 6.563 103.608 ;
     RECT  5.363 1.728 6.577 1.752 ;
     RECT  6.185 2.88 6.611 2.904 ;
     RECT  6.565 25.104 6.707 25.128 ;
     RECT  6.517 98.016 6.709 101.16 ;
     RECT  5.641 95.04 6.716 96.936 ;
     RECT  6.577 1.104 6.755 1.752 ;
     RECT  5.461 66.144 6.793 66.936 ;
     RECT  6.541 67.968 6.793 70.008 ;
     RECT  6.437 77.184 6.793 78.12 ;
     RECT  6.433 71.808 6.829 72.84 ;
     RECT  6.437 27.408 6.833 64.92 ;
     RECT  6.755 1.728 6.937 1.752 ;
     RECT  6.131 74.592 7.009 75.144 ;
     RECT  7.009 74.16 7.045 75.144 ;
     RECT  6.829 71.424 7.189 72.84 ;
     RECT  6.709 97.968 7.189 101.16 ;
     RECT  6.793 66.144 7.261 70.008 ;
     RECT  5.789 93.504 7.292 93.528 ;
     RECT  6.716 94.656 7.292 96.936 ;
     RECT  6.997 102.576 7.301 102.6 ;
     RECT  7.292 93.504 7.333 96.936 ;
     RECT  7.189 97.968 7.333 101.448 ;
     RECT  7.333 93.504 7.337 101.448 ;
     RECT  7.189 71.424 7.369 72.936 ;
     RECT  7.045 74.064 7.585 75.144 ;
     RECT  7.369 71.424 7.621 72.984 ;
     RECT  7.585 74.064 7.621 75.816 ;
     RECT  7.477 3.984 7.669 4.008 ;
     RECT  7.621 71.424 7.669 75.816 ;
     RECT  6.793 77.184 7.669 78.168 ;
     RECT  7.573 102.624 7.733 103.56 ;
     RECT  6.937 1.728 7.808 2.28 ;
     RECT  7.669 3.984 7.808 4.584 ;
     RECT  6.833 27.408 7.808 55.464 ;
     RECT  6.833 56.448 7.808 64.92 ;
     RECT  7.261 66.144 7.808 70.152 ;
     RECT  7.669 71.424 7.808 78.168 ;
     RECT  7.337 93.504 7.808 101.4 ;
     RECT  7.808 1.728 7.859 101.4 ;
     RECT  7.859 1.728 8.104 101.262 ;
     RECT  8.104 46.272 8.381 66.792 ;
     RECT  8.104 93.6 8.453 97.032 ;
     RECT  8.104 98.208 8.453 101.262 ;
     RECT  8.104 69.504 8.633 70.536 ;
     RECT  8.104 1.728 8.675 2.28 ;
     RECT  8.104 71.808 8.813 75.144 ;
     RECT  8.813 71.808 8.819 72.984 ;
     RECT  8.453 100.176 8.881 101.262 ;
     RECT  8.819 71.808 8.963 72.936 ;
     RECT  8.881 100.176 9.059 101.448 ;
     RECT  8.104 27.408 9.065 33.336 ;
     RECT  7.733 103.488 9.065 103.56 ;
     RECT  8.453 98.208 9.073 98.616 ;
     RECT  8.104 34.464 9.097 37.176 ;
     RECT  8.104 38.256 9.097 45.288 ;
     RECT  8.381 46.272 9.097 62.616 ;
     RECT  9.097 38.256 9.101 62.616 ;
     RECT  8.381 63.744 9.116 66.792 ;
     RECT  9.059 100.176 9.137 100.92 ;
     RECT  8.453 93.6 9.148 96.888 ;
     RECT  9.116 63.744 9.203 66.888 ;
     RECT  9.157 102.048 9.277 102.072 ;
     RECT  9.101 38.256 9.317 60.6 ;
     RECT  9.148 93.6 9.389 95.4 ;
     RECT  9.277 102.048 9.389 103.464 ;
     RECT  8.104 67.872 9.421 68.424 ;
     RECT  9.389 93.6 9.421 95.16 ;
     RECT  8.963 72.48 9.425 72.936 ;
     RECT  9.425 72.48 9.461 72.84 ;
     RECT  9.421 93.456 9.461 95.16 ;
     RECT  9.445 98.064 9.532 98.088 ;
     RECT  9.137 100.176 9.541 100.872 ;
     RECT  9.317 38.256 9.673 47.688 ;
     RECT  9.101 61.632 9.685 62.616 ;
     RECT  8.104 92.112 9.685 92.136 ;
     RECT  8.813 74.208 9.745 75.144 ;
     RECT  9.203 63.744 9.785 66.792 ;
     RECT  9.317 48.72 9.821 60.6 ;
     RECT  9.785 63.744 9.821 64.2 ;
     RECT  9.673 38.208 9.893 47.688 ;
     RECT  9.461 93.456 9.893 93.48 ;
     RECT  9.685 61.632 9.925 62.712 ;
     RECT  9.821 63.744 9.925 64.152 ;
     RECT  9.461 72.48 9.925 72.792 ;
     RECT  9.148 96.864 9.925 96.888 ;
     RECT  8.633 70.272 9.929 70.536 ;
     RECT  9.685 92.112 9.929 92.376 ;
     RECT  9.389 102.576 10.001 103.464 ;
     RECT  9.541 100.128 10.061 100.872 ;
     RECT  9.421 67.872 10.069 69.096 ;
     RECT  9.745 74.208 10.069 75.192 ;
     RECT  10.001 102.624 10.073 103.464 ;
     RECT  9.821 48.72 10.115 51.624 ;
     RECT  10.061 99.744 10.117 100.872 ;
     RECT  8.675 1.728 10.144 1.752 ;
     RECT  9.925 96.864 10.213 96.936 ;
     RECT  9.065 27.408 10.249 32.472 ;
     RECT  9.097 34.224 10.253 37.176 ;
     RECT  9.461 94.56 10.253 95.16 ;
     RECT  10.117 99.744 10.253 101.256 ;
     RECT  10.253 34.464 10.325 37.176 ;
     RECT  10.069 67.872 10.325 69.576 ;
     RECT  9.929 92.352 10.325 92.376 ;
     RECT  10.253 99.744 10.357 100.92 ;
     RECT  9.893 40.704 10.361 47.688 ;
     RECT  10.325 35.424 10.412 37.176 ;
     RECT  9.893 38.208 10.412 39.72 ;
     RECT  10.412 35.424 10.433 39.72 ;
     RECT  10.361 46.752 10.501 47.688 ;
     RECT  10.115 48.72 10.501 49.272 ;
     RECT  10.115 50.688 10.547 51.624 ;
     RECT  10.357 99.072 10.573 100.92 ;
     RECT  10.069 73.824 10.597 75.192 ;
     RECT  8.104 76.32 10.597 76.584 ;
     RECT  9.961 77.568 10.597 77.592 ;
     RECT  10.213 96.336 10.604 96.936 ;
     RECT  10.433 36.048 10.649 39.72 ;
     RECT  10.325 68.256 10.649 69.576 ;
     RECT  10.604 96.288 10.652 96.936 ;
     RECT  9.821 52.848 10.685 60.6 ;
     RECT  10.685 59.232 10.717 60.6 ;
     RECT  9.925 61.632 10.717 64.152 ;
     RECT  10.144 1.728 10.748 1.8 ;
     RECT  10.597 73.824 10.757 77.592 ;
     RECT  10.717 59.232 10.829 64.152 ;
     RECT  9.925 71.808 10.829 72.792 ;
     RECT  10.757 73.824 10.829 75.144 ;
     RECT  10.573 98.592 10.829 100.92 ;
     RECT  10.361 40.704 10.835 45.576 ;
     RECT  10.829 98.592 10.837 100.344 ;
     RECT  10.649 36.432 10.861 39.72 ;
     RECT  10.835 40.704 10.861 42.792 ;
     RECT  10.253 95.088 10.885 95.16 ;
     RECT  10.652 96.288 10.885 97.032 ;
     RECT  10.837 98.592 10.933 98.664 ;
     RECT  10.861 36.432 10.973 42.792 ;
     RECT  10.835 44.064 10.973 45.576 ;
     RECT  10.829 59.232 10.973 62.712 ;
     RECT  10.649 68.256 10.973 69.48 ;
     RECT  10.429 0.096 11.027 0.12 ;
     RECT  10.973 41.904 11.045 42.792 ;
     RECT  10.685 52.848 11.075 58.248 ;
     RECT  10.973 36.432 11.081 36.84 ;
     RECT  10.757 76.224 11.081 77.592 ;
     RECT  10.073 102.624 11.105 102.648 ;
     RECT  11.081 76.464 11.113 77.592 ;
     RECT  10.973 38.208 11.117 40.728 ;
     RECT  9.785 65.52 11.123 66.792 ;
     RECT  11.123 66.528 11.149 66.792 ;
     RECT  10.829 73.824 11.149 74.712 ;
     RECT  11.149 66.528 11.189 67.272 ;
     RECT  11.105 102.576 11.189 102.648 ;
     RECT  10.973 59.232 11.225 62.616 ;
     RECT  10.973 68.256 11.261 68.424 ;
     RECT  10.885 95.088 11.317 97.032 ;
     RECT  10.933 98.064 11.317 98.664 ;
     RECT  10.249 27.408 11.324 32.904 ;
     RECT  11.285 101.424 11.369 101.448 ;
     RECT  11.189 66.672 11.404 67.272 ;
     RECT  11.123 65.52 11.405 65.544 ;
     RECT  11.113 76.464 11.405 77.88 ;
     RECT  11.317 95.088 11.405 98.664 ;
     RECT  11.324 27.408 11.411 33.528 ;
     RECT  11.075 54.144 11.585 58.248 ;
     RECT  11.411 27.408 11.729 32.472 ;
     RECT  11.585 56.496 11.761 58.248 ;
     RECT  11.225 59.232 11.761 62.184 ;
     RECT  11.749 3.984 11.837 4.008 ;
     RECT  11.261 68.4 11.837 68.424 ;
     RECT  11.509 103.44 11.909 103.56 ;
     RECT  10.547 50.976 11.941 51.624 ;
     RECT  11.075 52.848 11.941 53.064 ;
     RECT  11.585 54.144 11.981 55.416 ;
     RECT  10.748 1.728 11.987 2.28 ;
     RECT  11.405 98.064 12.005 98.664 ;
     RECT  10.837 99.744 12.005 100.344 ;
     RECT  10.501 46.752 12.013 49.272 ;
     RECT  11.941 50.976 12.049 53.064 ;
     RECT  11.981 54.144 12.049 55.368 ;
     RECT  11.149 73.776 12.049 74.712 ;
     RECT  10.829 72 12.053 72.792 ;
     RECT  10.973 69.456 12.085 69.48 ;
     RECT  12.005 98.064 12.113 100.344 ;
     RECT  11.117 38.208 12.157 38.28 ;
     RECT  11.117 39.504 12.157 40.728 ;
     RECT  11.405 76.464 12.161 77.592 ;
     RECT  10.973 44.112 12.193 45.576 ;
     RECT  10.837 64.176 12.193 64.296 ;
     RECT  12.049 50.976 12.197 55.368 ;
     RECT  11.761 56.496 12.229 62.184 ;
     RECT  12.193 63.552 12.229 64.296 ;
     RECT  11.404 66.768 12.229 67.272 ;
     RECT  12.049 73.776 12.229 75.432 ;
     RECT  11.909 103.44 12.236 103.512 ;
     RECT  12.229 56.496 12.265 64.296 ;
     RECT  12.193 65.376 12.265 65.4 ;
     RECT  12.236 102.624 12.323 103.512 ;
     RECT  12.229 73.776 12.332 75.48 ;
     RECT  12.161 76.464 12.332 77.352 ;
     RECT  12.085 69.456 12.373 70.104 ;
     RECT  12.013 46.752 12.409 49.944 ;
     RECT  12.197 50.976 12.409 54.648 ;
     RECT  12.113 98.064 12.469 100.92 ;
     RECT  12.193 44.112 12.481 45.768 ;
     RECT  11.405 95.088 12.517 96.888 ;
     RECT  12.469 98.064 12.517 101.448 ;
     RECT  11.081 36.432 12.581 36.648 ;
     RECT  11.045 41.904 12.625 42.744 ;
     RECT  12.517 95.088 12.661 101.448 ;
     RECT  12.661 95.088 12.709 102.072 ;
     RECT  12.697 0.576 12.781 0.6 ;
     RECT  12.229 66.768 12.805 67.8 ;
     RECT  12.709 94.656 12.805 102.072 ;
     RECT  12.805 66.768 12.949 68.376 ;
     RECT  11.987 1.728 12.985 1.752 ;
     RECT  12.805 94.032 12.989 102.072 ;
     RECT  12.332 73.776 13.201 77.352 ;
     RECT  12.985 1.104 13.208 1.752 ;
     RECT  13.093 3.408 13.208 3.432 ;
     RECT  11.729 28.176 13.208 32.472 ;
     RECT  12.581 36.432 13.208 37.032 ;
     RECT  12.157 38.208 13.208 40.728 ;
     RECT  12.625 41.76 13.208 42.744 ;
     RECT  12.481 43.92 13.208 45.768 ;
     RECT  12.409 46.752 13.208 54.648 ;
     RECT  12.265 56.496 13.208 65.4 ;
     RECT  12.949 66.72 13.208 68.376 ;
     RECT  12.373 69.408 13.208 70.104 ;
     RECT  12.301 71.232 13.208 71.256 ;
     RECT  12.053 72.48 13.208 72.792 ;
     RECT  13.201 73.776 13.208 77.592 ;
     RECT  12.697 78.576 13.208 78.6 ;
     RECT  12.757 83.76 13.208 83.784 ;
     RECT  12.445 92.256 13.208 92.28 ;
     RECT  12.989 94.032 13.208 101.262 ;
     RECT  12.323 103.488 13.265 103.512 ;
     RECT  13.265 103.488 13.349 103.56 ;
     RECT  13.208 1.104 13.379 101.262 ;
     RECT  13.349 103.488 13.477 103.512 ;
     RECT  13.379 1.728 13.504 101.262 ;
     RECT  13.504 38.784 13.601 42.216 ;
     RECT  13.504 97.344 13.667 100.872 ;
     RECT  13.601 39.744 13.673 42.216 ;
     RECT  13.504 43.2 13.673 55.032 ;
     RECT  13.504 76.464 13.709 77.592 ;
     RECT  13.673 44.4 13.745 55.032 ;
     RECT  13.504 56.928 13.745 63.816 ;
     RECT  13.504 68.64 13.745 71.4 ;
     RECT  13.745 44.4 13.763 49.272 ;
     RECT  13.745 50.448 13.763 51.432 ;
     RECT  13.745 52.656 13.763 55.032 ;
     RECT  13.745 56.928 13.763 60.984 ;
     RECT  13.673 39.792 13.781 42.216 ;
     RECT  13.763 46.752 13.789 49.272 ;
     RECT  13.763 58.704 13.789 60.936 ;
     RECT  13.745 62.16 13.817 63.816 ;
     RECT  13.781 40.416 13.853 42.216 ;
     RECT  13.763 44.4 13.889 45.768 ;
     RECT  13.817 62.16 13.889 63.24 ;
     RECT  13.504 92.256 13.889 95.736 ;
     RECT  13.853 40.416 13.925 42.072 ;
     RECT  13.789 47.856 13.925 49.272 ;
     RECT  13.763 53.088 13.925 55.032 ;
     RECT  13.789 46.752 13.955 46.872 ;
     RECT  13.925 47.856 13.955 49.032 ;
     RECT  13.889 92.928 13.969 95.736 ;
     RECT  13.955 47.856 13.997 47.88 ;
     RECT  13.504 72.48 13.997 73.8 ;
     RECT  13.925 40.848 14.033 42.072 ;
     RECT  13.667 97.44 14.033 100.872 ;
     RECT  14.033 97.44 14.177 100.68 ;
     RECT  13.477 102.576 14.245 103.512 ;
     RECT  13.745 68.64 14.285 69.576 ;
     RECT  14.285 68.64 14.321 68.76 ;
     RECT  14.033 40.896 14.357 42.072 ;
     RECT  13.969 94.08 14.357 95.736 ;
     RECT  14.245 102 14.357 103.512 ;
     RECT  14.357 95.616 14.393 95.736 ;
     RECT  13.889 62.544 14.429 63.24 ;
     RECT  13.789 58.848 14.537 60.936 ;
     RECT  14.429 63.024 14.537 63.24 ;
     RECT  13.745 70.704 14.537 71.4 ;
     RECT  14.537 59.04 14.573 60.936 ;
     RECT  13.763 56.928 14.641 57.432 ;
     RECT  14.537 70.704 14.645 71.256 ;
     RECT  13.955 49.008 14.717 49.032 ;
     RECT  13.925 53.28 14.717 55.032 ;
     RECT  14.629 96.864 14.717 96.888 ;
     RECT  14.717 54.048 14.753 55.032 ;
     RECT  14.573 59.28 14.753 60.936 ;
     RECT  14.753 54.048 14.789 54.216 ;
     RECT  14.753 59.28 14.789 60.168 ;
     RECT  13.504 67.248 14.789 67.272 ;
     RECT  14.177 98.064 14.819 100.344 ;
     RECT  14.357 102.576 14.821 103.512 ;
     RECT  14.789 54.192 14.825 54.216 ;
     RECT  14.789 59.28 14.825 59.976 ;
     RECT  14.357 41.76 14.861 42.072 ;
     RECT  13.889 45.744 14.897 45.768 ;
     RECT  14.641 56.832 14.897 57.432 ;
     RECT  13.709 76.992 14.897 77.016 ;
     RECT  14.861 41.904 14.965 42.072 ;
     RECT  13.673 43.2 14.965 43.368 ;
     RECT  14.825 59.28 15.005 59.304 ;
     RECT  13.969 92.928 15.068 92.952 ;
     RECT  14.357 94.08 15.068 94.296 ;
     RECT  14.819 98.64 15.077 100.344 ;
     RECT  14.965 41.904 15.107 43.368 ;
     RECT  14.821 102.576 15.149 103.56 ;
     RECT  15.068 92.928 15.155 94.296 ;
     RECT  15.107 41.904 15.185 42.072 ;
     RECT  15.155 94.08 15.185 94.296 ;
     RECT  15.205 101.424 15.293 101.448 ;
     RECT  14.645 70.704 15.365 70.728 ;
     RECT  15.149 102.576 15.605 103.512 ;
     RECT  14.393 95.616 15.689 95.64 ;
     RECT  15.605 102.528 15.689 103.512 ;
     RECT  15.077 98.64 15.965 99.192 ;
     RECT  15.469 92.88 16.013 92.904 ;
     RECT  15.689 102.576 16.019 103.512 ;
     RECT  15.965 98.016 16.049 99.192 ;
     RECT  16.049 98.064 16.109 99.192 ;
     RECT  16.028 96.912 16.117 96.936 ;
     RECT  15.077 100.32 16.153 100.344 ;
     RECT  16.117 96.816 16.165 96.936 ;
     RECT  15.185 42.048 16.369 42.072 ;
     RECT  16.153 100.32 16.405 100.44 ;
     RECT  16.369 42.048 16.517 42.792 ;
     RECT  16.405 100.32 16.517 100.872 ;
     RECT  15.185 94.272 16.549 94.296 ;
     RECT  16.517 42.048 16.553 42.168 ;
     RECT  16.165 96.72 16.625 96.936 ;
     RECT  16.549 94.272 16.661 94.584 ;
     RECT  16.625 96.912 16.7 96.936 ;
     RECT  16.109 98.064 16.789 99.24 ;
     RECT  16.517 100.32 16.789 100.44 ;
     RECT  16.7 96.912 16.797 96.984 ;
     RECT  16.553 42.144 16.805 42.168 ;
     RECT  16.789 98.064 16.813 100.44 ;
     RECT  16.813 98.064 16.835 100.344 ;
     RECT  13.504 1.728 16.883 2.28 ;
     RECT  16.797 96.912 16.883 96.936 ;
     RECT  16.981 101.424 17.093 101.448 ;
     RECT  16.835 98.4 17.129 100.344 ;
     RECT  13.889 44.4 17.341 44.424 ;
     RECT  17.341 43.92 17.381 44.424 ;
     RECT  17.381 43.92 17.453 43.944 ;
     RECT  16.019 102.576 17.885 102.6 ;
     RECT  17.129 98.4 17.893 99.048 ;
     RECT  17.317 95.712 17.989 95.736 ;
     RECT  16.661 94.272 18.061 94.296 ;
     RECT  17.893 98.016 18.085 99.048 ;
     RECT  17.129 100.272 18.085 100.344 ;
     RECT  18.061 94.272 18.133 94.392 ;
     RECT  18.085 97.632 18.161 99.048 ;
     RECT  18.085 100.272 18.161 100.92 ;
     RECT  17.948 102.048 18.161 102.072 ;
     RECT  17.989 95.712 18.277 96.36 ;
     RECT  18.161 97.632 18.277 99.192 ;
     RECT  18.277 3.36 18.341 3.384 ;
     RECT  18.133 94.272 18.349 94.68 ;
     RECT  18.277 95.712 18.349 99.192 ;
     RECT  18.341 3.36 18.421 3.432 ;
     RECT  18.349 94.272 18.421 99.192 ;
     RECT  18.421 0.144 18.469 0.168 ;
     RECT  18.421 94.08 18.469 99.192 ;
     RECT  18.161 100.272 18.469 102.072 ;
     RECT  16.883 1.728 18.608 1.8 ;
     RECT  18.421 3.36 18.608 4.008 ;
     RECT  18.133 44.976 18.608 45 ;
     RECT  13.955 46.752 18.608 46.776 ;
     RECT  13.763 51.408 18.608 51.432 ;
     RECT  14.897 57.024 18.608 57.432 ;
     RECT  14.537 63.024 18.608 63.048 ;
     RECT  15.061 65.712 18.608 65.736 ;
     RECT  13.997 72.48 18.608 72.792 ;
     RECT  13.504 75.456 18.608 75.48 ;
     RECT  13.504 83.76 18.608 83.784 ;
     RECT  17.917 92.784 18.608 92.808 ;
     RECT  18.469 94.08 18.608 102.072 ;
     RECT  18.608 1.728 18.611 102.072 ;
     RECT  18.611 1.728 18.785 102.024 ;
     RECT  18.469 0.144 18.803 0.264 ;
     RECT  18.785 1.728 18.904 101.448 ;
     RECT  18.917 0.096 19.001 0.12 ;
     RECT  18.904 92.784 19.109 92.952 ;
     RECT  18.904 94.368 19.109 101.448 ;
     RECT  19.109 94.368 19.289 97.512 ;
     RECT  19.289 95.664 19.331 97.512 ;
     RECT  18.904 45.504 19.433 45.528 ;
     RECT  19.249 103.584 19.525 103.608 ;
     RECT  19.109 92.928 19.649 92.952 ;
     RECT  19.525 103.488 19.907 103.608 ;
     RECT  19.109 98.592 19.937 101.448 ;
     RECT  18.904 3.408 19.981 4.008 ;
     RECT  18.904 46.752 20.005 46.776 ;
     RECT  20.101 92.016 20.113 92.04 ;
     RECT  18.904 1.728 20.149 1.752 ;
     RECT  18.904 83.76 20.149 83.784 ;
     RECT  20.113 91.776 20.188 92.04 ;
     RECT  20.188 91.776 20.197 91.8 ;
     RECT  20.005 46.752 20.213 46.968 ;
     RECT  20.213 46.752 20.221 47.4 ;
     RECT  19.331 95.904 20.261 97.512 ;
     RECT  20.261 95.904 20.293 97.464 ;
     RECT  20.221 46.176 20.297 47.4 ;
     RECT  20.293 95.808 20.297 97.464 ;
     RECT  19.937 98.592 20.365 100.872 ;
     RECT  19.981 3.408 20.437 3.432 ;
     RECT  20.149 83.76 20.477 84.024 ;
     RECT  20.297 95.808 20.477 95.832 ;
     RECT  20.297 46.176 20.483 46.776 ;
     RECT  20.365 98.544 20.483 100.872 ;
     RECT  19.907 103.584 20.483 103.608 ;
     RECT  20.437 2.832 20.521 3.432 ;
     RECT  20.521 3.408 20.531 3.432 ;
     RECT  20.483 46.176 20.531 46.2 ;
     RECT  20.149 1.152 20.579 1.752 ;
     RECT  20.483 98.592 20.579 100.872 ;
     RECT  20.579 99.168 20.665 100.872 ;
     RECT  20.665 100.56 20.729 100.872 ;
     RECT  20.477 83.856 20.765 84.024 ;
     RECT  20.729 100.752 20.771 100.872 ;
     RECT  20.771 100.848 20.917 100.872 ;
     RECT  20.533 102 20.917 102.024 ;
     RECT  20.917 100.848 21.089 102.024 ;
     RECT  20.579 1.728 21.161 1.752 ;
     RECT  21.085 88.944 21.233 88.968 ;
     RECT  21.26 102.048 21.347 102.072 ;
     RECT  19.289 94.368 21.481 94.392 ;
     RECT  20.297 96.864 21.548 97.464 ;
     RECT  21.473 3.984 21.557 4.008 ;
     RECT  21.548 96.864 21.635 97.512 ;
     RECT  21.089 100.848 21.665 100.872 ;
     RECT  20.941 93.168 21.701 93.192 ;
     RECT  21.661 0.576 21.745 0.6 ;
     RECT  21.635 96.864 21.989 97.032 ;
     RECT  22.057 3.408 22.141 3.432 ;
     RECT  21.685 103.536 22.169 103.56 ;
     RECT  22.069 101.424 22.241 101.448 ;
     RECT  21.481 94.368 22.268 94.536 ;
     RECT  22.268 94.368 22.309 95.064 ;
     RECT  22.165 96.192 22.313 96.216 ;
     RECT  22.261 1.152 22.349 1.176 ;
     RECT  22.309 93.744 22.355 95.064 ;
     RECT  22.261 98.064 22.493 98.088 ;
     RECT  22.355 93.744 22.601 94.968 ;
     RECT  22.453 102.576 22.633 102.6 ;
     RECT  21.26 2.256 22.805 2.28 ;
     RECT  22.633 102.48 22.885 102.6 ;
     RECT  22.813 88.944 22.961 88.968 ;
     RECT  22.705 103.584 22.997 103.608 ;
     RECT  23.065 100.32 23.084 100.344 ;
     RECT  20.665 99.168 23.093 99.192 ;
     RECT  22.885 102 23.141 102.6 ;
     RECT  23.093 98.592 23.317 99.192 ;
     RECT  23.084 100.224 23.317 100.344 ;
     RECT  22.805 1.728 23.372 2.28 ;
     RECT  23.141 102 23.545 102.024 ;
     RECT  22.601 94.944 23.605 94.968 ;
     RECT  23.077 96.336 23.605 96.36 ;
     RECT  23.317 98.592 23.653 100.344 ;
     RECT  23.605 94.944 23.893 96.36 ;
     RECT  23.821 97.536 23.893 97.56 ;
     RECT  23.372 1.68 24.008 2.28 ;
     RECT  18.904 51.408 24.008 51.432 ;
     RECT  18.904 57.024 24.008 57.432 ;
     RECT  18.904 63.024 24.008 63.048 ;
     RECT  18.904 65.712 24.008 65.736 ;
     RECT  18.904 72.48 24.008 72.792 ;
     RECT  18.904 75.456 24.008 75.48 ;
     RECT  20.765 83.856 24.008 83.88 ;
     RECT  23.209 92.16 24.008 92.184 ;
     RECT  22.601 93.744 24.008 93.768 ;
     RECT  23.893 94.944 24.008 97.56 ;
     RECT  23.653 98.592 24.008 100.728 ;
     RECT  23.653 103.44 24.037 103.464 ;
     RECT  24.008 1.68 24.083 100.992 ;
     RECT  24.083 1.728 24.2 100.992 ;
     RECT  24.037 103.44 24.229 103.512 ;
     RECT  24.2 1.728 24.304 101.262 ;
     RECT  24.229 102.576 24.365 103.512 ;
     RECT  24.304 62.928 24.401 63.048 ;
     RECT  24.365 103.44 24.419 103.512 ;
     RECT  24.304 93.456 24.445 98.664 ;
     RECT  24.445 93.456 24.467 96.6 ;
     RECT  24.445 98.064 24.515 98.664 ;
     RECT  24.304 99.648 24.563 100.92 ;
     RECT  24.467 93.456 24.689 94.968 ;
     RECT  24.515 98.064 24.755 98.616 ;
     RECT  24.304 51.312 24.761 51.432 ;
     RECT  24.467 96.288 24.797 96.6 ;
     RECT  24.304 88.944 24.833 88.968 ;
     RECT  24.563 99.888 24.833 100.92 ;
     RECT  24.764 102.048 24.851 102.072 ;
     RECT  24.419 103.44 24.977 103.464 ;
     RECT  24.761 51.312 25.013 51.336 ;
     RECT  24.304 3.408 25.049 3.432 ;
     RECT  24.689 93.456 25.121 94.584 ;
     RECT  24.833 100.128 25.333 100.92 ;
     RECT  24.304 92.16 25.405 92.184 ;
     RECT  25.361 3.984 25.445 4.008 ;
     RECT  25.405 91.728 25.445 92.184 ;
     RECT  25.121 94.56 25.553 94.584 ;
     RECT  24.797 96.288 25.553 96.312 ;
     RECT  25.333 100.128 25.553 101.496 ;
     RECT  25.553 100.128 25.667 101.448 ;
     RECT  24.755 98.592 25.801 98.616 ;
     RECT  25.667 100.128 25.801 100.344 ;
     RECT  24.304 1.728 25.811 2.28 ;
     RECT  25.801 98.592 25.913 100.344 ;
     RECT  24.304 77.52 25.945 77.544 ;
     RECT  25.445 91.728 25.985 91.752 ;
     RECT  25.945 77.04 26.005 77.64 ;
     RECT  24.401 62.928 26.06 62.952 ;
     RECT  25.811 1.728 26.125 1.752 ;
     RECT  26.005 77.04 26.129 78.36 ;
     RECT  25.121 93.456 26.129 93.48 ;
     RECT  26.06 62.928 26.147 63.096 ;
     RECT  24.304 83.856 26.197 83.88 ;
     RECT  26.197 83.472 26.243 83.88 ;
     RECT  25.957 97.44 26.245 97.464 ;
     RECT  25.913 98.64 26.291 100.344 ;
     RECT  26.101 103.344 26.377 103.368 ;
     RECT  26.245 96.768 26.521 97.464 ;
     RECT  26.147 62.928 26.524 62.952 ;
     RECT  26.125 1.104 26.579 1.752 ;
     RECT  25.667 101.328 26.693 101.448 ;
     RECT  26.521 96.768 26.741 97.512 ;
     RECT  26.693 100.896 26.773 101.448 ;
     RECT  26.377 102.576 26.773 103.368 ;
     RECT  26.243 83.472 26.813 83.592 ;
     RECT  26.773 100.896 26.876 103.368 ;
     RECT  26.579 1.152 27.001 1.752 ;
     RECT  26.741 97.44 27.013 97.512 ;
     RECT  26.291 98.64 27.013 99.768 ;
     RECT  26.876 100.896 27.029 103.512 ;
     RECT  26.129 77.04 27.241 78.072 ;
     RECT  26.125 94.512 27.245 94.536 ;
     RECT  27.013 97.44 27.253 99.768 ;
     RECT  27.001 1.728 27.277 1.752 ;
     RECT  24.304 75.456 27.308 75.48 ;
     RECT  27.241 77.04 27.308 78.456 ;
     RECT  27.253 97.44 27.353 99.864 ;
     RECT  27.308 75.456 27.395 78.456 ;
     RECT  27.029 102.576 27.433 103.512 ;
     RECT  27.277 1.728 27.452 1.848 ;
     RECT  27.395 75.456 27.457 76.248 ;
     RECT  27.433 103.152 27.541 103.512 ;
     RECT  27.353 98.64 27.565 99.864 ;
     RECT  27.029 100.896 27.565 101.496 ;
     RECT  27.313 54.144 27.605 54.168 ;
     RECT  27.457 74.688 27.677 76.248 ;
     RECT  27.541 103.152 27.857 103.56 ;
     RECT  27.925 0.576 28.009 0.6 ;
     RECT  27.565 98.64 28.019 101.496 ;
     RECT  27.353 97.44 28.105 97.464 ;
     RECT  28.105 96.624 28.285 97.464 ;
     RECT  28.285 96.432 28.357 97.464 ;
     RECT  28.019 98.64 28.357 100.92 ;
     RECT  28.165 102.048 28.433 102.072 ;
     RECT  28.357 98.592 28.565 100.92 ;
     RECT  28.501 0.096 28.585 0.12 ;
     RECT  28.357 96.336 28.789 97.464 ;
     RECT  27.857 103.152 28.925 103.512 ;
     RECT  28.925 103.152 29.009 103.56 ;
     RECT  28.565 98.544 29.077 100.92 ;
     RECT  28.789 96.192 29.125 97.464 ;
     RECT  29.077 98.448 29.125 100.92 ;
     RECT  27.677 75.456 29.149 76.248 ;
     RECT  29.125 96.192 29.221 100.92 ;
     RECT  27.457 94.416 29.257 94.44 ;
     RECT  29.009 103.152 29.315 103.512 ;
     RECT  29.315 103.152 29.363 103.416 ;
     RECT  27.452 1.728 29.408 2.28 ;
     RECT  29.077 3.984 29.408 4.008 ;
     RECT  24.304 57.024 29.408 57.432 ;
     RECT  24.304 65.712 29.408 65.736 ;
     RECT  24.304 72.48 29.408 72.792 ;
     RECT  29.149 74.688 29.408 76.248 ;
     RECT  27.395 77.472 29.408 78.456 ;
     RECT  26.813 83.568 29.408 83.592 ;
     RECT  27.853 92.256 29.408 92.28 ;
     RECT  29.257 94.032 29.408 94.44 ;
     RECT  29.221 95.664 29.408 100.92 ;
     RECT  29.363 103.152 29.555 103.32 ;
     RECT  29.408 1.728 29.6 100.992 ;
     RECT  29.6 1.728 29.681 101.262 ;
     RECT  29.681 1.728 29.704 101.448 ;
     RECT  29.704 75.456 29.765 75.96 ;
     RECT  29.704 83.472 29.801 83.592 ;
     RECT  29.653 0.144 29.843 0.168 ;
     RECT  29.704 3.408 29.843 4.008 ;
     RECT  29.704 96.096 29.845 101.448 ;
     RECT  29.843 3.984 29.891 4.008 ;
     RECT  29.845 98.064 29.909 101.448 ;
     RECT  29.909 98.592 30.197 101.448 ;
     RECT  29.555 103.152 30.265 103.176 ;
     RECT  29.704 57.024 30.557 57.432 ;
     RECT  30.265 102.576 30.601 103.176 ;
     RECT  29.704 93.504 30.629 94.968 ;
     RECT  29.704 78.432 30.733 78.456 ;
     RECT  30.601 103.152 30.769 103.176 ;
     RECT  30.733 78.336 30.773 78.456 ;
     RECT  29.845 96.096 30.773 96.936 ;
     RECT  30.629 93.888 30.809 94.968 ;
     RECT  30.773 96.864 30.841 96.936 ;
     RECT  30.517 0.576 30.851 0.6 ;
     RECT  30.809 94.272 30.853 94.968 ;
     RECT  30.841 96.864 31.045 97.032 ;
     RECT  30.769 103.152 31.085 103.416 ;
     RECT  30.557 57.408 31.385 57.432 ;
     RECT  31.045 96.864 31.477 97.176 ;
     RECT  30.197 98.592 31.477 100.92 ;
     RECT  31.085 103.152 31.532 103.56 ;
     RECT  31.477 96.864 31.619 100.92 ;
     RECT  31.532 103.152 31.619 103.608 ;
     RECT  31.619 103.152 31.669 103.56 ;
     RECT  30.853 94.272 31.673 95.592 ;
     RECT  31.619 99.168 31.781 100.92 ;
     RECT  31.781 100.896 31.82 100.92 ;
     RECT  31.781 99.168 31.825 99.768 ;
     RECT  31.82 100.896 31.925 101.016 ;
     RECT  29.704 1.728 31.957 2.28 ;
     RECT  31.619 96.864 32.069 98.088 ;
     RECT  31.673 95.376 32.197 95.592 ;
     RECT  31.957 1.68 32.213 2.28 ;
     RECT  32.069 98.064 32.249 98.088 ;
     RECT  32.197 95.376 32.281 95.784 ;
     RECT  32.069 96.864 32.281 96.936 ;
     RECT  31.673 94.272 32.497 94.296 ;
     RECT  29.801 83.472 32.609 83.496 ;
     RECT  31.993 3.408 32.627 3.432 ;
     RECT  30.773 78.336 32.725 78.36 ;
     RECT  32.281 95.376 32.753 96.936 ;
     RECT  32.725 78.336 32.771 78.648 ;
     RECT  31.825 99.168 32.857 99.192 ;
     RECT  32.497 94.08 32.917 94.296 ;
     RECT  32.753 95.376 32.917 95.4 ;
     RECT  31.669 102.576 32.924 103.56 ;
     RECT  32.771 78.624 32.963 78.648 ;
     RECT  32.876 83.664 32.963 83.688 ;
     RECT  32.785 101.424 32.965 101.448 ;
     RECT  32.213 1.776 33.011 2.28 ;
     RECT  32.924 102.576 33.011 103.608 ;
     RECT  32.965 100.752 33.077 101.448 ;
     RECT  32.713 0.528 33.203 0.552 ;
     RECT  32.753 96.912 33.253 96.936 ;
     RECT  33.011 1.776 33.349 1.8 ;
     RECT  33.077 101.424 33.617 101.448 ;
     RECT  32.917 94.08 33.761 95.4 ;
     RECT  33.011 102.576 33.829 103.512 ;
     RECT  33.253 96.912 33.877 97.464 ;
     RECT  33.877 96.816 33.937 97.464 ;
     RECT  33.349 1.728 33.973 1.8 ;
     RECT  33.829 102.528 34.001 103.512 ;
     RECT  32.857 99.168 34.037 99.768 ;
     RECT  34.001 102.432 34.085 103.512 ;
     RECT  34.037 99.12 34.181 99.768 ;
     RECT  34.085 102.576 34.213 103.512 ;
     RECT  33.761 94.608 34.325 95.4 ;
     RECT  33.937 96.816 34.325 97.512 ;
     RECT  34.325 94.608 34.369 97.512 ;
     RECT  34.297 0.576 34.381 0.6 ;
     RECT  34.181 99.12 34.405 99.912 ;
     RECT  34.369 94.608 34.441 98.088 ;
     RECT  34.405 99.12 34.441 100.872 ;
     RECT  34.213 102.576 34.481 103.56 ;
     RECT  33.973 1.728 34.585 1.848 ;
     RECT  34.441 94.608 34.729 100.872 ;
     RECT  34.585 1.104 34.808 1.848 ;
     RECT  34.009 62.016 34.808 62.04 ;
     RECT  29.704 65.712 34.808 65.736 ;
     RECT  29.704 72.48 34.808 72.792 ;
     RECT  32.725 74.352 34.808 74.376 ;
     RECT  29.765 75.456 34.808 75.48 ;
     RECT  31.561 92.4 34.808 92.424 ;
     RECT  34.729 94.608 34.808 101.4 ;
     RECT  34.808 1.104 34.979 101.4 ;
     RECT  34.979 1.728 35.104 101.4 ;
     RECT  35.104 94.848 35.129 96.36 ;
     RECT  34.481 102.576 35.267 103.32 ;
     RECT  35.104 61.968 35.315 61.992 ;
     RECT  35.104 2.832 35.353 2.856 ;
     RECT  35.104 99.744 35.365 101.4 ;
     RECT  35.104 1.728 35.381 1.8 ;
     RECT  35.267 103.296 35.605 103.32 ;
     RECT  35.129 96.288 35.813 96.36 ;
     RECT  35.605 103.296 35.885 103.56 ;
     RECT  35.365 99.744 35.989 101.448 ;
     RECT  35.104 97.344 36.029 98.616 ;
     RECT  35.813 96.336 36.092 96.36 ;
     RECT  35.129 94.848 36.133 94.872 ;
     RECT  36.029 98.256 36.181 98.616 ;
     RECT  35.989 99.744 36.181 102.024 ;
     RECT  36.181 98.256 36.217 102.024 ;
     RECT  36.217 100.272 36.245 102.024 ;
     RECT  36.277 3.984 36.389 4.008 ;
     RECT  35.885 103.296 36.467 103.512 ;
     RECT  36.457 3.408 36.541 3.432 ;
     RECT  36.467 103.296 36.565 103.32 ;
     RECT  35.381 1.728 36.712 1.752 ;
     RECT  36.745 2.832 36.829 2.856 ;
     RECT  36.745 63.312 36.829 63.336 ;
     RECT  36.092 96.336 37.037 96.936 ;
     RECT  36.245 100.272 37.043 101.448 ;
     RECT  36.712 1.728 37.069 1.8 ;
     RECT  36.133 94.848 37.217 94.968 ;
     RECT  36.217 98.256 37.285 99.192 ;
     RECT  36.565 102.576 37.325 103.32 ;
     RECT  37.043 100.32 37.333 101.448 ;
     RECT  35.104 72.48 37.357 72.792 ;
     RECT  35.104 91.872 37.469 91.896 ;
     RECT  37.333 100.32 37.469 102.072 ;
     RECT  37.069 1.728 37.475 2.28 ;
     RECT  37.037 96.864 37.573 96.936 ;
     RECT  37.285 98.016 37.573 99.192 ;
     RECT  37.141 70.128 37.58 70.152 ;
     RECT  37.58 69.312 37.621 70.152 ;
     RECT  37.621 69.312 37.667 70.296 ;
     RECT  37.475 1.728 37.865 1.752 ;
     RECT  35.104 65.712 37.865 65.736 ;
     RECT  37.325 103.296 37.889 103.32 ;
     RECT  37.813 16.56 38.009 16.584 ;
     RECT  38.005 0.096 38.069 0.12 ;
     RECT  37.573 96.864 38.081 99.192 ;
     RECT  38.053 16.464 38.101 16.536 ;
     RECT  37.357 72.384 38.108 72.792 ;
     RECT  35.104 74.352 38.108 74.376 ;
     RECT  38.041 32.496 38.125 32.52 ;
     RECT  38.081 97.44 38.149 99.192 ;
     RECT  38.069 0.096 38.153 0.552 ;
     RECT  38.149 97.44 38.153 99.288 ;
     RECT  36.925 93.744 38.189 93.768 ;
     RECT  38.108 72.384 38.195 74.376 ;
     RECT  38.153 0.096 38.26 0.12 ;
     RECT  37.889 103.296 38.396 103.56 ;
     RECT  38.149 31.92 38.401 32.04 ;
     RECT  38.101 15.984 38.437 16.536 ;
     RECT  38.153 99.168 38.473 99.288 ;
     RECT  37.469 100.32 38.473 101.256 ;
     RECT  38.396 103.296 38.483 103.608 ;
     RECT  37.217 94.848 38.485 94.872 ;
     RECT  38.473 99.168 38.485 101.256 ;
     RECT  38.485 99.696 38.533 101.256 ;
     RECT  37.667 70.272 38.545 70.296 ;
     RECT  38.473 92.304 38.557 92.328 ;
     RECT  37.681 66.72 38.581 66.744 ;
     RECT  38.401 31.344 38.677 32.04 ;
     RECT  38.581 65.952 38.689 66.744 ;
     RECT  38.485 94.848 38.689 95.112 ;
     RECT  38.533 99.696 38.693 101.496 ;
     RECT  38.677 30.816 38.86 32.04 ;
     RECT  38.545 70.272 38.869 70.68 ;
     RECT  38.689 65.952 38.905 67.272 ;
     RECT  38.483 103.296 38.917 103.512 ;
     RECT  38.905 65.856 38.972 67.272 ;
     RECT  38.195 72.384 38.977 72.792 ;
     RECT  38.869 70.272 39.013 70.776 ;
     RECT  38.26 0.048 39.017 0.12 ;
     RECT  38.86 30.816 39.049 31.992 ;
     RECT  38.972 65.52 39.059 67.272 ;
     RECT  39.059 65.712 39.1 67.272 ;
     RECT  39.049 30.24 39.155 31.992 ;
     RECT  39.013 70.128 39.157 70.776 ;
     RECT  38.977 72.336 39.157 72.792 ;
     RECT  38.905 68.448 39.301 68.472 ;
     RECT  39.157 70.128 39.301 72.792 ;
     RECT  38.153 97.44 39.301 98.04 ;
     RECT  39.017 0.048 39.347 0.072 ;
     RECT  38.689 96.192 39.349 96.216 ;
     RECT  39.301 97.44 39.349 98.712 ;
     RECT  39.301 68.448 39.409 72.792 ;
     RECT  38.195 74.352 39.409 74.376 ;
     RECT  39.1 67.248 39.517 67.272 ;
     RECT  39.409 68.448 39.517 74.376 ;
     RECT  39.349 96.192 39.589 98.712 ;
     RECT  38.693 99.696 39.589 101.448 ;
     RECT  38.917 102.576 39.589 103.512 ;
     RECT  39.589 102.576 39.805 103.56 ;
     RECT  39.805 102.576 39.917 103.608 ;
     RECT  39.589 96.192 39.98 101.448 ;
     RECT  39.917 102.576 39.98 103.512 ;
     RECT  39.769 58.656 40.069 58.68 ;
     RECT  38.437 15.408 40.208 16.536 ;
     RECT  39.155 30.24 40.208 31.944 ;
     RECT  40.057 34.752 40.208 34.776 ;
     RECT  40.069 58.656 40.208 59.208 ;
     RECT  39.1 65.712 40.208 66.264 ;
     RECT  39.517 67.248 40.208 74.376 ;
     RECT  35.104 75.456 40.208 75.48 ;
     RECT  39.985 90.624 40.208 90.648 ;
     RECT  38.689 94.608 40.208 95.112 ;
     RECT  39.98 96.192 40.208 103.512 ;
     RECT  40.208 2.148 40.312 103.512 ;
     RECT  40.312 2.418 40.504 103.512 ;
     RECT  40.069 0.096 40.549 0.12 ;
     RECT  40.549 0.096 40.642 0.168 ;
     RECT  40.504 98.928 40.745 103.512 ;
     RECT  40.504 75.456 40.781 77.304 ;
     RECT  40.745 98.928 40.835 102.072 ;
     RECT  40.745 103.296 40.885 103.512 ;
     RECT  40.504 65.52 40.889 72.984 ;
     RECT  40.504 28.512 40.933 29.208 ;
     RECT  40.504 96.288 41.005 97.848 ;
     RECT  40.504 74.064 41.027 74.376 ;
     RECT  40.504 94.944 41.027 94.968 ;
     RECT  40.885 103.296 41.027 103.56 ;
     RECT  40.642 0.096 41.029 0.216 ;
     RECT  41.005 96.288 41.033 97.368 ;
     RECT  41.029 0.048 41.113 0.216 ;
     RECT  40.504 30.24 41.141 30.84 ;
     RECT  40.889 65.52 41.164 67.896 ;
     RECT  41.164 65.712 41.177 67.896 ;
     RECT  40.504 14.256 41.213 15.96 ;
     RECT  41.113 0.096 41.221 0.216 ;
     RECT  41.213 14.784 41.249 15.96 ;
     RECT  41.221 0.096 41.363 0.264 ;
     RECT  40.504 36.48 41.365 37.128 ;
     RECT  41.249 14.784 41.411 14.808 ;
     RECT  40.933 28.512 41.411 28.536 ;
     RECT  41.177 65.76 41.429 67.896 ;
     RECT  41.365 37.056 41.459 37.128 ;
     RECT  40.889 68.928 41.459 72.984 ;
     RECT  40.504 18.24 41.465 18.84 ;
     RECT  41.141 30.816 41.507 30.84 ;
     RECT  41.249 15.936 41.509 15.96 ;
     RECT  40.835 98.928 41.545 101.016 ;
     RECT  41.459 37.056 41.555 37.08 ;
     RECT  41.497 19.344 41.581 19.368 ;
     RECT  40.504 92.304 41.645 92.328 ;
     RECT  41.033 96.288 41.785 96.888 ;
     RECT  41.545 99.744 41.845 101.016 ;
     RECT  40.835 102.048 41.845 102.072 ;
     RECT  41.701 17.664 41.861 18.216 ;
     RECT  41.845 99.744 41.933 102.072 ;
     RECT  41.857 35.904 41.941 35.928 ;
     RECT  41.861 18.192 41.969 18.216 ;
     RECT  41.933 102.048 41.996 102.072 ;
     RECT  41.027 103.296 41.996 103.32 ;
     RECT  40.781 76.8 42.037 77.304 ;
     RECT  41.785 95.856 42.037 96.888 ;
     RECT  41.459 68.928 42.101 69.384 ;
     RECT  42.037 95.856 42.124 96.936 ;
     RECT  42.124 95.856 42.185 96.888 ;
     RECT  41.459 70.608 42.325 72.984 ;
     RECT  42.325 70.608 42.365 73.032 ;
     RECT  41.429 65.76 42.433 67.272 ;
     RECT  42.101 68.352 42.433 69.384 ;
     RECT  42.365 72.432 42.433 73.032 ;
     RECT  42.325 14.832 42.437 14.856 ;
     RECT  42.037 76.56 42.437 77.304 ;
     RECT  41.996 102.048 42.508 103.32 ;
     RECT  41.027 74.352 42.541 74.376 ;
     RECT  40.781 75.456 42.541 75.48 ;
     RECT  40.504 93.456 42.541 93.48 ;
     RECT  42.361 78.576 42.545 78.6 ;
     RECT  42.541 74.352 42.577 75.48 ;
     RECT  42.437 76.56 42.577 77.16 ;
     RECT  41.363 0.096 42.58 0.12 ;
     RECT  42.58 0.096 42.581 0.168 ;
     RECT  41.921 29.664 42.659 29.688 ;
     RECT  42.517 15.312 42.677 15.432 ;
     RECT  42.661 16.56 42.677 16.584 ;
     RECT  42.677 15.312 42.697 16.584 ;
     RECT  42.581 0.144 42.709 0.168 ;
     RECT  42.433 65.76 42.709 69.384 ;
     RECT  42.365 70.608 42.709 71.448 ;
     RECT  42.508 102.576 42.725 103.32 ;
     RECT  42.505 30.816 42.755 30.84 ;
     RECT  42.709 65.76 42.755 71.448 ;
     RECT  42.697 15.936 42.761 16.584 ;
     RECT  42.755 68.352 42.761 71.448 ;
     RECT  41.605 98.496 42.793 98.712 ;
     RECT  42.709 0.144 42.797 0.264 ;
     RECT  42.541 92.976 42.797 93.48 ;
     RECT  42.761 68.976 42.833 71.448 ;
     RECT  42.793 98.4 42.901 98.712 ;
     RECT  41.933 99.744 42.901 100.872 ;
     RECT  42.725 103.296 42.905 103.32 ;
     RECT  42.901 98.4 43.013 100.872 ;
     RECT  42.761 15.984 43.045 16.584 ;
     RECT  42.901 38.784 43.045 38.808 ;
     RECT  42.433 72.432 43.081 73.368 ;
     RECT  42.577 74.352 43.081 77.16 ;
     RECT  43.009 33.648 43.093 33.672 ;
     RECT  42.185 96.864 43.148 96.888 ;
     RECT  43.013 98.592 43.153 100.872 ;
     RECT  42.797 93.456 43.189 93.48 ;
     RECT  42.833 70.08 43.229 71.448 ;
     RECT  42.833 68.976 43.265 69 ;
     RECT  43.153 98.592 43.309 100.968 ;
     RECT  43.309 100.224 43.331 100.968 ;
     RECT  42.755 65.76 43.373 66.888 ;
     RECT  43.373 65.76 43.445 66.744 ;
     RECT  43.445 66.048 43.481 66.744 ;
     RECT  43.229 71.424 43.517 71.448 ;
     RECT  43.481 66.72 43.589 66.744 ;
     RECT  43.441 31.344 43.619 31.368 ;
     RECT  43.081 72.432 43.621 77.16 ;
     RECT  43.331 100.32 43.621 100.968 ;
     RECT  43.621 72.432 43.625 77.544 ;
     RECT  43.045 38.208 43.693 38.808 ;
     RECT  42.973 103.344 43.693 103.368 ;
     RECT  42.797 0.144 43.724 0.168 ;
     RECT  43.621 19.392 43.732 19.416 ;
     RECT  43.732 19.392 43.733 19.464 ;
     RECT  43.621 100.32 43.741 101.448 ;
     RECT  43.693 38.208 43.805 38.904 ;
     RECT  43.724 0.048 43.811 0.168 ;
     RECT  43.733 19.44 43.813 19.464 ;
     RECT  43.813 19.44 43.841 19.944 ;
     RECT  43.805 38.784 43.859 38.904 ;
     RECT  43.148 96.288 43.873 96.888 ;
     RECT  43.859 38.784 43.907 38.808 ;
     RECT  43.741 100.896 43.909 101.448 ;
     RECT  43.841 19.68 43.913 19.944 ;
     RECT  43.693 103.344 43.955 103.608 ;
     RECT  43.873 96.288 43.957 96.984 ;
     RECT  43.957 32.496 43.981 32.52 ;
     RECT  43.913 19.68 43.985 19.704 ;
     RECT  43.981 32.496 44.017 33.096 ;
     RECT  43.625 74.304 44.053 77.544 ;
     RECT  43.811 0.144 44.117 0.168 ;
     RECT  43.045 15.984 44.233 17.112 ;
     RECT  44.017 31.92 44.243 33.096 ;
     RECT  43.625 72.432 44.269 73.32 ;
     RECT  43.189 93.456 44.269 94.008 ;
     RECT  44.245 94.992 44.269 95.016 ;
     RECT  43.981 34.224 44.291 34.248 ;
     RECT  44.233 15.984 44.317 17.64 ;
     RECT  44.269 93.456 44.353 95.016 ;
     RECT  44.353 93.456 44.381 94.056 ;
     RECT  43.955 103.344 44.381 103.56 ;
     RECT  43.957 96.288 44.437 97.464 ;
     RECT  43.909 100.896 44.453 102.024 ;
     RECT  44.437 96.288 44.461 97.512 ;
     RECT  43.309 98.592 44.483 99.192 ;
     RECT  44.453 102 44.485 102.024 ;
     RECT  44.053 74.304 44.521 78.504 ;
     RECT  44.243 32.496 44.557 33.096 ;
     RECT  44.485 102 44.581 102.072 ;
     RECT  44.381 103.344 44.581 103.368 ;
     RECT  44.381 93.456 44.845 93.48 ;
     RECT  44.483 98.592 44.965 98.664 ;
     RECT  44.269 72.336 45.025 73.32 ;
     RECT  44.521 74.304 45.025 78.648 ;
     RECT  44.461 96.336 45.061 97.512 ;
     RECT  44.965 98.496 45.061 98.664 ;
     RECT  44.581 102 45.137 103.368 ;
     RECT  45.137 102 45.203 102.072 ;
     RECT  44.953 95.136 45.253 95.16 ;
     RECT  45.253 99.744 45.277 99.768 ;
     RECT  44.737 100.848 45.277 100.872 ;
     RECT  44.557 32.496 45.313 33.672 ;
     RECT  44.117 0.144 45.353 0.552 ;
     RECT  44.317 15.984 45.385 17.16 ;
     RECT  45.313 32.496 45.385 33.72 ;
     RECT  45.203 102 45.425 102.024 ;
     RECT  45.277 99.744 45.493 100.872 ;
     RECT  45.493 99.648 45.589 100.872 ;
     RECT  45.385 15.984 45.608 17.64 ;
     RECT  45.385 32.496 45.608 34.248 ;
     RECT  43.229 70.08 45.608 70.104 ;
     RECT  45.025 72.336 45.608 78.648 ;
     RECT  44.845 93.072 45.608 93.48 ;
     RECT  45.253 95.136 45.608 95.304 ;
     RECT  45.061 96.336 45.608 98.664 ;
     RECT  45.589 99.648 45.608 101.4 ;
     RECT  45.608 2.148 45.785 101.4 ;
     RECT  45.353 0.144 45.829 0.456 ;
     RECT  45.785 2.148 45.904 101.262 ;
     RECT  45.137 103.248 45.973 103.368 ;
     RECT  45.904 72.432 46.001 72.984 ;
     RECT  45.925 2.016 46.012 2.04 ;
     RECT  45.904 70.08 46.019 70.104 ;
     RECT  45.829 0.096 46.067 0.456 ;
     RECT  45.904 16.56 46.073 18.792 ;
     RECT  45.904 74.112 46.073 78.648 ;
     RECT  45.904 92.736 46.073 101.262 ;
     RECT  46.067 0.096 46.115 0.216 ;
     RECT  46.001 72.528 46.145 72.984 ;
     RECT  46.073 16.56 46.163 18.36 ;
     RECT  46.073 74.112 46.181 75.528 ;
     RECT  46.073 92.736 46.217 98.664 ;
     RECT  46.115 0.096 46.268 0.168 ;
     RECT  46.145 72.816 46.289 72.984 ;
     RECT  46.217 94.8 46.396 98.664 ;
     RECT  46.073 76.608 46.433 78.648 ;
     RECT  46.396 94.8 46.433 96.936 ;
     RECT  46.396 97.968 46.433 98.664 ;
     RECT  46.433 94.8 46.451 95.208 ;
     RECT  46.433 97.968 46.499 98.184 ;
     RECT  45.973 103.248 46.508 103.56 ;
     RECT  45.904 33.648 46.649 35.928 ;
     RECT  46.289 72.96 46.649 72.984 ;
     RECT  46.649 34.8 46.693 35.928 ;
     RECT  46.217 92.736 46.793 93.336 ;
     RECT  46.073 99.744 46.825 101.262 ;
     RECT  46.825 99.744 46.933 101.448 ;
     RECT  46.508 102.624 46.933 103.56 ;
     RECT  46.163 16.56 47.017 18.216 ;
     RECT  46.693 34.8 47.081 34.872 ;
     RECT  46.933 99.744 47.113 103.56 ;
     RECT  47.081 34.848 47.123 34.872 ;
     RECT  46.693 35.904 47.149 35.928 ;
     RECT  46.451 94.8 47.153 94.824 ;
     RECT  46.649 33.648 47.171 33.672 ;
     RECT  47.017 17.088 47.173 18.216 ;
     RECT  46.433 76.608 47.173 78.216 ;
     RECT  47.173 17.088 47.189 18.264 ;
     RECT  47.113 99.168 47.189 103.56 ;
     RECT  47.132 89.472 47.219 89.496 ;
     RECT  47.189 99.168 47.219 103.512 ;
     RECT  47.189 17.664 47.269 18.264 ;
     RECT  47.185 70.704 47.297 70.728 ;
     RECT  47.173 76.512 47.297 78.216 ;
     RECT  47.269 17.664 47.315 18.792 ;
     RECT  47.315 18.144 47.333 18.792 ;
     RECT  47.219 102 47.405 103.512 ;
     RECT  47.149 35.904 47.413 35.976 ;
     RECT  46.793 92.88 47.429 93.336 ;
     RECT  46.181 74.112 47.441 75.096 ;
     RECT  46.433 96.288 47.509 96.936 ;
     RECT  46.499 97.968 47.509 98.04 ;
     RECT  47.333 18.24 47.537 18.792 ;
     RECT  47.365 37.056 47.545 37.08 ;
     RECT  46.268 0.048 47.555 0.168 ;
     RECT  47.509 96.288 47.557 98.04 ;
     RECT  47.219 99.168 47.603 100.92 ;
     RECT  47.555 0.048 47.699 0.072 ;
     RECT  47.557 95.808 47.701 98.04 ;
     RECT  47.537 18.24 47.737 18.84 ;
     RECT  47.405 102.048 47.773 103.512 ;
     RECT  47.221 91.872 47.789 91.896 ;
     RECT  47.737 18.72 47.797 18.84 ;
     RECT  47.701 95.184 47.797 98.04 ;
     RECT  47.603 99.168 47.797 99.816 ;
     RECT  47.441 75.072 47.837 75.096 ;
     RECT  47.545 36.48 47.869 37.128 ;
     RECT  47.297 76.56 47.869 78.216 ;
     RECT  47.429 92.88 47.869 93.48 ;
     RECT  47.797 18.72 47.881 19.368 ;
     RECT  47.869 76.56 47.981 78.504 ;
     RECT  47.789 91.728 47.981 91.896 ;
     RECT  47.981 77.712 48.089 78.504 ;
     RECT  47.981 76.56 48.161 76.68 ;
     RECT  48.089 77.808 48.161 78.504 ;
     RECT  47.797 95.184 48.171 99.816 ;
     RECT  48.161 76.56 48.233 76.632 ;
     RECT  48.161 77.904 48.233 78.504 ;
     RECT  48.233 76.56 48.305 76.584 ;
     RECT  47.725 90.48 48.373 90.504 ;
     RECT  47.981 91.728 48.373 91.752 ;
     RECT  47.869 36.48 48.377 37.176 ;
     RECT  47.869 92.88 48.428 94.008 ;
     RECT  48.171 95.136 48.428 99.816 ;
     RECT  48.428 92.88 48.449 99.816 ;
     RECT  48.233 78.24 48.481 78.504 ;
     RECT  48.445 79.488 48.481 79.512 ;
     RECT  47.773 103.344 48.517 103.512 ;
     RECT  48.377 37.056 48.625 37.176 ;
     RECT  48.373 90.48 48.629 91.752 ;
     RECT  48.517 103.344 48.659 103.56 ;
     RECT  48.449 92.88 48.661 94.92 ;
     RECT  48.449 95.904 48.701 99.816 ;
     RECT  48.661 92.832 48.796 94.92 ;
     RECT  48.625 37.056 48.805 37.752 ;
     RECT  48.629 90.72 48.917 91.752 ;
     RECT  48.013 82.608 48.989 82.632 ;
     RECT  48.796 92.832 48.989 92.952 ;
     RECT  48.62 0.144 49.004 0.168 ;
     RECT  47.773 102.048 49.021 102.072 ;
     RECT  48.659 103.344 49.021 103.464 ;
     RECT  48.481 78.24 49.025 79.512 ;
     RECT  49.021 102.048 49.025 103.464 ;
     RECT  48.805 37.056 49.057 37.992 ;
     RECT  49.004 0.048 49.093 0.168 ;
     RECT  49.025 102.048 49.093 103.368 ;
     RECT  49.025 78.24 49.097 78.504 ;
     RECT  48.701 96.24 49.165 99.816 ;
     RECT  47.603 100.896 49.165 100.92 ;
     RECT  49.093 102 49.177 103.368 ;
     RECT  49.093 0.048 49.187 0.552 ;
     RECT  47.881 18.816 49.201 19.368 ;
     RECT  49.097 78.48 49.241 78.504 ;
     RECT  49.165 96.24 49.273 100.92 ;
     RECT  48.796 93.984 49.313 94.92 ;
     RECT  49.201 18.816 49.381 19.416 ;
     RECT  49.057 37.056 49.417 38.232 ;
     RECT  48.917 90.72 49.421 91.368 ;
     RECT  48.989 92.928 49.421 92.952 ;
     RECT  49.313 94.08 49.421 94.92 ;
     RECT  49.381 18.816 49.465 19.944 ;
     RECT  49.273 96.24 49.475 101.448 ;
     RECT  48.805 86.64 49.477 86.664 ;
     RECT  49.475 96.24 49.493 96.6 ;
     RECT  49.417 37.056 49.501 38.328 ;
     RECT  49.477 86.64 49.523 86.904 ;
     RECT  49.465 18.816 49.529 19.896 ;
     RECT  49.421 90.72 49.529 91.128 ;
     RECT  49.523 86.88 49.565 86.904 ;
     RECT  49.529 90.72 49.565 90.744 ;
     RECT  49.501 37.056 49.571 38.232 ;
     RECT  49.493 96.24 49.601 96.456 ;
     RECT  49.475 97.632 49.601 101.448 ;
     RECT  49.601 96.24 49.612 96.36 ;
     RECT  49.421 94.512 49.633 94.92 ;
     RECT  49.529 19.296 49.637 19.896 ;
     RECT  49.187 0.048 49.667 0.12 ;
     RECT  49.637 19.392 49.681 19.896 ;
     RECT  49.177 102.624 49.715 103.368 ;
     RECT  49.681 19.872 49.745 19.896 ;
     RECT  49.571 38.208 49.789 38.232 ;
     RECT  49.633 94.512 49.813 95.208 ;
     RECT  49.601 98.064 49.859 101.448 ;
     RECT  49.561 80.064 49.961 80.088 ;
     RECT  49.813 94.512 49.961 95.976 ;
     RECT  49.859 98.064 49.997 100.344 ;
     RECT  49.997 98.592 50.051 100.344 ;
     RECT  49.961 94.56 50.099 95.256 ;
     RECT  50.051 98.832 50.099 100.344 ;
     RECT  49.571 37.056 50.147 37.08 ;
     RECT  50.099 94.56 50.177 95.112 ;
     RECT  49.859 101.424 50.177 101.448 ;
     RECT  50.177 95.088 50.213 95.112 ;
     RECT  50.099 99.744 50.483 100.344 ;
     RECT  49.667 0.096 50.636 0.12 ;
     RECT  50.636 0.096 50.723 0.552 ;
     RECT  50.483 99.744 50.723 99.768 ;
     RECT  50.245 101.472 50.821 102.024 ;
     RECT  49.715 103.344 50.849 103.368 ;
     RECT  50.723 0.096 50.933 0.12 ;
     RECT  50.849 103.344 50.933 103.56 ;
     RECT  50.821 101.472 51.107 102.072 ;
     RECT  50.749 96.912 51.299 96.936 ;
     RECT  51.289 99.168 51.491 99.192 ;
     RECT  51.107 101.472 51.683 101.544 ;
     RECT  51.683 101.52 51.875 101.544 ;
     RECT  50.933 103.344 52.085 103.368 ;
    LAYER M5 ;
     RECT  0.864 0.016 50.904 0.131 ;
     RECT  0.864 0.131 50.712 0.563 ;
     RECT  0.864 0.563 50.136 1.763 ;
     RECT  0.864 1.763 2.856 1.811 ;
     RECT  10.224 1.763 11.976 1.811 ;
     RECT  13.104 1.763 19.944 1.811 ;
     RECT  27.312 1.763 50.136 1.811 ;
     RECT  5.328 1.763 8.664 1.859 ;
     RECT  27.312 1.811 33 1.859 ;
     RECT  34.128 1.811 35.112 1.859 ;
     RECT  6.144 1.859 8.664 2.291 ;
     RECT  10.8 1.811 11.976 2.291 ;
     RECT  13.104 1.811 16.872 2.291 ;
     RECT  21.312 1.763 25.8 2.291 ;
     RECT  27.504 1.859 33 2.291 ;
     RECT  36.288 1.811 50.136 2.291 ;
     RECT  1.248 1.811 2.856 2.821 ;
     RECT  18.384 1.811 19.944 2.821 ;
     RECT  34.8 1.859 35.112 2.821 ;
     RECT  18.384 2.821 20.472 3.349 ;
     RECT  1.248 2.821 4.008 3.397 ;
     RECT  18.288 3.349 20.472 3.397 ;
     RECT  6.144 2.291 8.112 3.443 ;
     RECT  13.104 2.291 13.512 3.443 ;
     RECT  21.504 2.291 22.104 3.443 ;
     RECT  24 2.291 25.416 3.443 ;
     RECT  32.592 2.291 32.616 3.443 ;
     RECT  6.576 3.443 8.112 4.019 ;
     RECT  11.76 2.291 11.784 4.019 ;
     RECT  18.288 3.397 20.52 4.019 ;
     RECT  21.504 3.443 21.528 4.019 ;
     RECT  25.392 3.443 25.416 4.019 ;
     RECT  29.088 2.291 29.88 4.019 ;
     RECT  36.288 2.291 36.792 4.019 ;
     RECT  1.248 3.397 4.824 4.595 ;
     RECT  7.68 4.019 8.112 4.595 ;
     RECT  2.304 4.595 4.824 5.125 ;
     RECT  1.248 4.595 1.272 5.171 ;
     RECT  2.304 5.125 4.872 5.219 ;
     RECT  37.824 2.291 50.136 16.595 ;
     RECT  6.576 4.019 6.6 25.093 ;
     RECT  6.576 25.093 6.696 25.139 ;
     RECT  2.4 5.219 4.872 26.293 ;
     RECT  2.304 26.293 4.872 28.021 ;
     RECT  2.304 28.021 5.16 28.309 ;
     RECT  6.672 25.139 6.696 29.029 ;
     RECT  6.576 29.029 6.696 29.077 ;
     RECT  10.272 29.941 10.296 30.661 ;
     RECT  6.576 29.077 6.744 30.709 ;
     RECT  7.8 4.595 8.112 30.709 ;
     RECT  10.272 30.661 10.872 30.709 ;
     RECT  9.312 30.709 10.872 30.755 ;
     RECT  2.304 28.309 5.208 30.803 ;
     RECT  38.064 16.595 50.136 30.851 ;
     RECT  6.576 30.709 8.112 30.853 ;
     RECT  9.312 30.755 9.336 30.853 ;
     RECT  10.464 30.755 10.872 30.853 ;
     RECT  13.2 3.443 13.512 30.853 ;
     RECT  6.576 30.853 9.336 30.995 ;
     RECT  6.576 30.995 8.112 31.093 ;
     RECT  6.336 31.093 8.112 31.285 ;
     RECT  9.312 30.995 9.336 31.427 ;
     RECT  0.144 31.429 0.168 31.715 ;
     RECT  12.528 30.853 13.512 31.907 ;
     RECT  38.064 30.851 41.928 31.955 ;
     RECT  38.064 31.955 39.144 32.003 ;
     RECT  2.304 30.803 4.872 32.005 ;
     RECT  38.064 32.003 38.808 32.051 ;
     RECT  2.208 32.005 4.872 32.053 ;
     RECT  2.208 32.053 5.112 32.387 ;
     RECT  38.064 32.051 38.088 32.531 ;
     RECT  2.4 32.387 5.112 32.771 ;
     RECT  6.288 31.285 8.112 33.203 ;
     RECT  6.288 33.203 6.792 33.539 ;
     RECT  10.464 30.853 11.4 33.539 ;
     RECT  42.912 30.851 50.136 33.683 ;
     RECT  42.912 33.683 44.28 34.259 ;
     RECT  45.456 33.683 50.136 34.259 ;
     RECT  2.4 32.771 4.872 35.029 ;
     RECT  2.4 35.029 5.16 35.171 ;
     RECT  0.144 33.877 0.168 35.267 ;
     RECT  6.768 33.539 6.792 35.317 ;
     RECT  7.8 33.203 8.112 35.317 ;
     RECT  40.2 31.955 41.928 35.939 ;
     RECT  45.6 34.259 50.136 35.939 ;
     RECT  47.28 35.939 50.136 35.987 ;
     RECT  0.192 36.565 0.216 36.851 ;
     RECT  13.2 31.907 13.512 36.997 ;
     RECT  40.2 35.939 41.544 37.091 ;
     RECT  47.712 35.987 50.136 37.091 ;
     RECT  40.2 37.091 41.448 37.139 ;
     RECT  47.856 37.091 49.752 37.139 ;
     RECT  48.144 37.139 49.752 37.187 ;
     RECT  10.464 33.539 10.488 37.427 ;
     RECT  48.816 37.187 49.752 38.003 ;
     RECT  49.392 38.003 49.752 38.243 ;
     RECT  49.44 38.243 49.464 38.339 ;
     RECT  12.624 36.997 13.512 38.387 ;
     RECT  0.144 37.141 0.168 38.435 ;
     RECT  10.512 37.573 10.536 38.629 ;
     RECT  42.912 34.259 43.896 38.819 ;
     RECT  43.824 38.819 43.848 38.915 ;
     RECT  10.512 38.629 10.632 39.395 ;
     RECT  13.104 38.387 13.512 40.067 ;
     RECT  13.2 40.067 13.512 40.741 ;
     RECT  0.144 41.221 0.168 41.411 ;
     RECT  13.2 40.741 13.752 41.795 ;
     RECT  10.512 39.395 10.536 42.133 ;
     RECT  10.512 42.133 10.776 42.179 ;
     RECT  10.752 42.179 10.776 42.803 ;
     RECT  0.144 43.621 0.168 43.907 ;
     RECT  10.8 43.237 10.824 44.053 ;
     RECT  10.032 44.053 10.824 44.195 ;
     RECT  13.2 41.795 13.512 44.341 ;
     RECT  6.768 35.317 8.112 44.965 ;
     RECT  18.288 4.019 19.128 45.011 ;
     RECT  12.528 44.341 13.512 45.059 ;
     RECT  6.288 44.965 8.112 45.251 ;
     RECT  18.6 45.011 19.128 45.539 ;
     RECT  0.144 45.973 0.168 46.163 ;
     RECT  20.256 4.019 20.52 46.211 ;
     RECT  13.2 45.059 13.512 46.645 ;
     RECT  13.2 46.645 13.752 46.741 ;
     RECT  20.256 46.211 20.472 46.787 ;
     RECT  6.288 45.251 6.792 46.837 ;
     RECT  7.8 45.251 8.112 46.837 ;
     RECT  13.2 46.741 13.944 46.883 ;
     RECT  6.288 46.837 8.112 46.979 ;
     RECT  10.8 44.195 10.824 47.173 ;
     RECT  10.512 47.173 10.824 47.219 ;
     RECT  13.2 46.883 13.752 47.365 ;
     RECT  20.256 46.787 20.28 47.411 ;
     RECT  0.144 47.317 0.168 47.699 ;
     RECT  13.104 47.365 13.752 48.227 ;
     RECT  13.2 48.227 13.752 48.229 ;
     RECT  0.144 48.709 0.168 48.995 ;
     RECT  1.248 48.709 1.272 49.043 ;
     RECT  10.512 47.219 10.536 50.101 ;
     RECT  10.08 50.101 10.536 51.781 ;
     RECT  9.552 51.781 10.536 52.115 ;
     RECT  0.144 50.389 0.168 52.259 ;
     RECT  10.512 52.115 10.536 53.075 ;
     RECT  6.288 46.979 6.792 53.267 ;
     RECT  6.768 53.267 6.792 54.133 ;
     RECT  7.8 46.979 8.112 54.133 ;
     RECT  6.768 54.133 8.112 54.661 ;
     RECT  11.04 53.557 11.064 54.707 ;
     RECT  2.4 35.171 4.872 55.093 ;
     RECT  2.304 55.093 4.872 55.283 ;
     RECT  6.288 54.661 8.112 55.331 ;
     RECT  6.768 55.331 8.112 56.483 ;
     RECT  13.2 48.229 13.944 56.485 ;
     RECT  29.4 4.019 29.712 57.013 ;
     RECT  0.144 57.061 0.168 57.347 ;
     RECT  12.336 56.485 13.944 57.493 ;
     RECT  12.192 57.493 13.944 57.539 ;
     RECT  12.192 57.539 12.216 58.261 ;
     RECT  40.2 37.139 40.512 58.645 ;
     RECT  0.144 59.029 0.168 59.219 ;
     RECT  12 58.261 12.216 59.267 ;
     RECT  6.768 56.483 6.792 59.605 ;
     RECT  7.8 56.483 8.112 59.605 ;
     RECT  12.192 59.267 12.216 59.797 ;
     RECT  13.2 57.539 13.944 59.797 ;
     RECT  12.192 59.797 13.944 59.843 ;
     RECT  6.768 59.605 8.808 60.179 ;
     RECT  7.8 60.179 8.808 60.515 ;
     RECT  6.768 60.179 6.792 60.661 ;
     RECT  0.144 60.565 0.168 60.755 ;
     RECT  11.376 60.949 11.4 61.091 ;
     RECT  12.384 59.843 13.944 61.525 ;
     RECT  34.8 2.821 35.304 62.003 ;
     RECT  2.4 55.283 4.872 62.581 ;
     RECT  6.624 60.661 6.792 62.627 ;
     RECT  2.4 62.581 5.208 62.629 ;
     RECT  6.72 62.627 6.792 62.677 ;
     RECT  7.8 60.515 8.112 62.677 ;
     RECT  9.696 62.101 9.72 62.723 ;
     RECT  10.8 62.533 10.824 62.723 ;
     RECT  12.24 61.525 13.944 63.059 ;
     RECT  26.448 62.917 26.472 63.061 ;
     RECT  2.304 62.629 5.208 63.155 ;
     RECT  36.768 4.019 36.792 63.347 ;
     RECT  6.72 62.677 8.112 63.779 ;
     RECT  12.24 63.059 13.512 64.307 ;
     RECT  7.8 63.779 8.112 64.405 ;
     RECT  13.104 64.307 13.512 65.075 ;
     RECT  7.8 64.405 8.664 65.171 ;
     RECT  39.792 58.645 40.512 65.509 ;
     RECT  15.072 42.421 15.096 65.747 ;
     RECT  39.024 65.509 41.112 65.795 ;
     RECT  6.768 63.779 6.792 66.133 ;
     RECT  10.848 64.261 10.872 66.181 ;
     RECT  10.848 66.181 11.112 66.227 ;
     RECT  6.384 66.133 6.792 66.373 ;
     RECT  0.144 65.173 0.168 66.563 ;
     RECT  11.088 66.227 11.112 66.661 ;
     RECT  39.024 65.795 40.512 66.755 ;
     RECT  9.168 66.709 9.192 66.899 ;
     RECT  11.088 66.661 11.352 67.283 ;
     RECT  42.24 66.949 42.264 67.283 ;
     RECT  2.4 63.155 5.208 68.099 ;
     RECT  13.2 65.075 13.512 68.341 ;
     RECT  42.72 67.477 42.744 68.341 ;
     RECT  11.088 67.283 11.112 68.435 ;
     RECT  39.312 66.755 40.512 68.675 ;
     RECT  39.792 68.675 40.512 68.917 ;
     RECT  42.144 68.341 42.744 68.917 ;
     RECT  0.144 68.773 0.168 68.963 ;
     RECT  6.192 66.373 6.792 69.493 ;
     RECT  7.8 65.171 8.112 69.493 ;
     RECT  6.192 69.493 8.112 69.587 ;
     RECT  13.104 68.341 13.512 69.587 ;
     RECT  45.6 35.939 45.912 70.069 ;
     RECT  39.792 68.917 42.744 70.115 ;
     RECT  39.792 70.115 42.168 70.117 ;
     RECT  6.768 69.587 8.112 70.163 ;
     RECT  37.632 69.301 37.656 70.307 ;
     RECT  2.4 68.099 4.872 70.405 ;
     RECT  39.648 70.117 42.168 70.739 ;
     RECT  0.144 70.309 0.168 70.979 ;
     RECT  7.8 70.163 8.112 71.797 ;
     RECT  2.4 70.405 5.736 71.843 ;
     RECT  42.144 70.739 42.168 71.893 ;
     RECT  39.648 70.739 40.512 71.939 ;
     RECT  41.616 71.893 42.168 71.939 ;
     RECT  39.792 71.939 40.512 72.037 ;
     RECT  41.616 71.939 41.64 72.037 ;
     RECT  6.768 70.163 6.792 72.565 ;
     RECT  7.8 71.797 8.952 72.565 ;
     RECT  6.768 72.565 8.952 72.851 ;
     RECT  42.864 72.613 42.888 72.851 ;
     RECT  6.768 72.851 8.808 72.947 ;
     RECT  7.8 72.947 8.808 72.995 ;
     RECT  44.112 72.949 44.136 73.091 ;
     RECT  38.16 72.373 38.184 73.523 ;
     RECT  39.792 72.037 41.64 73.619 ;
     RECT  11.376 72.277 11.4 73.811 ;
     RECT  40.2 73.619 41.64 74.099 ;
     RECT  41.616 74.099 41.64 74.387 ;
     RECT  0.144 74.341 0.168 74.627 ;
     RECT  6.768 72.947 6.792 74.629 ;
     RECT  7.8 72.995 8.112 74.629 ;
     RECT  13.2 69.587 13.512 74.629 ;
     RECT  6.768 74.629 8.112 75.157 ;
     RECT  12.96 74.629 13.512 75.205 ;
     RECT  40.2 74.099 40.512 75.781 ;
     RECT  26.112 63.061 26.472 76.069 ;
     RECT  44.112 74.293 44.136 76.357 ;
     RECT  6.096 75.157 8.112 76.403 ;
     RECT  40.2 75.781 40.632 76.403 ;
     RECT  12.384 75.205 13.512 76.499 ;
     RECT  6.768 76.403 8.112 76.595 ;
     RECT  47.184 76.501 47.208 76.693 ;
     RECT  45.6 70.069 46.008 76.739 ;
     RECT  47.184 76.693 47.304 76.835 ;
     RECT  47.184 76.835 47.208 76.883 ;
     RECT  10.608 75.157 10.632 77.027 ;
     RECT  26.112 76.069 27.384 77.075 ;
     RECT  6.768 76.595 6.792 77.413 ;
     RECT  26.112 77.075 26.472 77.509 ;
     RECT  2.4 71.843 4.872 77.605 ;
     RECT  5.952 77.413 6.792 77.605 ;
     RECT  2.4 77.605 6.792 77.795 ;
     RECT  5.952 77.795 6.792 78.131 ;
     RECT  26.016 77.509 26.472 78.371 ;
     RECT  44.112 76.357 44.568 78.371 ;
     RECT  32.736 74.341 32.76 78.613 ;
     RECT  32.736 78.613 32.952 78.659 ;
     RECT  26.112 78.371 26.472 83.507 ;
     RECT  12.768 76.499 13.512 83.795 ;
     RECT  26.112 83.507 26.232 83.891 ;
     RECT  49.488 86.629 49.512 86.915 ;
     RECT  47.184 89.461 47.208 91.717 ;
     RECT  49.104 91.093 49.128 91.717 ;
     RECT  20.16 83.749 20.184 91.811 ;
     RECT  47.184 91.717 47.832 92.821 ;
     RECT  48.816 91.717 49.128 92.821 ;
     RECT  45.6 76.739 45.912 92.869 ;
     RECT  47.184 92.821 49.128 92.869 ;
     RECT  45.6 92.869 49.128 93.347 ;
     RECT  13.2 83.795 13.512 93.445 ;
     RECT  40.2 76.403 40.512 93.445 ;
     RECT  9.696 92.341 9.72 93.491 ;
     RECT  2.4 77.795 4.872 93.493 ;
     RECT  29.4 57.013 30.456 93.493 ;
     RECT  6.768 78.131 6.792 94.021 ;
     RECT  7.8 76.595 8.112 94.021 ;
     RECT  13.2 93.445 13.944 94.021 ;
     RECT  44.544 78.371 44.568 94.021 ;
     RECT  18.6 45.539 18.912 94.069 ;
     RECT  20.112 92.005 20.136 94.403 ;
     RECT  47.472 93.347 49.128 94.501 ;
     RECT  9.12 94.069 9.144 94.549 ;
     RECT  18.432 94.069 18.912 94.549 ;
     RECT  47.472 94.501 49.944 94.549 ;
     RECT  32.928 78.659 32.952 94.595 ;
     RECT  34.8 62.003 35.112 94.597 ;
     RECT  12.816 94.021 13.944 94.645 ;
     RECT  6.768 94.021 8.112 94.691 ;
     RECT  12.72 94.645 13.944 94.691 ;
     RECT  2.4 93.493 4.968 94.741 ;
     RECT  40.2 93.445 41.016 94.979 ;
     RECT  44.304 94.021 44.568 94.981 ;
     RECT  34.704 94.597 35.112 95.029 ;
     RECT  22.32 93.733 22.344 95.075 ;
     RECT  6.864 94.691 8.112 95.123 ;
     RECT  38.496 92.293 38.52 95.123 ;
     RECT  1.92 94.741 4.968 95.125 ;
     RECT  9.12 94.549 10.104 95.125 ;
     RECT  34.32 95.029 35.112 95.171 ;
     RECT  45.6 93.347 45.912 95.173 ;
     RECT  47.472 94.549 50.04 95.221 ;
     RECT  44.256 94.981 44.568 95.269 ;
     RECT  45.6 95.173 46.44 95.269 ;
     RECT  9.12 95.125 10.92 95.557 ;
     RECT  24 3.443 24.312 95.557 ;
     RECT  29.4 93.493 30.504 95.557 ;
     RECT  15.12 93.349 15.144 95.605 ;
     RECT  18.144 94.549 18.912 95.653 ;
     RECT  29.4 95.557 30.888 95.653 ;
     RECT  12.72 94.691 13.512 95.701 ;
     RECT  15.12 95.605 15.24 95.701 ;
     RECT  16.56 94.549 16.584 95.701 ;
     RECT  18.144 95.653 19.32 95.701 ;
     RECT  24 95.557 24.456 95.701 ;
     RECT  9.12 95.557 11.112 95.749 ;
     RECT  12.72 95.701 15.24 95.749 ;
     RECT  7.2 95.123 8.112 95.941 ;
     RECT  9.12 95.749 15.24 95.941 ;
     RECT  1.92 95.125 5.4 96.181 ;
     RECT  29.232 95.653 30.888 96.181 ;
     RECT  23.616 95.701 24.456 96.277 ;
     RECT  26.112 83.891 26.136 96.277 ;
     RECT  34.8 95.171 35.112 96.277 ;
     RECT  44.256 95.269 46.44 96.277 ;
     RECT  47.472 95.221 50.088 96.277 ;
     RECT  1.92 96.181 6.216 96.325 ;
     RECT  7.2 95.941 15.24 96.325 ;
     RECT  16.56 95.701 19.32 96.325 ;
     RECT  22.176 96.181 22.2 96.325 ;
     RECT  23.616 96.277 26.136 96.325 ;
     RECT  28.8 96.181 30.888 96.325 ;
     RECT  34.368 96.277 35.496 96.325 ;
     RECT  40.2 94.979 40.512 96.325 ;
     RECT  42 96.325 42.024 96.565 ;
     RECT  28.416 96.325 30.888 96.613 ;
     RECT  1.92 96.325 15.24 96.709 ;
     RECT  16.56 96.325 20.04 96.709 ;
     RECT  22.176 96.325 26.136 96.757 ;
     RECT  34.368 96.325 36.648 96.805 ;
     RECT  1.92 96.709 20.04 96.853 ;
     RECT  28.176 96.613 30.888 96.853 ;
     RECT  32.208 95.749 32.232 96.853 ;
     RECT  40.032 96.325 40.512 96.853 ;
     RECT  41.568 96.565 42.024 96.853 ;
     RECT  43.2 96.277 50.088 96.853 ;
     RECT  28.176 96.853 32.232 96.901 ;
     RECT  40.032 96.853 50.088 97.045 ;
     RECT  1.92 96.853 21.096 97.429 ;
     RECT  28.176 96.901 32.904 97.429 ;
     RECT  33.888 96.805 36.648 97.429 ;
     RECT  38.016 96.853 38.04 97.429 ;
     RECT  39.36 97.045 50.088 97.429 ;
     RECT  1.92 97.429 21.144 97.477 ;
     RECT  22.176 96.757 26.28 97.477 ;
     RECT  27.6 97.429 50.088 97.477 ;
     RECT  1.92 97.477 50.088 99.109 ;
     RECT  51.264 96.901 51.288 99.157 ;
     RECT  1.536 99.109 50.088 99.203 ;
     RECT  32.88 99.203 50.088 99.733 ;
     RECT  51.264 99.157 51.48 99.733 ;
     RECT  22.272 99.203 31.8 99.779 ;
     RECT  32.88 99.733 51.48 99.779 ;
     RECT  22.272 99.779 31.704 99.827 ;
     RECT  1.536 99.203 21.144 100.355 ;
     RECT  22.272 99.827 31.656 100.355 ;
     RECT  32.976 99.779 51.48 100.355 ;
     RECT  15.984 100.355 21.144 100.837 ;
     RECT  22.272 100.355 22.296 100.837 ;
     RECT  23.28 100.355 31.656 100.981 ;
     RECT  1.536 100.355 10.968 101.413 ;
     RECT  12.096 100.355 14.664 101.413 ;
     RECT  15.984 100.837 22.296 101.413 ;
     RECT  23.28 100.981 31.896 101.413 ;
     RECT  32.976 100.355 41.832 101.413 ;
     RECT  23.28 101.413 41.832 101.461 ;
     RECT  42.816 100.355 51.48 101.461 ;
     RECT  23.28 101.461 51.672 101.509 ;
     RECT  1.536 101.413 22.296 101.989 ;
     RECT  23.28 101.509 51.864 101.989 ;
     RECT  1.536 101.989 51.864 103.632 ;
     RECT  2.856 1.763 5.328 1.859 ;
     RECT  11.976 1.763 13.104 2.291 ;
     RECT  19.944 1.763 21.312 2.291 ;
     RECT  25.8 1.763 27.312 1.859 ;
     RECT  16.872 1.811 18.384 2.291 ;
     RECT  33 1.811 34.128 1.859 ;
     RECT  35.112 1.811 36.288 2.821 ;
     RECT  2.856 1.859 4.008 2.821 ;
     RECT  11.784 2.291 13.104 3.443 ;
     RECT  18.288 2.291 18.384 3.349 ;
     RECT  19.944 2.291 21.504 2.821 ;
     RECT  36.792 2.291 37.824 16.595 ;
     RECT  20.472 2.821 21.504 3.397 ;
     RECT  35.304 2.821 36.288 4.019 ;
     RECT  4.824 3.397 6.144 3.443 ;
     RECT  20.52 3.397 21.504 4.019 ;
     RECT  11.784 3.443 13.2 4.019 ;
     RECT  24.312 3.443 25.392 4.019 ;
     RECT  6.6 4.019 7.68 4.595 ;
     RECT  19.128 4.019 20.256 45.539 ;
     RECT  35.304 4.019 36.768 62.003 ;
     RECT  1.272 4.595 2.304 5.171 ;
     RECT  6.6 4.595 7.8 25.093 ;
     RECT  36.792 16.595 38.064 32.531 ;
     RECT  6.696 25.093 7.8 29.077 ;
     RECT  5.16 28.021 6.672 28.309 ;
     RECT  5.208 28.309 6.672 29.029 ;
     RECT  5.208 29.029 6.576 30.803 ;
     RECT  6.744 29.077 7.8 30.709 ;
     RECT  8.112 30.709 9.312 30.853 ;
     RECT  9.336 30.755 10.464 31.427 ;
     RECT  4.872 30.803 6.576 31.093 ;
     RECT  41.928 30.851 42.912 35.939 ;
     RECT  11.4 30.853 12.528 31.907 ;
     RECT  8.112 30.995 9.312 31.427 ;
     RECT  4.872 31.093 6.336 31.285 ;
     RECT  4.872 31.285 6.288 32.053 ;
     RECT  39.144 31.955 40.2 32.003 ;
     RECT  38.808 32.003 40.2 32.051 ;
     RECT  5.112 32.053 6.288 32.771 ;
     RECT  4.872 32.771 6.288 33.539 ;
     RECT  6.792 33.203 7.8 35.317 ;
     RECT  4.872 33.539 5.16 35.029 ;
     RECT  44.28 33.683 45.456 34.259 ;
     RECT  41.544 35.939 42.912 37.091 ;
     RECT  45.912 35.939 47.28 35.987 ;
     RECT  41.448 37.091 42.912 37.139 ;
     RECT  10.752 42.803 10.776 43.237 ;
     RECT  10.752 43.237 10.8 44.053 ;
     RECT  4.872 44.965 6.288 53.267 ;
     RECT  6.792 45.251 7.8 46.837 ;
     RECT  18.912 45.539 20.256 47.411 ;
     RECT  0.144 46.163 0.168 47.317 ;
     RECT  13.752 46.645 15.072 46.741 ;
     RECT  13.944 46.741 15.072 46.883 ;
     RECT  13.752 46.883 15.072 48.229 ;
     RECT  6.792 46.979 7.8 54.133 ;
     RECT  0.144 47.699 0.168 48.709 ;
     RECT  13.944 48.229 15.072 63.059 ;
     RECT  0.168 48.709 1.248 48.995 ;
     RECT  1.272 48.709 2.4 49.043 ;
     RECT  0.144 48.995 1.248 49.043 ;
     RECT  0.144 49.043 0.168 50.389 ;
     RECT  8.112 51.781 9.552 52.115 ;
     RECT  4.872 53.267 6.768 54.661 ;
     RECT  4.872 54.661 6.288 55.331 ;
     RECT  6.792 56.483 7.8 59.605 ;
     RECT  12.216 57.539 13.2 59.797 ;
     RECT  0.144 59.219 0.168 60.565 ;
     RECT  12.192 59.843 12.384 60.949 ;
     RECT  6.792 60.179 7.8 62.677 ;
     RECT  11.4 60.949 12.384 61.091 ;
     RECT  11.376 61.091 12.384 61.525 ;
     RECT  11.376 61.525 12.24 62.533 ;
     RECT  9.72 62.533 10.8 62.723 ;
     RECT  10.824 62.533 12.24 62.723 ;
     RECT  5.208 62.581 6.624 62.627 ;
     RECT  5.208 62.627 6.72 63.779 ;
     RECT  6.792 63.779 7.8 69.493 ;
     RECT  10.872 64.261 12.24 64.307 ;
     RECT  5.208 66.133 6.384 66.373 ;
     RECT  5.208 66.373 6.192 68.099 ;
     RECT  8.112 66.709 9.168 66.899 ;
     RECT  42.24 67.283 42.264 67.477 ;
     RECT  42.24 67.477 42.72 68.341 ;
     RECT  4.872 68.099 6.192 69.587 ;
     RECT  39.648 68.675 39.792 70.117 ;
     RECT  0.144 68.963 0.168 70.309 ;
     RECT  4.872 69.587 6.768 70.405 ;
     RECT  6.792 70.163 7.8 72.565 ;
     RECT  5.736 70.405 6.768 71.843 ;
     RECT  40.512 70.739 42.144 71.893 ;
     RECT  40.512 71.893 41.616 72.037 ;
     RECT  41.64 71.939 42.168 72.613 ;
     RECT  41.64 72.613 42.864 72.851 ;
     RECT  6.792 72.947 7.8 74.629 ;
     RECT  44.136 72.949 45.6 73.091 ;
     RECT  44.112 73.091 45.6 74.293 ;
     RECT  40.512 74.099 41.616 74.387 ;
     RECT  44.136 74.293 45.6 76.357 ;
     RECT  40.512 74.387 40.632 75.781 ;
     RECT  4.872 75.157 6.096 76.403 ;
     RECT  44.568 76.357 45.6 95.269 ;
     RECT  4.872 76.403 6.768 77.413 ;
     RECT  46.008 76.501 47.184 76.739 ;
     RECT  6.792 76.595 7.8 94.021 ;
     RECT  45.912 76.739 47.184 76.883 ;
     RECT  4.872 77.413 5.952 77.605 ;
     RECT  4.872 77.795 5.952 78.131 ;
     RECT  18.912 83.749 20.16 91.811 ;
     RECT  45.912 89.461 47.184 92.869 ;
     RECT  47.832 91.717 48.816 92.821 ;
     RECT  18.912 91.811 20.136 92.005 ;
     RECT  18.912 92.005 20.112 94.403 ;
     RECT  13.944 93.445 15.12 94.691 ;
     RECT  9.696 93.491 9.72 94.069 ;
     RECT  8.112 94.069 9.12 95.941 ;
     RECT  9.144 94.069 9.72 94.549 ;
     RECT  18.912 94.403 19.32 95.653 ;
     RECT  15.144 94.549 16.56 95.605 ;
     RECT  6.768 94.691 6.864 95.123 ;
     RECT  13.512 94.691 15.12 95.701 ;
     RECT  40.512 94.979 41.016 96.325 ;
     RECT  22.32 95.075 22.344 95.701 ;
     RECT  6.768 95.123 7.2 95.125 ;
     RECT  5.4 95.125 7.2 96.181 ;
     RECT  34.368 95.171 34.8 96.277 ;
     RECT  46.44 95.173 47.472 96.277 ;
     RECT  15.24 95.605 16.56 96.709 ;
     RECT  22.32 95.701 23.616 96.181 ;
     RECT  30.888 95.749 32.208 96.853 ;
     RECT  6.216 96.181 7.2 96.325 ;
     RECT  22.2 96.181 23.616 96.325 ;
     RECT  40.512 96.325 42 96.565 ;
     RECT  42.024 96.325 43.2 96.853 ;
     RECT  40.512 96.565 41.568 96.853 ;
     RECT  21.096 96.853 22.176 97.429 ;
     RECT  36.648 96.853 38.016 97.429 ;
     RECT  32.904 96.901 33.888 97.429 ;
     RECT  50.088 96.901 51.264 99.733 ;
     RECT  38.04 97.045 39.36 97.429 ;
     RECT  21.144 97.429 22.176 97.477 ;
     RECT  26.28 97.429 27.6 97.477 ;
     RECT  21.144 99.203 22.272 100.837 ;
     RECT  31.8 99.203 32.88 99.779 ;
     RECT  31.704 99.779 32.976 99.827 ;
     RECT  31.656 99.827 32.976 100.981 ;
     RECT  10.968 100.355 12.096 101.413 ;
     RECT  14.664 100.355 15.984 101.413 ;
     RECT  22.296 100.355 23.28 101.989 ;
     RECT  41.832 100.355 42.816 101.461 ;
     RECT  31.896 100.981 32.976 101.413 ;
  END
END qfd_xcst_n
END LIBRARY
